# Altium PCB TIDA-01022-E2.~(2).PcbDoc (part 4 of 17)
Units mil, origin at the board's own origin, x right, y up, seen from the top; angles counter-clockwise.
Board outline 6929.13 x 11614.17 mil, 12 copper layers (L1_Top Layer, L2_GND, L3_GND, L4_Signal Layer 1, L5_GND, L6_PWR, L7_GND/PWR, L8_PWR, L9_GND/PWR, L10_Signal Layer 2, L11_GND, L12_Bottom Layer), stack 64.6 mil thick; 1711 components, 1001 nets, 5985 pads, 3200 vias.

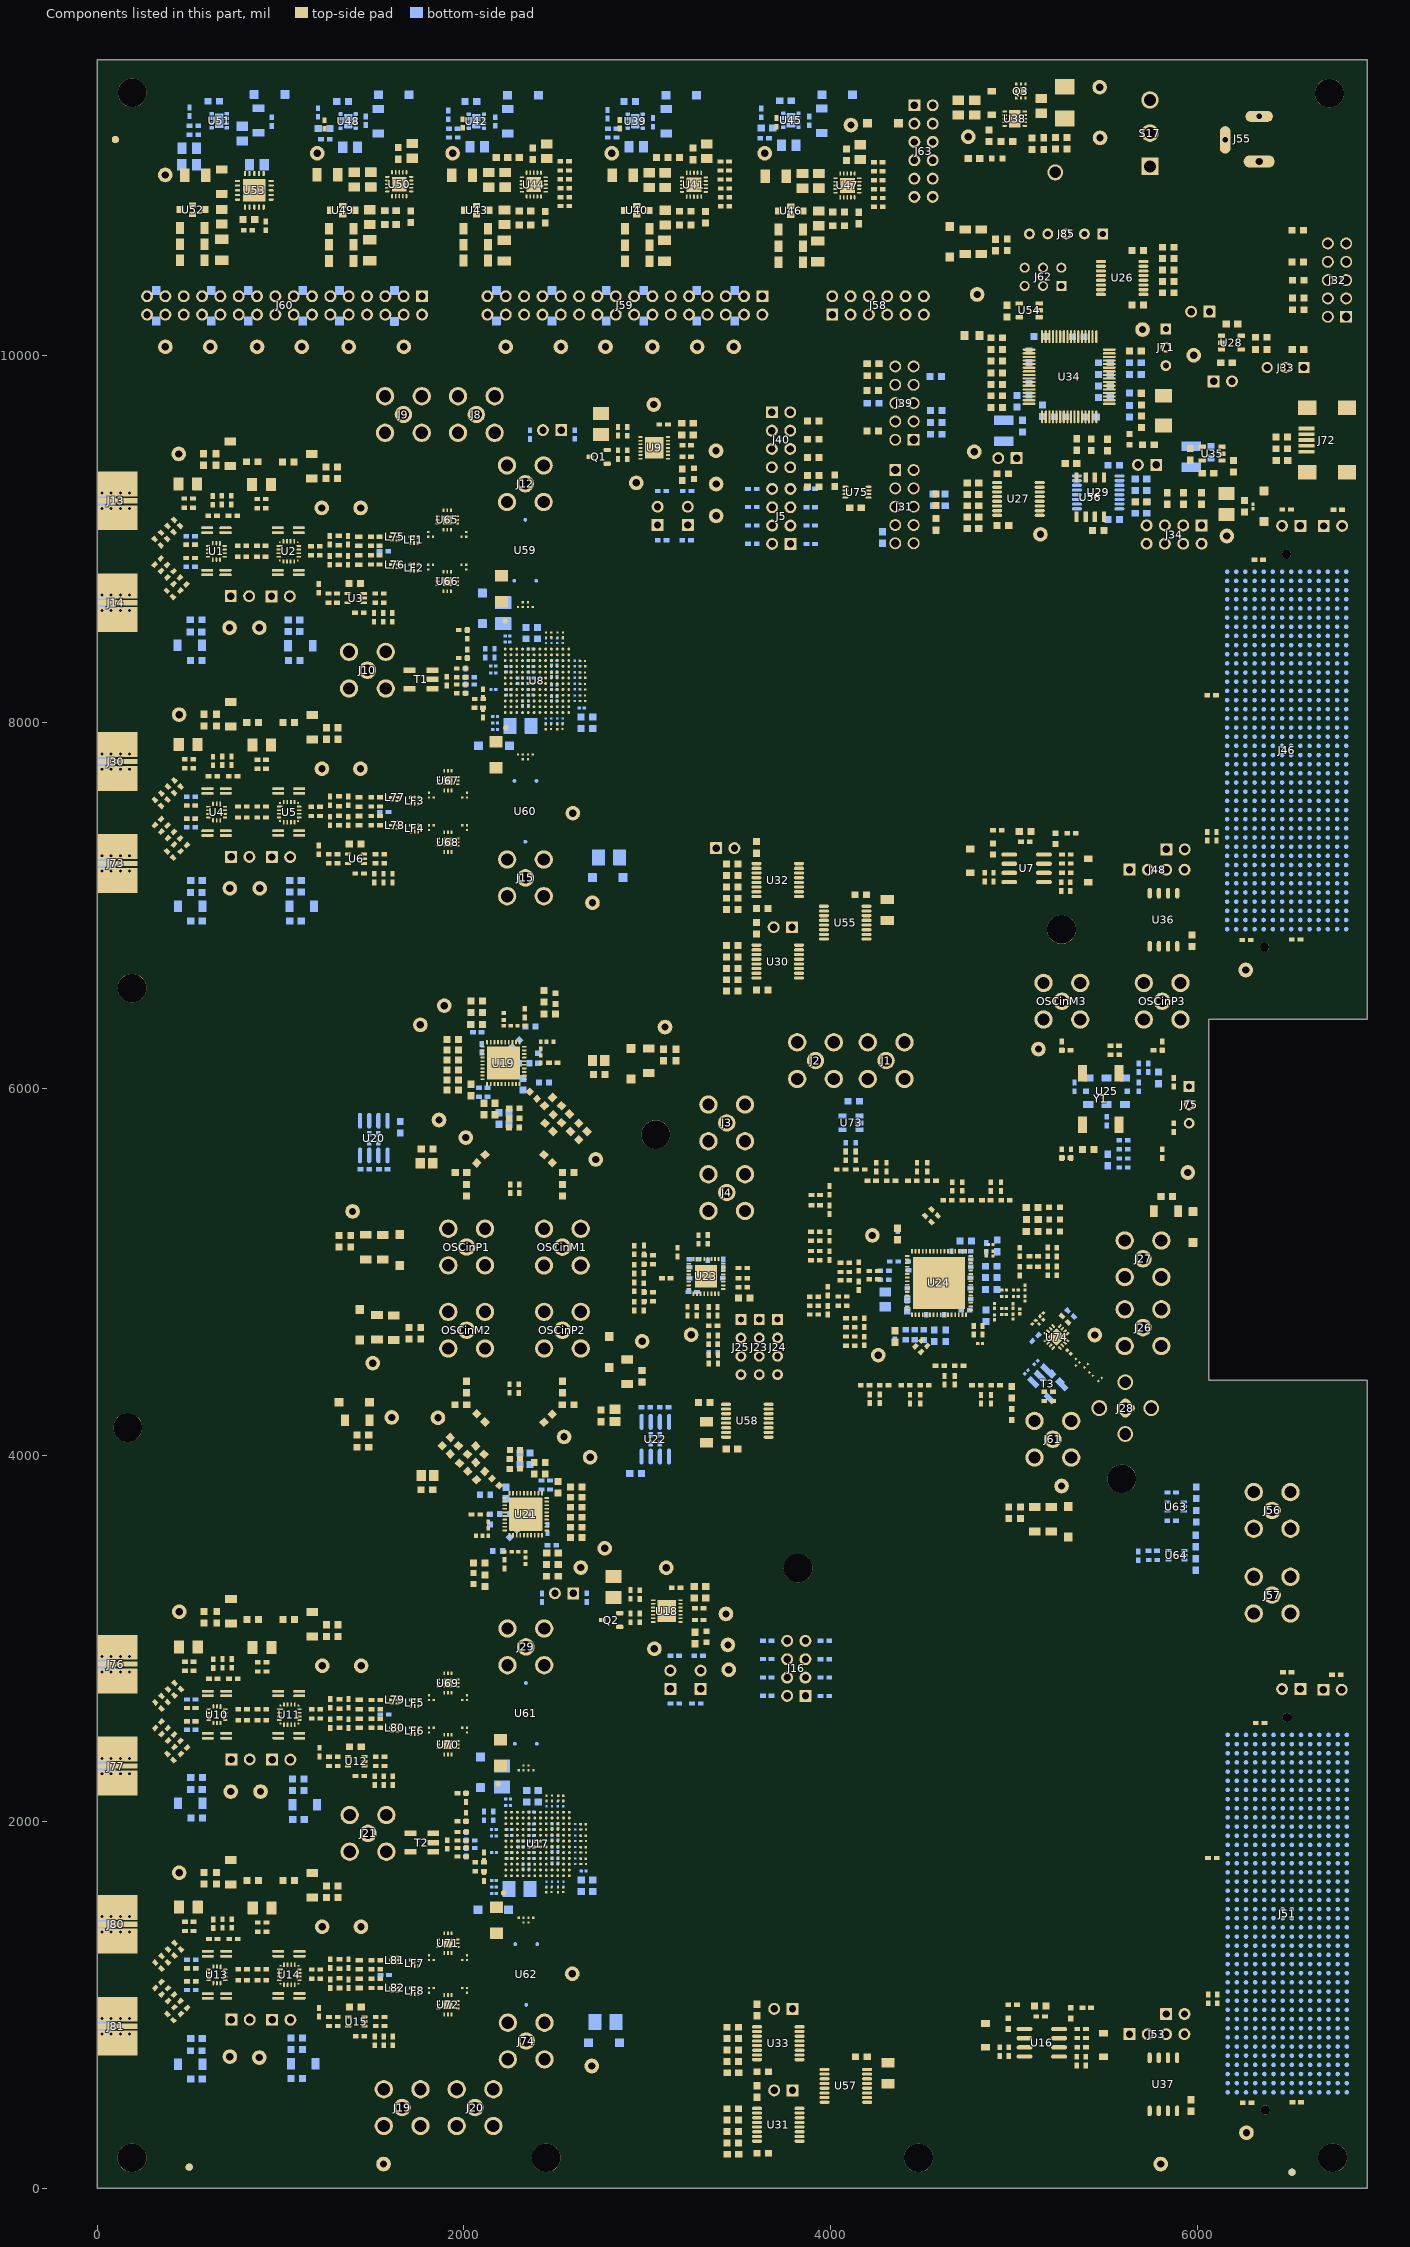
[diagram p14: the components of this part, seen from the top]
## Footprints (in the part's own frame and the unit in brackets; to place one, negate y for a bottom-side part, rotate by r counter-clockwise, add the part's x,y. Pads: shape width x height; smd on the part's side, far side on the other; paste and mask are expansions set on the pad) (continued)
ASP-184330-01#2 [mil]
  round 25 smd paste+5 mask+2: A1(975,225) A2(925,225) A3(875,225) A4(825,225) A5(775,225) A6(725,225) A7(675,225) A8(625,225) A9(575,225) A10(525,225) A11(475,225) A12(425,225) A13(375,225) A14(325,225) A15(275,225) A16(225,225) A17(175,225) A18(125,225) A19(75,225) A20(25,225) A21(-25,225) A22(-75,225) A23(-125,225) A24(-175,225) A25(-225,225) A26(-275,225) A27(-325,225) A28(-375,225) A29(-425,225) A30(-475,225) A31(-525,225) A32(-575,225) A33(-625,225) A34(-675,225) A35(-725,225) A36(-775,225) A37(-825,225) A38(-875,225) A39(-925,225) A40(-975,225) B1(975,175) B2(925,175) B3(875,175) B4(825,175) B5(775,175) B6(725,175) B7(675,175) B8(625,175) B9(575,175) B10(525,175) B11(475,175) B12(425,175) B13(375,175) B14(325,175) B15(275,175) B16(225,175) B17(175,175) B18(125,175) B19(75,175) B20(25,175) B21(-25,175) B22(-75,175) B23(-125,175) B24(-175,175) B25(-225,175) B26(-275,175) B27(-325,175) B28(-375,175) B29(-425,175) B30(-475,175) B31(-525,175) B32(-575,175) B33(-625,175) B34(-675,175) B35(-725,175) B36(-775,175) B37(-825,175) B38(-875,175) B39(-925,175) B40(-975,175) C1(975,125) C2(925,125) C3(875,125) C4(825,125) C5(775,125) C6(725,125) C7(675,125) C8(625,125) C9(575,125) C10(525,125) C11(475,125) C12(425,125) C13(375,125) C14(325,125) C15(275,125) C16(225,125) C17(175,125) C18(125,125) C19(75,125) C20(25,125) C21(-25,125) C22(-75,125) C23(-125,125) C24(-175,125) C25(-225,125) C26(-275,125) C27(-325,125) C28(-375,125) C29(-425,125) C30(-475,125) C31(-525,125) C32(-575,125) C33(-625,125) C34(-675,125) C35(-725,125) C36(-775,125) C37(-825,125) C38(-875,125) C39(-925,125) C40(-975,125) D1(975,75) D2(925,75) D3(875,75) D4(825,75) D5(775,75) D6(725,75) D7(675,75) D8(625,75) D9(575,75) D10(525,75) D11(475,75) D12(425,75) D13(375,75) D14(325,75) D15(275,75) D16(225,75) D17(175,75) D18(125,75) D19(75,75) D20(25,75) D21(-25,75) D22(-75,75) D23(-125,75) D24(-175,75) D25(-225,75) D26(-275,75) D27(-325,75) D28(-375,75) D29(-425,75) D30(-475,75) D31(-525,75) D32(-575,75) D33(-625,75) D34(-675,75) D35(-725,75) D36(-775,75) D37(-825,75) D38(-875,75) D39(-925,75) D40(-975,75) E1(975,25) E2(925,25) E3(875,25) E4(825,25) E5(775,25) E6(725,25) E7(675,25) E8(625,25) E9(575,25) E10(525,25) E11(475,25) E12(425,25) E13(375,25) E14(325,25) E15(275,25) E16(225,25) E17(175,25) E18(125,25) E19(75,25) E20(25,25) E21(-25,25) E22(-75,25) E23(-125,25) E24(-175,25) E25(-225,25) E26(-275,25) E27(-325,25) E28(-375,25) E29(-425,25) E30(-475,25) E31(-525,25) E32(-575,25) E33(-625,25) E34(-675,25) E35(-725,25) E36(-775,25) E37(-825,25) E38(-875,25) E39(-925,25) E40(-975,25) F1(975,-25) F2(925,-25) F3(875,-25) F4(825,-25) F5(775,-25) F6(725,-25) F7(675,-25) F8(625,-25) F9(575,-25) F10(525,-25) F11(475,-25) F12(425,-25) F13(375,-25) F14(325,-25) F15(275,-25) F16(225,-25) F17(175,-25) F18(125,-25) F19(75,-25) F20(25,-25) F21(-25,-25) F22(-75,-25) F23(-125,-25) F24(-175,-25) F25(-225,-25) F26(-275,-25) F27(-325,-25) F28(-375,-25) F29(-425,-25) F30(-475,-25) F31(-525,-25) F32(-575,-25) F33(-625,-25) F34(-675,-25) F35(-725,-25) F36(-775,-25) F37(-825,-25) F38(-875,-25) F39(-925,-25) F40(-975,-25) G1(975,-75) G2(925,-75) G3(875,-75) G4(825,-75) G5(775,-75) G6(725,-75) G7(675,-75) G8(625,-75) G9(575,-75) G10(525,-75) G11(475,-75) G12(425,-75) G13(375,-75) G14(325,-75) G15(275,-75) G16(225,-75) G17(175,-75) G18(125,-75) G19(75,-75) G20(25,-75) G21(-25,-75) G22(-75,-75) G23(-125,-75) G24(-175,-75) G25(-225,-75) G26(-275,-75) G27(-325,-75) G28(-375,-75) G29(-425,-75) G30(-475,-75) G31(-525,-75) G32(-575,-75) G33(-625,-75) G34(-675,-75) G35(-725,-75) G36(-775,-75) G37(-825,-75) G38(-875,-75) G39(-925,-75) G40(-975,-75) H1(975,-125) H2(925,-125) H3(875,-125) H4(825,-125) H5(775,-125) H6(725,-125) H7(675,-125) H8(625,-125) H9(575,-125) H10(525,-125) H11(475,-125) H12(425,-125) H13(375,-125) H14(325,-125) H15(275,-125) H16(225,-125) H17(175,-125) H18(125,-125) H19(75,-125) H20(25,-125) H21(-25,-125) H22(-75,-125) H23(-125,-125) H24(-175,-125) H25(-225,-125) H26(-275,-125) H27(-325,-125) H28(-375,-125) H29(-425,-125) H30(-475,-125) H31(-525,-125) H32(-575,-125) H33(-625,-125) H34(-675,-125) H35(-725,-125) H36(-775,-125) H37(-825,-125) H38(-875,-125) H39(-925,-125) H40(-975,-125) J1(975,-175) J2(925,-175) J3(875,-175) J4(825,-175) J5(775,-175) J6(725,-175) J7(675,-175) J8(625,-175) J9(575,-175) J10(525,-175) J11(475,-175) J12(425,-175) J13(375,-175) J14(325,-175) J15(275,-175) J16(225,-175) J17(175,-175) J18(125,-175) J19(75,-175) J20(25,-175) J21(-25,-175) J22(-75,-175) J23(-125,-175) J24(-175,-175) J25(-225,-175) J26(-275,-175) J27(-325,-175) J28(-375,-175) J29(-425,-175) J30(-475,-175) J31(-525,-175) J32(-575,-175) J33(-625,-175) J34(-675,-175) J35(-725,-175) J36(-775,-175) J37(-825,-175) J38(-875,-175) J39(-925,-175) J40(-975,-175) K1(975,-225) K2(925,-225) K3(875,-225) K4(825,-225) K5(775,-225) K6(725,-225) K7(675,-225) K8(625,-225) K9(575,-225) K10(525,-225) K11(475,-225) K12(425,-225) K13(375,-225) K14(325,-225) K15(275,-225) K16(225,-225) K17(175,-225) K18(125,-225) K19(75,-225) K20(25,-225) K21(-25,-225) K22(-75,-225) K23(-125,-225) K24(-175,-225) K25(-225,-225) K26(-275,-225) K27(-325,-225) K28(-375,-225) K29(-425,-225) K30(-475,-225) K31(-525,-225) K32(-575,-225) K33(-625,-225) K34(-675,-225) K35(-725,-225) K36(-775,-225) K37(-825,-225) K38(-875,-225) K39(-925,-225) K40(-975,-225) L1(975,-275) L2(925,-275) L3(875,-275) L4(825,-275) L5(775,-275) L6(725,-275) L7(675,-275) L8(625,-275) L9(575,-275) L10(525,-275) L11(475,-275) L12(425,-275) L13(375,-275) L14(325,-275) L15(275,-275) L16(225,-275) L17(175,-275) L18(125,-275) L19(75,-275) L20(25,-275) L21(-25,-275) L22(-75,-275) L23(-125,-275) L24(-175,-275) L25(-225,-275) L26(-275,-275) L27(-325,-275) L28(-375,-275) L29(-425,-275) L30(-475,-275) L31(-525,-275) L32(-575,-275) L33(-625,-275) L34(-675,-275) L35(-725,-275) L36(-775,-275) L37(-825,-275) L38(-875,-275) L39(-925,-275) L40(-975,-275) M1(975,-325) M2(925,-325) M3(875,-325) M4(825,-325) M5(775,-325) M6(725,-325) M7(675,-325) M8(625,-325) M9(575,-325) M10(525,-325) M11(475,-325) M12(425,-325) M13(375,-325) M14(325,-325) M15(275,-325) M16(225,-325) M17(175,-325) M18(125,-325) M19(75,-325) M20(25,-325) M21(-25,-325) M22(-75,-325) M23(-125,-325) M24(-175,-325) M25(-225,-325) M26(-275,-325) M27(-325,-325) M28(-375,-325) M29(-425,-325) M30(-475,-325) M31(-525,-325) M32(-575,-325) M33(-625,-325) M34(-675,-325) M35(-725,-325) M36(-775,-325) M37(-825,-325) M38(-875,-325) M39(-925,-325) M40(-975,-325) Y1(975,325) Y2(925,325) Y3(875,325) Y4(825,325) Y5(775,325) Y6(725,325) Y7(675,325) Y8(625,325) Y9(575,325) Y10(525,325) Y11(475,325) Y12(425,325) Y13(375,325) Y14(325,325) Y15(275,325) Y16(225,325) Y17(175,325) Y18(125,325) Y19(75,325) Y20(25,325) Y21(-25,325) Y22(-75,325) Y23(-125,325) Y24(-175,325) Y25(-225,325) Y26(-275,325) Y27(-325,325) Y28(-375,325) Y29(-425,325) Y30(-475,325) Y31(-525,325) Y32(-575,325) Y33(-625,325) Y34(-675,325) Y35(-725,325) Y36(-775,325) Y37(-825,325) Y38(-875,325) Y39(-925,325) Y40(-975,325) Z1(975,275) Z2(925,275) Z3(875,275) Z4(825,275) Z5(775,275) Z6(725,275) Z7(675,275) Z8(625,275) Z9(575,275) Z10(525,275) Z11(475,275) Z12(425,275) Z13(375,275) Z14(325,275) Z15(275,275) Z16(225,275) Z17(175,275) Z18(125,275) Z19(75,275) Z20(25,275) Z21(-25,275) Z22(-75,275) Z23(-125,275) Z24(-175,275) Z25(-225,275) Z26(-275,275) Z27(-325,275) Z28(-375,275) Z29(-425,275) Z30(-475,275) Z31(-525,275) Z32(-575,275) Z33(-625,275) Z34(-675,275) Z35(-725,275) Z36(-775,275) Z37(-825,275) Z38(-875,275) Z39(-925,275) Z40(-975,275)
  round 50 hole 50 unplated paste+0 mask+10: MH1(1070.5,0)
  round 50 hole 50 unplated mask+10: MH2(-1070.5,-120)
  silkscreen extent -1118,-409 1153,409
AssemblyNote [mil] "Assembly Note"
AssemblyNoteLabel [mil] "Assembly Note for PCB Labels"
CONN_PEC06DAAN [mm] "SULLINS"
  rect 1.65x1.65 hole 1.016 mask+0: 1(-6.35,-1.27)
  round 1.65 hole 1.016 mask+0: 2(-6.35,1.27) 3(-3.81,-1.27) 4(-3.81,1.27) 5(-1.27,-1.27) 6(-1.27,1.27) 7(1.27,-1.27) 8(1.27,1.27) 9(3.81,-1.27) 10(3.81,1.27) 11(6.35,-1.27) 12(6.35,1.27)
  silkscreen extent -8.72,-2.6 7.62,2.54, body extent -7.62,-2.54 7.62,2.54, height 8.38
CONN_RAPC722X [mm] "Conn_DC Jack"
  oval 1.7x4.3 hole 1.01 slot 3.56 at 90 deg mask+0.254: 1(-13.741,0)
  oval 1.5x3.8 hole 0.76 slot 3.05 at 90 deg mask+0.254: 2(-7.493,0)
  oval 3.8x1.5 hole 0.76 slot 3.05 at 0 deg mask+0.254: 3(-10.744,4.7)
  silkscreen extent -14.48,-4.57 0.25,4.57, body extent -14.5,-4.57 0.23,4.83, height 11.18
DBV0005A_N [mm] "SOT23, 5-Leads, Body 2.9x1.6mm, Pitch 0.95mm, Lead Span 2.8mm, IPC Medium Density"
  rrect17% 1x0.6 smd: 1(-1.375,0.95) 2(-1.375,0) 3(-1.375,-0.95) 4(1.375,-0.95) 5(1.375,0.95)
  silkscreen extent -1.62,-1.55 0.38,1.55, body extent -1.42,-1.46 1.42,1.46, height 1.09
DCK0005A_N#1 [mm] "SOT353, 5-Leads, Body 2x1.3mm, Pitch 0.65mm, Lead Span 2.1mm, IPC Medium Density"
  rrect25% 0.85x0.4 smd: 1(10.178,0.65) 2(10.178,0) 3(10.178,-0.65) 4(12.428,-0.65) 5(12.428,0.65)
  silkscreen extent 9.83,-1.02 11.85,1.1, body extent 10.16,-1 12.44,1, height 0.95
DCK0005A_N#2 [mm] "SOT353, 5-Leads, Body 2x1.3mm, Pitch 0.65mm, Lead Span 2.1mm, IPC Medium Density"
  rrect25% 0.85x0.4 smd: 1(-1.125,0.65) 2(-1.125,0) 3(-1.125,-0.65) 4(1.125,-0.65) 5(1.125,0.65)
  silkscreen extent -1.48,-1.02 0.55,1.1, body extent -1.14,-1 1.14,1, height 0.95
DCU0008A_N [mm] "TSSOP, 8-Leads, Body 2x2.3mm, Pitch 0.5mm, IPC Medium Density"
  oval 0.8x0.3 smd: 1(-1.6,0.75) 2(-1.6,0.25) 3(-1.6,-0.25) 4(-1.6,-0.75) 5(1.6,-0.75) 6(1.6,-0.25) 7(1.6,0.25) 8(1.6,0.75)
  silkscreen extent -1.05,-1.05 0.38,1.05, body extent -1.56,-1 1.56,1, height 0.9
DQ1225 [mm] "SMD, 12-Leads, Body 3x3mm"
  rect 0.51x0.25 smd: 1(-1.36,0.51) 2(-1.36,0) 3(-1.36,-0.51) 7(1.36,-0.51) 8(1.36,0) 9(1.36,0.51)
  rect 0.25x0.51 smd: 4(-0.51,-1.36) 5(0,-1.36) 6(0.51,-1.36) 10(0.51,1.36) 11(0,1.36) 12(-0.51,1.36)
  rect 1.24x1.24 smd: 13(0,0)
  silkscreen extent -1.8,-1.6 1.6,1.6, body extent -1.5,-1.5 1.5,1.5, height 0.89
DQK0006C [mm] "WSON"
  rrect12% 0.9x0.86 on Top Paste: 0(0,0.325)
  rrect34% 0.7x0.29 on Top Paste: 0(0.095,-0.65)
  rrect33% 0.45x0.3 smd: 1(-0.975,0.65) 2(-0.975,0) 3(-0.975,-0.65) 4(0.975,-0.65) 5(0.975,0) 6(0.975,0.65)
  rrect33% 0.75x0.3 smd paste-0.15: 7(0.095,-0.65)
  rrect11% 1x0.95 smd paste-0.5: 8(0,0.325)
  silkscreen extent -1.15,-1.15 1.15,1.15, body extent -1,-1 1,1, height 0.82
DRC0010J [mm] "SON, 10-Leads, Body 3x3mm, Pitch 0.5mm, Thermal Pad 2.4x1.65mm, TI Recommended"
  rrect40% 0.6x0.25 smd: 1(-1.4,1) 2(-1.4,0.5) 3(-1.4,0) 4(-1.4,-0.5) 5(-1.4,-1) 6(1.4,-1) 7(1.4,-0.5) 8(1.4,0) 9(1.4,0.5) 10(1.4,1)
  rrect40% 0.25x0.34 on Top Paste: 11(-0.25,1.53) 11(-0.25,-1.53) 11(0.25,1.53) 11(0.25,-1.53)
  rrect9% 1.5x1.06 on Top Paste: 11(0,0.63) 11(0,-0.63)
  rrect12% 1.65x2.4 smd paste-1 mask-2: 11(0,0)
  L1_Top Layer region: -0.775,-1.2 -0.375,-1.2 -0.375,-1.65 -0.371,-1.669 -0.36,-1.685 -0.344,-1.696 -0.325,-1.7 -0.325,-1.7 -0.325,-1.7 -0.175,-1.7 -0.175,-1.7 -0.156,-1.696 -0.14,-1.685 -0.129,-1.669 -0.125,-1.65 -0.125,-1.65 -0.125,-1.65 -0.125,-1.2 0.125,-1.2 0.125,-1.65 0.129,-1.669 0.14,-1.685 0.156,-1.696 0.175,-1.7 0.175,-1.7 0.175,-1.7 0.325,-1.7 0.325,-1.7 0.344,-1.696 0.36,-1.685 0.371,-1.669 0.375,-1.65 0.375,-1.65 0.375,-1.2 0.775,-1.2 0.794,-1.196 0.81,-1.185 0.821,-1.169 0.825,-1.15 0.825,-1.15 0.825,1.15 0.821,1.169 0.81,1.185 0.794,1.196 0.775,1.2 0.775,1.2 0.375,1.2 0.375,1.65 0.371,1.669 0.36,1.685 0.344,1.696 0.325,1.7 0.325,1.7 0.175,1.7 0.156,1.696 0.14,1.685 0.129,1.669 0.125,1.65 0.125,1.65 0.125,1.2 -0.125,1.2 -0.125,1.65 -0.125,1.65 -0.129,1.669 -0.14,1.685 -0.156,1.696 -0.175,1.7 -0.175,1.7 -0.325,1.7 -0.344,1.696 -0.36,1.685 -0.371,1.669 -0.375,1.65 -0.375,1.65 -0.375,1.2 -0.775,1.2 -0.794,1.196 -0.81,1.185 -0.821,1.169 -0.825,1.15 -0.825,1.15 -0.825,-1.15 -0.821,-1.169 -0.81,-1.185 -0.794,-1.196 -0.775,-1.2
  silkscreen extent -1.63,-1.63 1.63,1.63, body extent -1.5,-1.5 1.5,1.5, height 0.77
ESD_Overlay_Large [mil]
  silkscreen extent -254,-219 250,219
EURoHS_Exempt_60mil [mil] "EU RoHS Exempt symbol"
FCC_disclaimer [mil]
Fiducial10-20 [mm]
  round 1 smd mask+0.5: 1(0,0)
  L1_Top Layer keep-out circle w1.178: c0,0 r0.5
FIL_LFL18_TC1 [mm] "SMD, 6-Leads, Body 1.6x0.8mm"
  rrect40% 0.25x0.55 smd: 1(-0.5,0.425) 2(0,0.425) 3(0.5,0.425) 4(0.5,-0.425) 5(0,-0.425) 6(-0.5,-0.425)
  silkscreen extent -1.1,-1 1.1,1, body extent -0.85,-0.45 0.85,0.45, height 0.7
IEC_Caution_Medium [mil]
  silkscreen extent -217,-182 217,193
IND_LQG15H [mm] "MuRata"
  rect 0.55x0.6 smd: 1(-0.475,0) 2(0.475,0)
  silkscreen extent -1.3,-0.3 -0.95,0.3, body extent -0.52,-0.27 0.52,0.27, height 0.55
Johnson_142-0701-20x [mil] "Johnson Components recommended land pattern"
  round 95 hole 62: 1(0,0)
  round 100 hole 67: 2(100,100) 3(100,-100) 4(-100,-100) 5(-100,100)
  silkscreen extent -160,-160 160,160, body extent -156,-156 156,156, height 375
JOHNSON_142-0701-20X [mil] "Johnson Components recommended land pattern"
  round 95 hole 62: 1(0,0)
  round 100 hole 67: 2(100,100) 3(100,-100) 4(-100,-100) 5(-100,100)
  silkscreen extent -160,-160 160,160, body extent -156,-156 156,156, height 375
JOHNSON_142-0771-831 [mil]
  rect 28.5x218 smd: 1(0,-109)
  rect 135.75x218 smd: 2(-92.12,-109) 3(92.13,-109)
  rect 270x97.5 smd far side: 4(0,-48.75)
  round 16 hole 16: ""(-42,-25) ""(-42,-125) ""(-42,-75) ""(-42,-175) ""(42,-25) ""(42,-125) ""(42,-75) ""(42,-175)
  body extent -124,-179 123,375, height 131
Keystone5000 [mil] "For Keystone 500x miniature loop terminals"
  round 80 hole 40: 1(0,0)
  silkscreen extent -52,-52 52,52, body extent -49,-49 49,49, height 182
Keystone5001 [mil] "For Keystone 500x miniature loop terminals"
  round 80 hole 40: 1(0,0)
  silkscreen extent -52,-52 52,52, body extent -49,-49 49,49, height 182
Keystone5002 [mil] "For Keystone 500x miniature loop terminals"
  round 80 hole 40: 1(0,0)
  silkscreen extent -52,-52 52,52, body extent -49,-49 49,49, height 182
Keystone5012 [mil] "Keystone Multipurpose loops"
  round 87 hole 63: 1(0,0)
  silkscreen extent -70,-70 70,70, body extent -63,-63 63,62, height 319
Label_650x200 [mil] "Thermal Transfer Label"
  round 1 on Mech13: 0(0,0)
  silkscreen extent -325,-100 325,100, body extent -325,-100 325,100, height 1
LED_LTST-C190 [mm] "Lite-On"
  rect 0.8x0.8 smd: 1(-0.75,0) 2(0.75,0)
  silkscreen extent -1.1,-0.8 1.8,0.8, body extent -0.85,-0.45 0.85,0.45, height 0.9
LQFP64_N [mm] "Thin QFP, 64-Leads, Body 10x10mm, Pitch 0.5mm, IPC Medium Density"
  oval 1.8x0.3 smd: 1(-5.55,3.75) 2(-5.55,3.25) 3(-5.55,2.75) 4(-5.55,2.25) 5(-5.55,1.75) 6(-5.55,1.25) 7(-5.55,0.75) 8(-5.55,0.25) 9(-5.55,-0.25) 10(-5.55,-0.75) 11(-5.55,-1.25) 12(-5.55,-1.75) 13(-5.55,-2.25) 14(-5.55,-2.75) 15(-5.55,-3.25) 16(-5.55,-3.75) 33(5.55,-3.75) 34(5.55,-3.25) 35(5.55,-2.75) 36(5.55,-2.25) 37(5.55,-1.75) 38(5.55,-1.25) 39(5.55,-0.75) 40(5.55,-0.25) 41(5.55,0.25) 42(5.55,0.75) 43(5.55,1.25) 44(5.55,1.75) 45(5.55,2.25) 46(5.55,2.75) 47(5.55,3.25) 48(5.55,3.75)
  oval 0.3x1.8 smd: 17(-3.75,-5.55) 18(-3.25,-5.55) 19(-2.75,-5.55) 20(-2.25,-5.55) 21(-1.75,-5.55) 22(-1.25,-5.55) 23(-0.75,-5.55) 24(-0.25,-5.55) 25(0.25,-5.55) 26(0.75,-5.55) 27(1.25,-5.55) 28(1.75,-5.55) 29(2.25,-5.55) 30(2.75,-5.55) 31(3.25,-5.55) 32(3.75,-5.55) 49(3.75,5.55) 50(3.25,5.55) 51(2.75,5.55) 52(2.25,5.55) 53(1.75,5.55) 54(1.25,5.55) 55(0.75,5.55) 56(0.25,5.55) 57(-0.25,5.55) 58(-0.75,5.55) 59(-1.25,5.55) 60(-1.75,5.55) 61(-2.25,5.55) 62(-2.75,5.55) 63(-3.25,5.55) 64(-3.75,5.55)
  silkscreen extent -5.68,-4.25 4.25,4.57, body extent -5,-5 5,5, height 1.6
LQW18A [mm] "Murata"
  rect 0.625x0.85 smd: 1(-0.663,0) 2(0.663,0)
  silkscreen extent -0.13,-0.5 0.13,0.5, body extent -0.9,-0.5 0.9,0.5, height 1
LTST-C191_Green [mm] "Lite-On"
  rect 0.8x0.8 smd: 1(-0.75,0) 2(0.75,0)
  silkscreen extent -1.1,-0.8 1.8,0.8, body extent -0.85,-0.45 0.85,0.45, height 0.65
M08A_N [mm] "SOIC, 8-Leads, Body 4.9x3.9mm, Pitch 1.27mm, IPC Medium Density"
  oval 2.2x0.6 smd: 1(-2.4,1.905) 2(-2.4,0.635) 3(-2.4,-0.635) 4(-2.4,-1.905) 5(2.4,-1.905) 6(2.4,-0.635) 7(2.4,0.635) 8(2.4,1.905)
  silkscreen extent -2.52,-2.5 0.9,2.88, body extent -2,-2.5 2,2.5, height 1.75
MARKI_BAL-0006SMG [mil] "SMD, 3-Leads, Body 320x320mil"
  round 21 smd: 1(0,166) 2(60,-166) 3(-60,-166)
  L1_Top Layer region: -100,-180 -100,-115 -15,-115 -15,-180 10,-180 10,-115 110.01,-115.01 109.99,-180 180,-180 180,180 50,180 50,125 -50,125 -50,180 -180,180 -180,-180
  body extent -160,-160 160,160, height 155
MF05A_N [mm] "SOT23, 5-Leads, Body 2.9x1.6mm, Pitch 0.95mm, Lead Span 2.8mm, IPC Medium Density"
  rect 1.1x0.65 smd: 1(-1.2,0.95) 2(-1.2,0) 3(-1.2,-0.95) 4(1.2,-0.95) 5(1.2,0.95)
  silkscreen extent -1.32,-1.55 0.25,1.95, body extent -0.9,-1.55 0.9,1.55, height 1.19
Mill-Max_800-10-003-10-001000 [mm] "Mill-Max"
  rect 1.5x1.5 hole 0.85: 1(-2.54,0)
  round 1.5 hole 0.85: 2(0,0) 3(2.54,0)
  silkscreen extent -3.81,-1.27 3.81,1.78, body extent -3.81,-1.27 3.81,1.27, height 8.13
Mill-Max_800-10-004-10-001000 [mm] "Mill-Max"
  rect 1.5x1.5 hole 0.85: 1(-3.81,0)
  round 1.5 hole 0.85: 2(-1.27,0) 3(1.27,0) 4(3.81,0)
  silkscreen extent -5.75,-1.27 5.08,1.27, body extent -5.08,-1.27 5.08,1.27, height 8.13
Mill-Max_800-10-005-10-001000 [mm] "Mill-Max"
  rect 1.5x1.5 hole 0.85: 1(-5.08,0)
  round 1.5 hole 0.85: 2(-2.54,0) 3(0,0) 4(2.54,0) 5(5.08,0)
  silkscreen extent -6.35,-1.27 6.35,1.78, body extent -6.35,-1.27 6.35,1.27, height 8.13
Mill-Max_802-10-006-10-001000 [mm] "Header, 2.54 mm, 3x2, TH"
  rect 1.4x1.4 hole 0.9: 1(-2.54,1.27)
  round 1.4 hole 0.9: 2(-2.54,-1.27) 3(0,1.27) 4(0,-1.27) 5(2.54,1.27) 6(2.54,-1.27)
  silkscreen extent -4.21,-2.54 3.81,2.54, body extent -3.85,-2.54 3.77,2.54, height 8.11
MNC_AT1521 [mm] "SMD, 5-leads, Body 3.81x3.81mm, Pitch 1.27mm"
  rect 0.76x1.65 smd: 1(-1.27,1.59) 2(0,1.59) 3(1.27,1.59) 4(1.27,-1.59) 6(-1.27,-1.59)
  silkscreen extent -1.91,-1.91 1.91,3.09, body extent -1.91,-1.91 1.91,1.91, height 4.07
Murata_NFM31P#1 [mm] "SMD, 3-Leads, Body 3.2x1.6mm"
  rect 0.95x1 smd paste-2 mask-2: 1(-1.725,0) 3(1.725,0)
  rect 1x0.7 smd paste-2 mask+0: 2(0,-0.65) 2(0,0.65)
  silkscreen extent -2.59,-1.2 2.59,1.2, body extent -1.7,-0.9 1.7,0.9, height 1.5
Murata_NFM31P#2 [mm] "SMD, 3-Leads, Body 3.2x1.6mm"
  rect 0.95x1 smd paste-2 mask-2: 1(-19.378,138.303) 3(-15.928,138.303)
  rect 1x0.7 smd paste-2 mask+0: 2(-17.653,137.653) 2(-17.653,138.953)
  silkscreen extent -20.24,137.1 -15.07,139.5, body extent -19.35,137.4 -15.95,139.2, height 1.5
NKD0064A [mm] "QFN, 64-Leads, Body 9x9mm, Pitch 0.5mm"
  rrect40% 0.6x0.25 smd: 1(-4.4,3.75) 2(-4.4,3.25) 3(-4.4,2.75) 4(-4.4,2.25) 5(-4.4,1.75) 6(-4.4,1.25) 7(-4.4,0.75) 8(-4.4,0.25) 9(-4.4,-0.25) 10(-4.4,-0.75) 11(-4.4,-1.25) 12(-4.4,-1.75) 13(-4.4,-2.25) 14(-4.4,-2.75) 15(-4.4,-3.25) 16(-4.4,-3.75) 33(4.4,-3.75) 34(4.4,-3.25) 35(4.4,-2.75) 36(4.4,-2.25) 37(4.4,-1.75) 38(4.4,-1.25) 39(4.4,-0.75) 40(4.4,-0.25) 41(4.4,0.25) 42(4.4,0.75) 43(4.4,1.25) 44(4.4,1.75) 45(4.4,2.25) 46(4.4,2.75) 47(4.4,3.25) 48(4.4,3.75)
  rrect40% 0.25x0.6 smd: 17(-3.75,-4.4) 18(-3.25,-4.4) 19(-2.75,-4.4) 20(-2.25,-4.4) 21(-1.75,-4.4) 22(-1.25,-4.4) 23(-0.75,-4.4) 24(-0.25,-4.4) 25(0.25,-4.4) 26(0.75,-4.4) 27(1.25,-4.4) 28(1.75,-4.4) 29(2.25,-4.4) 30(2.75,-4.4) 31(3.25,-4.4) 32(3.75,-4.4) 49(3.75,4.4) 50(3.25,4.4) 51(2.75,4.4) 52(2.25,4.4) 53(1.75,4.4) 54(1.25,4.4) 55(0.75,4.4) 56(0.25,4.4) 57(-0.25,4.4) 58(-0.75,4.4) 59(-1.25,4.4) 60(-1.75,4.4) 61(-2.25,4.4) 62(-2.75,4.4) 63(-3.25,4.4) 64(-3.75,4.4)
  rrect1% 7.2x7.2 smd paste-3.6: 65(0,0)
  silkscreen extent -4.65,-4.65 4.65,4.65, body extent -4.55,-4.55 4.55,4.55, height 0.81
OSC_CVHD-950-4 [mil] "Crystek recommended land pattern 2011-02-22 Rev H"
  rect 90x50 smd: 1(-140,100) 2(-140,-100) 3(140,-100) 4(140,100)
  silkscreen extent -200,-300 200,300, body extent -180,-280 180,280, height 209
Pb-Free_Overlay_Small [mil]
  silkscreen extent -46,-46 46,46
PROBE_POINT_30PAD [mil] "PROBE_POINT_30PAD"
  round 30 smd: 1(0,0)
  silkscreen extent -25,-25 25,25
PW0016A_N [mm] "TSOP, 16-Leads, Body 5x4.4mm, Pitch 0.65mm, IPC Medium Density"
  oval 1.4x0.45 smd: 1(-2.95,2.275) 2(-2.95,1.625) 3(-2.95,0.975) 4(-2.95,0.325) 5(-2.95,-0.325) 6(-2.95,-0.975) 7(-2.95,-1.625) 8(-2.95,-2.275) 9(2.95,-2.275) 10(2.95,-1.625) 11(2.95,-0.975) 12(2.95,-0.325) 13(2.95,0.325) 14(2.95,0.975) 15(2.95,1.625) 16(2.95,2.275)
  silkscreen extent -3.5,-2.55 1.85,2.75, body extent -3.21,-2.5 3.21,2.5, height 1
QFN16-3x3MM_0_5 [mm] "QFN, 16-Leads, Body 3x3mm, Pitch 0.5mm"
  rrect100% 0.6x0.3 smd: 1(-1.4,0.75) 2(-1.4,0.25) 3(-1.4,-0.25) 4(-1.4,-0.75) 9(1.4,-0.75) 10(1.4,-0.25) 11(1.4,0.25) 12(1.4,0.75)
  rrect100% 0.3x0.6 smd: 5(-0.75,-1.4) 6(-0.25,-1.4) 7(0.25,-1.4) 8(0.75,-1.4) 13(0.75,1.4) 14(0.25,1.4) 15(-0.25,1.4) 16(-0.75,1.4)
  rrect6% 1.7x1.7 smd paste-2: 17(0,0)
  silkscreen extent -1.6,-1.6 1.6,1.6, body extent -1.5,-1.5 1.5,1.5, height 1.01
RGR0020A [mm] "QFN, 20-Leads, Body 3.5x3.5mm, Pitch 0.5mm, Thermal Pad 2.05x2.05mm, TI Recommended"
  oval 0.6x0.24 smd: 1(-1.65,1) 2(-1.65,0.5) 3(-1.65,0) 4(-1.65,-0.5) 5(-1.65,-1) 11(1.65,-1) 12(1.65,-0.5) 13(1.65,0) 14(1.65,0.5) 15(1.65,1)
  oval 0.24x0.6 smd: 6(-1,-1.65) 7(-0.5,-1.65) 8(0,-1.65) 9(0.5,-1.65) 10(1,-1.65) 16(1,1.65) 17(0.5,1.65) 18(0,1.65) 19(-0.5,1.65) 20(-1,1.65)
  rect 2.05x2.05 smd paste-1.025: 21(0,0)
  silkscreen extent -1.97,-1.98 1.97,1.97, body extent -1.83,-1.83 1.83,1.83, height 1.01
RGW0020A [mm] "QFN, 20-Leads, Body 5x5mm, Pitch 0.65mm, Thermal Pad 3.15x3.15mm, TI Recommended"
  oval 0.75x0.3 smd: 1(-2.325,1.3) 2(-2.325,0.65) 3(-2.325,0) 4(-2.325,-0.65) 5(-2.325,-1.3) 11(2.325,-1.3) 12(2.325,-0.65) 13(2.325,0) 14(2.325,0.65) 15(2.325,1.3)
  oval 0.3x0.75 smd: 6(-1.3,-2.325) 7(-0.65,-2.325) 8(0,-2.325) 9(0.65,-2.325) 10(1.3,-2.325) 16(1.3,2.325) 17(0.65,2.325) 18(0,2.325) 19(-0.65,2.325) 20(-1.3,2.325)
  rect 3.15x3.15 smd paste-1.575: 21(0,0)
  silkscreen extent -2.73,-2.73 2.73,2.73, body extent -2.58,-2.57 2.57,2.58, height 1.01
RHA0040A [mm] "QFN, 40-Leads, Body 6x6mm, Pitch 0.5mm, Thermal Pad 4.6x4.6mm, TI Recommended"
  rrect40% 0.6x0.25 smd: 1(-2.9,2.25) 2(-2.9,1.75) 3(-2.9,1.25) 4(-2.9,0.75) 5(-2.9,0.25) 6(-2.9,-0.25) 7(-2.9,-0.75) 8(-2.9,-1.25) 9(-2.9,-1.75) 10(-2.9,-2.25) 21(2.9,-2.25) 22(2.9,-1.75) 23(2.9,-1.25) 24(2.9,-0.75) 25(2.9,-0.25) 26(2.9,0.25) 27(2.9,0.75) 28(2.9,1.25) 29(2.9,1.75) 30(2.9,2.25)
  rrect40% 0.25x0.6 smd: 11(-2.25,-2.9) 12(-1.75,-2.9) 13(-1.25,-2.9) 14(-0.75,-2.9) 15(-0.25,-2.9) 16(0.25,-2.9) 17(0.75,-2.9) 18(1.25,-2.9) 19(1.75,-2.9) 20(2.25,-2.9) 31(2.25,2.9) 32(1.75,2.9) 33(1.25,2.9) 34(0.75,2.9) 35(0.25,2.9) 36(-0.25,2.9) 37(-0.75,2.9) 38(-1.25,2.9) 39(-1.75,2.9) 40(-2.25,2.9)
  rrect2% 4.6x4.6 smd paste-2.3: 41(0,0)
  silkscreen extent -3.2,-3.18 3.18,3.18, body extent -3,-3 3,3, height 1
RMS0014A [mm] "QFN, Body 2.6x2.6mm, Pitch 0.5mm"
  oval 0.7x0.25 smd: 1(-1.1,0.5)
  oval 0.6x0.25 smd: 2(-1.15,0) 3(-1.15,-0.5) 8(1.15,-0.5) 9(1.15,0) 10(1.15,0.5)
  oval 0.25x0.6 smd: 4(-0.75,-1.15) 5(-0.25,-1.15) 6(0.25,-1.15) 7(0.75,-1.15) 11(0.75,1.15) 12(0.25,1.15) 13(-0.25,1.15) 14(-0.75,1.15)
  silkscreen extent -1.4,-1.4 1.4,1.4, body extent -1.3,-1.3 1.3,1.3, height 0.61
RMZ0016A [mm] "QFN, 16-Leads, Body 3.0x3.0 mm, Pitch 0.5mm"
  rrect40% 0.8x0.25 smd paste+0 mask+0.07: 1(-1.3,0.75)
  rrect40% 0.6x0.25 smd paste+0 mask+0.07: 2(-1.4,0.25) 3(-1.4,-0.25) 4(-1.4,-0.75) 9(1.4,-0.75) 10(1.4,-0.25) 11(1.4,0.25) 12(1.4,0.75)
  rrect40% 0.25x0.6 smd paste+0 mask+0.07: 5(-0.75,-1.4) 6(-0.25,-1.4) 7(0.25,-1.4) 8(0.75,-1.4) 13(0.75,1.4) 14(0.25,1.4) 15(-0.25,1.4) 16(-0.75,1.4)
  rrect40% 0.25x0.25 smd paste+0 mask+0.07: ""(-1.25,-1.25) ""(-1.25,1.25) ""(1.25,-1.25) ""(1.25,1.25)
  silkscreen extent -1.7,-1.7 1.7,1.7, body extent -1.55,-1.55 1.55,1.55, height 0.66
Rosenberger_32K101-400L5 [mm] "SMA, 50 Ohm, TH"
  rrect50% 2.2x2.2 hole 1.6: 1(0,0)
  round 2.2 hole 1.6: 2(-2.54,2.54) 3(2.54,2.54) 4(2.54,-2.54) 5(-2.54,-2.54)
  silkscreen extent -3.18,-3.18 3.18,3.18, body extent -3.17,-3.17 3.18,3.18, height 9.51
RTV0032A [mm] "QFN, 32-Leads, Body 5x5mm, Pitch 0.5mm"
  rrect40% 0.6x0.25 smd: 1(-2.4,1.75) 2(-2.4,1.25) 3(-2.4,0.75) 4(-2.4,0.25) 5(-2.4,-0.25) 6(-2.4,-0.75) 7(-2.4,-1.25) 8(-2.4,-1.75) 17(2.4,-1.75) 18(2.4,-1.25) 19(2.4,-0.75) 20(2.4,-0.25) 21(2.4,0.25) 22(2.4,0.75) 23(2.4,1.25) 24(2.4,1.75)
  rrect40% 0.25x0.6 smd: 9(-1.75,-2.4) 10(-1.25,-2.4) 11(-0.75,-2.4) 12(-0.25,-2.4) 13(0.25,-2.4) 14(0.75,-2.4) 15(1.25,-2.4) 16(1.75,-2.4) 25(1.75,2.4) 26(1.25,2.4) 27(0.75,2.4) 28(0.25,2.4) 29(-0.25,2.4) 30(-0.75,2.4) 31(-1.25,2.4) 32(-1.75,2.4)
  rrect3% 3.1x3.1 smd paste-1.55: 33(0,0)
  silkscreen extent -2.7,-2.7 2.7,2.7, body extent -2.55,-2.55 2.55,2.55, height 0.81
Samtec_HTSW-103-09-x-S [mm] "Header, 3x1, 2.54mm, TH"
  rect 1.55x1.55 hole 1.02: 1(-2.54,0)
  round 1.55 hole 1.02: 2(0,0) 3(2.54,0)
  silkscreen extent -3.81,-1.24 3.81,1.5, body extent -3.81,-1.24 3.81,1.24, height 8.38
SDA14B [mm] "SON, 14-Leads, Body 4x4mm, Pitch 0.5mm, NSC Recommended"
  rect 0.6x0.25 smd paste-0.125 mask+0.051: 1(-1.9,1.5) 2(-1.9,1) 3(-1.9,0.5) 4(-1.9,0) 5(-1.9,-0.5) 6(-1.9,-1) 7(-1.9,-1.5) 8(1.9,-1.5) 9(1.9,-1) 10(1.9,-0.5) 11(1.9,0) 12(1.9,0.5) 13(1.9,1) 14(1.9,1.5)
  rect 2.6x3 smd paste-1.3 mask+0.051: 15(0,0)
  silkscreen extent -3.02,-2.2 2.35,2.3, body extent -2.05,-2.05 2.05,2.05, height 0.8
SIA0008B [mm] "SIP 8-Leads, Body 5x7mm"
  rrect17% 1x0.6 on Bottom Paste: 1(-1.85,2.14) 1(-1.85,2.94) 2(-1.85,-0.4) 2(-1.85,0.4) 3(-1.85,-2.94) 3(-1.85,-2.14) 4(1.85,-2.94) 4(1.85,-2.14) 5(1.85,-0.4) 5(1.85,0.4) 6(1.85,2.14) 6(1.85,2.94)
  rrect10% 1x1.4 smd paste-0.5: 1(-1.85,2.54) 2(-1.85,0) 3(-1.85,-2.54) 4(1.85,-2.54) 5(1.85,0) 6(1.85,2.54)
  rrect12% 0.8x0.8 smd: 7(0,2.865) 8(0,-2.865)
  silkscreen extent -2.64,-3.63 2.64,3.63, body extent -2.56,-3.56 2.56,3.56, height 1.13
SIL0008D_SMD#1 [mm] "SIP, 8-Leads, Body 2.8x3.0mm, Pitch 0.65mm, Thermal Pad 1.9x1.1mm"
  rrect12% 1.04x0.85 on Bottom Paste: 0(0,-0.525) 0(0,0.525)
  rrect40% 0.6x0.5 smd paste-0.05 mask-0.05: 1(-1.05,0.975) 2(-1.05,0.325) 3(-1.05,-0.325) 4(-1.05,-0.975) 5(1.05,-0.975) 6(1.05,-0.325) 7(1.05,0.325) 8(1.05,0.975)
  rrect17% 1.2x2 smd paste-0.6 mask-0.05: 9(0,0)
  silkscreen extent -1.53,-1.63 1.53,1.63, body extent -1.4,-1.5 1.4,1.5, height 1.53
SIL0008D_SMD#2 [mm] "SIP, 8-Leads, Body 2.8x3.0mm, Pitch 0.65mm, Thermal Pad 1.9x1.1mm"
  rrect50% 1.04x0.85 on Bottom Paste: 0(0,-0.525) 0(0,0.525)
  rrect40% 0.6x0.5 smd paste-0.05 mask-0.05: 1(-1.05,0.975) 2(-1.05,0.325) 3(-1.05,-0.325) 4(-1.05,-0.975) 5(1.05,-0.975) 6(1.05,-0.325) 7(1.05,0.325) 8(1.05,0.975)
  rrect17% 1.2x2 smd paste-0.6 mask-0.05: 9(0,0)
  silkscreen extent -1.53,-1.63 1.53,1.62, body extent -1.4,-1.5 1.4,1.5, height 1.53
SMB-Bi [mil] "Molded Diode, 2-Leads, Body 5.4x3.6mm, IPC Medium Density, based on OnSemi component dimensions"
  rect 85x107.99 smd: 1(-87.01,0) 2(87.01,0)
  silkscreen extent -125,-79 125,79, body extent -104,-73 104,73, height 89
SOD-123 [mm] "On Semi recommended land pattern"
  rect 0.915x1.22 smd: 1(-1.637,0) 2(1.637,0)
  silkscreen extent -2.74,-1.17 2.03,1.17, body extent -1.93,-0.9 1.93,0.9, height 1.35
SOIC127P800X216-8N [mm] "SOIC, 8-Leads, Body 5.3x5.3mm (max), Pitch 1.27mm, IPC Medium Density"
  oval 1.5x0.6 smd: 1(-3.675,1.905) 2(-3.675,0.635) 3(-3.675,-0.635) 4(-3.675,-1.905) 5(3.675,-1.905) 6(3.675,-0.635) 7(3.675,0.635) 8(3.675,1.905)
  silkscreen extent -4.11,-2.7 2.69,2.7, body extent -4.1,-2.7 4.1,2.7, height 2.17
SOIC-8 [mm] "duplicate of SO-8.  SOIC, 8-Leads, Body 5.0x4.0mm (max), Pitch 1.27mm, IPC Medium Density"
  rrect17% 1.45x0.6 smd: 1(-2.725,1.905) 2(-2.725,0.635) 3(-2.725,-0.635) 4(-2.725,-1.905) 5(2.725,-1.905) 6(2.725,-0.635) 7(2.725,0.635) 8(2.725,1.905)
  silkscreen extent -3.5,-2.5 0.9,2.5, body extent -3,-2.45 3,2.45, height 1.63
SOT-23 [mm] "SOT23, 3-Leads, Body 2.9x1.3mm, Pitch 0.95mm, Lead Span 2.5mm, IPC Medium Density"
  rrect50% 1x0.6 smd: 1(-1.2,0.95) 2(-1.2,-0.95) 3(1.2,0)
  silkscreen extent -1.62,-1.5 0.7,1.5, body extent -1.16,-1.45 1.21,1.45, height 1
"SW_ L101011MS02Q" [mm] "SWITCH SLIDE sPST 4A PCB"
  rect 2.416x2.416 hole 1.65: 1(2.858,4.6)
  round 2.416 hole 1.65: 2(2.857,0) 3(2.858,-4.6)
  silkscreen extent -5.4,-9.55 5.4,9.55, body extent -5.39,-9.55 5.39,9.55, height 14.18
TCBS-6-01 [mil] "Richco Plastics"
  round 157 hole 157 unplated mask+10: 1(0,0)
  body extent -180,-156 180,156, height 375
TE_5-146278-4 [mm] "TE CONNECTIVITY"
  rect 1.65x1.65 hole 1: 1(-3.81,0)
  round 1.65 hole 1: 2(-1.27,0) 3(1.27,0) 4(3.81,0)
  silkscreen extent -5.46,-1.27 5.08,1.27, body extent -4.95,-1.17 4.95,1.17, height 8.13
TFMR_5_150x150_50 [mil] "TFMR_5_150X150_50"
  rect 65x30 smd: 1(-62.5,-50) 2(-62.5,0) 3(-62.5,50) 4(62.5,50) 6(62.5,-50)
  silkscreen extent -110,-90 110,90
TSW-102-07-G-S [mm] "Samtec 100mil, 1x2, 230 mil above insulator"
  rrect6% 1.65x1.65 hole 1.016: 1(-1.27,0)
  round 1.65 hole 1.016: 2(1.27,0)
  silkscreen extent -2.54,-1.27 2.54,1.65, body extent -2.54,-1.27 2.54,1.27, height 8.38
TSW-104-07-G-D [mm] "Samtec 100mil, 2x4, 230 mil above insulator"
  rrect6% 1.65x1.65 hole 1.016: 1(-3.81,-1.27)
  round 1.65 hole 1.016: 2(-3.81,1.27) 3(-1.27,-1.27) 4(-1.27,1.27) 5(1.27,-1.27) 6(1.27,1.27) 7(3.81,-1.27) 8(3.81,1.27)
  silkscreen extent -6.1,-2.54 5.08,2.54, body extent -5.08,-2.54 5.08,2.54, height 8.38
TSW-116-07-G-D [mm] "Samtec 100mil, 2x16, 230 mil above insulator"
  rrect6% 1.65x1.65 hole 1.016: 1(-19.05,-1.27)
  round 1.65 hole 1.016: 2(-19.05,1.27) 3(-16.51,-1.27) 4(-16.51,1.27) 5(-13.97,-1.27) 6(-13.97,1.27) 7(-11.43,-1.27) 8(-11.43,1.27) 9(-8.89,-1.27) 10(-8.89,1.27) 11(-6.35,-1.27) 12(-6.35,1.27) 13(-3.81,-1.27) 14(-3.81,1.27) 15(-1.27,-1.27) 16(-1.27,1.27) 17(1.27,-1.27) 18(1.27,1.27) 19(3.81,-1.27) 20(3.81,1.27) 21(6.35,-1.27) 22(6.35,1.27) 23(8.89,-1.27) 24(8.89,1.27) 25(11.43,-1.27) 26(11.43,1.27) 27(13.97,-1.27) 28(13.97,1.27) 29(16.51,-1.27) 30(16.51,1.27) 31(19.05,-1.27) 32(19.05,1.27)
  silkscreen extent -21.35,-2.54 20.32,2.54, body extent -20.32,-2.54 20.32,2.54, height 8.38
"WE-CBF_1210_High Current" [mm] "SMD EMI Suppression Ferrite  Bead, body 3.2mmx2.5mm"
  rect 1.6x1.8 smd: 1(-1.8,0) 2(1.8,0)
  silkscreen extent -2.85,-1.25 2.85,1.25, body extent -1.6,-1.25 1.6,1.25, height 1.34
WE-LPF_0603 [mm] "WE-LPF Multilayer Chip Low-Pass Filter, 0603"
  rect 0.25x0.55 smd mask+0: 1(0.5,0.4) 2(0,0.4) 3(-0.5,0.4) 4(-0.5,-0.4) 5(0,-0.4) 6(0.5,-0.4)
  silkscreen extent -0.8,-0.8 0.8,0.8, body extent -0.8,-0.4 0.8,0.4, height 0.62
WL-SMCW_Green_0805 [mm] "SMD, 2-Leads, Body 2x1.25mm"
  rect 1.1x1.2 smd: 1(-1.05,0) 2(1.05,0)
  silkscreen extent -2.4,-1.1 1.5,1.1, body extent -1,-0.62 1,0.63, height 0.7
WURTH_61301021121 [mm] "Header, 2.54mm, 5x2, TH"
  rect 1.65x1.65 hole 1.15: 1(-5.08,-1.27)
  round 1.65 hole 1.15: 2(-5.08,1.27) 3(-2.54,-1.27) 4(-2.54,1.27) 5(0,-1.27) 6(0,1.27) 7(2.54,-1.27) 8(2.54,1.27) 9(5.08,-1.27) 10(5.08,1.27)
  silkscreen extent -6.35,-2.92 6.35,2.54, body extent -6.35,-2.54 6.35,2.54, height 8.54
XTAL_ABM3 [mm] "Abracon recommended land pattern 12.28.10"
  rect 1.9x2.4 smd: 1(-2.05,0) 2(2.05,0)
  silkscreen extent -2.67,-1.78 2.67,1.78, body extent -2.6,-1.7 2.6,1.7, height 1.3

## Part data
3P3V_RX1 3P3V_RX2 TP6 TP12 TP13 TP14 TP17 TP18 TP21 TP22 TP23 TP24 TP25 TP26 TP31 TP32 TP33 TP34 TP35 TP36 TP37 TP38 TP39 TP40 TP41 TP42 TP43 TP44 TP45 TP46 TP47 TP48 TP49 TP54 TP55 TP56 TP57 TP58 TP59 TP60 TP61 TP62 TP63 TP77: "Test Point, Miniature, Red, TH"
BG1 BG2 CALSAT1 CALSAT2 CE_TP1 CE_TP2 RMPCLK1 RMPCLK2 RMPDIR1 RMPDIR2 SYNC1 TP1 TP2 TP3 TP7 TP8 TP9 Vtune_TP1 Vtune_TP2: "Test Point, Miniature, White, TH"
C1 C12 C13 C14 C27 C35 C46 C47 C48 C61 C161 C172 C173 C174 C187 C195 C206 C207 C208 C221 C384 C385 C386 C387 C388 C389 C390 C412 C422 C435 C492 C500 C504 C507: "CAP, CERM, 0.01 µF, 25 V, +/- 10%, X7R, 0402"
C2 C3 C4 C5 C21 C22 C23 C24 C36 C37 C38 C39 C55 C56 C57 C58 C162 C163 C164 C165 C181 C182 C183 C184 C196 C197 C198 C199 C215 C216 C217 C218: "CAP, CERM, 0.01 µF, 25 V, +/- 20%, X7R, 0306"
C6 C7 C8 C9 C17 C18 C19 C20 C40 C41 C42 C43 C51 C52 C53 C54 C166 C167 C168 C169 C177 C178 C179 C180 C200 C201 C202 C203 C211 C212 C213 C214: "CAP, CERM, 2200 pF, 50 V, +/- 20%, X7R, 0306"
C10 C15 C44 C49 C170 C175 C204 C209: "CAP, CERM, 1 pF, 50 V, +/- 5%, C0G/NP0, 0402"
C11 C16 C45 C50 C171 C176 C205 C210: "CAP, CERM, 2.4 pF, 50 V, +/- 5%, C0G/NP0, 0402"
C25 C28 C31 C32 C33 C34 C59 C62 C65 C66 C67 C68 C185 C188 C191 C192 C193 C194 C219 C222 C225 C226 C227 C228: "CAP, CERM, 0.1 µF, 10 V, +/- 10%, X5R, 0402"
C26 C60 C70 C132 C133 C159 C160 C186 C220 C230 C292 C293 C319 C320 C475 C476 C484: "CAP, CERM, 1 µF, 10 V, +/- 10%, X5R, 0603"
C29 C30 C63 C64 C189 C190 C223 C224: "CAP, TA, 10 µF, 10 V, +/- 10%, 0.9 ohm, SMD"
C69 C74 C82 C83 C94 C95 C109 C229 C234 C242 C243 C254 C255 C269 C321 C325 C334 C341 C391 C392 C394 C396 C399 C401 C402 C406 C407 C408 C410 C413 C415 C417 C419 C423 C424 C436 C437 C438: "CAP, CERM, 0.1 µF, 25 V, +/- 20%, X7R, 0402"
C71 C72 C73 C75 C76 C77 C78 C79 C80 C81 C84 C85 C86 C87 C88 C89 C96 C98 C100 C101 C102 C103 C104 C105 C106 C110 C111 C112 C113 C114 C115 C118 C120 C121 C122 C123 C124 C125 C126 C127 C128 C129 C130 C131 C135 C136 C137 C138 C139 C140 C141 C142 C143 C144 C145 C146 C150 C151 C152 C153 C154 C155 C156 C157 C158 C231 C232 C233 C235 C236 C237 C238 C239 C240 C241 C244 C245 C246 C247 C248 C249 C256 C258 C260 C261 C262 C263 C264 C265 C266 C270 C271 C272 C273 C274 C275 C278 C280 C281 C282 C283 C284 C285 C286 C287 C288 C289 C290 C291 C295 C296 C297 C298 C299 C300 C301 C302 C303 C304 C305 C306 C310 C311 C312 C313 C314 C315 C316 C317 C318 C483: "CAP, CERM, 0.1 µF, 10 V, +/- 10%, X7S, 0201"
C90 C91 C92 C93 C97 C99 C250 C251 C252 C253 C257 C259: "CAP, CERM, 4700 pF, 50 V, +/- 10%, X7R, 0402"
C107 C116 C117 C267 C276 C277: "CAP, CERM, 100 pF, 50 V, +/- 5%, C0G/NP0, 0402"
C108 C119 C134 C149 C268 C279 C294 C309 C482: "CAP, TA, 10 µF, 10 V, +/- 20%, 2.5 ohm, SMD"
C147 C485 C596 C605 C609 C622 C625 C629 C633 C637 C638 C648 C650 C658 C659 C670 C671 C688 C689 C699 C700 C708 C709 C717 C718: "CAP, CERM, 0.1 µF, 50 V, +/- 10%, X7R, AEC-Q200 Grade 1, 0603"
C148 C431 C441 C442 C443 C444 C445 C447 C448 C449 C450 C451 C452 C453 C454 C455 C456 C458 C459 C460 C461 C462 C463 C464 C465 C467 C468 C469 C472 C489 C737 C738 C741: "CAP, CERM, 0.1uF, 25V, +/-5%, X7R, 0603"
C307: "CAP, CERM, 0.1 µF, 6.3 V,+/- 10%, X5R, 0201"
C308: "CAP, CERM, 0.1 µF, 25 V,+/- 20%, X7R, 0402"
C322 C338 C352 C368: "CAP, CERM, 0.01 µF, 16 V, +/- 10%, X7R, 0402"
C323 C324 C326 C332 C333 C340 C343 C353 C354 C356 C362 C363 C370 C373 C470 C473: "CAP, CERM, 1 µF, 16 V, +/- 10%, X7R, 0603"
C327 C328 C331 C348 C349 C350 C357 C358 C361 C378 C379 C380: "CAP, CERM, 0.1uF, 16V, +/-5%, X7R, 0603"
C329 C330 C359 C360 C432: "CAP, CERM, 10uF, 10V, +/-10%, X5R, 0805"
C335 C365: "CAP, CERM, 1200 pF, 50 V, +/- 5%, C0G/NP0, 0603"
C336 C366: "CAP, CERM, 300pF, 100V, +/-5%, C0G/NP0, 0603"
C337 C367: "CAP, CERM, 0.027 µF, 50 V, +/- 10%, X7R, 0603"
C339 C369: "CAP, CERM, 220 pF, 50 V, +/- 5%, C0G/NP0, 0603"
C342 C344 C345 C346 C347 C372 C374 C375 C376 C377 C457 C466 C736: "CAP, CERM, 10 µF, 10 V, +/- 20%, X5R, 0603"
C351 C397 C400 C403 C404 C405: "CAP, CERM, 0.1 µF, 6.3 V, +/- 10%, X5R, 0201"
C355 C364 C371 C509 C510: "CAP, CERM, 470 pF, 50 V, +/- 5%, C0G/NP0, 0402"
C381: "CAP, CERM, 10 µF, 16 V, +/- 20%, X5R, 0603"
C382 C420 C428 C429 C430 C433 C439 C440: "CAP, CERM, 1 µF, 10 V, +/- 10%, X7S, 0402"
C383 C421 C434 C508 C511: "CAP, CERM, 0.1 µF, 16 V, +/- 10%, X7R, 0402"
C393: "CAP, CERM, 3900 pF, 10 V, +/- 10%, X5R, 0201"
C395: "CAP, CERM, 47 pF, 25 V, +/- 5%, C0G/NP0, 0201"
C398: "CAP, CERM, 0.68 µF, 10 V, +/- 10%, X5R, 0402"
C409: "CAP, CERM, 12 pF, 25 V, +/- 5%, C0G/NP0, AEC-Q200 Grade 1, 0402"
C411: "CAP, CERM, 4.7 µF, 6.3 V, +/- 20%, X5R, 0402"
C414: "CAP, CERM, 10 pF, 50 V, +/- 5%, C0G/NP0, 0402"
C416: "CAP, CERM, 2200 pF, 25 V, +/- 10%, X7R, 0402"
C418: "CAP, CERM, 100 pF, 50 V, +/- 1%, C0G/NP0, 0402"
C425 C426 C427: "CAP, CERM, 33pF, 50V, +/-5%, C0G/NP0, 0603"
C446: "CAP, CERM, 1 µF, 10 V,+/- 10%, X7S, 0402"
C471 C474: "CAP, CERM, 100 µF, 10 V, +/- 20%, X5R, 1210"
C477 C478 C479 C723: "CAP, CERM, 1 µF, 25 V, +/- 10%, X5R, 0805"
C480 C481: "CAP, CERM, 1000 pF, 100 V, +/- 20%, X7R, 0603"
C486 C597 C610 C626 C630 C634: "CAP, CERM, 33 µF, 25 V, +/- 20%, X5R, 1206"
C487 C494 C496 C497 C498 C537 C539 C540 C541 C598 C600 C602 C603 C604 C606 C611 C623 C627 C631 C635 C639 C641 C643 C644 C645 C646 C649 C651 C663 C665 C672 C674 C690 C691 C693 C701 C703 C705 C706 C707 C710 C712 C715 C719 C721: "CAP, CERM, 10 µF, 25 V, +/- 20%, X7R, 1206_190"
C488 C599 C607 C612 C624 C628 C632 C636 C640 C642 C652 C653 C664 C666 C673 C675 C692 C694 C702 C704 C711 C713 C720 C722: "CAP, CERM, 0.01 µF, 50 V, +/- 10%, X7R, AEC-Q200 Grade 1, 0603"
C490 C491 C493 C499 C502 C503 C505 C506: "CAP, CERM, 0.1 µF, 16 V, +/- 5%, X7R, 0402"
C495 C538 C601 C647 C695 C696 C697: "CAP, CERM, 22 µF, 6.3 V, +/- 20%, X5R, 0805"
C501 C544 C608 C654 C698: "CAP, CERM, 3300 pF, 50 V, +/- 5%, C0G/NP0, 0603"
C512: "CAP, CERM, 0.01 µF, 25 V,+/- 10%, X7R, 0402"
C516 C517 C523 C587 C588 C594 C613 C614 C620 C655 C656 C668: "CAP, CERM, 10 µF, 16 V, +/- 10%, X5R, 0805"
C518 C519 C589 C590 C615 C616 C657 C660 C714: "CAP, CERM, 47 µF, 4 V, +/- 20%, X5R, 0805"
C522 C524 C593 C595 C619 C621 C667 C669 C716: "CAP, CERM, 0.01 µF, 50 V, +/- 10%, X7R, 0603"
C739 C740: "CAP, CERM, 16 pF, 100 V, +/- 5%, C0G/NP0, 0603"
D1 D3 D6 D8: "LED, Orange, SMD"
D2 D4 D7 D9: "Diode, Ultrafast, 100 V, 0.15 A, SOD-123"
D5 D10 D11 D12 D13 D14 D15 D16 D17 D18 D21: "LED, Green, SMD"
D19: "Diode, TVS, Bi, 15 V, 24.4 Vc, SMB"
D20: "Diode, Schottky, 30 V, 1 A, SOD-123"
FID1 FID2 FID3 FID4 FID5 FID6: "Fiducial mark.  There is nothing to buy or mount."
J1 J2 J3 J4 J8 J9 J12 J15 J19 J20 J26 J27 J29 J56 J57 J61 J74 OSCinM1 OSCinM2 OSCinM3 OSCinP1 OSCinP2 OSCinP3: "Connector, TH, SMA"
J5 J16 J34 J40: "Header, 100mil, 4x2, Gold, TH"
J6 J7 J11 J17 J18 J22 J35 J36 J37 J38 J41 J42 J43 J44 J45 J47 J49 J50 J52 J54 J64 J67 J68 J78 J79 J82 J83 J84: "Header, 100mil, 2x1, Gold, TH"
J10 J21: "Connector, SMA, TH"
J13 J14 J30 J73 J76 J77 J80 J81: "JACK, SMA, 50 Ohm, Gold, Edge Mount"
J23 J24 J25: "Header, 100mil, 4x1, TH"
J28: library part CMP-0077743-1, "SMA, 50 Ohm, Gold, TH"
J31 J32 J39: "Header, 2.54 mm, 5x2, Gold, TH"
J33: "Header, 100mil, 3x1, Gold, TH"
J46 J51: "14 ROW .050 PITCH TERMINAL ARRAY ASM."
J48 J53: "Header, 100mil, 4x1, Tin, TH"
J55: "Power Jack, mini, 2.1mm OD, R/A, TH"
J58 J63: "Header, 100mil, 6x2, Tin, TH"
J59 J60: "Header, 100mil, 16x2, Gold, TH"
J62: "Header, 2.54 mm, 3x2, Gold, TH"
J71 J75: "Header, 100mil, 3x1, TH"
J72: "WR-COM Mini USB 2.0 Type AB SMT Horizontal 5 Contacts"
J85: "Header, 100mil, 5x1, TH"
L1 L3 L5 L7 L9 L11 L13 L15: "Inductor, Wirewound, 5.6 nH, 0.9 A, 0.045 ohm, SMD"
L2 L4 L6 L8 L10 L12 L14 L16: "Inductor, Wirewound, Ceramic, 3.9 nH, 2.2 A, 0.054 ohm, SMD"
L17 L18 L19 L20: "Inductor, Multilayer, Air Core, 18 nH, 0.3 A, 0.36 ohm, SMD"
L21 L48 L49 L50 L51 L52 L53 L54 L55 L56 L60 L61 L62 L63 L64 L65 L66 L67: "Ferrite Bead, 120 ohm @ 100 MHz, 3 A, 0603"
L22 L23 L24 L25 L26 L27 L28 L29 L30 L31: "Ferrite Bead, 120 ohm @ 100 MHz, 0.5 A, 0603"
L32 L33 L34: "Ferrite Bead, 26 ohm @ 100 MHz, 6 A, 0603"
L35 L36 L37 L38 L39 L40 L41 L42 L43 L44 L45 L46 L47 L57 L58 L59 L68 L69 L70 L71 L72 L73 L74 L83 L84 L85 L86 L87 L88 L89 L90 L91 L92: "Ferrite Bead, 1000 ohm @ 100 MHz, 1.5 A, 1806"
L75 L76 L77 L78 L79 L80 L81 L82: "WE-LPF Multilayer Chip Low-Pass Filter, size 0603, 2400-2500MHz"
L93 L94 L95 L96: library part "WE-CBF, 742792310", "WE-CBF SMD EMI Suppression Ferrite Bead, 1210, 30O"
LBL1: library part THT-14-423-10, "Thermal Transfer Printable Labels, 0.650\" W x 0.200\" H - 10,000 per roll"
LF1 LF2 LF3 LF4 LF5 LF6 LF7 LF8: "Filter for Communication Equipment, SMD"
Logo1: library part ESD_Susceptible, "ESD Susceptible Symbol"
Logo2: library part Pb-Free
Logo3: library part FCC_disclaimer, "FCC_disclaimer"
Logo4: library part EURoHS_Exempt
Logo5: library part IEC_Caution, "IEC 61010-1 Caution Warning"
Q1 Q2: library part "MMBT3904, Fairchild Semiconductor", "Transistor, NPN, 40 V, 0.2 A, SOT-23"
Q3: "MOSFET, N-CH, 20 V, 10 A, DQK0006C (WSON-6)"
R1 R3 R25 R27 R82 R84 R106 R108 R483 R556 R557 R558 R559 R565 R566 R567 R568 R574 R575 R576 R577 R583 R584 R585: "RES, 2.00 k, 1%, 0.063 W, 0402"
R2 R10 R11 R14 R15 R23 R24 R26 R34 R35 R38 R39 R47 R48 R67 R68 R69 R70 R78 R79 R83 R91 R92 R95 R96 R104 R105 R107 R115 R116 R119 R120 R128 R129 R148 R149 R150 R151 R159 R160 R174 R178 R181 R184 R185 R186 R188 R193 R195 R197 R200 R203 R204 R207 R215 R219 R222 R225 R226 R229 R234 R236 R238 R239 R244 R245 R246 R247 R248 R249 R250 R251 R252 R253 R254 R255 R256 R257 R260 R261 R262 R263 R264 R265 R266 R270 R271 R272 R277 R280 R285 R286 R287 R293 R295 R303 R304 R306 R310 R313 R314 R315 R316 R317 R318 R320 R322 R323 R325 R326 R343 R346 R350 R355 R356 R357 R359 R360 R361 R390 R391 R474 R477 R479 R482 R495 R496 R497 R498 R499 R500 R507 R508 R509 R510 R511 R512 R519 R520 R521 R522 R523 R524 R586 R587 R588 R589 R590 R633 R636 R637 R638 R639 R640 R641 R642 R643 R644 R645: "RES, 0, 5%, 0.063 W, 0402"
R4 R18 R28 R42 R85 R99 R109 R123: "RES, 4.99, 1%, 0.063 W, 0402"
R5 R19 R29 R43 R54 R55 R56 R57 R63 R64 R71 R86 R100 R110 R124 R135 R136 R137 R138 R144 R145 R152 R553 R554 R562 R563 R571 R572 R580 R581: "RES, 1.00 k, 1%, 0.1 W, 0402"
R6 R16 R30 R40 R87 R97 R111 R121: "RES, 127, 1%, 0.063 W, 0402"
R7 R17 R31 R41 R88 R98 R112 R122: "RES, 1.21 k, 1%, 0.063 W, 0402"
R8 R12 R32 R36 R89 R93 R113 R117: "RES, 22.6, 1%, 0.063 W, 0402"
R9 R13 R33 R37 R90 R94 R114 R118: "RES, 15.0, 1%, 0.063 W, 0402"
R20 R21 R44 R45 R101 R102 R125 R126: "RES, 365, 1%, 0.063 W, 0402"
R22 R46 R103 R127: "RES, 10.0 k, 1%, 0.063 W, 0402"
R49 R130 R492: "RES, 8.06 k, 1%, 0.063 W, 0402"
R50 R61 R131 R142 R352 R353 R358: "RES, 1.2 k, 5%, 0.063 W, 0402"
R51 R62 R132 R143: "RES, 1.00 M, 1%, 0.1 W, 0402"
R52 R53 R58 R59 R65 R66 R74 R75 R76 R133 R134 R139 R140 R146 R147 R155 R156 R157 R228 R368: "RES, 10.0 k, 1%, 0.1 W, 0402"
R60 R141: "RES, 1.33 k, 1%, 0.063 W, 0402"
R72 R153: "RES, 2.10 k, 1%, 0.063 W, 0402"
R73 R154 R267 R344: "RES, 100, 1%, 0.063 W, 0402"
R77 R158: "RES, 750, 5%, 0.1 W, 0603"
R80 R81 R161 R162: "RES, 1.3 k, 5%, 0.1 W, 0603"
R163 R166: "RES, 1.5 k, 5%, 0.063 W, 0402"
R164 R168 R175 R180 R205 R209 R216 R221: "RES, 50, 0.1%, 0.05 W, 0402"
R165 R167 R169 R170 R171 R173 R206 R208 R210 R211 R212 R214 R470: "RES, 0 ohm, 5%, 0.1W, 0603"
R172 R213: "RES, 100 k, 5%, 0.1 W, 0603"
R176 R218: "RES, 56, 5%, 0.1 W, 0603"
R177 R191 R192 R198 R199 R217 R232 R233 R241 R242 R296 R374 R375 R376 R377 R378 R379 R386 R387 R388 R389 R403 R408 R410 R494 R506 R518 R530 R593 R594 R595 R596 R598 R600: "RES, 0, 5%, 0.1 W, 0603"
R179 R220 R469: "RES, 270, 5%, 0.1 W, 0603"
R182 R183 R223 R224: "RES, 10.0 k, 0.5%, 0.063 W, 0402"
R187 R196 R227 R237 R394 R396 R398 R400 R402 R404 R405 R407 R409 R411 R416 R420 R421 R423 R424 R425 R440 R441 R445 R447 R449 R451 R452 R454 R467 R468 R591: "RES, 100, 1%, 0.1 W, 0603"
R189 R202 R230 R243: "RES, 51, 5%, 0.1 W, 0603"
R190 R231: "RES, 330 ohm, 5%, 0.1W, 0603"
R194 R201 R235 R240 R475 R476 R480 R481: "RES, 100, 5%, 0.063 W, 0402"
R258 R259 R268 R269: "RES, 160, 5%, 0.063 W, 0402"
R273 R274 R276 R279 R282 R283 R288 R289 R292 R294 R299 R300: "RES, 120, 5%, 0.063 W, 0402"
R275: "RES, 620, 1%, 0.05 W, 0201"
R278 R290 R301 R302 R309 R392 R401 R551 R552 R560 R561 R569 R570 R578 R579 R592 R604 R605 R606 R607 R608 R609 R610 R646 R647 R648 R649 R650 R651 R652 R653 R654 R655 R656 R657 R658 R659 R660 R661 R662 R663 R664 R665 R666 R667 R668 R669 R670 R671 R672 R673 R674 R675 R676 R677: "RES, 0, 5%, 0.05 W, 0201"
R281 R291: "RES, 51, 5%, 0.05 W, 0201"
R284: "RES, 39.0 k, 1%, 0.05 W, 0201"
R297 R298 R311 R312: "RES, 49.9, 1%, 0.05 W, 0201"
R305: "RES, 100, 1%, 0.05 W, 0201"
R307 R308: "RES, 294, 1%, 0.05 W, 0201"
R319 R341: "RES, 49.9, 1%, 0.063 W, 0402"
R321 R340: "RES, 130, 1%, 0.063 W, 0402"
R324 R327: "RES, 18, 5%, 0.063 W, 0402"
R328 R329 R330 R331 R332 R333 R334 R335 R336 R337 R338 R339 R362 R363 R364 R365: "RES, 240, 5%, 0.063 W, 0402"
R342 R345 R349 R354: "RES, 20.0, 1%, 0.063 W, 0402"
R347 R348 R366 R367: "RES, 220, 5%, 0.063 W, 0402"
R351: "RES, 82.0, 1%, 0.1 W, 0603"
R369: "RES, 47, 5%, 0.063 W, 0402"
R370 R371 R372 R373: "RES, 750, 1%, 0.1 W, 0603"
R380 R381 R382 R383 R384 R385 R406 R429 R430 R431 R544 R545 R546: "RES, 10 k, 5%, 0.1 W, 0603"
R393: "RES, 33 k, 5%, 0.063 W, 0402"
R395 R399: "RES, 0, 5%, 0.05 W, AEC-Q200 Grade 0, 0201"
R397 R489 R503 R513 R525: "RES, 100 k, 1%, 0.063 W, 0402"
R426 R427 R428 R597 R599 R601 R602 R603: "RES, 33, 5%, 0.1 W, 0603"
R432 R433 R434 R435 R436 R437 R438 R439 R455 R456 R458 R459 R461 R462 R464 R465 R485 R543 R549: "RES, 1.00 k, 1%, 0.1 W, 0603"
R472 R539: "RES, 10.0, 1%, 0.25 W, 0603"
R473 R478: "RES, 4.99 k, 1%, 0.063 W, 0402"
R484: "RES, 1.00 M, 1%, 0.1 W, 0603"
R486 R493 R505 R517 R529: "RES, 10.0 k, 1%, 0.1 W, 0603"
R487: "RES, 45.3 k, 1%, 0.1 W, 0603"
R488: "RES, 100 k, 1%, 0.1 W, 0603"
R490: "RES, 11.0 k, 1%, 0.063 W, 0402"
R491: "RES, 13.7 k, 1%, 0.063 W, 0402"
R501: "RES, 3.24 k, 1%, 0.063 W, 0402"
R502: "RES, 6.34 k, 1%, 0.063 W, 0402"
R504 R535: "RES, 9.09 k, 1%, 0.063 W, 0402"
R514: "RES, 34.8 k, 1%, 0.1 W, 0603"
R515: "RES, 38.3 k, 1%, 0.063 W, 0402"
R516 R528: "RES, 11.3 k, 1%, 0.063 W, 0402"
R526: "RES, 24.9 k, 1%, 0.1 W, 0603"
R527: "RES, 27.4 k, 1%, 0.063 W, 0402"
R531: "RES, 24.3 k, 1%, 0.1 W, 0603"
R532: "RES, 11.5 k, 1%, 0.1 W, 0603"
R533: "RES, 19.6 k, 1%, 0.063 W, 0402"
R534: "RES, 28.7 k, 1%, 0.063 W, 0402"
R536: "RES, 118 k, 1%, 0.063 W, 0402"
R537: "RES, 105 k, 1%, 0.063 W, 0402"
R541 R548 R550: "RES, 10.0 k, 1%, 0.25 W, 1206"
R542: "RES, 12k ohm, 5%, 0.1W, 0603"
R547: "RES, 2.2 k, 5%, 0.1 W, 0603"
R555 R564 R573 R582: "RES, 50, 0.1%, 0.5 W, 0402"
R613 R614 R617 R618 R621 R622 R625 R626 R629 R630: "RES, 0, 5%, 0.25 W, 1206"
R631 R632 R634 R635: "RES, 10.0 k, 0.5%, 0.1 W, 0603"
S1 S2 S3 S4 S5 S6 S7 S8 S9 S10 S11 S12: "HEX STANDOFF SPACER, 9.53 mm"
S17: "SWITCH SLIDE SPST 4A PCB, TH"
T1 T2: "RF Transformer, 50 ohm, SMT"
T3: library part TFMR_5_TC1-1-13M+, "RF Transformer"
TP4 TP5 TP10 TP11: "Test Point, O.025\""
TP15 TP16 TP20 TP27 TP28 TP29 TP30 TP50 TP51 TP52 TP53 TP64 TP65 TP66 TP67 TP68 TP69 TP70 TP71 TP72 TP73 TP74 TP75 TP76: "Test Point, Miniature, Black, TH"
TP19: "Test Point, Multipurpose, White, TH"
U1 U4 U10 U13: "8GHz Ultra Wideband Fully Differential Amplifier, RMS0014A (UQFN-14)"
U2 U5 U11 U14: "4.5 GHz Ultra Wideband Digital Variable Gain Amplifier, RMZ0016A (UQFN-HR-16)"
U3 U6 U12 U15: "Precision, Low Noise, Low Iq Operational Amplifier, 2.2 to 5.5 V, -40 to 125 degC, 5-pin SOT23 (DCK0005A), Green (RoHS & no Sb/Br)"
U7 U16: "Dual Micro-Power Rail-to-Rail Input CMOS Comparator with Push-Pull Output, 8-pin Narrow SOIC"
U8 U17: "6.4-GSPS Single Channel or 3.2-GSPS Dual Channel 12-bit Analog-to-Digital Converter (ADC) Family, AAV0144A (FCBGA-144)"
U9 U18: "Dual Remote Diode and Local Temperature Sensor with SMBus Interface and TruTherm Technology, 15-pin LLP"
U19 U21: "High Performance, Wideband PLLatinum RF Synthesizer, RHA0040A (VQFN-40)"
U20 U22: "Automotive LVDS Dual Differential Line Receiver, 8-pin Narrow SOIC"
U23: "3.1-GHz Differential Clock Buffer/Level Translator, RTV0032A (WQFN-32)"
U24: "LMK04828BISQE/NOPB"
U25: "Ultra-Low Jitter Programmable Oscillator with Internal EEPROM, SIA0008B"
U26 U27 U29 U30 U31 U32 U33: "4-Bit Dual-Supply Bus Transceiver With Configurable Voltage-Level Shifting and 3-State Outputs, PW0016A (TSSOP-16)"
U28 U54: "Single Bus Buffer Gate With 3-State Outputs, DBV0005A (SOT-5)"
U34: "Quad High Speed USB to Multipurpose UART/MPSSE IC"
U35: "Single Output LDO, 300 mA, Fixed 3.3 V Output, 2 to 5.5 V Input, with Low IQ, 5-pin SOT-23 (DBV), -40 to 125 degC, Green (RoHS & no Sb/Br)"
U36 U37: library part 24LC65, "64K I2C Smart Serial EEPROM, SOIC-8"
U38: "5V, 5A, 30mO eFuse with Adjustable +/-15% Accurate Current Limit, DRC0010J (VSON-10)"
U39 U42 U45 U48 U51: "3-A 17V Step-down Converter Module with Integrated Inductor, SIL0008D (uSIP-8)"
U40 U43 U46 U49 U52: "FILTER LC HIGH FREQ 27uF 1206"
U41 U44 U47: "High-Current (3 A), High-Accuracy (1%), Low-Noise (4.4 µVRMS), LDO Voltage Regulator, RGR0020A (VQFN-20)"
U50: "2A, Low-Dropout Voltage Regulator for High Speed Communication Systems, RGR0020A (VQFN-20)"
U53: "Single Output High PSRR LDO, 1 A, Adjustable -1.18 to -33 V Output, -3 to -36 V Input, with Ultra-Low Noise, 20-pin VQFN (RGW), -40 to 125 degC, Green (RoHS & no Sb/Br)"
U55 U57 U58: "Remote 8-Bit I2C and Low-Power I/O Expander With Interrupt Output and Configuration Registers, PW0016A (TSSOP-16)"
U56: "1K Microwire Compatible Serial EEPROM"
U59 U60 U61 U62: "Broadband Balun, 500 kHz to 6 GHz"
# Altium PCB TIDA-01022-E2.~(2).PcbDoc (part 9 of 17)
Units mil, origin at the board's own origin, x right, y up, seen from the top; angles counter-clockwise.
Board outline 6929.13 x 11614.17 mil, 12 copper layers (L1_Top Layer, L2_GND, L3_GND, L4_Signal Layer 1, L5_GND, L6_PWR, L7_GND/PWR, L8_PWR, L9_GND/PWR, L10_Signal Layer 2, L11_GND, L12_Bottom Layer), stack 64.6 mil thick; 1711 components, 1001 nets, 5985 pads, 3200 vias.

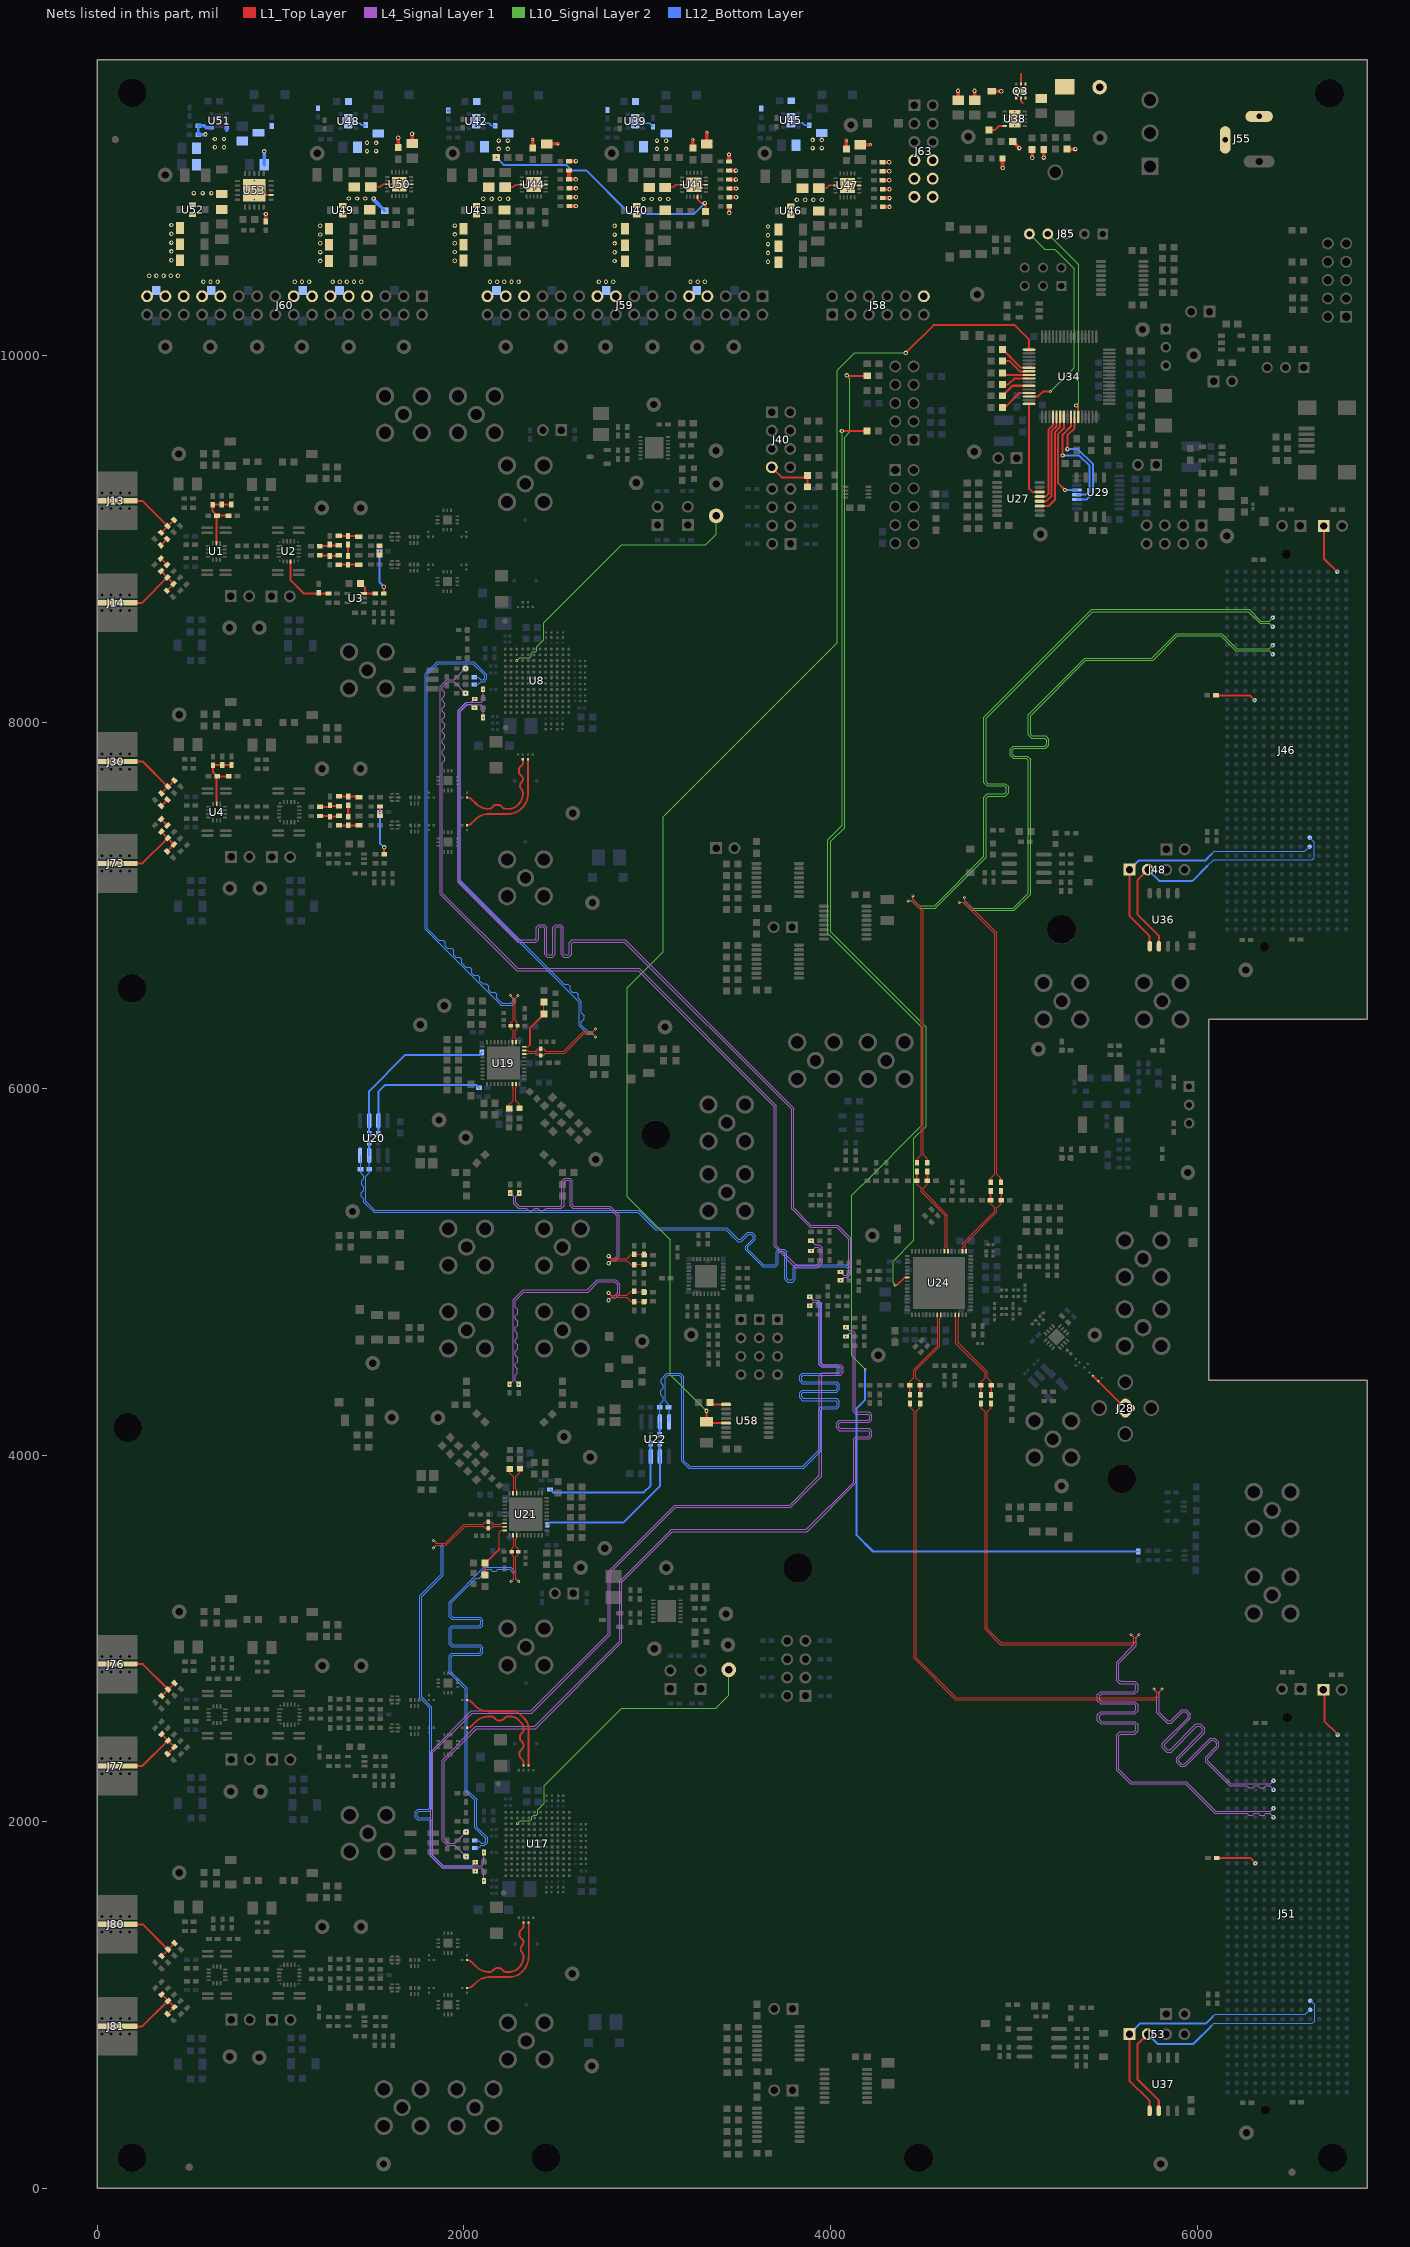
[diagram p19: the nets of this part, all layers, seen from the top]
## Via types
v1: diameter 16, hole 8, L1_Top Layer to L12_Bottom Layer, tented both sides, 1699 vias
v2: diameter 24, hole 12, L1_Top Layer to L12_Bottom Layer, tented both sides, 1501 vias

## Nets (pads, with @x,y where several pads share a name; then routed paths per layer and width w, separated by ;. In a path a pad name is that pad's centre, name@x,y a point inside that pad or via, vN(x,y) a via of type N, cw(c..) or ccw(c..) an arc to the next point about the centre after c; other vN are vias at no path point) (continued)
F_OUT2N: R606.1 R659.1 R661.2 | length 604
  L1_Top Layer w10: R659.1@2016.45,7436.62 ccw(c2016.45,7470.42) 2040.35,7446.52 2063.15,7469.32 cw(c2133.86,7398.61) 2133.86,7498.61 2241.87,7498.61 ccw(c2241.87,7602.03) 2315,7528.9 ccw(c2231.46,7612.44) 2349.6,7612.44 2349.6,7793.24 ccw(c2347.82,7793.24) 2349.08,7794.5 R606.1@2349.08,7796.9
F_OUT2P: R605.1 R654.1 R657.2 | length 603
  L1_Top Layer w10: R654.1@2016.45,7588.6 cw(c2016.45,7554.8) 2040.35,7578.7 2063.15,7555.9 ccw(c2133.86,7626.61) 2133.86,7526.61 2137.73,7526.61 ccw(c2137.73,7546.58) 2151.85,7532.46 2156.85,7537.46 2161.28,7541.9 cw(c2176.78,7526.4) 2176.78,7548.32 2187.95,7548.32 cw(c2187.95,7529.61) 2201.18,7542.84 2206.55,7537.47 2211.59,7532.42 ccw(c2225.62,7546.45) 2225.62,7526.61 2241.87,7526.61 ccw(c2241.87,7602.03) 2295.2,7548.7 ccw(c2231.47,7612.44) 2321.6,7612.44 ccw(c2288.85,7612.44) 2319.23,7624.67 ccw(c2288.85,7612.44) 2312.01,7635.59 2311.8,7635.8 cw(c2324.84,7648.84) 2306.4,7648.84 2306.4,7655.58 cw(c2325.52,7655.58) 2312,7669.1 2313.68,7670.78 ccw(c2294.56,7689.9) 2321.6,7689.9 ccw(c2301.7,7689.9) 2315.77,7703.97 2310.77,7708.97 ; 2310.76,7708.97 2306.33,7713.4 cw(c2321.83,7728.9) 2299.91,7728.9 2299.91,7740.07 cw(c2318.62,7740.07) 2305.39,7753.3 2310.76,7758.67 ; 2310.77,7758.67 2315.81,7763.71 ccw(c2301.78,7777.74) 2321.62,7777.74 R605.1@2321.62,7796.9 ; R605.1@2320.53,7796.9 cw(c2317.95,7794.32) 2321.6,7794.32 ccw(c2317.95,7794.32) R605.1@2320.53,7796.9
F_OUT3N: R608.1 R667.1 R669.2 | length 607.8
  L1_Top Layer w10: R667.1@2016.15,2512.34 ccw(c2016.15,2546.14) 2040.05,2522.24 2062.85,2545.04 cw(c2133.56,2474.33) 2133.56,2574.33 2149.82,2574.33 cw(c2149.82,2554.49) 2163.85,2568.52 2168.89,2563.48 2174.26,2558.1 ccw(c2187.49,2571.33) 2187.49,2552.62 2198.66,2552.62 ccw(c2198.66,2574.54) 2214.16,2559.04 2218.59,2563.47 2223.59,2568.48 cw(c2237.71,2554.36) 2237.71,2574.33 2254.82,2574.33 cw(c2254.82,2516.85) 2295.46,2557.49 2311.08,2541.87 cw(c2278.65,2509.44) 2324.52,2509.44 2324.52,2498.93 cw(c2304.78,2500.92) 2318.81,2486.89 ; 2309.87,2444.19 cw(c2319.44,2453.74) 2305.92,2453.74 2305.92,2468.84 cw(c2318.37,2468.84) 2309.57,2477.65 2318.79,2486.88 ; 2309.88,2444.18 2316.37,2437.69 cw(c2296.45,2417.77) 2324.62,2417.77 2324.62,2412.83 cw(c2304.78,2412.83) 2318.81,2398.8 2313.77,2393.76 2308.39,2388.39 ccw(c2321.62,2375.16) 2302.91,2375.16 2302.91,2363.99 ccw(c2324.83,2363.99) 2309.33,2348.49 2313.76,2344.06 2318.77,2339.06 cw(c2304.65,2324.94) 2324.52,2326.93 ; R608.1@2324.08,2306.94 ccw(c2323.04,2307.98) 2324.52,2307.98 2324.52,2326.93 ; 2324.62,2324.94 ccw(c2304.65,2324.94) 2324.52,2326.93
F_OUT3P: R607.1 R662.1 R665.2 | length 608.6
  L1_Top Layer w10: R662.1@2016.15,2664.32 cw(c2016.15,2630.52) 2040.05,2654.42 2062.85,2631.62 ccw(c2133.56,2702.33) 2133.56,2602.33 2266.41,2602.33 cw(c2266.41,2544.85) 2307.06,2585.49 2330.88,2561.67 cw(c2278.65,2509.44) 2352.52,2509.44 2352.52,2484.64 ; 2352.52,2483.69 2352.52,2307 R607.1@2352.58,2306.93
F_OUT4N: R610.1 R675.1 R677.2 | length 605.4
  L1_Top Layer w10: R675.1@2016.45,1093.92 2017.78,1093.92 ccw(c2017.78,1140.22) 2050.52,1107.48 2066.48,1123.45 cw(c2137.19,1052.74) 2137.19,1152.74 2245.2,1152.74 ccw(c2245.2,1256.16) 2318.33,1183.03 ccw(c2234.8,1266.56) 2352.93,1266.56 2352.93,1447.37 ccw(c2351.15,1447.37) 2352.41,1448.63 R610.1@2352.41,1451.03
F_OUT4P: R609.1 R670.1 R673.2 | length 607.7
  L1_Top Layer w10: R670.1@2016.45,1245.9 cw(c2016.45,1211.72) 2040.62,1235.89 2066.48,1210.02 ccw(c2137.19,1280.74) 2137.19,1180.74 2141.06,1180.74 ccw(c2141.06,1200.71) 2155.18,1186.58 2160.18,1191.59 2164.61,1196.03 cw(c2180.11,1180.53) 2180.11,1202.45 2191.28,1202.45 cw(c2191.28,1183.74) 2204.51,1196.97 2209.88,1191.6 2214.92,1186.55 ccw(c2228.95,1200.58) 2228.95,1180.74 2245.2,1180.74 ccw(c2245.2,1256.16) 2298.53,1202.83 ccw(c2234.8,1266.56) 2324.93,1266.56 ccw(c2292.18,1266.56) 2322.56,1278.8 ccw(c2292.18,1266.56) 2315.34,1289.72 2315.13,1289.93 cw(c2328.17,1302.96) 2309.73,1302.96 2309.73,1309.71 cw(c2328.85,1309.71) 2315.33,1323.23 2317.01,1324.91 ccw(c2297.89,1344.03) 2324.93,1344.03 ccw(c2305.03,1344.03) 2319.1,1358.1 2314.1,1363.1 2309.66,1367.53 cw(c2325.16,1383.03) 2303.24,1383.03 2303.24,1394.2 cw(c2321.95,1394.2) 2308.72,1407.43 2314.09,1412.8 2319.14,1417.84 ccw(c2305.11,1431.87) 2324.95,1431.87 2324.95,1450 R609.1@2324.95,1451.03 ; R609.1@2323.86,1451.03 cw(c2321.28,1448.45) 2324.93,1448.45 ccw(c2321.28,1448.45) R609.1@2323.86,1451.03
F_REFCLK1+: R322.1 R329.2 U24.54 | length 500.2
  L1_Top Layer w6: R329.2@4528,5497.16 4528,5479.35 4504.62,5455.97 4504.62,5441.82 4636.13,5310.31 4636.13,5135.11 4640.47,5130.76 U24.54@4640.47,5112.95
  L1_Top Layer w10: R329.2@4528,5497.16 R322.1@4528,5547.16
F_REFCLK1-: R325.1 R328.2 U24.55 | length 500.2
  L1_Top Layer w6: R328.2@4470.25,5497.16 4470.25,5479.35 4493.62,5455.97 4493.62,5437.27 4625.13,5305.76 4625.13,5135.11 4620.79,5130.76 U24.55@4620.79,5112.95
  L1_Top Layer w10: R328.2@4470.25,5497.16 R325.1@4470.25,5547.16
F_REFCLK1_N: J46.G7 R325.2 | length 4849.6
  L1_Top Layer w6: v1(4421.23,7024.43) 4442.41,7024.43 4493.62,6973.22 4493.62,5639.53 4471.62,5617.53 R325.2@4471.62,5595.78
  L10_Signal Layer 2 w5.5: v1(4421.23,7024.43) 4440.32,7024.43 4479.75,6985 4571.97,6985 4849,7262.03 4849,7585.39 4859.36,7595.75 4953.61,7595.75 4971,7613.14 4971,7645.86 4953.61,7663.25 4859.36,7663.25 4849,7673.61 4849,8022 5430,8603 6279.03,8603 6343.02,8539.01 6394.11,8539.01 v1(6413.11,8520.01)
F_REFCLK1_P: J46.G6 R322.2 | length 4848
  L1_Top Layer w6: v1(4448.81,7052) 4448.81,7033.59 4504.62,6977.77 4504.62,5639.53 4526.62,5617.53 R322.2@4526.62,5595.78
  L10_Signal Layer 2 w5.5: v1(4448.81,7052) 4448.81,7032.91 4484.72,6997 4567,6997 4837,7267 4837,7590.36 4854.39,7607.75 4948.64,7607.75 4959,7618.11 4959,7640.89 4948.64,7651.25 4854.39,7651.25 4837,7668.64 4837,8026.97 5425.03,8615 6284,8615 6347.99,8551.01 6394.11,8551.01 v1(6413.11,8570.01)
F_REFCLK2+: R304.1 R339.2 U24.24 | length 500.6
  L1_Top Layer w6: R339.2@4432.25,4382.29 4432.25,4400.1 4454.94,4422.79 4454.94,4467.61 4585.76,4598.43 4585.76,4744.34 4581.42,4748.69 U24.24@4581.42,4766.5
  L1_Top Layer w10: R304.1@4432.25,4331.29 R339.2@4432.25,4382.29
F_REFCLK2-: R306.1 R338.2 U24.25 | length 502
  L1_Top Layer w6: R338.2@4488.63,4382.29 4488.63,4400.1 4465.94,4422.79 4465.94,4463.05 4596.76,4593.87 4596.76,4744.34 4601.1,4748.69 U24.25@4601.1,4766.5
  L1_Top Layer w10: R306.1@4488.63,4329.91 R338.2@4488.63,4382.29
F_REFCLK2_N: J51.G7 R306.2 | length 4847.8
  L1_Top Layer w6: R306.2@4488.63,4282.67 4488.63,4260.92 4466.63,4238.92 4466.63,2896.37 4686,2677 5769,2677 5780,2688 5780,2708 v1(5764,2724)
  L4_Signal Layer 1 w4.9: v1(5764,2724) 5780,2708 5780,2594.03 5835.48,2538.55 5859.86,2538.55 5920.7,2599.4 5935.14,2599.4 5951.04,2583.5 5951.04,2569.06 5809.94,2427.96 5809.94,2403.58 5832.86,2380.66 5857.24,2380.66 5998.34,2521.76 6012.78,2521.76 6028.68,2505.86 6028.68,2491.42 5887.58,2350.32 5887.58,2325.94 5910.5,2303.02 5934.88,2303.01 6075.98,2444.12 6090.42,2444.12 6106.32,2428.22 6106.32,2413.78 6045.47,2352.94 6045.47,2328.56 6165.53,2208.5 6178.22,2195.81 6271.19,2195.81 6281,2186 6302.19,2186 6312,2195.81 6333.19,2195.81 6342,2187 6366.19,2187 6375,2195.81 6394.64,2195.81 v1(6416.44,2174.01)
F_REFCLK2_P: J51.G6 R304.2 | length 4849.8
  L1_Top Layer w6: R304.2@4433.63,4282.67 4433.63,4260.92 4455.63,4238.92 4455.63,2891.81 4681.44,2666 5773.56,2666 5779.56,2672 5787.78,2680.22 5791,2683.44 5791,2708 5807,2724 v1(5808,2724)
  L4_Signal Layer 1 w4.9: v1(5808,2724) 5792,2708 5792,2599 5840.45,2550.55 5854.89,2550.55 5915.73,2611.4 5940.11,2611.4 5963.04,2588.47 5963.04,2564.09 5821.94,2422.99 5821.94,2408.55 5837.83,2392.66 5852.27,2392.66 5993.37,2533.76 6017.75,2533.76 6040.68,2510.83 6040.68,2486.45 5899.58,2345.35 5899.58,2330.91 5915.47,2315.02 5929.91,2315.01 6071.01,2456.12 6095.39,2456.12 6118.32,2433.19 6118.32,2408.81 6057.47,2347.97 6057.47,2333.53 6170.5,2220.5 6183.19,2207.81 6400.24,2207.81 v1(6416.44,2224.01) ; v1@6415.19,2225.26 v1@6416.75,2226.81
F_SYSREF1+: R318.1 R331.2 U24.49 | length 410.4
  L1_Top Layer w6: U24.49@4738.9,5112.95 4738.9,5130.76 4734.56,5135.11 4734.56,5155 4907.41,5327.86 4907.41,5349.07 4930.79,5372.45 R331.2@4930.79,5390.26
  L1_Top Layer w10: R331.2@4930.79,5390.26 R318.1@4930.79,5440.26
F_SYSREF1-: R320.1 R330.2 U24.50 | length 410.4
  L1_Top Layer w6: U24.50@4719.22,5112.95 4719.22,5130.76 4723.56,5135.11 4723.56,5154.56 4723.56,5159.56 4852,5288 4896.41,5332.41 4896.41,5349.07 4873.03,5372.45 R330.2@4873.03,5390.26
  L1_Top Layer w10: R330.2@4873.03,5390.26 R320.1@4873.03,5440.26
F_SYSREF1_N: J46.G10 R320.2 | length 4939.6
  L1_Top Layer w6: v1(4703.81,7016) 4725,7016 4896.41,6844.59 4896.41,5532.63 4874.41,5510.63 R320.2@4874.41,5488.88
  L10_Signal Layer 2 w5.5: v1(4703.81,7016) 4722.91,7016 4766.91,6972 5001.97,6972 5091,7061.03 5091,7795.86 5073.61,7813.25 5001.36,7813.25 4991,7823.61 4991,7846.39 5001.36,7856.75 5173.61,7856.75 5191,7874.14 5191,7906.86 5173.61,7924.25 5101.36,7924.25 5091,7934.61 5091,8035.03 5392.46,8336.49 5758.49,8336.49 5762,8340 5892,8470 6129.03,8470 6210.02,8389.01 6394.11,8389.01 v1(6413.11,8370.01)
F_SYSREF1_P: J46.G9 R318.2 | length 4938
  L1_Top Layer w6: v1(4731.39,7043.58) 4731.39,7025.16 4907.41,6849.14 4907.41,5532.63 4929.41,5510.63 R318.2@4929.41,5488.88
  L10_Signal Layer 2 w5.5: v1(4731.39,7043.58) 4731.39,7024.49 4771.88,6984 4997,6984 5079,7066 5079,7790.89 5068.64,7801.25 4996.39,7801.25 4979,7818.64 4979,7851.36 4996.39,7868.75 5168.64,7868.75 5179,7879.11 5179,7901.89 5168.64,7912.25 5096.39,7912.25 5079,7929.64 5079,8040 5387.49,8348.49 5753.51,8348.49 5887.03,8482 6134,8482 6214.99,8401.01 6394.11,8401.01 v1(6413.11,8420.01)
F_SYSREF2+: R314.1 R335.2 U24.29 | length 513.2
  L1_Top Layer w6: U24.29@4679.84,4766.5 4679.84,4748.69 4684.19,4744.34 4684.19,4608.29 4842.48,4450 4842.48,4422.38 4819.1,4399 R335.2@4819.1,4381.19
  L1_Top Layer w10: R314.1@4819.1,4330.31 R335.2@4819.1,4381.19
F_SYSREF2-: R315.1 R334.2 U24.30 | length 513.2
  L1_Top Layer w6: U24.30@4699.53,4766.5 4699.53,4748.69 4695.19,4744.34 4695.19,4612.85 4853.48,4454.56 4853.48,4422.38 4876.86,4399 R334.2@4876.86,4381.19
  L1_Top Layer w10: R315.1@4876.86,4330.32 R334.2@4876.86,4381.19
F_SYSREF2_N: J51.G10 R315.2 | length 4835.1
  L1_Top Layer w6: R315.2@4875.47,4281.69 4875.47,4259.95 4853.47,4237.95 4853.47,3054.53 4931,2977 5645,2977 5655,2987 5655,3007 v1(5639,3023)
  L4_Signal Layer 1 w4.9: v1(5639,3023) 5655,3007 5655,2964.97 5561,2870.97 5561,2770.79 5578.24,2753.55 5655.79,2753.55 5666,2743.34 5666,2720.86 5655.79,2710.65 5473.24,2710.65 5456,2693.41 5456,2660.99 5473.24,2643.75 5655.79,2643.75 5666,2633.54 5666,2611.06 5655.79,2600.85 5473.24,2600.85 5456,2583.61 5456,2551.19 5473.24,2533.95 5655.79,2533.95 5666,2523.74 5666,2501.26 5655.79,2491.05 5578.24,2491.05 5561,2473.81 5561,2281.03 5635.03,2207 5936.03,2207 6097.22,2045.81 6271.19,2045.81 6281,2036 6302.19,2036 6312,2045.81 6333.19,2045.81 6342,2037 6366.19,2037 6375,2045.81 6394.64,2045.81 v1(6416.44,2024.01)
F_SYSREF2_P: J51.G9 R314.2 | length 4834.9
  L1_Top Layer w6: R314.2@4820.47,4281.69 4820.47,4259.95 4842.47,4237.95 4842.47,3049.97 4926.44,2966 5649.56,2966 5650.56,2967 5662.78,2979.22 5666,2982.44 5666,3007 5682,3023 v1(5683,3023)
  L4_Signal Layer 1 w4.9: v1(5683,3023) 5667,3007 5667,2960 5573,2866 5573,2775.76 5583.21,2765.55 5660.76,2765.55 5678,2748.31 5678,2715.89 5660.76,2698.65 5478.21,2698.65 5468,2688.44 5468,2665.96 5478.21,2655.75 5660.76,2655.75 5678,2638.51 5678,2606.09 5660.76,2588.85 5478.21,2588.85 5468,2578.64 5468,2556.16 5478.21,2545.95 5660.76,2545.95 5678,2528.71 5678,2496.29 5660.76,2479.05 5583.21,2479.05 5573,2468.84 5573,2286 5640,2219 5941,2219 6102.19,2057.81 6400.24,2057.81 v1(6416.44,2074.01)
FMC_SCL_1: J46.C30 J48.2 U36.6 | length 1594.7
  L1_Top Layer w11: J48.2@5731.21,7194.68 5675.21,7138.68 5675.21,6949.68 5791.21,6833.68 U36.6@5791.21,6776.68
  L12_Bottom Layer w5: 6056.23,7215.03 6089.21,7248.01 6627.11,7248.01 6638.11,7259.01 6638.11,7345.01 J46.C30@6613.11,7370.01
  L12_Bottom Layer w11: J48.2@5731.21,7194.68 5792.21,7133.68 5974.88,7133.68 6056.23,7215.03
FMC_SCL_2: J51.C30 J53.2 U37.6 | length 1600.7
  L1_Top Layer w11: J53.2@5730.4,841.39 5674.4,785.39 5674.4,596.39 5790.4,480.39 U37.6@5790.4,423.39
  L12_Bottom Layer w5: 6076.04,885.52 6090.34,899.81 6628.24,899.81 6641.44,913.01 6641.44,1002.12 J51.C30@6616.75,1026.81
  L12_Bottom Layer w11: J53.2@5730.4,841.39 5784.1,787.69 5978.21,787.69 6076.04,885.52 ; J53.2@5734.54,848.69 J53.2@5736.12,847.11
FMC_SDA_1: J46.C31 J48.1 U36.5 | length 1497.4
  L1_Top Layer w11: J48.1@5631.21,7194.68 5631.21,6940.68 5741.21,6830.68 U36.5@5741.21,6776.68
  L12_Bottom Layer w5: 6076.98,7278.28 6092.71,7294.01 6587.11,7294.01 J46.C31@6613.11,7320.01
  L12_Bottom Layer w11: J48.1@5631.21,7194.68 5681.21,7244.68 6043.38,7244.68 6076.98,7278.28
FMC_SDA_2: J51.C31 J53.1 U37.5 | length 1506
  L1_Top Layer w11: J53.1@5630.4,841.39 5630.4,587.39 5740.4,477.39 U37.5@5740.4,423.39
  L12_Bottom Layer w5: 6084.79,936.77 6097.84,949.81 6589.75,949.81 J51.C31@6616.75,976.81
  L12_Bottom Layer w11: J53.1@5630.4,841.39 5687.69,898.69 6046.71,898.69 6084.79,936.77
FREQ_DIV_RESET: R403.2 U58.9 | length 91.6
  L1_Top Layer w11: R403.2@3342.79,4288.29 3353.36,4277.72 U58.9@3430.04,4277.72
GND: C355.2 C364.2 C371.2 C477.2 C478.2 C480.2 C481.2 C494.2 C495.2 C496.1 C497.1 C498.1 C501.1 C509.2 C510.2 C516.2 C517.2 C518.2 C519.2 C523.2 C524.2 C537.2 C538.2 C539.1 C540.1 C541.1 C544.1 C587.2 C588.2 C589.2 C590.2 C594.2 C595.2 C600.2 C601.2 C602.1 C603.1 C604.1 C608.1 C613.2 C614.2 C615.2 C616.2 C620.2 C621.2 C643.2 C644.1 C645.1 C646.1 C647.2 C654.1 C655.2 C656.2 C657.2 C660.2 C668.2 C669.2 C690.2 C695.1 C696.1 C697.1 C705.1 C706.1 C707.1 C714.2 C715.1 C723.2 D20.2 D21.2 J58.12 J59.7 J59.9 J59.17 J59.19 J59.27 J59.29 J59.31 J60.7 J60.9 J60.11 J60.13 J60.15 J60.23 J60.25 J60.27 J60.29 J60.31 J63.7 J63.8 J63.9 J63.10 J63.11 J63.12 L57.1 L58.1 L59.1 L68.1 L69.1 L70.1 L71.1 Q3.4 Q3.7 R486.1 R488.1 R492.1 R495.1 R496.1 R497.1 R498.1 R499.1 R500.1 R504.1 R507.1 R508.1 R509.1 R510.1 R511.1 R512.1 R516.1 R519.1 R520.1 R521.1 R522.1 R523.1 R524.1 R528.1 R532.1 R533.2 R534.2 R537.1 U38.11@5004.7,11291.8 U39.3 U39.9 U40.2 U41.8 U41.18 U41.21 U42.3 U42.9 U43.2 U44.8 U44.18 U44.21 U45.3 U45.9 U46.2 U47.8 U47.18 U47.21 U48.3 U48.9 U49.2 U50.8 U50.18 U50.21 U51.4 U51.5 U52.2 U53.7 U53.21 | length 3387.3
  L1_Top Layer w8: v1(855.91,10901.1) 881.5,10875.51 U53.7@947.45,10875.51 ; C656.2@1490.22,10919.4 1544.14,10919.4 1559.1,10934.36 U50.18@1581.89,10934.36 v1(1616.34,10934.36) U50.21@1646.85,10934.36 v1(1677.36,10934.36) U50.8@1711.81,10934.36 ; C589.2@2224.09,10917.54 2266.67,10917.54 2281.63,10932.5 U44.18@2315.76,10932.5 v1(2350.21,10932.5) U44.21@2380.72,10932.5 v1(2411.24,10932.5) U44.8@2445.69,10932.5 ; C516.2@3097.92,10916.68 3140.5,10916.68 3155.46,10931.64 U41.18@3189.59,10931.64 v1(3224.04,10931.64) U41.21@3254.55,10931.64 v1(3285.06,10931.64) U41.8@3319.51,10931.64 ; C614.2@3934.9,10912.67 3977.47,10912.67 3992.43,10927.63 U47.18@4026.56,10927.63 ; v1(4061.01,10927.63) U47.21@4091.53,10927.63 v1(4122.04,10927.63) U47.8@4156.49,10927.63
  L1_Top Layer w20: R537.1@918.5,10730.19 918.5,10770.65 v2(919.42,10771.57) ; v2(1641.14,11187.4) 1641.22,11187.32 C669.2@1641.22,11133.9 ; v2(1717.14,11209.91) 1717.22,11209.83 C668.2@1717.22,11156.4 ; C595.2@2375.09,11132.03 v1(2375.09,11177.96) ; C594.2@2451.09,11154.54 2513.52,11154.54 v1(2513.59,11154.46) ; R508.1@2572.72,11009.54 R509.1@2572.72,10960.54 v2(2609.67,10960.54) ; R507.1@2572.72,11059.54 2573.64,11060.46 v2(2610.59,11060.46) ; R512.1@2572.8,10814.61 R512.1@2573.72,10815.54 v2(2610.67,10815.54) ; R511.1@2572.8,10862.61 R511.1@2573.72,10863.54 v2(2610.67,10863.54) ; R510.1@2572.8,10910.61 R510.1@2573.72,10911.54 v2(2610.67,10911.54) ; C524.2@3248.92,11131.17 v1(3248.92,11177.1) ; C523.2@3324.92,11153.68 v1@3324.92,11216.1 ; R497.1@3445.62,10958.76 R497.1@3446.54,10959.68 v2(3483.5,10959.68) ; R496.1@3445.62,11007.76 R496.1@3446.54,11008.68 v2(3483.5,11008.68) ; v2(3445.62,11096.56) 3445.62,11059.6 R495.1@3446.54,11058.68 ; R500.1@3446.62,10815.6 R500.1@3447.54,10814.68 v2(3447.54,10777.72) ; R499.1@3446.62,10861.76 R499.1@3447.54,10862.68 v2(3484.5,10862.68) ; R498.1@3446.62,10909.76 R498.1@3447.54,10910.68 v2(3484.5,10910.68) ; C621.2@4085.9,11127.17 v1(4085.9,11173.09) ; C620.2@4161.9,11149.67 v1@4217,11149.67 ; R521.1@4282.6,10954.75 R521.1@4283.52,10955.67 v2(4320.47,10955.67) ; R520.1@4282.6,11003.75 R520.1@4283.52,11004.67 v2(4320.47,11004.67) ; R519.1@4283.52,11054.67 v2(4319.7,11054.67) ; R524.1@4283.6,10809.75 R524.1@4284.52,10810.67 v2(4321.47,10810.67) ; R523.1@4283.6,10857.75 R523.1@4284.52,10858.67 v2(4321.47,10858.67) ; R522.1@4283.6,10905.75 R522.1@4284.52,10906.67 v2(4321.47,10906.67) ; v2(4695.32,11444.73) 4695.82,11444.23 C478.2@4695.82,11392.8 ; v2(4785.32,11444.73) 4785.82,11444.23 C477.2@4785.82,11392.8 ; D20.2@4878.82,11441.27 4930.24,11441.27 v2(4930.74,11441.77) ; D21.2@4938.35,11074.8 4938.35,11023.38 v2(4938.84,11022.88) ; R488.1@4993.32,11167.8 5029.68,11131.44 v2(5030.38,11131.44) ; v2(5099.82,11078.23) C481.2@5099.82,11123.31 ; v2(5162.82,11079.23) R486.1@5162.82,11124.31 ; C480.2@5290.31,11125.8 v2(5335.39,11125.8)
  L12_Bottom Layer w8: U48.9@1380.67,11266.03 U48.3@1409.21,11266.03 1432.56,11266.03 1441.58,11257.01 C509.2@1463.76,11257.01 ; U42.9@2081.49,11265.82 U42.3@2109,11265.82 2136.73,11265.82 2149.78,11252.76 C364.2@2170.76,11252.76 ; U39.9@2948.49,11265.86 U39.3@2976,11265.86 3013.16,11265.86 C355.2@3031.45,11247.58 ; U45.9@3797.49,11269.99 U45.3@3825.01,11269.99 3844.4,11269.99 3858.11,11256.28 C371.2@3883.49,11256.28
  L12_Bottom Layer w15: R533.2@549.62,11203.92 R534.2@549.62,11252.92 ; v2@588,11203.92 v2(590,11205.92)
  L12_Bottom Layer w20: R533.2@549.62,11203.92 v2@588,11203.92 ; R534.2@549.62,11252.92 582.76,11252.92 593.42,11242.26 U51.5@623.22,11242.26 ; 705.89,11229.1 U51.4@705.89,11242.26 ; C723.2@910.42,11041.57 v2(910.42,11113.57) ; v2(1506.72,10856.32) 1506.72,10850.41 R532.1@1567.72,10789.4 ; R504.1@1913.41,11335.93 R504.1@1913.41,11338.04 ; v1(2067.66,11278.61) 2067.66,11251.99 U42.9@2081.49,11265.82 ; v1(2934.66,11278.66) 2934.66,11252.04 U39.9@2948.49,11265.86 ; v1(3783.67,11282.79) 3783.67,11256.17 U45.9@3797.49,11269.99
  other v1: 855.91,10848.94 4091.53,10897.12 803.75,10901.1 908.08,10901.1 3254.55,10901.13 2380.72,10901.98 1646.85,10903.85 855.91,10953.27 4091.53,10958.14 3254.55,10962.15 2380.72,10963.01 1646.85,10964.87 4217,11150 3325,11216.18 1367.87,11249.3 2067.66,11249.09 2934.66,11249.13 3783.67,11253.26 5004.7,11254.4 1367.87,11278.83 4982.06,11291.8 5027.34,11291.8 2067.66,11308.14 2934.66,11308.19 1367.87,11308.36 3783.67,11312.32 5004.7,11329.21
  other v2: 578,10402 617,10402 656,10402 1077,10402 1116,10402 1155,10402 1283,10402 1322,10402 1361,10402 1400,10402 1439,10402 2142,10402 2181,10402 2220,10402 2259,10402 2298,10402 2736,10402 2775,10402 2814,10402 3236,10402 3275,10402 3314,10402 283,10435 322,10435 361,10435 400,10435 439,10435 3658.73,10511.73 1215.93,10516 2821.51,10515.64 1949.93,10516.6 403.93,10520 3658.73,10559.73 1215.93,10564 2821.51,10563.64 1949.93,10564.6 403.93,10568 3658.73,10607.73 1215.93,10612 2821.51,10611.64 1949.93,10612.6 403.93,10616 3658.73,10655.73 1215.93,10660 2821.51,10659.64 1949.93,10660.6 403.93,10664 3658.73,10703.73 1215.93,10708 2821.51,10707.64 1949.93,10708.6 403.93,10712 3816.4,10849.59 3861.4,10849.59 3906.4,10849.59 3951.4,10849.59 2979.42,10853.6 3024.42,10853.6 3069.42,10853.6 3114.42,10853.6 2105.59,10854.46 2150.59,10854.46 2195.59,10854.46 2240.59,10854.46 1371.72,10856.32 1416.72,10856.32 1461.72,10856.32 526,10886 574,10886 622,10886 1470.79,11115 1520.7,11114.94 2189.1,11127.06 2239,11127 3053,11127 3102.9,11126.94 3902.01,11131.13 3951.91,11131.07 641,11135.92 690.9,11135.87 1470.79,11160 1520.7,11159.94 2189.1,11172.06 2239,11172 3053,11172 3102.9,11171.94 3902.01,11176.13 3951.91,11176.07 641,11180.92 690.9,11180.87
GND1: C479.2 D19.1 J55.2 J55.3 Q3.1 Q3.2 Q3.5 Q3.6 Q3.8 TP20.1 | length 85.8
  L1_Top Layer w11: Q3.5@5038.41,11404.03 5038.41,11387.23 5048.02,11377.62 ; Q3.2@5038.41,11480.8 5038.41,11536.23
HSPC_PRSNT_M2C_L_1: J46.Z1 J49.1 | length 279.9
  L1_Top Layer w11: J49.1@6690.81,9070.01 6690.81,8892.31 v1(6763.11,8820.01)
HSPC_PRSNT_M2C_L_2: J51.Z1 J54.1 | length 279.9
  L1_Top Layer w11: J54.1@6694.45,2726.81 6694.45,2549.11 v1@6766.75,2476.81
  other v1: 6766.44,2474.01
ILIM: R487.2 U38.10 | length 94.9
  L1_Top Layer w10: R487.2@4863.82,11230.3 4897.9,11230.3 4920.03,11252.43 U38.10@4949.58,11252.43
IN1_N: C13.1 C490.2 J13.1 R8.1 | length 439.4
  L1_Top Layer w11: J13.1@101.27,9206.79 J13.1@109,9206.79 245.49,9206.79 R8.1@382.88,9069.4 ; C13.1@347.21,9032.69 382.88,9068.37 R8.1@382.88,9069.4 ; C490.2@418.21,9103.49 384.12,9069.4 R8.1@382.88,9069.4
IN1_P: C14.1 C491.1 C492.1 J14.1 R12.1 | length 491.4
  L1_Top Layer w11: J14.1@100.12,8650.69 J14.1@109,8650.69 243.61,8650.69 R12.1@382.21,8789.29 ; C14.1@347.21,8824.29 R12.1@382.21,8789.29 ; C492.1@378.61,8716.49 C491.1@416.21,8754.08 416.21,8755.29 R12.1@382.21,8789.29
IN2_N: C47.1 C493.2 J30.1 R32.1 | length 438.6
  L1_Top Layer w10: J30.1@103.92,7784.66 J30.1@105.07,7784.66
  L1_Top Layer w11: J30.1@105.07,7784.66 J30.1@109,7784.66 247.29,7784.66 R32.1@384.68,7647.27 ; C47.1@349.01,7610.57 384.68,7646.24 R32.1@384.68,7647.27 ; C493.2@420.01,7681.36 385.91,7647.27 R32.1@384.68,7647.27
IN2_P: C48.1 C499.1 C500.1 J73.1 R36.1 | length 491.8
  L1_Top Layer w10: J73.1@101.92,7228.57 J73.1@105.07,7228.57 ; R36.1@384.01,7365.95 R36.1@384.01,7367.16
  L1_Top Layer w11: J73.1@105.07,7228.57 J73.1@109,7228.57 245.41,7228.57 R36.1@384.01,7367.16 C48.1@349.01,7402.16 ; C500.1@380.01,7294.36 380.41,7294.36 C499.1@418.01,7331.95 R36.1@384.01,7365.95
IN3_N: C173.1 C502.2 J76.1 R89.1 | length 437.4
  L1_Top Layer w11: J76.1@105.36,2860.42 J76.1@109,2860.42 247.58,2860.42 R89.1@384.97,2723.03 ; C173.1@350.52,2686.33 386.2,2722.01 R89.1@386.2,2723.03 387.43,2723.03 C502.2@421.52,2757.13
IN3_P: C174.1 C503.1 C504.1 J77.1 R93.1 | length 488.7
  L1_Top Layer w11: J77.1@105.36,2304.33 J77.1@109,2304.33 245.7,2304.33 R93.1@384.29,2442.92 ; C174.1@350.52,2477.93 R93.1@385.52,2442.93 419.52,2408.92 C503.1@419.52,2407.72 381.93,2370.13 C504.1@381.52,2370.13
IN4_N: C207.1 C505.2 J80.1 R113.1 | length 437.4
  L1_Top Layer w11: J80.1@105.43,1440.06 109,1440.06 247.65,1440.06 R113.1@385.04,1302.67 ; C207.1@350.6,1267 386.27,1302.67 R113.1@386.27,1303.7 387.51,1303.7 C505.2@421.6,1337.79
IN4_P: C208.1 C506.1 C507.1 J81.1 R117.1 | length 488.7
  L1_Top Layer w11: J81.1@105.43,883.97 109,883.97 245.77,883.97 R117.1@384.37,1022.56 ; C208.1@350.6,1058.59 R117.1@385.6,1023.59 419.6,989.59 C506.1@419.6,988.38 382.01,950.79 C507.1@381.6,950.79
IOVLVL: R597.2 U24.7 | length 5507.4
  L1_Top Layer w10: v1(4352,4929) 4363,4929 4403.25,4969.25 U24.7@4418.03,4969.25
  L1_Top Layer w11: v2(4088,9891) 4090,9889 R597.2@4200.5,9889
  L10_Signal Layer 2 w6.5: v2(4088,9891) 4105,9874 4105,9583 4076,9554 4076,7424 4001,7349 4001,6856 4521,6336 4521,5795.48 4455,5729.48 4455,5173.12 4341,5059.12 4341,4939.89 4351.89,4929 v1(4352,4929) 4355.28,4929 v1@4356.28,4928
LDO_PG_1P9V: R389.1 R493.2 U41.4 | length 1401
  L1_Top Layer w10: U41.4@3274.24,10866.68 3274.24,10851.48 3294.34,10831.37 v2(3314.19,10831.37) 3316.92,10828.64 R493.2@3316.92,10785.17
  L12_Bottom Layer w11: v1(2175.69,11080.86) 2216.54,11040 2558,11040 2587.93,11010.07 2665.93,11010.07 2903,10773 3255.82,10773 v2(3314.19,10831.37)
LMH_CLK: U27.6 U34.48 | length 528.3
  L1_Top Layer w11: U34.48@5083.38,9736.33 5083.38,9272.62 5100.41,9255.59 U27.6@5140.96,9255.59
LMH_CS1: U27.3 U34.54 | length 561.5
  L1_Top Layer w11: U27.3@5140.96,9178.81 5189.81,9178.81 5225,9214 5225,9583.12 5252.67,9610.8 U34.54@5252.67,9665.47
LMH_CS2: U29.5 U34.55 | length 492.1
  L1_Top Layer w11: U34.55@5272.36,9665.47 5272.36,9602.36 5242,9572 5242,9303 v2(5279,9266)
  L12_Bottom Layer w11: v2(5279,9266) 5279.2,9265.8 U29.5@5343.68,9265.8
LMH_CS3: U29.4 U34.57 | length 617.3
  L1_Top Layer w11: v2(5266,9454) 5266,9568 5311.73,9613.73 U34.57@5311.73,9665.47
  L12_Bottom Layer w11: v2(5266,9454) 5357,9454 5413,9398 5413,9258 5395.2,9240.2 U29.4@5343.68,9240.2
LMH_CS4: U29.3 U34.58 | length 628.3
  L1_Top Layer w11: v2(5292,9489) 5292,9564 5331.41,9603.41 U34.58@5331.41,9665.47
  L4_Signal Layer 1 w5.5: v2(5292,9489) v2@5292,9490
  L12_Bottom Layer w11: v2(5292,9489) 5349,9489 5432,9406 5432,9248 5398.61,9214.61 U29.3@5343.68,9214.61
LMH_CSX1: J85.4 U34.59 | length 1077.8
  L1_Top Layer w11: v2(5340.19,9726.93) 5351.1,9716.03 U34.59@5351.1,9665.47
  L10_Signal Layer 2 w6.5: J85.4@5185,10663 5354,10494 5354,9740.74 v2(5340.19,9726.93)
LMH_SDI: U27.5 U34.52 | length 484.2
  L1_Top Layer w11: U27.5@5140.96,9230 5173,9230 5188,9245 5188,9594.21 5213.3,9619.51 U34.52@5213.3,9665.47
LMH_SDO: U27.4 U34.53 | length 519.9
  L1_Top Layer w11: U27.4@5140.96,9204.4 5176.4,9204.4 5205,9233 5205,9587.17 5232.99,9615.15 U34.53@5232.99,9665.47
LMK00304_STS: R550.1 U34.33 U58.13 | length 7735.8
  L1_Top Layer w11: v2(3323,4242) 3323.18,4241.82 R550.1@3323.18,4183.24 3331.06,4175.36 U58.13@3430.04,4175.36 ; v2(4410,10014) 4411,10014 4562,10165 5004,10165 5083.38,10085.62 U34.33@5083.38,10031.61
  L10_Signal Layer 2 w6.5: v2(3323,4242) 3126,4439 3126,5175 2890.5,5410.5 2890.5,6550.5 3088,6748 3088,7484 4036,8432 4036,9919 4131,10014 v2(4410,10014)
LMK04828_SYNC1: J46.J15 R586.2 | length 221.1
  L1_Top Layer w11: R586.2@6102.73,8146.01 6287.11,8146.01 v1(6313.11,8120.01)
LMK04828_SYNC2: J51.J15 R590.1 | length 221.1
  L1_Top Layer w11: R590.1@6106.37,1802.81 6290.75,1802.81 v1@6316.75,1776.81
  other v1: 6316.44,1774.01
LMK_ADC1_DCLKM: C99.2 C396.2 R197.1 | length 4856.9
  L4_Signal Layer 1 w4.9: v1(2008.17,8157.76) 1946.92,8219 1910.97,8219 1882,8190.03 1882,8173 1896,8159 1896,8145 1882,8131 1882,8116 1896,8102 1896,8088 1882,8074 1882,8058 1895,8045 1895,8029 1882,8016 1882,8001 1895,7988 1895,7972 1882,7959 1882,7944 1896,7930 1896,7916 1882,7902 1882,7885 1896,7871 1896,7857 1882,7843 1882,7823 1896,7809 1896,7791 1882,7777 1882,7065.97 2291.97,6656 2954.97,6656 2957.97,6653 3704,5906.97 3704,5144 3812,5036 3923,5036 3943,5056 3943,5127 3934.06,5135.94 3915.35,5135.94 v1(3893.85,5114.44)
LMK_ADC1_DCLKP: C90.2 C394.2 R195.1 | length 4856.9
  L4_Signal Layer 1 w4.9: v1(2008.17,8292.24) 1946.92,8231 1906,8231 1870,8195 1870,7061 2287,6644 2950,6644 3692,5902 3692,5139.03 3807.03,5024 3927.97,5024 3955,5051.03 3955,5131.97 3939.03,5147.94 3915.35,5147.94 v1(3893.85,5169.44)
LMK_ADC1_SYSREF_M: C95.1 R200.1 R201.1 R280.2 U20.3 | length 8900.1
  L4_Signal Layer 1 w4.9: v1(2103.89,8024.57) 2103.89,8084.77 2092.97,8095.69 2018.66,8095.69 1979.97,8057 1979.97,7129 2296.97,6812 2387.74,6812 2395.45,6819.71 2395.45,6879.76 2410.19,6894.5 2437.61,6894.5 2452.35,6879.76 2452.35,6737.21 2460.06,6729.5 2477.54,6729.5 2485.25,6737.21 2485.25,6879.76 2499.99,6894.5 2527.41,6894.5 2542.15,6879.76 2542.15,6737.21 2549.86,6729.5 2567.34,6729.5 2575.05,6737.21 2575.05,6797.26 2589.79,6812 2879,6812 3799,5892 3799,5350 3893,5256 4038.97,5256 4042.49,5252.49 4111,5183.97 4111,4990.3 4091.97,4971.27 4071.29,4971.27 v1(4054.79,4954.77)
  L12_Bottom Layer w6: U20.3@1482.81,5636.03 1483.28,5635.57 R201.1@1483.28,5559.32 1483.28,5541.51 1465.16,5523.38 1465.16,5384.84 1514,5336 2953,5336 3048,5241 3433,5241 3497.02,5176.98 3508.73,5176.98 3549.03,5217.28 3569.85,5217.28 3589.34,5197.8 3589.34,5176.98 3549.03,5136.67 3549.03,5124.97 3634,5040 3696.22,5040 3704.5,5048.28 3704.5,5109.28 3719.22,5124 3746.78,5124 3761.5,5109.28 3761.5,4964.28 3769.78,4956 3788.22,4956 3796.5,4964.28 3796.5,5025.28 3811.22,5040 4089.56,5040 4106.51,5023.05 4109.73,5019.82 4109.73,4988.44 4106.51,4985.22 4093.06,4971.77 4071.79,4971.77 v1(4054.79,4954.77)
  L12_Bottom Layer w11: U20.3@1482.81,5636.03 R200.1@1482.81,5706.9
LMK_ADC1_SYSREF_P: C94.1 R201.2 R277.2 U20.4 | length 8834
  L4_Signal Layer 1 w4.9: v1(2103.89,8178.81) 2103.89,8118.61 2092.97,8107.69 2013.69,8107.69 1967.97,8061.97 1967.97,7124.03 2292,6800 2392.71,6800 2407.45,6814.74 2407.45,6874.79 2415.16,6882.5 2432.64,6882.5 2440.35,6874.79 2440.35,6732.24 2455.09,6717.5 2482.51,6717.5 2497.25,6732.24 2497.25,6874.79 2504.96,6882.5 2522.44,6882.5 2530.15,6874.79 2530.15,6732.24 2544.89,6717.5 2572.31,6717.5 2587.05,6732.24 2587.05,6792.29 2594.76,6800 2874.03,6800 3787,5887.03 3787,5345.03 3790.51,5341.51 3888.03,5244 4034,5244 4099,5179 4099,4995.27 4087,4983.27 4071.29,4983.27 v1(4054.79,4999.77)
  L12_Bottom Layer w6: U20.4@1432.81,5636.03 1436.04,5632.81 R201.2@1436.04,5559.32 1436.04,5541.51 1454.16,5523.38 1454.16,5509 1442,5496.84 1442,5475.16 1454.16,5463 1454.16,5447 1440,5432.84 1440,5414.16 1454.16,5400 1454.16,5380.29 1509.44,5325 2948.44,5325 3043.44,5230 3428.44,5230 3492.46,5165.98 3513.28,5165.98 3553.59,5206.28 3565.3,5206.28 3578.34,5193.24 3578.34,5181.54 3538.03,5141.23 3538.03,5120.41 3629.44,5029 3700.78,5029 3715.5,5043.72 3715.5,5104.72 3723.78,5113 3742.22,5113 3750.5,5104.72 3750.5,4959.72 3765.22,4945 3792.78,4945 3807.5,4959.72 3807.5,5020.72 3815.78,5029 4085,5029 4098.73,5015.27 4098.73,4993 4088.5,4982.77 4071.79,4982.77 v1(4054.79,4999.77)
LMK_ADC2_DCLKM: C259.2 C402.2 R238.1 | length 5018.4
  L4_Signal Layer 1 w4.9: v1(2011.5,1810.35) 1950.25,1871.6 1907.29,1871.6 1883.77,1895.11 1880.26,1898.63 1880.26,2336.26 2065,2521 2386,2521 2849,2984 2849,3311.97 3128.51,3591.49 3132.03,3595 3867.03,3595 4123,3850.97 4123,4087.11 4137.74,4101.85 4205.79,4101.85 4213.5,4109.56 4213.5,4127.04 4205.79,4134.75 4047.24,4134.75 4032.5,4149.49 4032.5,4176.91 4047.24,4191.65 4205.79,4191.65 4213.5,4199.36 4213.5,4216.84 4205.79,4224.55 4137.74,4224.55 4123,4239.29 4123,4660 4116.48,4666.52 4101.35,4666.52 v1(4082.35,4647.52)
LMK_ADC2_DCLKP: C250.2 C401.2 R236.1 | length 5018.4
  L4_Signal Layer 1 w4.9: v1(2011.5,1944.84) 1950.25,1883.6 1912.26,1883.6 1892.26,1903.6 1892.26,2331.29 2069.97,2509 2390.97,2509 2861,2979.03 2861,3307 3137,3583 3872,3583 4135,3846 4135,4082.14 4142.71,4089.85 4210.76,4089.85 4225.5,4104.59 4225.5,4132.01 4210.76,4146.75 4052.21,4146.75 4044.5,4154.46 4044.5,4171.94 4052.21,4179.65 4210.76,4179.65 4225.5,4194.39 4225.5,4221.81 4210.76,4236.55 4142.71,4236.55 4135,4244.26 4135,4664.97 4121.45,4678.52 4101.35,4678.52 v1(4082.35,4697.52)
LMK_ADC2_SYSREF_M: C255.1 R239.1 R240.1 R295.2 U22.3 | length 8615.4
  L4_Signal Layer 1 w4.9: v1(2108.76,1677.75) 2108.76,1737.5 2096.89,1749.37 2047,1749.37 1880.72,1749.37 1818.26,1811.83 1818.26,2383.23 2040.03,2605 2365,2605 2786,3026 2786,3362.97 3085.03,3662 3151.03,3728 3778.03,3728 3939.5,3889.47 3939.5,4433.91 3954.24,4448.65 4049.29,4448.65 4057,4456.36 4057,4473.84 4049.29,4481.55 3954.24,4481.55 3939.5,4496.29 3939.5,4822.92 3927.99,4834.44 3904.85,4834.44 v1(3885.85,4815.44)
  L12_Bottom Layer w6: R240.1@3067.84,4261.16 3067.84,4278.97 3085.96,4297.09 3085.96,4317.51 3073,4330.47 3073,4351.56 3085.96,4364.51 3085.96,4380.51 3075,4391.47 3075,4415.56 3104.22,4444.78 3107.44,4448 3178.56,4448 3181.78,4444.78 3196.78,4429.78 3200,4426.56 3200,3970.56 3230.78,3939.78 3847.78,3939.78 3934.14,4026.14 3934.14,4248.78 3948.86,4263.5 4028.36,4263.5 4036.64,4271.78 4036.64,4290.22 4028.36,4298.5 3846.36,4298.5 3831.64,4313.22 3831.64,4340.78 3846.36,4355.5 4028.36,4355.5 4036.64,4363.78 4036.64,4382.22 4028.36,4390.5 3846.36,4390.5 3831.64,4405.22 3831.64,4432.78 3846.36,4447.5 4028.36,4447.5 4036.64,4455.78 4036.64,4474.22 4028.36,4482.5 3948.86,4482.5 3934.14,4497.22 3934.14,4820.94 3920.14,4834.94 3905.35,4834.94 v1(3885.85,4815.44) ; U22.3@3068.8,4181.94 R240.1@3068.8,4260.19
  L12_Bottom Layer w11: R239.1@3067.83,4111.57 U22.3@3067.83,4180.97
LMK_ADC2_SYSREF_P: C254.1 R240.2 R293.2 U22.4 | length 8541.6
  L4_Signal Layer 1 w4.9: v1(2108.76,1833) 2108.76,1773.25 2096.89,1761.37 1996,1761.37 1885.69,1761.37 1830.26,1816.8 1830.26,2378.26 2045,2593 2369.97,2593 2798,3021.03 2798,3358 3156,3716 3783,3716 3951.5,3884.5 3951.5,4428.94 3959.21,4436.65 4054.26,4436.65 4069,4451.39 4069,4478.81 4054.26,4493.55 3959.21,4493.55 3951.5,4501.26 3951.5,4827.89 3932.96,4846.44 3904.85,4846.44 v1(3885.85,4865.44)
  L12_Bottom Layer w6: R240.2@3115.08,4261.16 3115.08,4278.97 3096.96,4297.09 3096.96,4421.96 3112,4437 3174,4437 3189,4422 3189,3966 3223,3932 3226.22,3928.78 3852.33,3928.78 3855.56,3932 3945.14,4021.58 3945.14,4244.22 3953.42,4252.5 4032.92,4252.5 4047.64,4267.22 4047.64,4294.78 4032.92,4309.5 3850.92,4309.5 3842.64,4317.78 3842.64,4336.22 3850.92,4344.5 4032.92,4344.5 4047.64,4359.22 4047.64,4386.78 4032.92,4401.5 3850.92,4401.5 3842.64,4409.78 3842.64,4428.22 3850.92,4436.5 4032.92,4436.5 4047.64,4451.22 4047.64,4478.78 4032.92,4493.5 3953.42,4493.5 3945.14,4501.78 3945.14,4825.5 3924.7,4845.94 3905.35,4845.94 v1(3885.85,4865.44) ; U22.4@3118.8,4181.94 R240.2@3118.8,4257.43
LMK_CLKIN: J28.1 R301.1 R307.2 | length 250
  L1_Top Layer w11: R301.1@5430.87,4433.5 5460.37,4404 R307.2@5461,4404 J28.1@5607.84,4257.16
LMK_CS: R451.1 U34.40 | length 152.6
  L1_Top Layer w11: R451.1@4935.38,9910.97 R451.1@4937.81,9910.97 ; R451.1@4937.81,9905 4949,9893.81 U34.40@5083.38,9893.81
LMK_EXT_SYNC: R229.1 R601.1 | length 8192.5
  L1_Top Layer w11: v2(4062,9588) R601.1@4199.01,9588
  L10_Signal Layer 2 w6.5: v2(4062,9588) 4063.5,9586.5 4063.5,7437.5 3984,7358 3984,6849 4501,6332 4501,5801.93 4174.81,5475.74 4173.74,5475.74 4116,5418 4116,4542 v1(4189,4469)
  L12_Bottom Layer w11: v1(4189,4469) 4189,4303 4142,4256 4142,3564 4231.38,3474.62 R229.1@5679,3474.62
LMK_LMX_SCK: R445.1 U34.38 | length 186.9
  L1_Top Layer w11: R445.1@4937.81,10033 5037.63,9933.18 U34.38@5083.38,9933.18
LMK_SDIO_LMX_SDI: R447.1 U34.39 | length 171
  L1_Top Layer w11: R447.1@4935.38,9974.97 R447.1@4937.81,9974.97 ; R447.1@4937.81,9969 4977,9969 5032.5,9913.5 U34.39@5083.38,9913.5
LMX1_CLKM: C93.2 R168.1 U19.22 | length 2878.9
  L1_Top Layer w6: U19.22@2283.76,6253.99 2283.76,6271.8 2279.41,6276.14 2279.41,6315.31 2291.82,6327.71 R168.1@2291.82,6343.55 2291.82,6359.39 2279.27,6371.94 2279.27,6492.09 v1(2294.77,6507.59)
  L12_Bottom Layer w6: C93.2@2055.41,8205 2077.16,8205 2091.66,8219.5 2109.56,8219.5 2125,8234.94 2125,8258.56 2053.56,8330 1855.44,8330 1788,8262.56 1788,6869 2203,6454 2262,6454 2279.27,6471.27 2279.27,6492.09 v1(2294.77,6507.59)
LMX1_CLKP: C92.2 R164.1 U19.23 | length 2878.7
  L1_Top Layer w6: v1(2252.77,6507.59) 2268.27,6492.09 2268.27,6372.26 2255.73,6359.71 R164.1@2255.73,6343.87 2255.73,6328.03 2268.41,6315.34 2268.41,6276.14 2264.07,6271.8 U19.23@2264.07,6253.99
  L12_Bottom Layer w6: C92.2@2055.41,8245 2077.16,8245 2091.66,8230.5 2105,8230.5 2114,8239.5 2114,8254 2049,8319 1860,8319 1799,8258 1799,6873.56 1862.56,6810 1887,6810 1897,6800 1897,6775.56 1907.56,6765 1932,6765 1943.16,6753.84 1943.16,6729.4 1954.47,6718.08 1975.69,6718.08 1987,6706.77 1987,6685.56 2008.93,6663.63 2030.14,6663.63 2042.16,6651.61 2042.16,6630.4 2053.47,6619.08 2074.69,6619.08 2086,6607.77 2086,6586.56 2101.48,6571.07 2122.69,6571.07 2134.72,6559.05 2134.72,6537.84 2146.03,6526.53 2167.24,6526.53 2178.56,6515.21 2178.56,6494 2207.56,6465 2257.44,6465 2268.27,6475.83 2268.27,6492.09 v1(2252.77,6507.59)
LMX1_CS: R452.1 U34.41 | length 158.9
  L1_Top Layer w11: R452.1@4937.81,9842 4969,9842 5001.13,9874.13 U34.41@5083.38,9874.13
LMX1_REFN: R203.1 R255.2 R256.1 R258.2 | length 1443.1
  L1_Top Layer w6: v2(2789.09,5047.33) 2804.04,5062.29 2888.81,5062.29 2911.69,5039.41 2920.59,5039.41 2923.76,5042.58 2929.5,5042.58 2981,5042.58 R255.2@2983.38,5042.58
  L4_Signal Layer 1 w4.9: v1(2301.31,5429.94) 2282.71,5411.34 2282.71,5377.29 2300.5,5359.5 2526.74,5359.5 2534.45,5367.21 2534.45,5496.76 2549.19,5511.5 2576.61,5511.5 2591.35,5496.76 2591.35,5367.21 2599.06,5359.5 2798.47,5359.5 2848,5309.97 2848,5083.11 2825.72,5060.83 2802.59,5060.83 v2(2789.09,5047.33)
LMX1_REFP: R185.2 R252.1 R254.2 R259.2 | length 1443.4
  L1_Top Layer w6: v2(2789.09,5086.33) 2802.13,5073.29 2888.81,5073.29 2911.69,5096.17 R259.2@2929.5,5096.17 2930,5096.67 R252.1@2982,5096.67
  L4_Signal Layer 1 w4.9: v1(2252.11,5430.25) 2270.71,5411.65 2270.71,5372.32 2292.01,5351.01 2295.53,5347.5 2339,5347.5 2352.5,5334 2372.5,5334 2386,5347.5 2402,5347.5 2416.5,5333 2433.5,5333 2448,5347.5 2531.71,5347.5 2546.45,5362.24 2546.45,5491.79 2554.16,5499.5 2571.64,5499.5 2579.35,5491.79 2579.35,5362.24 2594.09,5347.5 2793.5,5347.5 2836,5305 2836,5088.08 2820.75,5072.83 2802.59,5072.83 v2(2789.09,5086.33)
LMX1_SYNC: R178.2 R193.1 U20.7 | length 800.8
  L12_Bottom Layer w11: R193.1@1532.81,5753.77 U20.7@1532.81,5825.01 1532.81,5983.47 1570.16,6020.82 2065.39,6020.82 R178.2@2081.69,6004.52
LMX1_SYSREFREQ: R184.2 R200.2 U20.6 | length 933.2
  L12_Bottom Layer w11: R200.2@1482.81,5754.14 U20.6@1482.81,5825.01 1482.81,5986.87 1680.66,6184.72 2084.13,6184.72 R184.2@2096.31,6196.9
LMX2_CLKM: C253.2 R209.1 U21.22 | length 2893.9
  L1_Top Layer w6: v1(2256.84,3310.39) 2272.34,3325.89 2272.34,3446.04 2259.8,3458.58 R209.1@2259.8,3474.42 2259.8,3490.27 2272.2,3502.67 2272.2,3541.83 2267.86,3546.17 U21.22@2267.86,3563.98
  L12_Bottom Layer w6: C253.2@2058.74,1857.6 2080.49,1857.6 2094.99,1872.1 2112.65,1872.1 2125.78,1885.22 2129,1888.44 2129,1911.56 2125.78,1914.78 2069,1971.56 2069,2123.56 2019,2173.56 2019,2728 1930,2817 1930,2900.22 1938.28,2908.5 2088.28,2908.5 2103,2923.22 2103,2950.78 2088.28,2965.5 1938.28,2965.5 1930,2973.78 1930,3050.22 1938.28,3058.5 2088.28,3058.5 2103,3073.22 2103,3100.78 2088.28,3115.5 1938.28,3115.5 1930,3123.78 1930,3194 2019.93,3283.93 2053.16,3317.16 ; v1(2256.84,3310.39) 2272.34,3325.89 2272.34,3354.66 2250,3377 2184,3377 2175,3368 2154,3368 2145,3377 2113,3377 2097,3361 2097,3342 2083.47,3328.47 2064.47,3328.47 ; 2053.16,3317.16 2064.47,3328.47 ; 2053.16,3317.16 2064.47,3328.47
LMX2_CLKP: C252.2 R205.1 U21.23 | length 2877.7
  L1_Top Layer w6: U21.23@2287.55,3563.98 2287.55,3546.17 2283.2,3541.83 2283.2,3502.63 2295.89,3489.95 R205.1@2295.89,3474.1 2295.89,3458.26 2283.34,3445.72 2283.34,3325.89 v1(2298.84,3310.39)
  L12_Bottom Layer w6: C252.2@2058.74,1897.6 2080.49,1897.6 2094.99,1883.1 2108.1,1883.1 2118,1893 2118,1907 2058,1967 2058,2119 2008,2169 2008,2723.44 1919,2812.44 1919,2904.78 1933.72,2919.5 2083.72,2919.5 2092,2927.78 2092,2946.22 2083.72,2954.5 1933.72,2954.5 1919,2969.22 1919,3054.78 1933.72,3069.5 2083.72,3069.5 2092,3077.78 2092,3096.22 2083.72,3104.5 1933.72,3104.5 1919,3119.22 1919,3198.56 2108.44,3388 2254.56,3388 2283.34,3359.21 2283.34,3325.89 v1(2298.84,3310.39)
LMX2_CS: R454.1 U34.45 | length 180.5
  L1_Top Layer w11: R454.1@4935.38,9722.97 R454.1@4937.81,9722.97 ; R454.1@4937.81,9717 4951.96,9717 5030.35,9795.39 U34.45@5083.38,9795.39
LMX2_REFN: R244.1 R264.2 R265.1 R268.2 | length 1443.8
  L1_Top Layer w6: v2(2788.59,4845.83) 2803.54,4860.79 2888.31,4860.79 2911.19,4837.91 2929,4837.91 2929.5,4837.41 2930,4836.91 R265.1@2980,4836.91
  L4_Signal Layer 1 w4.9: v1(2248.66,4387.84) 2268.16,4407.34 2268.16,4848.13 2322.03,4902 2672.03,4902 2728.03,4958 2827,4958 2851,4934 2851,4881.61 2828.72,4859.33 2802.09,4859.33 v2(2788.59,4845.83)
LMX2_REFP: R226.2 R260.1 R262.2 R269.2 | length 1443.9
  L1_Top Layer w6: v2(2788.59,4884.83) 2801.63,4871.79 2888.31,4871.79 2911.19,4894.67 R269.2@2929,4894.67 2933,4890.67 R260.1@2981,4890.67
  L4_Signal Layer 1 w4.9: v1(2299.16,4387.35) 2280.16,4406.34 2280.16,4436 2291.16,4447 2291.16,4471 2280.16,4482 2280.16,4498 2292.16,4510 2292.16,4533 2280.16,4545 2280.16,4568 2292.16,4580 2292.16,4603 2280.16,4615 2280.16,4631 2291.16,4642 2291.16,4666 2280.16,4677 2280.16,4697 2292.16,4709 2292.16,4732 2280.16,4744 2280.16,4761 2292.16,4773 2292.16,4796 2280.16,4808 2280.16,4843.16 2327,4890 2677,4890 2733,4946 2822.03,4946 2839,4929.03 2839,4886.58 2823.75,4871.33 2802.09,4871.33 v2(2788.59,4884.83)
LMX2_SYNC: R219.2 R234.1 U22.7 | length 800.8
  L12_Bottom Layer w11: R219.2@2469.93,3813.45 2486.22,3797.16 2981.46,3797.16 3018.8,3834.5 U22.7@3018.8,3992.97 R234.1@3018.8,4064.21
LMX2_SYSREFREQ: R225.2 R239.2 U22.6 | length 934.1
  L12_Bottom Layer w11: R225.2@2455.3,3621.08 2467.49,3633.26 2870.96,3633.26 3068.8,3831.1 U22.6@3068.8,3992.97 3067.83,3993.94 R239.2@3067.83,4064.32
LMX_ADC1_SYSREF_M: C325.1 R180.1 U19.19 | length 2672
  L1_Top Layer w6: U19.19@2329.03,6208.71 2346.84,6208.71 2351.18,6204.37 2390.38,6204.37 2403.07,6217.06 R180.1@2418.91,6217.06 2434.75,6217.06 2447.3,6204.51 2545.3,6204.51 2650.1,6309.32 2701.66,6309.32 v1(2717.16,6324.82)
  L12_Bottom Layer w6: v1(2056.89,8077.19) 2037.89,8096.19 2017,8096.19 1979.97,8059.16 1979.97,7136.03 2545.93,6570.07 2567.14,6570.07 2579.16,6558.05 2579.16,6536.84 2590.47,6525.53 2611.69,6525.53 2623,6514.21 2623,6493 2641,6475 2641,6413 2656,6398 2656,6381 2641,6366 2641,6346.56 2678.24,6309.32 2701.66,6309.32 v1(2717.16,6324.82)
LMX_ADC1_SYSREF_P: C321.1 R175.2 U19.18 | length 2672.5
  L1_Top Layer w6: U19.18@2329.03,6189.03 2346.84,6189.03 2351.18,6193.37 2390.35,6193.37 2402.75,6180.97 R175.2@2418.59,6180.97 2434.43,6180.97 2443.76,6190.29 2446.98,6193.51 2549.85,6193.51 2654.66,6298.32 2701.66,6298.32 v1(2717.16,6282.82)
  L12_Bottom Layer w6: v1(2058.26,8126.19) 2039.26,8107.19 2012.44,8107.19 1968.97,8063.71 1968.97,7131.48 2630,6470.44 2630,6342 2673.68,6298.32 2701.66,6298.32 v1(2717.16,6282.82)
LMX_ADC2_SYSREF_M: C341.1 R221.1 U21.19 | length 2673.7
  L1_Top Layer w6: v1(1834.46,3493.16) 1849.96,3508.66 1901.51,3508.66 2006.32,3613.46 2104.32,3613.46 2116.86,3600.92 R221.1@2132.7,3600.92 2148.55,3600.92 2161.23,3613.6 2200.43,3613.6 2204.77,3609.26 U21.19@2222.59,3609.26
  L12_Bottom Layer w6: v1(1834.46,3493.16) 1849.96,3508.66 1868.34,3508.66 1875.67,3501.33 1875.67,3350.22 1758,3232.56 1758,2677.44 1814,2621.44 1814,2076.78 1805.72,2068.5 1748.72,2068.5 1734,2053.78 1734,2026.22 1748.72,2011.5 1805.72,2011.5 1814,2003.22 1814,1816.44 1819,1811.44 1880.25,1750.19 2042.59,1750.19 v1(2061.59,1731.19)
LMX_ADC2_SYSREF_P: C334.1 R216.2 U21.18 | length 2673.5
  L1_Top Layer w6: v1(1834.46,3535.16) 1849.96,3519.66 1896.96,3519.66 2001.76,3624.46 2104.64,3624.46 2107.86,3627.68 2117.18,3637.01 R216.2@2133.02,3637.01 2148.87,3637.01 2161.27,3624.6 2200.43,3624.6 2204.77,3628.95 U21.18@2222.59,3628.95
  L12_Bottom Layer w6: v1(1834.46,3535.16) 1849.96,3519.66 1872.9,3519.66 1886.67,3505.89 1886.67,3345.67 1769,3228 1769,2682 1825,2626 1825,2072.22 1810.28,2057.5 1753.28,2057.5 1745,2049.22 1745,2030.78 1753.28,2022.5 1810.28,2022.5 1825,2007.78 1825,1821 1884.81,1761.19 2042.59,1761.19 v1(2061.59,1780.19)
LMX_CS_1X: J85.5 U34.46 | length 1175.5
  L1_Top Layer w11: U34.46@5083.38,9775.7 5130.7,9775.7 5158,9803 v1(5199,9803)
  L10_Signal Layer 2 w6.5: J85.5@5085,10663 5168,10580 5224,10580 5330,10474 5330,9934 v1(5199,9803)
LMX_OSCIN1+: C348.2 U19.8 | length 144.6
  L1_Top Layer w6: C348.2@2246.86,5891.78 2246.86,5913.52 2268.41,5935.08 2268.41,6003.49 2264.07,6007.83 U19.8@2264.07,6025.64
LMX_OSCIN1-: C349.2 U19.9 | length 143.3
  L1_Top Layer w6: U19.9@2283.76,6025.64 2283.76,6007.83 2279.41,6003.49 2279.41,5937.85 2302.04,5915.22 C349.2@2302.04,5893.48
LMX_OSCIN2+: C378.2 U21.8 | length 144.6
  L1_Top Layer w6: U21.8@2287.55,3792.33 2287.55,3810.14 2283.2,3814.48 2283.2,3882.9 2304.76,3904.45 C378.2@2304.76,3926.2
LMX_OSCIN2-: C379.2 U21.9 | length 143.3
  L1_Top Layer w6: C379.2@2249.58,3924.5 2249.58,3902.75 2272.2,3880.13 2272.2,3814.48 2267.86,3810.14 U21.9@2267.86,3792.33
LMX_SDO: R449.1 U34.43 | length 168.3
  L1_Top Layer w11: R449.1@4937.81,9780 4992.57,9834.76 U34.43@5083.38,9834.76
LMX_SDO_MSEL: J40.7 R406.2 R408.2 | length 284.7
  L1_Top Layer w11: J40.7@3679.92,9390 3735.92,9334 3862.5,9334 R406.2@3874.5,9346 R408.2@3874.5,9284
MUXOUT1: R187.1 R190.2 U19.20 | length 300.5
  L1_Top Layer w6: U19.20@2329.03,6228.4 2349.5,6228.4 2359.81,6238.72 ; R187.1@2435.81,6472.22 2436.32,6471.72 R190.2@2436.32,6406.72
  L1_Top Layer w11: 2359.81,6238.72 2359.81,6330.21 R190.2@2436.32,6406.72
MUXOUT2: R227.1 R231.2 U21.20 | length 300.5
  L1_Top Layer w6: R227.1@2115.3,3346.26 R227.1@2115.8,3345.75 ; 2191.8,3487.76 2191.8,3579.26 2202.12,3589.58 U21.20@2222.59,3589.58
  L1_Top Layer w11: R227.1@2115.3,3346.26 R231.2@2115.3,3411.26 2191.8,3487.76
NetBG1_1: BG1.1 U8.C3 | length 1548.3
  L10_Signal Layer 2 w3.5: v1(2287.93,8335.33) 2304.6,8352 ; 2304.68,8352.08 2304.6,8352 ; 2434.67,8459.17 2434.67,8448 2397.92,8411.24 2397.92,8389.24 2391,8382.33 2376,8382.33 2366.92,8373.25 2366.92,8360.24 2358.67,8352 2304.6,8352
  L10_Signal Layer 2 w6.5: 2434.67,8459.17 2434.67,8542 2860.67,8968 3318,8968 3375.44,9025.44 BG1.1@3375.44,9124.69
NetBG2_1: BG2.1 U17.C3 | length 1659.3
  L10_Signal Layer 2 w3.5: v1(2291.26,1989.33) 2307.93,2006 ; 2308.01,2006.08 2307.93,2006 ; 2438,2113.17 2438,2102 2401.25,2065.25 2401.25,2043.25 2394.33,2036.33 2379.33,2036.33 2370.25,2027.25 2370.25,2014.25 2362,2006 2307.93,2006
  L10_Signal Layer 2 w6.5: 2438,2113.17 2438,2196 2861,2619 3373.77,2619 3444.77,2690 BG2.1@3444.77,2829.93
NetC1_1: C1.1 R1.1 R2.1 R3.2 R483.2 U1.2 | length 385.5
  L1_Top Layer w8: C1.1@648.91,9122.87 C1.1@652.03,9125.99
  L1_Top Layer w11: U1.2@648.91,8976.27 C1.1@648.91,9122.87 ; R2.1@715.29,9125.99 C1.1@652.03,9125.99 628.91,9149.11 R3.2@628.91,9185.99 630.29,9187.37 R1.1@678.91,9187.37 729.71,9187.37 R483.2@729.91,9187.16
NetC10_1: C10.1 L1.1 R11.1 | length 109.5
  L1_Top Layer w11: R11.1@1212.71,8959.6 1257.81,8959.6 C10.1@1266.72,8968.51 1271.18,8964.05 L1.1@1316.72,8964.05
NetC11_1: C11.1 L1.2 L2.1 | length 111
  L1_Top Layer w11: L1.2@1316.72,9016.22 1366.26,9016.22 C11.1@1366.72,9015.76 1421.3,9015.76 L2.1@1425.72,9011.33
NetC11_2: C11.2 C16.2 | length 62.8
  L1_Top Layer w11: C16.2@1366.72,8905.76 C11.2@1366.72,8968.51
NetC12_1: C12.1 R7.1 R17.1 R22.2 | length 292.3
  L1_Top Layer w11: R17.1@1539.34,8909.13 R7.1@1539.34,8961.13 ; R22.2@1562.71,8701.26 v2(1562.71,8738.45)
  L12_Bottom Layer w11: v1(1539.2,8931.82) 1539.2,8761.96 v2(1562.71,8738.45)
NetC13_2: C13.2 R20.2 | length 49.5
  L1_Top Layer w11: R20.2@345.61,8964.29 C13.2@380.61,8999.29
NetC14_2: C14.2 R21.2 | length 49.5
  L1_Top Layer w11: R21.2@345.61,8892.69 C14.2@380.61,8857.69
NetC15_1: C15.1 L3.1 R15.1 | length 107.9
  L1_Top Layer w11: R15.1@1212.71,8909.6 1262.87,8909.6 C15.1@1266.72,8905.76 1311.26,8905.76 L3.1@1316.72,8911.22
NetC16_1: C16.1 L3.2 L4.1 | length 109.4
  L1_Top Layer w11: L3.2@1316.72,8859.05 1366.18,8859.05 C16.1@1366.72,8858.51 1425.3,8858.51 L4.1@1425.72,8858.94
NetC26_2: C26.2 R22.1 U3.3 | length 129
  L1_Top Layer w11: C26.2@1435.59,8756.26 1460.19,8731.65 1460.19,8706.85 U3.3@1465.19,8701.85 ; U3.3@1453.38,8701.85 U3.3@1465.19,8701.85 ; R22.1@1515.47,8701.26 1514.88,8701.85 U3.3@1465.19,8701.85
NetC27_1: C27.1 R23.2 U2.7 | length 339.4
  L1_Top Layer w11: U2.7@1053.93,8876.14 1053.93,8773 1125.68,8701.26 R23.2@1260.47,8701.26
NetC35_1: C35.1 R25.1 R26.1 R27.2 R559.2 U4.2 | length 385.5
  L1_Top Layer w8: C35.1@650.71,7700.74 C35.1@653.83,7703.86
  L1_Top Layer w11: U4.2@650.71,7554.14 C35.1@650.71,7700.74 ; R26.1@717.09,7703.86 C35.1@653.83,7703.86 630.71,7726.98 R27.2@630.71,7763.86 632.09,7765.24 R25.1@680.71,7765.24 731.5,7765.24 R559.2@731.71,7765.04
NetC44_1: C44.1 L5.1 R35.1 | length 109.5
  L1_Top Layer w11: R35.1@1214.51,7537.48 1259.61,7537.48 C44.1@1268.52,7546.39 1272.98,7541.92 L5.1@1318.52,7541.92
NetC45_1: C45.1 L5.2 L6.1 | length 111
  L1_Top Layer w11: L5.2@1318.52,7594.09 1368.06,7594.09 C45.1@1368.52,7593.63 1423.09,7593.63 L6.1@1427.52,7589.2
NetC45_2: C45.2 C50.2 | length 62.8
  L1_Top Layer w11: C50.2@1368.52,7483.63 C45.2@1368.52,7546.38
NetC46_1: C46.1 R31.1 R41.1 R46.2 | length 292.3
  L1_Top Layer w11: R41.1@1541.14,7487.01 R31.1@1541.14,7539.01 ; R46.2@1564.51,7279.13 v2(1564.51,7316.32)
  L12_Bottom Layer w11: v1(1541,7509.7) 1541,7339.84 v2(1564.51,7316.32)
NetC47_2: C47.2 R44.2 | length 49.5
  L1_Top Layer w11: R44.2@347.41,7542.16 C47.2@382.41,7577.16
NetC48_2: C48.2 R45.2 | length 49.5
  L1_Top Layer w11: R45.2@347.41,7470.57 C48.2@382.41,7435.57
NetC49_1: C49.1 L7.1 R39.1 | length 107.9
  L1_Top Layer w11: R39.1@1214.51,7487.48 1264.67,7487.48 C49.1@1268.52,7483.63 1313.06,7483.63 L7.1@1318.52,7489.09
NetC50_1: C50.1 L7.2 L8.1 | length 109.4
  L1_Top Layer w11: L7.2@1318.52,7436.92 1367.98,7436.92 C50.1@1368.52,7436.39 1427.09,7436.39 L8.1@1427.52,7436.81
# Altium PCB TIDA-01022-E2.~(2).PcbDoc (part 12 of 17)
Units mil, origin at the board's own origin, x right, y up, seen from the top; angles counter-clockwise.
Board outline 6929.13 x 11614.17 mil, 12 copper layers (L1_Top Layer, L2_GND, L3_GND, L4_Signal Layer 1, L5_GND, L6_PWR, L7_GND/PWR, L8_PWR, L9_GND/PWR, L10_Signal Layer 2, L11_GND, L12_Bottom Layer), stack 64.6 mil thick; 1711 components, 1001 nets, 5985 pads, 3200 vias.

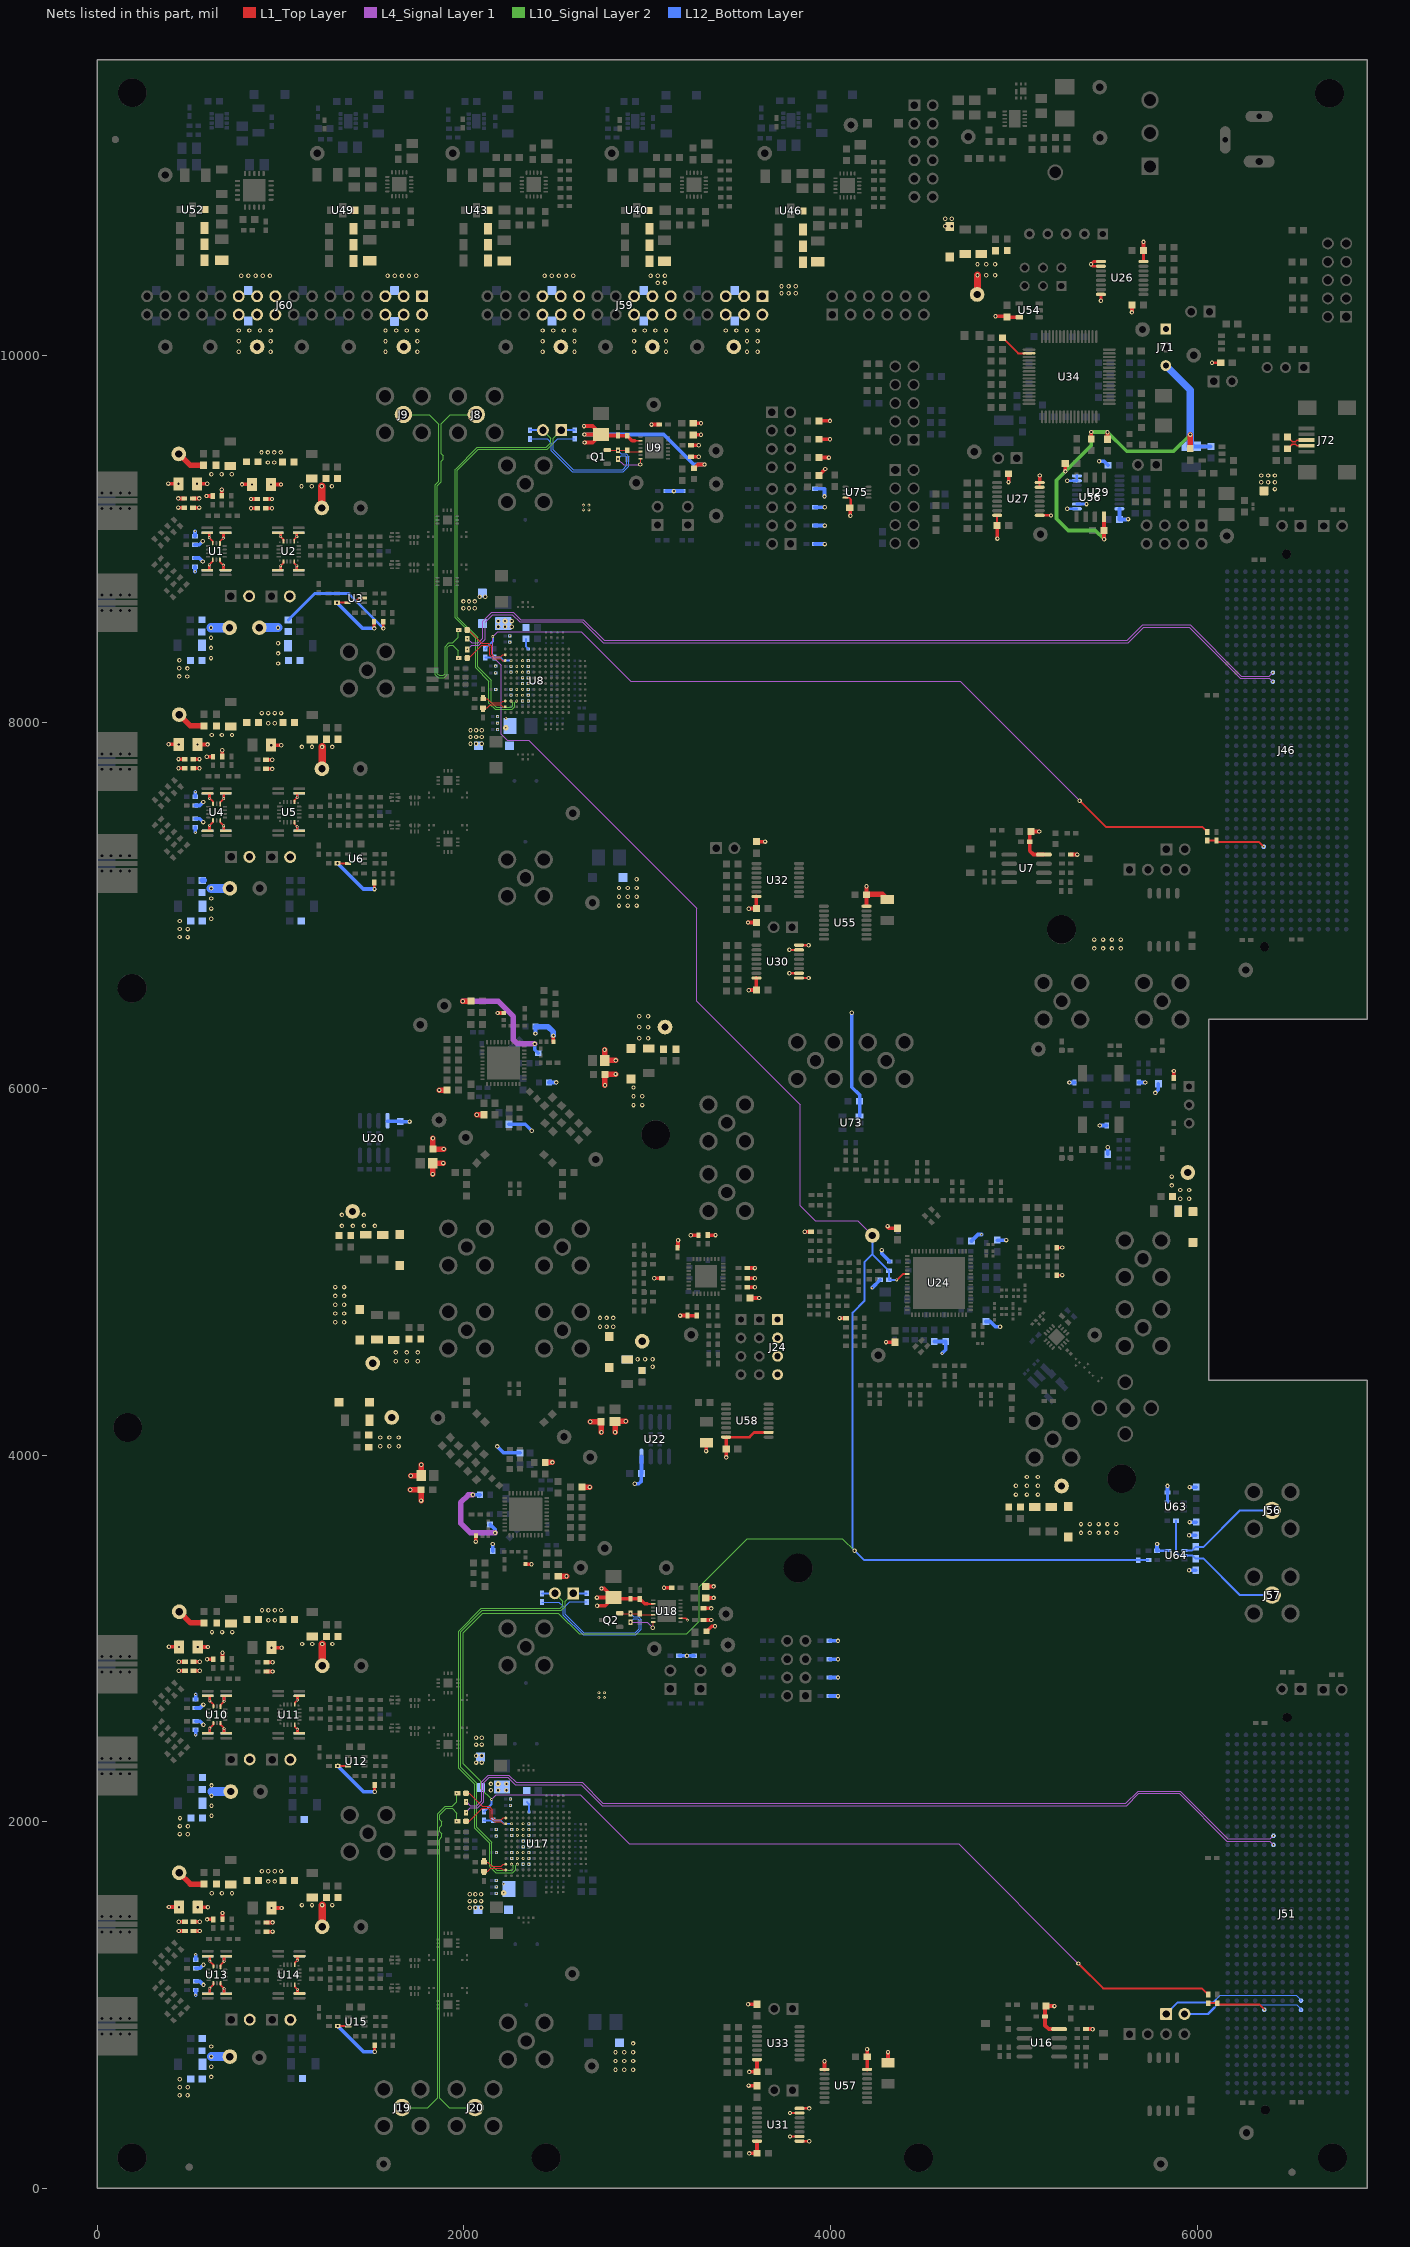
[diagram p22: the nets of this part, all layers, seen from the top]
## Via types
v1: diameter 16, hole 8, L1_Top Layer to L12_Bottom Layer, tented both sides, 1699 vias
v2: diameter 24, hole 12, L1_Top Layer to L12_Bottom Layer, tented both sides, 1501 vias

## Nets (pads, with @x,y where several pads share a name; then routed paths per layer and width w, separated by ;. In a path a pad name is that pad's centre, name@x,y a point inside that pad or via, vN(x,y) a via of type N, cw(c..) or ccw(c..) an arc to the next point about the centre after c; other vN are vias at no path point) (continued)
SYNC: C424.2 R71.2 R152.2 R229.2 R369.2 R633.2 R636.2 R637.2 SYNC1.1 U24.6 | length 20481.1
  L1_Top Layer w9.84: 4390,4984.26 4394.68,4988.94 U24.6@4418.03,4988.94
  L1_Top Layer w11: v1(4360.89,4957) 4362.74,4957 4390,4984.26 ; v2(5351.9,1226.91) 5487.27,1091.53 6025.9,1091.53 R637.2@6060,1057.43 ; v2(5358.57,7570.9) 5501.57,7427.9 6028.44,7427.9 R633.2@6055.82,7400.52
  L4_Signal Layer 1 w3.5: v2@5351.9,1224.91 v2(5351.9,1226.91) v2@5356.6,1226.91
  L4_Signal Layer 1 w5.5: v1(2150.26,2121.8) 2150.26,2121.89 2175.37,2147 2634,2147 2901.82,1879.18 4699.63,1879.18 v2(5351.9,1226.91) ; SYNC1.1@4227.97,5199.02 4148.99,5278 3916,5278 3834,5360 3834,5913 3271,6476 3271,6983 2354,7900 2235,7900 2202,7933 2202,8311 2156.93,8356.07 v1(2156.93,8465.8) 2156.93,8465.89 2184.04,8493 2638.66,8493 2908.49,8223.17 4706.3,8223.17 v2(5358.57,7570.9) v2@5358.57,7568.9
  L10_Signal Layer 2 w6.5: v1(2150.26,2121.8) 2091,2181.06 2091,2222 1995.05,2317.95 1995.05,3031.08 2102.97,3139 2515,3139 2629,3025 3215,3025 3284,3094 3284,3283 3546,3545 4065,3545 v2(4131,3479)
  L12_Bottom Layer w11: R152.2@2109.5,2055.72 2150.26,2096.48 v1(2150.26,2121.8) ; R71.2@2116.17,8399.72 2156.93,8440.48 v1(2156.93,8465.8) ; SYNC1.1@4227.97,5199.02 4227.97,5097.06 ; v1(4360.89,4957) 4317.78,4957 R369.2@4317.72,4956.94 4317.72,5006.56 C424.2@4318.09,5006.94 4227.97,5097.06 ; R636.2@5735.38,3428 5679.62,3428 R229.2@5679,3427.38 4182.62,3427.38 v2(4131,3479) 4120,3490 4120,4778 4186,4844 4186,5055.09 4227.97,5097.06
SYNC1_N: J46.G13 R69.1 | length 4749.9
  L4_Signal Layer 1 w4.9: v1(2018.1,8396.54) 2041.35,8419.8 2081.77,8419.8 2115,8453.03 2115,8545 2156.49,8586.49 2264.51,8586.49 2304,8547 2646.03,8547 2760.03,8433 5623,8433 5708.19,8518.19 5956.11,8518.19 6235.29,8239.01 6394.11,8239.01 v1(6413.11,8220.01)
SYNC1_P: J46.G12 R68.1 | length 4749.9
  L4_Signal Layer 1 w4.9: v1(2018.1,8455.06) 2041.35,8431.8 2076.8,8431.8 2103,8458 2103,8549.97 2151.51,8598.49 2269.49,8598.49 2308.97,8559 2651,8559 2765,8445 5618.03,8445 5703.22,8530.19 5961.08,8530.19 6240.26,8251.01 6394.11,8251.01 v1(6413.11,8270.01)
SYNC1_SE: J46.H31 R587.1 R633.1 | length 321.2
  L1_Top Layer w11: R633.1@6055.82,7353.28 6055.92,7353.39 R587.1@6105.11,7353.39 6112.48,7346.01 6337.11,7346.01 v1(6363.11,7320.01)
SYNC1SE: R71.1 R72.2 U8.C2 | length 147.4
  L12_Bottom Layer w11: R71.1@2116.17,8352.47 R72.2@2166.17,8352.47 2197.85,8352.47 2214.99,8335.33 v1(2256.43,8335.33)
SYNC2_N: J51.G13 R150.1 | length 4752.7
  L4_Signal Layer 1 w4.9: v1(2011.43,2052.55) 2034.68,2075.8 2075.1,2075.8 2108.33,2109.03 2108.33,2214.33 2136.49,2242.49 2239.54,2242.49 2279.03,2203 2639.36,2203 2753.36,2089 5616.33,2089 5682.33,2155 5902.03,2155 6162.02,1895.01 6395.44,1895.01 v1(6416.44,1874.01)
SYNC2_P: J51.G12 R149.1 | length 4751
  L4_Signal Layer 1 w4.9: v1(2011.43,2111.06) 2034.68,2087.8 2070.13,2087.8 2096.33,2114 2096.33,2219.3 2131.52,2254.49 2244.51,2254.49 2284,2215 2644.33,2215 2758.33,2101 5611.36,2101 5677.36,2167 5907,2167 6166.99,1907.01 6399.44,1907.01 v1(6416.44,1924.01)
SYNC2_SE: J51.H31 R589.1 R637.1 | length 320.6
  L1_Top Layer w11: R637.1@6060,1010.19 R589.1@6108.75,1010.19 6116.13,1002.81 6340.75,1002.81 v1@6366.75,976.81
  other v1: 6366.44,974.01
SYNC2SE: R152.1 R153.2 U17.C2 | length 157.4
  L12_Bottom Layer w10: R152.1@2109.5,2006.48 2201.18,2006.48 2218.32,1989.33 v1(2259.76,1989.33)
SYNCSE_EXTIN: J56.1 R631.1 U64.1 | length 568.6
  L12_Bottom Layer w11: U64.1@5931.19,3479.41 5970.99,3479.41 R631.1@5991.9,3500.32 6035.32,3500.32 6233.82,3698.82 J56.1@6408.9,3698.82
SYNCSE_EXTOUT: J57.1 R588.2 R632.1 U64.2 | length 792.5
  L12_Bottom Layer w11: R588.2@5884.62,3643 5884.62,3472.38 5903.18,3453.82 U64.2@5931.19,3453.82 5973.4,3453.82 R632.1@5991.9,3435.31 6035.32,3435.31 6233.82,3236.82 J57.1@6408.9,3236.82
SYS1+: C94.2 C321.2 U8.K1 | length 132.6
  L1_Top Layer w6: C321.2@2105.51,8126.19 2127.26,8126.19 2148.83,8104.61 2200.81,8104.61 2211.06,8114.86 U8.K1@2224.94,8114.86
SYS1-: C95.2 C325.2 U8.L1 | length 131.9
  L1_Top Layer w6: C325.2@2104.13,8077.19 2127.26,8077.19 2143.68,8093.61 2200.81,8093.61 2211.06,8083.36 U8.L1@2224.94,8083.36
SYS2+: C254.2 C334.2 U17.K1 | length 132.6
  L1_Top Layer w6: C334.2@2108.84,1780.19 2130.59,1780.19 2152.16,1758.61 2204.15,1758.61 2214.39,1768.86 U17.K1@2228.27,1768.86
SYS2-: C255.2 C341.2 U17.L1 | length 131.9
  L1_Top Layer w6: C341.2@2107.46,1731.19 2108.76,1731.19 C341.2@2108.84,1731.19 2130.59,1731.19 2147.01,1747.61 2204.15,1747.61 2214.39,1737.37 U17.L1@2228.27,1737.37
TDI_1: J51.D30 J52.1 | length 790.4
  L12_Bottom Layer w5: 6102.4,1030.16 6125.05,1052.81 6540.75,1052.81 J51.D30@6566.75,1026.81
  L12_Bottom Layer w11: J52.1@5830.85,951.48 5894.55,1015.18 6087.42,1015.18 6102.4,1030.16 ; J51.D30@6565.19,1025.26 J51.D30@6566.44,1024.01
TDIODE1+: J11.1 R78.2 U8.K2 | length 2251.5
  L10_Signal Layer 2 w5.5: v1(2256.43,8114.86) 2266.18,8105.11 2266.18,8089.8 2257.18,8080.8 2174.82,8080.8 2147.83,8107.79 2147.83,8228.87 2075,8301.7 2075,8461.97 1964,8572.97 1964,9373 2078,9487 2453.64,9487 2486.42,9519.77 2486.42,9548.16 J11.1@2530.82,9592.56
  L12_Bottom Layer w11: J11.1@2530.82,9592.56 R78.2@2603.93,9592.56 R78.2@2604.16,9592.79
TDIODE1-: J11.2 R79.2 U8.K3 | length 2288.4
  L10_Signal Layer 2 w5.5: v1(2287.93,8114.86) 2278.18,8105.11 2278.18,8084.83 2262.15,8068.8 2169.85,8068.8 2137.67,8100.98 2135.83,8102.82 2135.83,8223.9 2063,8296.73 2063,8457 1952,8568 1952,9377.97 1957,9382.97 2073.03,9499 2448.67,9499 2474.42,9524.74 2474.42,9548.96 J11.2@2430.82,9592.56
  L12_Bottom Layer w11: R79.2@2360.16,9592.17 2360.56,9592.56 J11.2@2430.82,9592.56
TDIODE1N: C116.2 C117.2 Q1.2 R79.1 U9.5 | length 962
  L1_Top Layer w6: Q1.2@2781.35,9484.05 2783.13,9482.27 v2(2840.1,9482.27) C117.2@2890.1,9482.27 2896.47,9475.9 U9.5@2963.36,9475.9
  L12_Bottom Layer w6: R79.1@2360.16,9544.93 2453.62,9544.93 2476.55,9522 2476.55,9480.9 2591.75,9365.69 2870,9365.69 2899.44,9395.14 2899.44,9448.7 2884,9464.15 2858.22,9464.15 v2(2840.1,9482.27)
TDIODE1P: C116.1 R78.1 U9.7 | length 888.6
  L1_Top Layer w6: v2(2961.9,9404.89) 2963.36,9406.36 U9.7@2963.36,9436.53
  L4_Signal Layer 1 w5.5: v2(2840.1,9435.03) 2870.24,9404.89 v2(2961.9,9404.89)
  L12_Bottom Layer w6: R78.1@2603.93,9545.32 2510.87,9545.32 2487.55,9522 2487.55,9485.45 2596.31,9376.69 2865.44,9376.69 2888.44,9399.69 2888.44,9444.15 2879.44,9453.15 2858.22,9453.15 v2(2840.1,9435.03)
TDIODE2+: J22.1 R159.2 U17.K2 | length 2296.3
  L10_Signal Layer 2 w5.5: v1(2259.76,1768.86) 2269.51,1759.11 2269.51,1743.8 2260.51,1734.8 2178.15,1734.8 2151.16,1761.8 2151.16,1888.81 2070.26,1969.71 2070.26,2210.74 1983.05,2297.95 1983.05,3036.05 2100,3153 2530.97,3153 2551.75,3173.78 2551.75,3202.17 J22.1@2596.15,3246.57
  L12_Bottom Layer w11: J22.1@2596.15,3246.57 R159.2@2669.26,3246.57
TDIODE2-: J22.2 R160.2 U17.K3 | length 2332.9
  L10_Signal Layer 2 w5.5: 2141,1754.98 2173.18,1722.8 2265.48,1722.8 2281.51,1738.83 2281.51,1759.11 v1(2291.26,1768.86) ; 2141,1754.98 2139.16,1756.83 2139.16,1883.84 2058.26,1964.74 2058.26,2205.77 1971.05,2292.98 1971.05,3041.02 2095.03,3165 2526,3165 2539.75,3178.75 2539.75,3202.97 J22.2@2496.15,3246.57
  L12_Bottom Layer w11: R160.2@2425.89,3246.57 J22.2@2496.15,3246.57
TDIODE2N: C276.2 C277.2 Q2.2 R160.1 U18.5 | length 968.6
  L1_Top Layer w6: Q2.2@2849.68,3138.28 2851.46,3136.5 v2(2908.43,3136.5) C277.2@2958.43,3136.5 2964.8,3130.13 U18.5@3031.69,3130.13
  L12_Bottom Layer w6: R160.1@2425.49,3198.93 2517.85,3198.93 2541.88,3174.91 2541.88,3127.57 2649.52,3019.93 2938.33,3019.93 2967.77,3049.37 2967.77,3102.94 2952.33,3118.38 2926.55,3118.38 v2(2908.43,3136.5)
TDIODE2P: C276.1 R159.1 U18.7 | length 895.2
  L1_Top Layer w6: v2(3030.23,3059.12) 3031.69,3060.59 U18.7@3031.69,3090.76
  L4_Signal Layer 1 w5.5: v2(2908.43,3089.26) 3000.09,3089.26 v2(3030.23,3059.12)
  L12_Bottom Layer w6: R159.1@2669.26,3199.32 2577.3,3199.32 2552.88,3174.91 2552.88,3132.12 2654.07,3030.93 2933.77,3030.93 2956.77,3053.93 2956.77,3098.38 2947.77,3107.38 2926.56,3107.38 v2(2908.43,3089.26)
TDO_1: J51.D31 J52.2 | length 668
  L12_Bottom Layer w5: 6094.65,986.91 6108.55,1000.81 6542.75,1000.81 J51.D31@6566.75,976.81
  L12_Bottom Layer w11: J52.2@5930.85,951.48 6059.22,951.48 6094.65,986.91 ; J51.D31@6565.19,975.26 J51.D31@6566.44,974.01
TMSP1+: J8.1 R67.1 | length 1943.7
  L10_Signal Layer 2 w5.5: 1874.98,9410 1874.98,9423.02 ; v1(1969,8502) 1968.59,8501.59 v1@1968.59,8500.04 ; v1@1970.85,8502.3 1969.78,8501.22 v1@1968.59,8500.04 ; J8.1@2067.22,9677.9 1926.32,9677.9 1875,9626.58 1875,9464 1886.98,9452.02 1886.98,9435.02 1875,9423.04 1875,9310.03 1854,9289.03 1854,8263.97 1863.97,8254 1888,8254 1897,8263 1897,8411.97 1916.83,8431.8 1939.03,8431.8 1968.59,8461.36 v1@1968.59,8500.04
TMSP1-: J9.1 R70.1 | length 1941.6
  L10_Signal Layer 2 w5.5: J9.1@1669.62,9677.9 1810.52,9677.9 1863,9625.42 1863,9315 1842,9294 1842,8259 1859,8242 1892.97,8242 1909,8258.03 1909,8407 1921.8,8419.8 1939.03,8419.8 1968.59,8390.24 v1@1968.59,8351.56 ; v1(1969,8349) 1968.59,8349.41 v1@1968.59,8351.56 ; v1@1970.85,8349.3 1970.08,8350.08 v1@1968.59,8351.56
TMSP2+: J19.1 R148.1 | length 1943.3
  L10_Signal Layer 2 w5.5: J19.1@1662.64,440.91 1803.54,440.91 1856.02,493.38 1856.02,2043.78 1897.25,2085.01 1935,2085.01 1960.25,2110.26 1960.25,2151.88 1961,2152.63 v1(1961,2156)
TMSP2-: J20.1 R151.1 | length 1941.7
  L10_Signal Layer 2 w5.5: 1868,1947 1868,1970 ; 1868.02,1946.98 1879.98,1935.02 1879.98,1918.02 1868.02,1906.06 1868.02,492.23 1919.34,440.91 J20.1@2060.24,440.91 ; 1868.02,1970.02 1880,1982 1880,1999 1868.02,2010.98 1868.02,2038.8 1902.22,2073.01 1935,2073.01 1960.25,2047.76 1960.25,2006.13 1960,2005.88 v1(1960,2003)
TMSTP1+: R67.2 R68.2 U8.B1 | length 306.4
  L1_Top Layer w6: R68.2@2007.79,8501.5 2018.1,8501.5 2025.6,8501.5 2096.6,8430.5 2133.78,8430.5 2151.93,8412.36 2151.93,8369.8 2165.15,8356.58 2200.81,8356.58 2211.06,8366.83 U8.B1@2224.94,8366.83
TMSTP1-: R69.2 R70.2 U8.C1 | length 306.4
  L1_Top Layer w6: R70.2@2007.79,8348.5 2018.1,8348.5 2025.6,8348.5 2096.6,8419.5 2129.23,8419.5 2140.93,8407.8 2140.93,8365.24 2160.6,8345.58 2200.81,8345.58 2211.06,8335.33 U8.C1@2224.94,8335.33
TMSTP2+: R148.2 R149.2 U17.B1 | length 306.4
  L1_Top Layer w6: R149.2@2011.12,2155.51 2028.93,2155.51 2099.93,2084.51 2137.12,2084.51 2155.26,2066.36 2155.26,2023.8 2168.48,2010.58 2204.15,2010.58 2214.39,2020.83 U17.B1@2228.27,2020.83
TMSTP2-: R150.2 R151.2 U17.C1 | length 306.4
  L1_Top Layer w6: R151.2@2011.12,2002.51 2028.93,2002.51 2099.93,2073.51 2132.56,2073.51 2144.26,2061.8 2144.26,2019.25 2163.93,1999.58 2204.15,1999.58 2214.39,1989.33 U17.C1@2228.27,1989.33
USB_ACTIVITY: R549.1 U34.34 | length 186.3
  L1_Top Layer w11: R549.1@4935.88,10102.97 R549.1@4940.08,10098.77 ; R549.1@4938.31,10097 5023.38,10011.92 U34.34@5083.38,10011.92
USB_DM: J72.2 R472.1 | length 117.2
  L1_Top Layer w8.2: R472.1@6493.44,9490.71 6518.48,9515.75 6536.7,9515.75 6545.34,9507.1 J72.2@6596.73,9507.1
USB_DP: J72.3 R539.1 | length 117.1
  L1_Top Layer w8.2: R539.1@6493.44,9554.71 6518.21,9529.95 6536.7,9529.95 6545.34,9538.59 J72.3@6596.73,9538.59
V1P1V: J59.22 J59.24 J59.26 L37.1 L38.1 L39.1 L40.1 L84.2 TP26.1
  other v2: 2826.68,646.91 2874.68,646.91 2922.68,646.91 2826.68,694.91 2874.68,694.91 2922.68,694.91 2826.68,742.91 2874.68,742.91 2922.68,742.91 2922.68,790.91 2066,2323 2097,2323 2066,2360 2097,2360 2066.13,2421.37 2097.13,2421.37 2066.13,2458.37 2097.13,2458.37 2845.66,6998.71 2893.66,6998.71 2941.66,6998.71 2845.66,7046.71 2893.66,7046.71 2941.66,7046.71 2845.66,7094.71 2893.66,7094.71 2941.66,7094.71 2941.66,7142.71 1996.52,8621 2027.52,8621 2058.52,8621 1996.52,8658 2027.52,8658 2058.52,8658 2084.87,8683.63 2115.87,8683.63 2429,10020 2603,10020 2429,10078 2603,10078 2429,10136 2487,10136 2545,10136 2603,10136
V1P1V_IN: C539.2 C540.2 C541.2 J59.21 J59.23 J59.25 L84.1 R618.2 U43.3
  other v2: 2440,10435 2479,10435 2518,10435 2557,10435 2596,10435
V1P9V: J59.12 J59.14 J59.16 L35.1 L36.1 L72.1 L83.2 TP22.1
  other v2: 2031.21,1530.63 2062.21,1530.63 2093.21,1530.63 2031.21,1567.63 2062.21,1567.63 2093.21,1567.63 2031.21,1604.63 2062.21,1604.63 2093.21,1604.63 2035.27,7881.26 2066.27,7881.26 2097.27,7881.26 2035.27,7918.26 2066.27,7918.26 2097.27,7918.26 2035.27,7955.26 2066.27,7955.26 2097.27,7955.26 6424,9271 6350,9308 6387,9308 6424,9308 6350,9345 6387,9345 6424,9345 2928,10020 3102,10020 2928,10078 3102,10078 2928,10136 2986,10136 3044,10136 3102,10136
V1P9V_IN: C496.2 C497.2 C498.2 J59.11 J59.13 J59.15 L83.1 R614.2 U40.3 | length 1.4
  L1_Top Layer w10: C496.2@3010.43,10692.06 C496.2@3011.44,10691.04
  other v2: 3057,10396 3096,10396 3018,10435 3057,10435 3096,10435
V3P3: J59.2 J59.4 J59.6 L41.1 L42.1 L43.1 L44.1 L45.1 L46.1 L47.1 L73.1 L74.2 TP33.1
  other v2: 5366.07,3576.12 5414.07,3576.12 5462.07,3576.12 5510.07,3576.12 5558.07,3576.12 5366.07,3624.12 5414.07,3624.12 5462.07,3624.12 5510.07,3624.12 5558.07,3624.12 2741.91,4701.28 2777.91,4701.28 2813.91,4701.28 1297.64,4725.39 1345.64,4725.39 2741.91,4749.28 2777.91,4749.28 2813.91,4749.28 1297.64,4773.39 1345.64,4773.39 1297.64,4821.39 1345.64,4821.39 1297.64,4869.39 1345.64,4869.39 1297.64,4917.39 1345.64,4917.39 2924.64,5910.39 2972.64,5910.39 2924.64,5958.39 2972.64,5958.39 2924.64,6006.39 3544,10020 3602,10020 3544,10078 3602,10078 3428,10136 3486,10136 3544,10136 3602,10136 4626,10705 4661,10705 4626,10746 4661,10746
V3P3_IN: C602.2 C603.2 C604.2 J59.1 J59.3 J59.5 L74.1 R622.2 U46.3
  other v2: 3732,10339 3771,10339 3810,10339 3732,10378 3771,10378 3810,10378
V3P3_LMK48XX: C625.1 C626.1 C627.2 C628.1 L22.1 L23.1 L24.1 L25.1 L29.1 L30.1 L31.1 L45.2 R228.1 R271.2 R286.2 R321.1 R340.1 R369.1 TP37.1 | length 728.7
  L1_Top Layer w15: R321.1@5234.67,4982.2 v2@5263.1,4982.2 ; R340.1@5234.67,5132.45 v2@5263.1,5132.45
  L1_Top Layer w20: v2(3858.62,5219.44) R271.2@3893.85,5219.44 ; v2(4049.16,4748.08) R286.2@4084.39,4748.08 ; v2(4302.47,4616.94) 4302.89,4616.52 L23.1@4350.97,4616.52 ; v2(4310.89,5250) 4310.89,5244.52 4316.9,5238.51 L31.1@4365.97,5238.51
  L12_Bottom Layer w20: v2(3858.62,5219.44) v2@3859.84,5218.22 ; v2(4049.16,4748.08) v2@4050.38,4746.86 ; v1(4226.47,4912.94) R369.1@4270.47,4956.94 ; v2(4278.89,5119) 4278.89,5100.38 R228.1@4322.27,5057 ; L24.1@4565.97,4620.52 L25.1@4627.97,4620.52 4627.97,4575.44 v1(4608.47,4555.94) ; L30.1@4769.05,5168.44 4804.61,5204 v1(4824,5204) ; L22.1@4846.97,4729.52 4871.37,4729.52 4899.89,4701 v2(4924.89,4701) ; L29.1@4908.97,5173.51 v2(4958.9,5173.51)
  other v2: 5011.23,3785.01 5071.23,3785.01 5131.23,3785.01 5011.23,3833.01 5071.23,3833.01 5131.23,3833.01 5071.23,3881.01 5131.23,3881.01 5264.17,4982.98 5264.17,5133.23
V3P3_LMK61E2: C629.1 C630.1 C631.2 C632.1 L21.2 L46.2 L56.1 R163.2 R352.2 R353.2 R358.1 TP38.1 | length 235.3
  L1_Top Layer w20: R163.2@5872.89,6058.6 5872.89,6095.89 v2(5873,6096)
  L12_Bottom Layer w11: R358.1@5505.84,5799 R358.1@5505.97,5798.87 ; L21.2@5512.38,5642.51 L21.2@5512.51,5642.64
  L12_Bottom Layer w20: v2(5303.08,6033.46) R352.2@5330.97,6033.46 ; v2(5468,5799) R358.1@5505.84,5799 ; L21.2@5512.51,5642.64 v2(5512.51,5680.48) ; R353.2@5680.97,6033.46 5717.02,6033.46 v2(5717.14,6033.35) ; v2@5770.78,5976.81 5788.35,5994.39 L56.1@5788.35,6027.22
  other v2: 5908,5399 5956,5399 5908,5447 5956,5447 5861,5472 5861,5520 5771.08,5976.52
V3P3_LMK00304: C381.1 C382.1 C383.1 C485.1 C486.1 C487.2 C488.1 J24.1 J24.2 J24.3 J24.4 L73.2 R245.2 R246.2 R247.2 R248.2 R249.2 R250.2 R251.2 TP24.1 | length 437.9
  L1_Top Layer w11: R245.2@3164.5,5131.41 R245.2@3168,5134.91
  L1_Top Layer w20: v2(3038,4966) 3038.21,4965.79 R246.2@3079.88,4965.79 ; R245.2@3168,5134.91 v2(3168,5173) ; v2(3178.76,4762) 3178.38,4762.38 C383.1@3219,4762.38 3219.71,4761.67 R251.2@3270.5,4761.67 ; v2(3237.62,5200.62) 3237.83,5200.41 R249.2@3279.5,5200.41 ; R250.2@3330.5,5200.91 3372.17,5200.91 v2(3372.38,5200.7) ; C382.1@3545.12,4916.29 3586.79,4916.29 v2(3587,4916.07) ; R247.2@3545.12,4966.29 3586.79,4966.29 v2(3587,4966.07) ; R248.2@3545.12,5021.29 3586.79,5021.29 v2(3587,5021.07) ; C381.1@3561,4857.79 3610.79,4857.79 v2(3611,4858)
  other v2: 3029,4483 2947,4524 2988,4524 3029,4524
V3P3_LMX1: C328.2 C329.2 C330.2 C331.2 C350.2 C596.1 C597.1 C598.2 C599.1 L41.2 R165.1 R167.1 R170.1 R171.2 R172.1 R173.2 TP31.1 U20.8 | length 1526.2
  L1_Top Layer w30: C329.2@1827.11,5592.72 C329.2@1828.17,5593.78 ; C328.2@1829.2,5669.45 C328.2@1830.26,5670.52 ; v2(1829.23,5533.54) C329.2@1829.23,5592.72 C329.2@1828.17,5593.78 ; v2(1830.26,5729.69) C328.2@1830.26,5670.52 ; C328.2@1831.33,5669.45 C328.2@1830.26,5670.52 ; v2(1865.09,5991.92) R173.2@1904.23,5991.92 ; v2(1887.34,5593.78) C329.2@1828.17,5593.78 ; v2(1889.44,5670.52) C328.2@1830.26,5670.52 ; v2(1992.88,6477.14) R171.2@2026.45,6477.14 ; v2(2069.52,5857.32) R172.1@2108.66,5857.32 ; C331.2@2767.14,6078.05 C331.2@2768.2,6079.11 ; v2(2767.17,6211.96) 2767.17,6153.85 C330.2@2767.17,6152.79 ; C330.2@2768.23,6151.73 C330.2@2767.17,6152.79 ; v2(2769.26,6018.88) C331.2@2769.26,6078.05 C331.2@2768.2,6079.11 ; v2(2827.37,6079.11) C331.2@2768.2,6079.11 ; v2(2827.41,6153.85) C330.2@2768.23,6153.85 C330.2@2767.17,6152.79
  L4_Signal Layer 1 w30: v2(1992.88,6477.14) 2185.86,6477.14 2270,6393 2270,6266 2291.68,6244.32 v2(2385.81,6244.32)
  L12_Bottom Layer w20: U20.8@1582.81,5821.27 1650.97,5821.27 C350.2@1651.97,5820.27 v2(1703.17,5820.27) ; R165.1@2245.1,5805.31 2334.42,5805.31 v2(2369.86,5769.87) ; v2(2385.81,6244.32) 2385.81,6212.28 R170.1@2404.81,6193.28 ; R167.1@2468.86,6038.93 R167.1@2463.84,6033.92 v2(2502.86,6033.87)
  other v2: 1333.94,5251.3 1393.94,5251.3 1453.94,5251.3 1513.94,5251.3 1333.94,5311.3 1453.94,5311.3
V3P3_LMX1RF: C605.1 C606.2 C607.1 L17.1 L18.1 L42.2 R169.1 TP34.1 | length 232.2
  L1_Top Layer w20: v2(2183.37,6412.47) L17.1@2216.07,6412.47 ; L18.1@2487.51,6256.72 v2(2487.51,6289.42)
  L12_Bottom Layer w20: v2(2389.81,6300.72) 2390.37,6301.28 R169.1@2390.37,6338.72
  L12_Bottom Layer w30: R169.1@2390.37,6338.72 2457.03,6338.72 2487.51,6308.23 v2(2487.51,6289.42)
  other v2: 2956.28,6275.23 3004.28,6275.23 2956.28,6335.23 3004.28,6335.23 2956.28,6395.23 3004.28,6395.23
V3P3_LMX2: C358.2 C359.2 C360.2 C361.2 C380.2 C609.1 C610.1 C611.2 C612.1 L43.2 R206.1 R208.1 R211.1 R212.2 R213.1 R214.2 TP35.1 U22.8 | length 1423.7
  L1_Top Layer w30: v2(1706.98,3811.53) C358.2@1766.15,3811.53 ; v2(1709.07,3888.26) 1767.18,3888.26 C359.2@1768.25,3888.26 ; C358.2@1765.09,3812.59 C358.2@1766.15,3811.53 ; v2(1766.15,3752.35) C358.2@1766.15,3811.53 ; C358.2@1767.21,3812.59 C358.2@1766.15,3811.53 ; v2(1767.18,3948.5) C359.2@1767.18,3889.33 C359.2@1768.25,3888.26 ; C359.2@1769.31,3889.33 C359.2@1768.25,3888.26 ; R213.1@2442.96,3960.65 v2(2482.1,3960.65) ; R212.2@2525.87,3340.13 v2(2559.44,3340.13) ; R214.2@2647.39,3826.06 v2(2686.53,3826.06) ; v2(2689.21,4183.18) C361.2@2748.38,4183.18 C361.2@2749.45,4184.24 ; C361.2@2748.38,4185.31 C361.2@2749.45,4184.24 ; v2(2749.45,4125.07) C361.2@2749.45,4184.24 ; C360.2@2822.06,4184.21 C360.2@2823.12,4185.28 ; v2(2824.18,4125.04) C360.2@2824.18,4184.21 C360.2@2823.12,4185.28 ; v2(2882.29,4185.28) 2824.18,4185.28 C360.2@2823.12,4185.28
  L4_Signal Layer 1 w30: v2(2048.76,3784.1) 2024.1,3784.1 1982,3742 1982,3629 2034.84,3576.16 v2(2169.57,3576.16)
  L12_Bottom Layer w20: v2@2048.8,3784.06 R208.1@2087.78,3784.06 R208.1@2082.76,3779.04 ; R211.1@2142.48,3622.45 2169.83,3595.1 2169.57,3594.84 v2(2169.57,3576.16) ; v2(2181.76,4048.1) 2217.2,4012.66 R206.1@2306.51,4012.66 ; v2(2932,3844) 2953,3844 2967.8,3858.8 C380.2@2967.8,3899.45 2968.8,3900.46 U22.8@2968.8,3992.97
  other v2: 1627.57,4512.9 1687.57,4512.9 1747.57,4512.9 1627.57,4560.9 1687.57,4560.9 1747.57,4560.9
V3P3_LMX2RF: C622.1 C623.2 C624.1 L19.1 L20.1 L44.2 R210.1 TP36.1 | length 103.6
  L1_Top Layer w20: v2(2064.1,3528.56) L20.1@2064.1,3561.26 ; L19.1@2335.55,3405.5 v2(2368.25,3405.5)
  L12_Bottom Layer w20: R210.1@2156.32,3477.61 2156.32,3515.05 v2(2156.88,3515.61)
  other v2: 1543.1,4048.68 1593.1,4048.68 1643.1,4048.68 1543.1,4096.68 1593.1,4096.68 1643.1,4096.68
V3P3_VDD: C69.2 C70.1 C107.1 C108.1 C109.1 C147.1 C148.1 C229.2 C230.1 C267.1 C268.1 C269.1 C441.2 C444.2 C447.2 C449.2 C451.2 C453.2 C455.2 C468.2 C489.2 C508.1 C511.1 C633.1 C634.1 C635.2 C636.1 C737.2 C741.2 D5.1 D10.1 J71.1 L47.2 R49.2 R74.2 R75.2 R76.2 R80.2 R81.2 R130.2 R155.2 R156.2 R157.2 R161.2 R162.2 R404.1 R406.1 R411.1 R420.1 R425.1 R429.1 R430.1 R431.1 R440.1 R441.1 R467.1 R468.1 R541.2 R548.2 R550.2 R631.2 R632.2 R634.2 R635.2 TP39.1 U7.8 U9.2 U16.8 U18.2 U18.9 U26.1 U26.2 U26.8 U26.16 U27.1 U27.7 U27.8 U27.16 U29.1 U29.2 U29.7 U29.8 U29.16 U30.1 U30.2 U30.7 U30.8 U30.16 U31.1 U31.2 U31.7 U31.8 U31.16 U32.16 U33.16 U54.5 U55.16 U57.1 U57.16 U58.2 U58.16 U63.5 U64.5 U73.1 U75.8 | length 7282.3
  L1_Top Layer w8: U18.9@3181.3,3110.45 3208.5,3110.45 v1(3218.92,3100.02)
  L1_Top Layer w10: 2929.96,9534.95 U9.2@2963.36,9534.95 ; 2998.29,3189.19 U18.2@3031.69,3189.19
  L1_Top Layer w11: U75.8@4081.01,9224.47 4100.53,9224.47 4110,9215 4110,9174.5 C148.1@4104.5,9169 ; C444.2@4908.68,9072.79 U27.16@4908.68,9127.63 ; U27.7@5140.96,9281.18 U27.8@5140.96,9306.77
  L1_Top Layer w12: v2(3775.15,6629.3) 3775.21,6629.24 U30.2@3827.61,6629.24 ; v2(3775.15,6757.26) 3775.21,6757.2 U30.7@3827.61,6757.2 ; v2(3778.48,283.31) 3778.54,283.25 U31.2@3830.94,283.25 ; v2(3778.48,411.26) 3778.54,411.2 U31.7@3830.94,411.2 ; U30.1@3827.61,6603.65 v2(3880.07,6603.59) v2(3880.07,6603.59) ; U30.8@3827.61,6782.79 3880.01,6782.79 v2(3880.07,6782.73) ; U31.1@3830.94,257.66 3883.34,257.66 v2(3883.4,257.6) ; U31.8@3830.94,436.79 3883.34,436.79 v2(3883.4,436.73)
  L1_Top Layer w15: U58.16@3430.04,4098.58 3557.33,4098.58 3582.92,4124.17 U58.2@3662.32,4124.17 ; U27.1@5140.96,9127.63 5202.18,9127.63 v2(5202.72,9127.09) ; v2@5474.72,10302 U26.8@5474.72,10333.41 ; U26.2@5474.72,10486.95 5432.05,10486.95 v2(5421,10498) 5435.54,10512.54 U26.1@5474.72,10512.54 ; U26.16@5707,10512.54 5707,10572.74 C441.2@5707.21,10572.95 ; v2(6080.83,9960.28) R420.1@6128.55,9960.28
  L1_Top Layer w20: v2(2654.9,9614.89) 2701.38,9614.89 C108.1@2747.1,9569.17 ; v2(2656.9,9568.89) 2656.62,9569.17 C108.1@2747.1,9569.17 ; v2(2657.9,9524.89) 2702.83,9524.89 C108.1@2747.1,9569.17 ; v2(2725.23,3223.12) 2724.95,3223.4 C268.1@2815.43,3223.4 ; v2(2726.23,3179.12) 2771.16,3179.12 C268.1@2815.43,3223.4 ; v2(2750,3273) 2765.83,3273 C268.1@2815.43,3223.4 ; 2929.96,9534.95 2917.17,9534.95 C109.1@2890.1,9562.03 2841.1,9562.03 C107.1@2840.1,9563.03 2753.24,9563.03 C108.1@2747.1,9569.17 ; 2998.29,3189.19 2985.5,3189.19 C269.1@2958.43,3216.26 2909.43,3216.26 C267.1@2908.43,3217.26 2821.57,3217.26 C268.1@2815.43,3223.4 ; v2(3022.9,9622.89) 3023.03,9623.03 R76.2@3065.48,9623.03 ; v2(3091.23,3277.12) 3091.36,3277.26 R157.2@3133.81,3277.26 ; R74.2@3238.72,9447.03 v2(3281.17,9447.03) ; R75.2@3238.72,9510.03 v2(3281.17,9510.03) ; R80.2@3250.6,9567.03 3293.05,9567.03 v2(3293.18,9567.16) ; R81.2@3250.6,9630.03 v2@3293.05,9630.03 ; D5.1@3255.1,9385.08 3275.09,9405.06 v2(3312,9405.06) ; R155.2@3307.06,3101.26 v2(3349.5,3101.26) ; R156.2@3307.06,3164.26 v2(3349.5,3164.26) ; R161.2@3318.93,3221.26 3361.38,3221.26 v2(3361.51,3221.39) ; R162.2@3318.93,3284.26 3361.38,3284.26 v2(3361.51,3284.39) ; v2(3321,4022.37) R550.2@3321,4067.06 ; R550.2@3321.18,4067.06 R550.2@3323.18,4069.06 ; D10.1@3323.43,3039.31 3351.05,3066.93 v2(3369.66,3066.93) ; U58.16@3430.04,4098.58 3430.04,4033.8 C489.2@3430.68,4033.15 3430.68,3988.32 v2(3431,3988) ; v2(3549.2,6906.63) 3549.6,6906.22 R440.1@3595.07,6906.22 ; v2(3550,1005) 3550.07,1004.93 R468.1@3598.4,1004.93 ; v2(3552.53,560.63) 3552.93,560.23 R441.1@3598.4,560.23 ; v2(3553.07,6537.02) 3554.03,6537.97 C449.2@3595.33,6537.97 ; v2(3553.07,6981.73) 3554.03,6982.68 C453.2@3595.33,6982.68 U32.16@3595.33,7048.36 ; v2(3556.4,191.02) 3557.36,191.98 C451.2@3598.66,191.98 ; v2(3556.4,635.73) 3557.36,636.68 C455.2@3598.66,636.68 ; C449.2@3595.08,6537.73 C449.2@3595.33,6537.97 ; U30.16@3595.33,6603.65 C449.2@3595.33,6537.97 ; R467.1@3595.43,7347.75 v2(3642.93,7347.75) ; C451.2@3598.41,191.73 C451.2@3598.66,191.98 ; C455.2@3598.41,636.44 C455.2@3598.66,636.68 ; U31.16@3598.66,257.66 C451.2@3598.66,191.98 ; U33.16@3598.66,702.36 C455.2@3598.66,636.68 ; R406.1@3937.5,9347 v2(3971,9380.5) ; R431.1@3937.5,9443 v2(3991,9443) ; R430.1@3937.5,9543 v2(3997,9543) ; R429.1@3937.5,9643 v2(3997,9643) ; U57.1@3967.01,649.08 v2(3967.06,693.32) v2(3967.06,693.32) ; C148.1@4104.5,9169 4108,9165.5 v2(4108,9125) ; U55.16@4195.96,6995.08 C737.2@4195.96,7057.16 ; C737.2@4196.32,7057.51 v2@4196.32,7104.48 ; U57.16@4199.29,649.08 4199.29,711.16 4199.65,711.52 C741.2@4199.65,718.52 4199.65,758.48 v2(4199.4,758.73) ; R548.2@4313.15,685.6 4313.15,743.48 v2(4313.4,743.73) ; v2(4899.87,10213.5) 4959.86,10213.5 C468.2@4962.88,10210.47 ; v2(4910,9001) 4910,9067 C444.2@4911,9068 ; C468.2@4964.79,10208.57 U54.5@5029.75,10208.57 ; v2(4970.91,9309.13) 4971.31,9309.53 R411.1@4971.31,9355 ; v2(5138.21,7402.68) 5137.71,7403.18 C70.1@5092.71,7403.18 5086.83,7397.31 C69.2@5086.83,7346.18 5086.83,7297.06 5106.71,7277.18 U7.8@5163.7,7277.18 ; U27.8@5140.96,9306.77 5140.96,9344.96 v2(5141,9345) ; v2(5221.3,994.75) 5220.8,995.25 C230.1@5175.79,995.25 5169.92,989.38 C229.2@5169.92,938.25 5169.92,889.13 5189.8,869.25 U16.8@5246.78,869.25 ; R49.2@5309.83,7277.18 5345.71,7277.18 v2(5346.21,7276.68) ; R130.2@5392.92,869.25 5428.8,869.25 v2(5429.3,868.75) ; v2(5644,10235) R404.1@5644.01,10276 ; v2(5707,10619.58) 5707.21,10619.79 C441.2@5707.21,10572.95
  L1_Top Layer w30: C737.2@4198.12,7059.31 4282.11,7059.31 R541.2@4309.82,7031.6
  L1_Top Layer w40: TP39.1@4801.4,10334.82 v2(4801.4,10437.82)
  L12_Bottom Layer w15: v2(5290.95,9163.46) U29.1@5343.68,9163.43 ; v2(5290.95,9317) U29.7@5343.68,9316.98 U29.8@5343.68,9342.57 ; U29.2@5343.68,9189.02 v2@5396.38,9189.02 ; C511.1@5781.48,3479.41 U64.5@5842.61,3479.41 ; U63.5@5838.18,3745.69 C508.1@5838.18,3796.77
  L12_Bottom Layer w20: v2(2656.9,9568.89) 3089.49,9568.89 3253.31,9405.06 v2(3312,9405.06) ; v2(4116,6414) 4116,6008 4158.5,5965.5 C147.1@4158.5,5931 ; U73.1@4158.74,5850.4 C147.1@4158.74,5930.75 ; v2(5465,9423) 5491.32,9423 R425.1@5513.32,9401 ; U29.16@5575.96,9163.43 5575.96,9105.35 C447.2@5576.31,9105 5613.63,9105 5615.63,9107 v2(5623,9107) ; C511.1@5781.15,3479.74 5781.15,3515.4 v2(5781.21,3515.45) ; v2(5837.9,3832.82) 5837.84,3832.76 C508.1@5837.84,3797.1 C508.1@5838.18,3796.77 ; v2(5955.86,3372.05) 5955.92,3371.99 R632.2@5991.57,3371.99 ; v2(5955.86,3563.04) 5955.92,3562.98 R631.2@5991.57,3562.98 ; v2(5958.86,3635.05) 5958.92,3634.99 R634.2@5994.57,3634.99 ; v2(5958.86,3826.04) 5958.92,3825.98 R635.2@5994.57,3825.98
  other v2: 5439,6765 5487,6765 5535,6765 5583,6765 5439,6813 5487,6813 5535,6813 5583,6813 4196.07,7104.73 5396.4,9189 3293.18,9630.16 5475,10298 4849.4,10437.82 4897.4,10437.82 4801.4,10497.82 4849.4,10497.82 4897.4,10497.82
V_BUS: C471.1 C472.2 C738.2 J71.3 L34.2 R544.2 R545.2 R546.2 U56.8 | length 2402.9
  L1_Top Layer w20: R545.2@5279.88,9410.97 5279.88,9368.46 v2(5280.87,9367.47) ; R546.2@5421.88,9544.47 v2(5421.87,9582.47) ; C738.2@5491.88,9045.47 U56.8@5491.88,9119.69 ; v2(5492.39,8996.99) 5491.88,8997.49 5491.88,9044.47 C738.2@5492.38,9044.97 ; R544.2@5510.88,9543.47 v2(5510.88,9581.46)
  L1_Top Layer w30: L34.2@5962,9491.68 v2(5962,9568)
  L10_Signal Layer 2 w20: v2(5492.39,8996.99) 5443.9,9045.47 5296.53,9045.47 5233,9109 5233,9319.6 v2(5280.87,9367.47) 5421.87,9508.47 v2(5421.87,9582.47) 5509.87,9582.47 v2(5510.88,9581.46) 5615.34,9477 5871,9477 v2(5962,9568)
  L12_Bottom Layer w20: v2(5421.87,9582.47) v2@5422.88,9581.46 ; C471.1@5968.59,9503.5 C472.2@6075,9503.5
  L12_Bottom Layer w40: J71.3@5829,9945 5962,9812 v2(5962,9568) C471.1@5962,9505.09 ; C471.1@5967,9505.09 C471.1@5968.59,9503.5
VA1P1_ADC1: C119.1 C120.1 C121.1 C122.1 C123.1 C124.1 C125.1 C126.1 C127.1 C128.1 C129.1 C130.1 C131.1 C132.1 C133.1 L37.2 TP4.1 U8.C5 U8.D2 U8.D3 U8.D5 U8.E5 U8.F5 U8.G5 U8.H5 U8.J2 U8.J3 U8.J5 U8.K5 | length 61.3
  L12_Bottom Layer w10: C132.1@2338.77,8454.56 2338.77,8410.47 C121.1@2350.92,8398.32
  other v1: 2350.92,8114.86 2256.43,8146.35 2287.93,8146.35 2350.92,8146.35 2350.92,8177.85 2350.92,8209.35 2350.92,8240.84 2350.92,8272.34 2256.43,8303.83 2287.93,8303.83 2350.92,8303.83 2172.81,8304.79 2350.92,8335.33
  other v2: 2187.08,8519.9 2224.08,8519.9 2261.08,8519.9 2187.08,8550.9 2224.08,8550.9 2261.08,8550.9
VA1P1_ADC2: C279.1 C280.1 C281.1 C282.1 C283.1 C284.1 C285.1 C286.1 C287.1 C288.1 C289.1 C290.1 C291.1 C292.1 C293.1 L38.2 TP10.1 U17.C5 U17.D2 U17.D3 U17.D5 U17.E5 U17.F5 U17.G5 U17.H5 U17.J2 U17.J3 U17.J5 U17.K5 | length 61.3
  L12_Bottom Layer w10: C292.1@2342.1,2108.56 2354.25,2096.41 C281.1@2354.25,2052.33
  other v1: 2354.25,1768.86 2259.76,1800.36 2291.26,1800.36 2354.25,1800.36 2354.25,1831.85 2354.25,1863.35 2354.25,1894.85 2354.25,1926.34 2259.76,1957.84 2291.26,1957.84 2354.25,1957.84 2176.14,1958.8 2354.25,1989.33
  other v2: 2147,2172 2186.26,2171.8 2231.26,2171.8 2147,2207 2186.26,2206.8 2231.26,2206.8
VA1P9_ADC1: C134.1 C135.1 C136.1 C137.1 C138.1 C139.1 C140.1 C141.1 C142.1 C143.1 C144.1 C145.1 C146.1 L35.2 R54.1 R55.1 R56.1 R57.1 R63.2 R64.2 TP5.1 U8.C4 U8.D4 U8.E2 U8.E3 U8.E4 U8.F4 U8.G4 U8.H2 U8.H3 U8.H4 U8.J4 U8.K4 | length 341.8
  L12_Bottom Layer w20: R63.2@3103.92,9260.91 R64.2@3193.68,9260.91 ; R57.1@3915.42,8970.99 3967.96,8970.99 v2(3968.08,8970.87) ; R56.1@3915.42,9071.99 3967.96,9071.99 v2(3968.08,9071.87) ; R55.1@3915.42,9171.99 3967.96,9171.99 v2(3968.08,9171.87) ; R54.1@3915.42,9271.99 3967.96,9271.99 3967,9271.03 v2(3967,9231)
  other v1: 2183.26,7958.56 2228.08,7968.9 2183.26,7993.56 2228.08,8019.9 2183.26,8029.56 2319.43,8114.86 2319.43,8146.35 2173.81,8177.79 2256.43,8177.85 2287.93,8177.85 2319.43,8177.85 2319.43,8209.35 2319.43,8240.84 2172.81,8267.79 2256.43,8272.34 2287.93,8272.34 2319.43,8272.34 2319.43,8303.83 2319.43,8335.33 2250.26,8435.56 2250.26,8470.56 2651,9158 2681,9158 2651,9184 2681,9184
  other v2: 3145.3,9259.91
VA1P9_ADC2: C294.1 C295.1 C296.1 C297.1 C298.1 C299.1 C300.1 C301.1 C302.1 C303.1 C304.1 C305.1 C306.1 L36.2 R135.1 R136.1 R137.1 R138.1 R144.2 R145.2 TP11.1 U17.C4 U17.D4 U17.E2 U17.E3 U17.E4 U17.F4 U17.G4 U17.H2 U17.H3 U17.H4 U17.J4 U17.K4 | length 258
  L12_Bottom Layer w20: R144.2@3173.61,2905.76 3174.35,2906.49 v2(3216.28,2906.49) R145.2@3256.65,2906.49 ; R138.1@3997.06,2686.1 v2(4040.6,2686.1) v2@4040.48,2686.22 ; R137.1@3997.06,2787.1 v2(4040.6,2787.1) v2@4040.48,2787.22 ; R136.1@3997.06,2887.1 4040.6,2887.1 v2(4040.72,2886.98) ; R135.1@3997.06,2987.1 v2@4040.6,2987.1
  other v1: 2176.59,1609.56 2216.26,1611.8 2176.59,1644.56 2216.26,1661.8 2176.59,1680.56 2322.76,1768.86 2322.76,1800.36 2177.14,1831.8 2259.76,1831.85 2291.26,1831.85 2322.76,1831.85 2322.76,1863.35 2322.76,1894.85 2176.14,1921.8 2259.76,1926.34 2291.26,1926.34 2322.76,1926.34 2322.76,1957.84 2322.76,1989.33 2253.59,2089.56 2253.59,2124.56 2736,2678 2766,2678 2736,2704 2766,2704
  other v2: 4040.72,2986.98
VA3P75: J60.2 J60.4 J60.6 L48.1 L49.1 L50.1 L51.1 L52.1 L53.1 L54.1 L55.1 L85.2 TP43.1
  other v2: 932.17,1675.17 967.17,1675.17 897.17,1730.42 932.17,1730.42 967.17,1730.42 1002.17,1730.42 933.09,3099.5 968.09,3099.5 898.09,3154.76 933.09,3154.76 968.09,3154.76 1003.09,3154.76 931.99,7993.8 966.99,7993.8 896.99,8049.06 931.99,8049.06 966.99,8049.06 1001.99,8049.06 930.19,9415.93 965.19,9415.93 895.19,9471.18 930.19,9471.18 965.19,9471.18 1000.19,9471.18 1572,10020 1746,10020 1572,10078 1746,10078 1572,10136 1630,10136 1688,10136 1746,10136
VA3P75_IN: C644.2 C645.2 C646.2 J60.1 J60.3 J60.5 L85.1 R626.2 U49.3
  other v2: 1583,10435 1622,10435 1661,10435 1700,10435 1739,10435
VA3P75_LMH5401_1: C3.2 C7.1 C18.1 C22.2 C29.1 C31.1 C32.1 C658.1 C663.2 C664.1 J67.2 L52.2 R1.2 R5.2 R19.1 TP46.1 U1.1 U1.10 | length 641.9
  L1_Top Layer w10: U1.10@668.6,8885.71 668.6,8875.08 v1(687.63,8856.05) ; U1.1@668.6,8974.3 668.6,8984.93 v1(687.63,9003.96) ; C22.2@687.63,8831.05 689.89,8828.79 C22.2@698.91,8828.79 ; C3.2@687.63,9028.96 689.89,9031.23 C3.2@698.91,9031.23
  L1_Top Layer w15: C22.2@687.63,8831.05 v1(687.63,8856.05) ; v1(687.63,9003.96) C3.2@687.63,9028.96
  L1_Top Layer w20: v2(386.48,9300.93) C29.1@441.73,9300.93 ; v2(440.57,9169.99) C32.1@474.29,9169.99 ; v2(440.57,9219.99) C31.1@474.29,9219.99 ; R1.2@678.91,9234.61 v2(678.91,9268.33)
  L1_Top Layer w30: TP46.1@443.91,9462.71 505.34,9401.29 C664.1@578.91,9401.29
  L12_Bottom Layer w10: C18.1@687.63,8831.05 689.89,8828.79 C18.1@698.91,8828.79 ; C7.1@687.63,9030.93 689.89,9033.19 C7.1@698.91,9033.19
  L12_Bottom Layer w15: C18.1@687.63,8831.05 v1(687.63,8856.05) ; v1@687.63,9005.93 C7.1@687.63,9030.93
  L12_Bottom Layer w20: R19.1@532.53,8895.01 556.24,8895.01 v2(575.19,8876.05) ; R5.2@532.53,8966.97 556.24,8966.97 v2(575.19,8985.93)
  other v2: 441.73,9299.99 622.05,9351.57 677.3,9351.57 732.55,9351.57
VA3P75_LMH5401_2: C37.2 C41.1 C52.1 C56.2 C63.1 C65.1 C66.1 C670.1 C672.2 C673.1 J78.2 L54.2 R25.2 R29.2 R43.1 TP48.1 U4.1 U4.10 | length 641.9
  L1_Top Layer w10: U4.10@670.39,7463.59 670.39,7452.95 v1(689.42,7433.92) ; U4.1@670.39,7552.17 670.39,7562.8 v1(689.42,7581.84) ; C56.2@689.42,7408.92 691.69,7406.66 C56.2@700.71,7406.66 ; C37.2@689.42,7606.84 691.69,7609.1 C37.2@700.71,7609.1
  L1_Top Layer w15: C56.2@689.42,7408.92 v1(689.42,7433.92) ; v1(689.42,7581.84) C37.2@689.42,7606.84
  L1_Top Layer w20: v2(388.28,7878.8) C63.1@443.53,7878.8 ; v2(442.37,7747.86) C66.1@476.09,7747.86 ; v2(442.37,7797.86) C65.1@476.09,7797.86 ; R25.2@680.71,7812.48 v2(680.71,7846.2)
  L1_Top Layer w30: TP48.1@445.71,8040.59 507.13,7979.16 C673.1@580.71,7979.16
  L12_Bottom Layer w10: C52.1@689.42,7408.92 691.69,7406.66 C52.1@700.71,7406.66 ; C41.1@689.42,7608.8 691.69,7611.07 C41.1@700.71,7611.07
  L12_Bottom Layer w15: C52.1@689.42,7408.92 v1(689.42,7433.92) ; v1@689.42,7583.8 C41.1@689.42,7608.8
  L12_Bottom Layer w20: R43.1@534.33,7472.88 558.04,7472.88 v2(576.99,7453.92) ; R29.2@534.33,7544.85 558.04,7544.85 v2(576.99,7563.8)
  other v2: 443.53,7877.86 623.84,7929.44 679.1,7929.44 734.35,7929.44
VA3P75_LMH5401_3: C163.2 C167.1 C178.1 C182.2 C189.1 C191.1 C192.1 C659.1 C665.2 C666.1 J82.2 L53.2 R82.2 R86.2 R100.1 TP47.1 U10.1 U10.10 | length 641.9
  L1_Top Layer w10: U10.10@671.91,2539.35 671.91,2528.72 v1(690.94,2509.69) ; U10.1@671.91,2627.94 671.91,2638.57 v1(690.94,2657.6) ; C182.2@690.94,2484.69 693.21,2482.42 C182.2@702.23,2482.42 ; C163.2@690.94,2682.6 693.21,2684.86 C163.2@702.23,2684.86
  L1_Top Layer w15: C182.2@690.94,2484.69 v1(690.94,2509.69) ; v1(690.94,2657.6) C163.2@690.94,2682.6
  L1_Top Layer w20: v2(389.79,2954.57) C189.1@445.05,2954.57 ; v2(443.89,2823.63) C192.1@477.61,2823.63 ; v2(443.89,2873.63) C191.1@477.61,2873.63 ; R82.2@682.23,2888.25 v2(682.23,2921.97)
  L1_Top Layer w30: TP47.1@446.81,3146.29 508.23,3084.86 C666.1@581.81,3084.86
  L12_Bottom Layer w10: C178.1@690.94,2484.69 693.21,2482.42 C178.1@702.23,2482.42 ; C167.1@690.94,2684.57 693.21,2686.83 C167.1@702.23,2686.83
  L12_Bottom Layer w15: C178.1@690.94,2484.69 v1(690.94,2509.69) ; v1@690.94,2659.57 C167.1@690.94,2684.57
  L12_Bottom Layer w20: R100.1@535.85,2548.64 559.55,2548.64 v2(578.51,2529.69) ; R86.2@535.85,2620.61 559.55,2620.61 v2(578.51,2639.57)
  other v2: 445.05,2953.63 624.94,3035.14 680.19,3035.14 735.45,3035.14
VA3P75_LMH5401_4: C197.2 C201.1 C212.1 C216.2 C223.1 C225.1 C226.1 C671.1 C674.2 C675.1 J84.2 L55.2 R106.2 R110.2 R124.1 TP49.1 U13.1 U13.10 | length 641.9
  L1_Top Layer w10: U13.10@671.99,1120.02 671.99,1109.38 v1(691.02,1090.35) ; U13.1@671.99,1208.6 671.99,1219.23 v1(691.02,1238.26) ; C216.2@691.02,1065.35 693.28,1063.09 C216.2@702.3,1063.09 ; C197.2@691.02,1263.26 693.28,1265.53 C197.2@702.3,1265.53
  L1_Top Layer w15: C216.2@691.02,1065.35 v1(691.02,1090.35) ; v1(691.02,1238.26) C197.2@691.02,1263.26
  L1_Top Layer w20: v2(389.87,1535.23) C223.1@445.12,1535.23 ; v2(443.96,1404.29) C226.1@477.68,1404.29 ; v2(443.96,1454.29) C225.1@477.68,1454.29 ; R106.2@682.3,1468.91 v2(682.3,1502.63)
  L1_Top Layer w30: TP49.1@445.88,1721.95 507.31,1660.53 C675.1@580.88,1660.53
  L12_Bottom Layer w10: C212.1@691.02,1065.35 693.28,1063.09 C212.1@702.3,1063.09 ; C201.1@691.02,1265.23 693.28,1267.5 C201.1@702.3,1267.5
  L12_Bottom Layer w15: C212.1@691.02,1065.35 v1(691.02,1090.35) ; v1@691.02,1240.23 C201.1@691.02,1265.23
  L12_Bottom Layer w20: R124.1@535.92,1129.31 559.63,1129.31 v2(578.59,1110.35) ; R110.2@535.92,1201.28 559.63,1201.28 v2(578.59,1220.23)
  other v2: 445.12,1534.29 624.02,1610.8 679.27,1610.8 734.52,1610.8
VA3P75_LMH6401_1: C5.2 C9.1 C20.1 C24.2 C25.2 C30.1 C33.1 C34.1 C637.1 C639.2 C640.1 J64.2 L48.2 R556.2 TP40.1 U2.8 U2.13 U3.5 | length 791.1
  L1_Top Layer w10: U2.8@1073.62,8876.14 1073.62,8865.95 v1(1087.99,8851.58) ; U2.13@1073.62,8986.38 1073.62,8996.56 v1(1087.99,9010.93) ; C24.2@1090.52,8829.05 C24.2@1104.09,8829.05 ; C5.2@1090.52,9033.46 C5.2@1099.09,9033.46 C5.2@1104.09,9033.46
  L1_Top Layer w11: v2(1307.71,8651.26) 1364.21,8651.26 U3.5@1364.8,8650.67
  L1_Top Layer w15: C24.2@1087.99,8831.58 v1(1087.99,8851.58) ; v1(1087.99,9010.93) C5.2@1087.99,9030.93 ; R556.2@1508.91,8547.16 1508.91,8512.21 v2(1510.19,8510.93)
  L1_Top Layer w20: C34.1@918.71,9166.71 v2(952.43,9166.71) ; C33.1@918.71,9216.71 v2(952.43,9216.71) ; v2(946.27,9295.77) v2(1001.53,9295.77)
  L1_Top Layer w40: TP40.1@1224.15,9168.08 v2(1224.15,9286.5)
  L12_Bottom Layer w10: C20.1@1090.52,8829.05 C20.1@1099.09,8829.05 C20.1@1104.09,8829.05 ; C9.1@1090.52,9033.46 C9.1@1099.09,9033.46 C9.1@1104.09,9033.46
  L12_Bottom Layer w15: C20.1@1087.99,8831.58 v1(1087.99,8851.58) ; v1(1087.99,9010.93) C9.1@1087.99,9030.93
  L12_Bottom Layer w20: v2(1307.71,8651.26) 1448.04,8510.93 v2(1510.19,8510.93)
  other v2: 1113.65,9286.5 1168.9,9286.5 1279.41,9286.5
VA3P75_LMH6401_2: C39.2 C43.1 C54.1 C58.2 C59.2 C64.1 C67.1 C68.1 C648.1 C651.2 C652.1 J68.2 L50.2 R565.2 TP44.1 U5.8 U5.13 U6.5 | length 792.4
  L1_Top Layer w10: U5.8@1075.42,7454.01 1075.42,7443.83 v1(1089.79,7429.46) ; U5.13@1075.42,7564.25 1075.42,7574.43 v1(1089.79,7588.8) ; C58.2@1092.32,7406.93 C58.2@1105.89,7406.93 ; C39.2@1092.32,7611.34 C39.2@1100.89,7611.34 C39.2@1105.89,7611.34
  L1_Top Layer w11: v2(1309.51,7229.13) 1366.01,7229.13 U6.5@1366.6,7228.54
  L1_Top Layer w15: C58.2@1089.79,7409.46 v1(1089.79,7429.46) ; v1(1089.79,7588.8) C39.2@1089.79,7608.8 ; R565.2@1510.71,7125.04 1510.71,7090.09 v2(1511.99,7088.8)
  L1_Top Layer w20: C68.1@920.51,7744.58 v2(954.23,7744.58) ; C67.1@920.51,7794.58 v2(954.23,7794.58) ; v2(948.07,7873.64) v2(1003.32,7873.64)
  L1_Top Layer w40: TP44.1@1225,7745 1225.95,7745.95 v2(1225.95,7864.37)
  L12_Bottom Layer w10: C54.1@1092.32,7406.93 C54.1@1105.89,7406.93 ; C43.1@1092.32,7611.34 C43.1@1100.89,7611.34 C43.1@1105.89,7611.34
  L12_Bottom Layer w15: C54.1@1089.79,7409.46 v1(1089.79,7429.46) ; v1(1089.79,7588.8) C43.1@1089.79,7608.8
  L12_Bottom Layer w20: v2(1309.51,7229.13) 1449.84,7088.8 v2(1511.99,7088.8)
  other v2: 1115.45,7864.37 1170.7,7864.37 1281.2,7864.37
VA3P75_LMH6401_3: C165.2 C169.1 C180.1 C184.2 C185.2 C190.1 C193.1 C194.1 C638.1 C641.2 C642.1 J79.2 L49.2 R574.2 TP41.1 U11.8 U11.13 U12.5 | length 791.1
  L1_Top Layer w10: U11.8@1076.94,2529.78 1076.94,2519.59 v1(1091.31,2505.22) ; U11.13@1076.94,2640.01 1076.94,2650.2 v1(1091.31,2664.57) ; C184.2@1093.84,2482.69 C184.2@1107.41,2482.69 ; C165.2@1093.84,2687.1 C165.2@1102.41,2687.1 C165.2@1107.41,2687.1
  L1_Top Layer w11: v2(1311.03,2304.9) 1367.53,2304.9 U12.5@1368.12,2304.31
  L1_Top Layer w15: C184.2@1091.31,2485.22 v1(1091.31,2505.22) ; v1(1091.31,2664.57) C165.2@1091.31,2684.57 ; R574.2@1512.23,2200.8 1512.23,2165.85 v2(1513.51,2164.57)
  L1_Top Layer w20: C194.1@922.03,2820.34 v2(955.75,2820.34) ; C193.1@922.03,2870.34 v2(955.75,2870.34) ; v2(949.59,2949.4) v2(1004.84,2949.4)
  L1_Top Layer w40: TP41.1@1227.05,2851.65 v2(1227.05,2970.07)
  L12_Bottom Layer w10: C180.1@1093.84,2482.69 C180.1@1107.41,2482.69 ; C169.1@1093.84,2687.1 C169.1@1102.41,2687.1 C169.1@1107.41,2687.1
  L12_Bottom Layer w15: C180.1@1091.31,2485.22 v1(1091.31,2505.22) ; v1(1091.31,2664.57) C169.1@1091.31,2684.57
  L12_Bottom Layer w20: v2(1311.03,2304.9) 1451.36,2164.57 v2(1513.51,2164.57)
  other v2: 1116.55,2970.07 1171.8,2970.07 1282.3,2970.07
VA3P75_LMH6401_4: C199.2 C203.1 C214.1 C218.2 C219.2 C224.1 C227.1 C228.1 C649.2 C650.1 C653.1 J83.2 L51.2 R583.2 TP45.1 U14.8 U14.13 U15.5 | length 791.1
  L1_Top Layer w10: U14.8@1077.01,1110.44 1077.01,1100.26 v1(1091.38,1085.89) ; U14.13@1077.01,1220.68 1077.01,1230.86 v1(1091.38,1245.23) ; C218.2@1093.91,1063.36 C218.2@1107.48,1063.36 ; C199.2@1093.91,1267.77 C199.2@1102.48,1267.77 C199.2@1107.48,1267.77
  L1_Top Layer w11: v2(1311.11,885.56) 1367.6,885.56 U15.5@1368.19,884.97
  L1_Top Layer w15: C218.2@1091.38,1065.89 v1(1091.38,1085.89) ; v1(1091.38,1245.23) C199.2@1091.38,1265.23 ; R583.2@1512.3,781.47 1512.3,746.52 v2(1513.59,745.23)
  L1_Top Layer w20: C228.1@922.11,1401.01 v2(955.82,1401.01) ; C227.1@922.11,1451.01 v2(955.82,1451.01) ; v2(949.66,1530.07) v2(1004.92,1530.07)
  L1_Top Layer w40: TP45.1@1226.12,1427.32 v2(1226.12,1545.73)
  L12_Bottom Layer w10: C214.1@1093.91,1063.36 C214.1@1107.48,1063.36 ; C203.1@1093.91,1267.77 C203.1@1102.48,1267.77 C203.1@1107.48,1267.77
  L12_Bottom Layer w15: C214.1@1091.38,1065.89 v1(1091.38,1085.89) ; v1(1091.38,1245.23) C203.1@1091.38,1265.23
  L12_Bottom Layer w20: v2(1311.11,885.56) 1451.43,745.23 v2(1513.59,745.23)
  other v2: 1115.62,1545.73 1170.87,1545.73 1281.38,1545.73
VA_N1P25: J60.18 J60.20 J60.22 L60.1 L61.1 L62.1 L63.1 L64.1 L65.1 L66.1 L67.1 L86.2 TP58.1
  other v2: 492.2,507.9 448.42,508.45 448.97,552.24 492.76,551.68 449.52,596.02 493.13,1932.23 449.34,1932.79 493.68,1976.02 449.9,1976.57 450.45,2020.36 448.24,6827.09 492.03,6826.53 448.8,6870.87 492.58,6870.32 449.35,6914.66 446.45,8249.21 490.23,8248.66 447,8293 490.79,8292.45 447.55,8336.79 771,10020 945,10020 771,10078 945,10078 771,10136 829,10136 887,10136 945,10136
VA_N1P25_IN: C705.2 C706.2 C707.2 J60.17 J60.19 J60.21 L86.1 R630.2 U52.3
  other v2: 785,10435 824,10435 863,10435 902,10435 941,10435
VA_N1P25_LMH5401_1: C2.2 C6.1 C17.1 C21.2 C29.2 C31.2 C32.2 C689.1 C693.2 C694.1 L61.2 R3.1 R553.2 R554.2 TP55.1 U1.3 U1.8 | length 536
  L1_Top Layer w10: C21.2@598.91,8830.75 607.93,8830.75 C21.2@610.19,8833.02 ; C2.2@598.91,9033.19 607.93,9033.19 C2.2@610.19,9030.93 ; v1(610.19,8858.02) 629.23,8877.05 U1.8@629.23,8885.71 U1.8@629.23,8887.68 ; v1(610.19,9005.93) 629.23,8986.9 U1.3@629.23,8976.27
  L1_Top Layer w15: C21.2@610.19,8833.02 v1(610.19,8858.02) ; v1(610.19,9005.93) C2.2@610.19,9030.93
  L1_Top Layer w20: C32.2@521.53,9169.99 v2(555.25,9169.99) ; C31.2@521.53,9219.99 v2(555.25,9219.99) ; v2(544.09,9299.99) v2(599.34,9299.99) ; v2(595.19,9233.23) R3.1@628.91,9233.23
  L12_Bottom Layer w10: C17.1@598.91,8828.79 607.93,8828.79 C17.1@610.19,8831.05 ; C6.1@598.91,9033.19 607.93,9033.19 C6.1@610.19,9030.93
  L12_Bottom Layer w15: C17.1@610.19,8831.05 v1@610.19,8856.05 ; v1(610.19,9005.93) C6.1@610.19,9030.93
  L12_Bottom Layer w20: v1(532.53,8820.64) R554.2@532.53,8847.79 ; R553.2@532.53,9013.79 v1(532.53,9040.93)
  L12_Bottom Layer w50: v2(619.63,8514.85) v2(619.63,8514.85) TP55.1@720.91,8514.79
  other v2: 619.63,8349.09 619.63,8404.35 619.63,8459.6
VA_N1P25_LMH5401_2: C36.2 C40.1 C51.1 C55.2 C63.2 C65.2 C66.2 C700.1 C703.2 C704.1 L63.2 R27.1 R562.2 R563.2 TP57.1 U4.3 U4.8 | length 546.1
  L1_Top Layer w10: C55.2@600.71,7408.63 609.73,7408.63 C55.2@611.99,7410.89 ; C36.2@600.71,7611.07 609.73,7611.07 C36.2@611.99,7608.8 ; v1(611.99,7435.89) 631.02,7454.92 U4.8@631.02,7463.59 U4.8@631.02,7465.56 ; v1(611.99,7583.8) 631.02,7564.77 U4.3@631.02,7554.14
  L1_Top Layer w15: C55.2@611.99,7410.89 v1(611.99,7435.89) ; v1(611.99,7583.8) C36.2@611.99,7608.8
  L1_Top Layer w20: C66.2@523.33,7747.86 v2(557.05,7747.86) ; C65.2@523.33,7797.86 v2(557.05,7797.86) ; v2(545.89,7877.86) v2(601.14,7877.86) ; v2(596.99,7811.11) R27.1@630.71,7811.11
  L12_Bottom Layer w10: C51.1@600.71,7406.66 609.73,7406.66 C51.1@611.99,7408.92 ; C40.1@600.71,7611.07 609.73,7611.07 C40.1@611.99,7608.8
  L12_Bottom Layer w15: C51.1@611.99,7408.92 v1@611.99,7433.92 ; v1(611.99,7583.8) C40.1@611.99,7608.8
  L12_Bottom Layer w20: v1(534.33,7398.51) R563.2@534.33,7425.66 ; R562.2@534.33,7591.66 v1(534.33,7618.8)
  L12_Bottom Layer w30: C704.1@571.7,7135.86 C704.1@581.91,7135.86
  L12_Bottom Layer w50: v2@621.49,7092.66 TP57.1@722.71,7092.66
  other v2: 621.42,6926.97 621.42,6982.22 621.42,7037.47 621.42,7092.72
VA_N1P25_LMH5401_3: C162.2 C166.1 C177.1 C181.2 C189.2 C191.2 C192.2 C709.1 C712.2 C713.1 L65.2 R84.1 R571.2 R572.2 TP61.1 U10.3 U10.8 | length 535.9
  L1_Top Layer w10: C181.2@602.23,2484.39 611.25,2484.39 C181.2@613.51,2486.66 ; C162.2@602.23,2686.83 611.25,2686.83 C162.2@613.51,2684.57 ; v1(613.51,2511.66) 632.54,2530.69 U10.8@632.54,2539.35 U10.8@632.54,2541.32 ; v1(613.51,2659.57) 632.54,2640.54 U10.3@632.54,2629.9
  L1_Top Layer w15: C181.2@613.51,2486.66 v1(613.51,2511.66) ; v1(613.51,2659.57) C162.2@613.51,2684.57
  L1_Top Layer w20: C192.2@524.85,2823.63 v2(558.57,2823.63) ; C191.2@524.85,2873.63 v2(558.57,2873.63) ; v2(547.41,2953.63) v2(602.66,2953.63) ; v2(598.51,2886.87) R84.1@632.23,2886.87
  L12_Bottom Layer w10: C177.1@602.23,2482.42 611.25,2482.42 C177.1@613.51,2484.69 ; C166.1@602.23,2686.83 611.25,2686.83 C166.1@613.51,2684.57
  L12_Bottom Layer w15: C177.1@613.51,2484.69 v1@613.51,2509.69 ; v1(613.51,2659.57) C166.1@613.51,2684.57
  L12_Bottom Layer w20: v1(535.85,2474.28) R572.2@535.85,2501.42 ; R571.2@535.85,2667.42 v1(535.85,2694.57)
  L12_Bottom Layer w50: 626.13,2165 TP61.1@727.35,2165
  other v2: 622.52,2032.67 622.52,2087.92 622.52,2143.17 622.52,2198.42
VA_N1P25_LMH5401_4: C196.2 C200.1 C211.1 C215.2 C223.2 C225.2 C226.2 C718.1 C721.2 C722.1 L67.2 R108.1 R580.2 R581.2 TP63.1 U13.3 U13.8 | length 535.9
  L1_Top Layer w10: C215.2@602.3,1065.06 611.32,1065.06 C215.2@613.59,1067.32 ; C196.2@602.3,1267.5 611.32,1267.5 C196.2@613.59,1265.23 ; v1(613.59,1092.32) 632.62,1111.35 U13.8@632.62,1120.02 U13.8@632.62,1121.99 ; v1(613.59,1240.23) 632.62,1221.2 U13.3@632.62,1210.57
  L1_Top Layer w15: C215.2@613.59,1067.32 v1(613.59,1092.32) ; v1(613.59,1240.23) C196.2@613.59,1265.23
  L1_Top Layer w20: C226.2@524.92,1404.29 v2(558.64,1404.29) ; C225.2@524.92,1454.29 v2(558.64,1454.29) ; v2(547.48,1534.29) v2(602.74,1534.29) ; v2(598.59,1467.54) R108.1@632.3,1467.54
  L12_Bottom Layer w10: C211.1@602.3,1063.09 611.32,1063.09 C211.1@613.59,1065.35 ; C200.1@602.3,1267.5 611.32,1267.5 C200.1@613.59,1265.23
  L12_Bottom Layer w15: C211.1@613.59,1065.35 v1@613.59,1090.35 ; v1(613.59,1240.23) C200.1@613.59,1265.23
  L12_Bottom Layer w20: v1(535.92,1054.94) R581.2@535.92,1082.09 ; R580.2@535.92,1248.09 v1(535.92,1275.23)
  L12_Bottom Layer w50: v2@621.66,719.02 TP63.1@722.88,719.02
  other v2: 621.6,608.33 621.6,663.58 621.6,718.84 621.6,774.09
VA_N1P25_LMH6401_1: C4.2 C8.1 C19.1 C23.2 C30.2 C33.2 C34.2 C688.1 C691.2 C692.1 L60.2 R557.1 TP54.1 U2.5 U2.16 U3.2 | length 1166.4
  L1_Top Layer w10: C23.2@984.09,8829.05 C23.2@997.66,8829.05 ; C4.2@984.09,9033.46 C4.2@997.66,9033.46 ; v1(1000.19,8851.58) 1014.56,8865.95 U2.5@1014.56,8876.14 ; v1(1000.19,9010.93) 1014.56,8996.56 U2.16@1014.56,8986.38 ; v1(1415.19,8655.93) 1415.19,8665.93 1425.52,8676.26 U3.2@1453.38,8676.26
  L1_Top Layer w15: C23.2@1000.19,8831.58 v1(1000.19,8851.58) ; v1(1000.19,9010.93) C4.2@1000.19,9030.93 ; R557.1@1558.91,8547.16 1558.91,8512.21 v2(1560.19,8510.93)
  L1_Top Layer w20: v2(788.66,9296.71) C30.2@843.91,9296.71 ; v2(837.75,9166.71) C34.2@871.47,9166.71 ; v2(837.75,9216.71) C33.2@871.47,9216.71
  L12_Bottom Layer w10: C19.1@984.09,8829.05 C19.1@997.66,8829.05 ; C8.1@984.09,9033.46 C8.1@997.66,9033.46
  L12_Bottom Layer w15: C19.1@1000.19,8831.58 v1(1000.19,8851.58) ; v1(1000.19,9010.93) C8.1@1000.19,9030.93 ; C692.1@1041.29,8557.35 1185.93,8702 1369.13,8702 v1(1415.19,8655.93) v2(1560.19,8510.93)
  L12_Bottom Layer w50: TP54.1@883.78,8515 v2(985,8515)
  other v2: 985.93,8319.55 985.93,8374.81 985.93,8430.06 843.91,9295.77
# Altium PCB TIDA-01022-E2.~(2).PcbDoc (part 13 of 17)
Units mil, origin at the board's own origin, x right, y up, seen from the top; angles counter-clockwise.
Board outline 6929.13 x 11614.17 mil, 12 copper layers (L1_Top Layer, L2_GND, L3_GND, L4_Signal Layer 1, L5_GND, L6_PWR, L7_GND/PWR, L8_PWR, L9_GND/PWR, L10_Signal Layer 2, L11_GND, L12_Bottom Layer), stack 64.6 mil thick; 1711 components, 1001 nets, 5985 pads, 3200 vias.

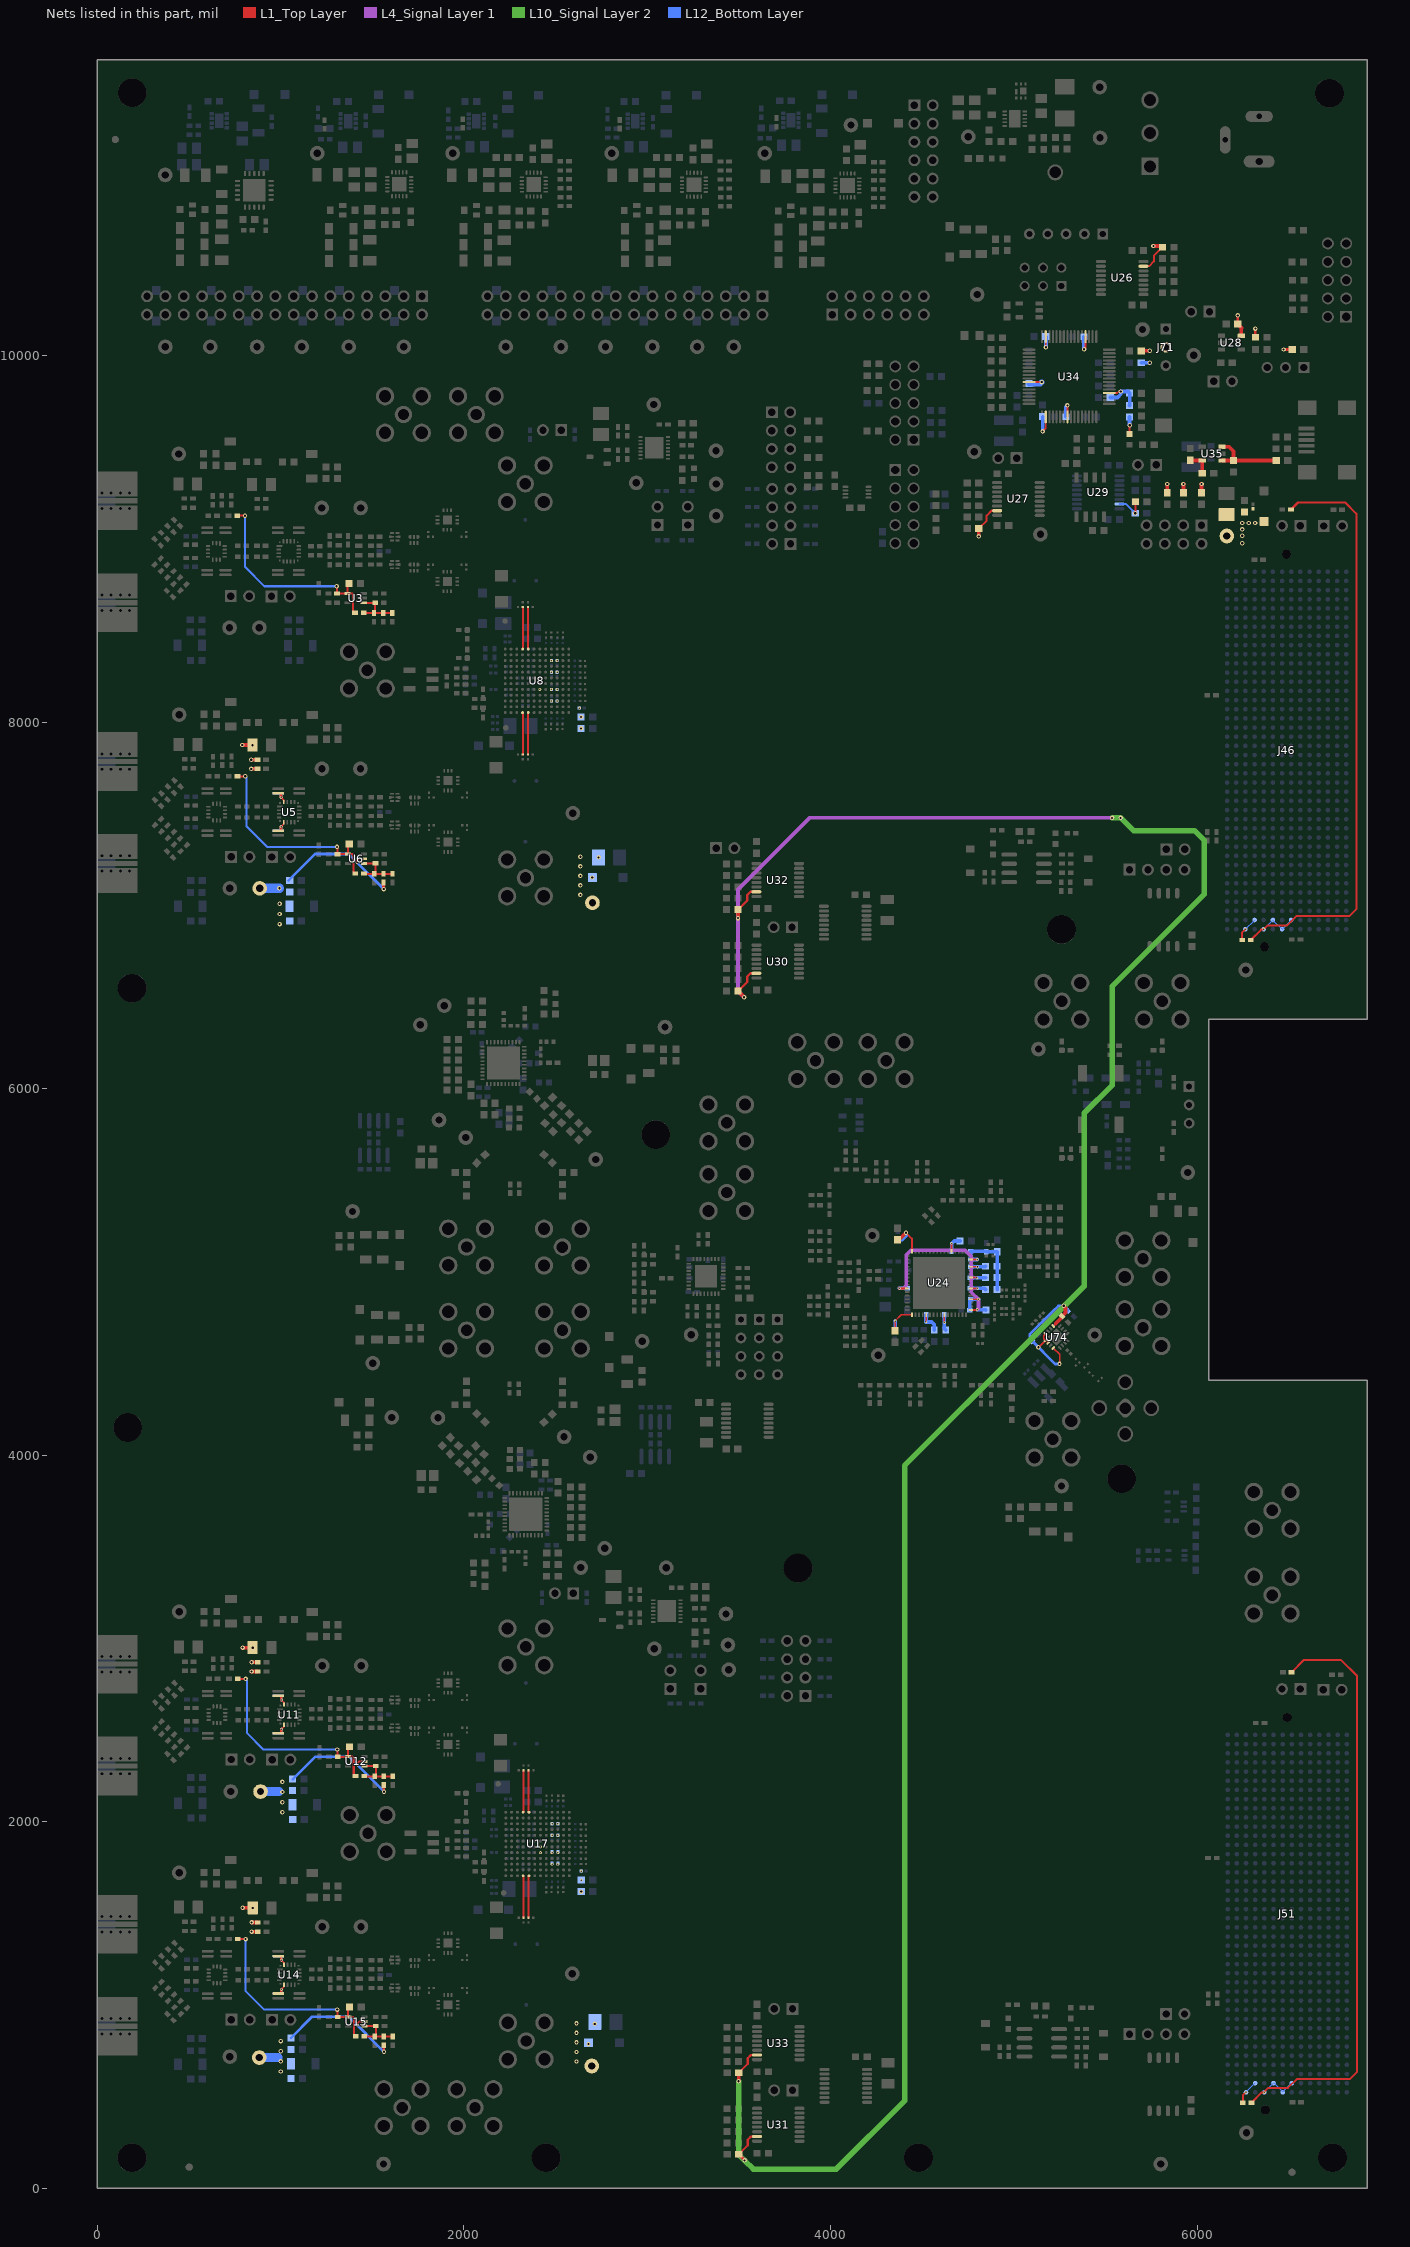
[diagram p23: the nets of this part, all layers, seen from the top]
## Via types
v1: diameter 16, hole 8, L1_Top Layer to L12_Bottom Layer, tented both sides, 1699 vias
v2: diameter 24, hole 12, L1_Top Layer to L12_Bottom Layer, tented both sides, 1501 vias

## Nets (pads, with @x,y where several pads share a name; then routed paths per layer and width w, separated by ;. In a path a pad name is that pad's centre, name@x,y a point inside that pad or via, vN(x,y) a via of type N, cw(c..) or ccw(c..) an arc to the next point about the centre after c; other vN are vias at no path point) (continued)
VA_N1P25_LMH6401_2: C38.2 C42.1 C53.1 C57.2 C64.2 C67.2 C68.2 C699.1 C701.2 C702.1 L62.2 R566.1 TP56.1 U5.5 U5.16 U6.2 | length 1166.4
  L1_Top Layer w10: C57.2@985.89,7406.93 C57.2@999.46,7406.93 ; C38.2@985.89,7611.34 C38.2@999.46,7611.34 ; v1(1001.99,7429.46) 1016.36,7443.83 U5.5@1016.36,7454.01 ; v1(1001.99,7588.8) 1016.36,7574.43 U5.16@1016.36,7564.25 ; v1(1416.99,7233.8) 1416.99,7243.8 1427.32,7254.13 U6.2@1455.18,7254.13
  L1_Top Layer w15: C57.2@1001.99,7409.46 v1(1001.99,7429.46) ; v1(1001.99,7588.8) C38.2@1001.99,7608.8 ; R566.1@1560.71,7125.04 1560.71,7090.09 v2(1561.99,7088.8)
  L1_Top Layer w20: v2(790.46,7874.58) C64.2@845.71,7874.58 ; v2(839.55,7744.58) C68.2@873.27,7744.58 ; v2(839.55,7794.58) C67.2@873.27,7794.58
  L12_Bottom Layer w10: C53.1@985.89,7406.93 C53.1@999.46,7406.93 ; C42.1@985.89,7611.34 C42.1@999.46,7611.34
  L12_Bottom Layer w15: C53.1@1001.99,7409.46 v1(1001.99,7429.46) ; v1(1001.99,7588.8) C42.1@1001.99,7608.8 ; C702.1@1043.09,7135.23 1187.73,7279.87 1370.92,7279.87 v1(1416.99,7233.8) v2(1561.99,7088.8)
  L12_Bottom Layer w50: TP56.1@891.65,7093.2 v2(992.87,7093.2)
  other v2: 993.8,6897.76 993.8,6953.01 993.8,7008.26 845.71,7873.64
VA_N1P25_LMH6401_3: C164.2 C168.1 C179.1 C183.2 C190.2 C193.2 C194.2 C708.1 C710.2 C711.1 L64.2 R575.1 TP60.1 U11.5 U11.16 U12.2 | length 1135.5
  L1_Top Layer w10: C183.2@987.41,2482.69 C183.2@1000.98,2482.69 ; C164.2@987.41,2687.1 C164.2@1000.98,2687.1 ; v1(1003.51,2505.22) 1017.88,2519.59 U11.5@1017.88,2529.78 ; v1(1003.51,2664.57) 1017.88,2650.2 U11.16@1017.88,2640.01 ; v1(1418.51,2309.57) 1418.51,2319.57 1428.84,2329.9 U12.2@1456.7,2329.9
  L1_Top Layer w15: C183.2@1003.51,2485.22 v1(1003.51,2505.22) ; v1(1003.51,2664.57) C164.2@1003.51,2684.57 ; R575.1@1562.23,2200.8 1562.23,2165.85 v2(1563.51,2164.57)
  L1_Top Layer w20: v2(791.98,2950.34) C190.2@847.23,2950.34 ; v2(841.07,2820.34) C194.2@874.79,2820.34 ; v2(841.07,2870.34) C193.2@874.79,2870.34
  L12_Bottom Layer w10: C179.1@987.41,2482.69 C179.1@1000.98,2482.69 ; C168.1@987.41,2687.1 C168.1@1000.98,2687.1
  L12_Bottom Layer w15: C179.1@1003.51,2485.22 v1(1003.51,2505.22) ; v1(1003.51,2664.57) C168.1@1003.51,2684.57 ; C711.1@1066.47,2232.85 1189.25,2355.64 1372.44,2355.64 v1(1418.51,2309.57) v2(1563.51,2164.57)
  L12_Bottom Layer w50: TP60.1@890,2165 991.22,2165
  other v2: 1009.5,2051.91 1009.5,2107.16 1009.5,2162.41 1009.5,2217.66 847.23,2949.4
VA_N1P25_LMH6401_4: C198.2 C202.1 C213.1 C217.2 C224.2 C227.2 C228.2 C717.1 C719.2 C720.1 L66.2 R584.1 TP62.1 U14.5 U14.16 U15.2 | length 1143.7
  L1_Top Layer w10: C217.2@987.48,1063.36 C217.2@1001.05,1063.36 ; C198.2@987.48,1267.77 C198.2@1001.05,1267.77 ; v1(1003.59,1085.89) 1017.96,1100.26 U14.5@1017.96,1110.44 ; v1(1003.59,1245.23) 1017.96,1230.86 U14.16@1017.96,1220.68 ; v1(1418.59,890.23) 1418.59,900.23 1428.91,910.56 U15.2@1456.78,910.56
  L1_Top Layer w15: C217.2@1003.59,1065.89 v1(1003.59,1085.89) ; v1(1003.59,1245.23) C198.2@1003.59,1265.23 ; R584.1@1562.3,781.47 1562.3,746.52 v2(1563.59,745.23)
  L1_Top Layer w20: v2(792.05,1531.01) C224.2@847.3,1531.01 ; v2(841.15,1401.01) C228.2@874.86,1401.01 ; v2(841.15,1451.01) C227.2@874.86,1451.01
  L12_Bottom Layer w10: C213.1@987.48,1063.36 C213.1@1001.05,1063.36 ; C202.1@987.48,1267.77 C202.1@1001.05,1267.77
  L12_Bottom Layer w15: C213.1@1003.59,1065.89 v1(1003.59,1085.89) ; v1(1003.59,1245.23) C202.1@1003.59,1265.23 ; C720.1@1055.53,820.38 1171.45,936.3 1372.52,936.3 v2(1563.59,745.23)
  L12_Bottom Layer w50: TP62.1@883.45,713.81 984.67,713.81
  other v2: 1000.17,637.83 1000.17,693.09 1000.17,748.34 1000.17,803.59 847.3,1530.07
VADJ_RX1: J46.E39 J46.F40 J46.G39 J46.H40 R473.2 R477.2 | length 3412.3
  L1_Top Layer w11: R477.2@6292.73,6811.01 6348.93,6867.21 v1@6362.8,6867.21 ; v1(6363.11,6870.01) 6384.3,6891.2 6491.36,6891.2 6541.36,6941.2 6830.68,6941.2 6868.68,6979.2 6868.68,9137.32 6808,9198 6550.02,9198 R473.2@6511.73,9159.71
  L12_Bottom Layer w5: v1(6363.11,6870.01) J46.G39@6413.11,6920.01 J46.F40@6463.11,6870.01 J46.E39@6513.11,6920.01
VADJ_RX2: J51.E39 J51.F40 J51.G39 J51.H40 R478.2 R482.2 | length 3437.4
  L1_Top Layer w11: R482.2@6296.37,467.81 6352.57,524.01 v1(6366.44,524.01) ; v1@6366.75,526.81 6387.94,548 6495,548 6545,598 6834.32,598 6872.32,636 6872.32,2795.68 6784,2884 6582.86,2884 R478.2@6515.37,2816.51
  L12_Bottom Layer w5: J51.H40@6366.75,526.81 6416.75,576.81 6466.75,526.81 J51.E39@6516.75,576.81
VBUS: C473.1 R470.2 U35.1 U35.3 | length 418.5
  L1_Top Layer w20: U35.1@6136.15,9427.18 6197.32,9427.18 C473.1@6198,9426.5 ; U35.3@6136.15,9501.98 6174.02,9501.98 6198,9478 C473.1@6198,9426.5 ; R470.2@6430.92,9426.85 6198.35,9426.85 C473.1@6198,9426.5
VBUSS: C470.1 L34.1 U35.5 | length 136.3
  L1_Top Layer w20: L34.1@5962,9428.69 5963.51,9427.18 U35.5@6027.88,9427.18 6027.88,9357.94 C470.1@6027.52,9357.58
VCC1_VCO: C420.1 C421.1 C422.1 L22.2 U24.10 U24.33 U24.36 | length 1207.9
  L1_Top Layer w9.84: U24.33@4764.49,4792.09 v1@4795,4792.09 ; U24.36@4764.49,4851.14 v1(4806.68,4851.14)
  L1_Top Layer w10: v1(4375.73,4910.2) U24.10@4418.03,4910.2
  L4_Signal Layer 1 w20: v1(4375.73,4910.2) 4396.2,4910.2 4413,4927 4413,5092 4439,5118 4734,5118 4768,5084 4768,4889.82 v1(4806.68,4851.14) 4806.68,4800.68 v1(4800,4794)
  L12_Bottom Layer w20: v1(4375.73,4910.2) C420.1@4418.03,4910.2 ; C422.1@4759.59,4791.02 4759.59,4846.24 C421.1@4764.49,4851.14 v1(4806.68,4851.14) ; v1(4800,4794) 4843.56,4794 4846.01,4791.55 L22.2@4846.97,4792.51
VCC2_CG1: C430.1 L23.2 U24.17 | length 212
  L1_Top Layer w8.6: L23.2@4350.97,4679.51 4352,4680.54 v1(4352,4732) 4352,4732.47 4386.03,4766.5 U24.17@4443.62,4766.5
  L12_Bottom Layer w20: C430.1@4350.97,4679.51 4352,4680.54 v1(4352,4732)
VCC3_SYSREF: C429.1 L24.2 U24.21 | length 161.4
  L1_Top Layer w8: v1(4520.47,4727.15) 4522.36,4729.04 U24.21@4522.36,4766.5
  L12_Bottom Layer w20: C429.1@4522.36,4766.5 4520.47,4764.6 v1(4520.47,4727.15) 4552.26,4727.15 4565.97,4713.44 L24.2@4565.97,4683.51
VCC4_CG2: C428.1 L25.2 U24.26 | length 127.2
  L1_Top Layer w8: v1(4620.79,4725.26) U24.26@4620.79,4766.5
  L12_Bottom Layer w20: C428.1@4620.79,4766.5 v1(4620.79,4725.26) 4620.79,4690.69 L25.2@4627.97,4683.51
VCC7_OSCOUT: C438.2 L26.2 U24.39 | length 120.5
  L1_Top Layer w9.84: U24.39@4764.49,4910.2 v1(4800.73,4910.2)
  L12_Bottom Layer w20: C438.2@4764.09,4910.94 4764.83,4910.2 v1(4800.73,4910.2) 4839.29,4910.2 L26.2@4845.47,4904.02
VCC8_OSCIN: C437.2 L27.2 U24.42 | length 117.4
  L1_Top Layer w8: v1@4797.16,4969.25 v1(4798.47,4967.94)
  L1_Top Layer w9.84: U24.42@4764.49,4969.25 v1@4797.16,4969.25
  L12_Bottom Layer w20: C437.2@4763.09,4967.94 v1(4798.47,4967.94) 4844.4,4967.94 L27.2@4845.47,4969.02
VCC9_CP2: C436.2 L28.2 U24.45 | length 119.5
  L1_Top Layer w8: v1@4801.1,5028.31 v1(4801.47,5027.94)
  L1_Top Layer w9.84: U24.45@4764.49,5028.31 v1@4801.1,5028.31
  L12_Bottom Layer w20: C436.2@4764.49,5028.31 4764.86,5027.94 v1(4801.47,5027.94) 4842.4,5027.94 L28.2@4845.47,5031.02
VCC10_PLL2: C433.1 C434.1 C435.1 L26.1 L27.1 L28.1 L29.2 U24.47 | length 467.4
  L1_Top Layer w9.84: U24.47@4764.49,5067.68 v1(4800.21,5067.68)
  L12_Bottom Layer w20: v1(4800.21,5067.68) C435.1@4764.49,5067.68 4764.49,5111.54 C434.1@4764.97,5112.02 4847.35,5112.02 C433.1@4848.97,5110.39 4908.85,5110.39 L29.2@4908.97,5110.52 4908.97,5031.52 L28.1@4908.47,5031.02 L27.1@4908.47,4969.02 L26.1@4908.47,4904.02
VCC11_CG3: C440.1 L30.2 U24.53 | length 134.4
  L1_Top Layer w9.84: U24.53@4660.16,5112.95 v1(4660.16,5154.25)
  L12_Bottom Layer w20: C440.1@4660.16,5112.95 v1(4660.16,5154.25) 4674.35,5168.44 L30.2@4706.05,5168.44
VCC12_CG0: C439.1 L31.2 U24.64 | length 250.4
  L1_Top Layer w9.84: v2(4411.62,5214) 4443.62,5181.99 U24.64@4443.62,5112.95
  L1_Top Layer w20: L31.2@4365.97,5175.52 4369.55,5171.94 v2(4411.62,5214)
  L12_Bottom Layer w20: C439.1@4365.97,5175.52 4390.14,5175.52 4411.62,5197 v2(4411.62,5214)
VCMO1: C28.1 R24.1 R556.1 R557.2 R558.2 U3.1 | length 277.9
  L1_Top Layer w11: R24.1@1452.71,8596.26 1454.56,8594.41 R556.1@1508.91,8594.41 ; U3.1@1453.38,8650.67 1514.88,8650.67 C28.1@1515.47,8651.26 1515.47,8600.97 R556.1@1508.91,8594.41 ; R558.2@1607.91,8594.41 R557.2@1558.91,8594.41 R556.1@1508.91,8594.41
VCMO2: C62.1 R48.1 R565.1 R566.2 R567.2 U6.1 | length 277.9
  L1_Top Layer w11: R48.1@1454.51,7174.13 1456.36,7172.28 R565.1@1510.71,7172.28 ; U6.1@1455.18,7228.54 1516.68,7228.54 C62.1@1517.27,7229.13 1517.27,7178.84 R565.1@1510.71,7172.28 ; R567.2@1609.71,7172.28 R565.1@1510.71,7172.28
VCMO3: C188.1 R105.1 R574.1 R575.2 R576.2 U12.1 | length 277.9
  L1_Top Layer w11: R105.1@1456.03,2249.9 1457.88,2248.05 R574.1@1512.23,2248.05 ; U12.1@1456.7,2304.31 1518.2,2304.31 C188.1@1518.79,2304.9 1518.79,2254.6 R574.1@1512.23,2248.05 ; R576.2@1611.23,2248.05 R574.1@1512.23,2248.05
VCMO4: C222.1 R129.1 R583.1 R584.2 R585.2 U15.1 | length 277.9
  L1_Top Layer w11: R129.1@1456.11,830.56 1457.96,828.71 R583.1@1512.3,828.71 ; U15.1@1456.78,884.97 1518.27,884.97 C222.1@1518.86,885.56 1518.86,835.27 R583.1@1512.3,828.71 ; R585.2@1611.3,828.71 R583.1@1512.3,828.71
VCMO_LMH5401_1: C26.1 R2.2 R23.1 R24.2 U3.4 | length 1158.1
  L1_Top Layer w11: R2.2@762.53,9125.99 v2(805.14,9125.99) ; v2(1305.19,8740.93) 1307.71,8738.41 R23.1@1307.71,8701.26 1364.21,8701.26 U3.4@1364.8,8701.85 ; C26.1@1372.6,8756.26 1364.8,8748.46 U3.4@1364.8,8701.85 ; R24.2@1405.47,8596.26 1395.19,8606.53 1395.19,8695.93 1389.28,8701.85 U3.4@1364.8,8701.85
  L12_Bottom Layer w11: v2(805.14,9125.99) 805.14,8846.86 911.07,8740.93 v2(1305.19,8740.93)
VCMO_LMH5401_2: C60.1 R26.2 R47.1 R48.2 U6.4 | length 1150.9
  L1_Top Layer w11: R26.2@764.33,7703.86 v2(806.93,7703.86) ; v2(1306.99,7318.8) 1309.51,7316.28 R47.1@1309.51,7279.13 1366.01,7279.13 U6.4@1366.6,7279.72 ; C60.1@1374.39,7334.13 1366.6,7326.34 U6.4@1366.6,7279.72 ; R48.2@1407.27,7174.13 1396.99,7184.41 1396.99,7273.8 1391.07,7279.72 U6.4@1366.6,7279.72
  L12_Bottom Layer w11: v2(806.93,7703.86) 814,7696.8 814,7430 925.2,7318.8 v2(1306.99,7318.8)
VCMO_LMH5401_3: C186.1 R83.2 R104.1 R105.2 U12.4 | length 1163.4
  L1_Top Layer w11: R83.2@765.85,2779.63 v2(808.45,2779.63) ; v2(1308.51,2394.57) 1311.03,2392.05 R104.1@1311.03,2354.9 1367.53,2354.9 U12.4@1368.12,2355.49 ; C186.1@1375.91,2409.9 1368.12,2402.1 U12.4@1368.12,2355.49 ; R105.2@1408.79,2249.9 1398.51,2260.17 1398.51,2349.57 1392.59,2355.49 U12.4@1368.12,2355.49
  L12_Bottom Layer w11: v2(808.45,2779.63) 815,2773.08 815,2485 905.43,2394.57 v2(1308.51,2394.57)
VCMO_LMH5401_4: C220.1 R107.2 R128.1 R129.2 U15.4 | length 1160.9
  L1_Top Layer w11: R107.2@765.92,1360.29 v2(808.53,1360.29) ; v2(1308.59,975.23) 1311.11,972.71 R128.1@1311.11,935.56 1367.6,935.56 U15.4@1368.19,936.15 ; C220.1@1375.99,990.56 1368.19,982.76 U15.4@1368.19,936.15 ; R129.2@1408.86,830.56 1398.59,840.84 1398.59,930.23 1392.67,936.15 U15.4@1368.19,936.15
  L12_Bottom Layer w11: v2(808.53,1360.29) 808.53,1076.47 909.77,975.23 v2(1308.59,975.23)
VD1P1_ADC1: C149.1 C150.1 C151.1 C152.1 C153.1 C154.1 C155.1 C156.1 C157.1 C158.1 C159.1 C160.1 L39.2 TP6.1 U8.C9 U8.C10 U8.E9 U8.E10 U8.G7 U8.H7 U8.H9 U8.H10 U8.K9 U8.K10
  other v1: 2629.4,8076 2476.91,8114.86 2508.4,8114.86 2413.91,8177.85 2476.91,8177.85 2508.4,8177.85 2413.91,8209.35 2476.91,8272.34 2508.4,8272.34 2476.91,8335.33 2508.4,8335.33
  other v2: 2634.87,7056.72 2634.87,7108.72 2700.23,7151.69 2634.87,7160.72 2634.87,7212.72 2734.39,7261.72 2634.87,7264.72 2639.09,7965.35 2639.09,8027.35
VD1P1_ADC2: C309.1 C310.1 C311.1 C312.1 C313.1 C314.1 C315.1 C316.1 C317.1 C318.1 C319.1 C320.1 L40.2 TP12.1 U17.C9 U17.C10 U17.E9 U17.E10 U17.G7 U17.H7 U17.H9 U17.H10 U17.K9 U17.K10
  other v1: 2640.04,1682.24 2639.78,1731.37 2480.24,1768.86 2511.73,1768.86 2417.24,1831.85 2480.24,1831.85 2511.73,1831.85 2417.24,1863.35 2480.24,1926.34 2511.73,1926.34 2480.24,1989.33 2511.73,1989.33
  other v2: 2613.65,692.32 2613.65,744.32 2679.02,787.29 2613.65,796.32 2613.65,848.32 2713.17,897.32 2613.65,900.32 2640.04,1619.24
VDDL19: C308.2 C442.2 C443.2 C445.2 C446.2 C448.2 C450.2 C452.2 C454.2 C456.2 C482.1 C483.1 C484.1 C512.2 L72.2 R380.1 R381.1 R382.1 R383.1 R384.1 R385.1 TP23.1 U26.15 U27.15 U28.5 U29.15 U30.15 U31.15 U32.15 U33.15 U74.9 U74.12 U74.13 U74.14 U74.16 | length 15054.8
  L1_Top Layer w8: v2(5133.59,4589) 5135.16,4589 U74.13@5172.78,4626.62 ; U74.12@5172.78,4662.81 5163,4653.03 5163,4636.4 U74.13@5172.78,4626.62 ; U74.14@5186.7,4612.7 U74.13@5172.78,4626.62 ; U74.16@5214.54,4584.86 5249,4550.4 v2(5249,4498) ; U74.9@5214.54,4704.57 5228.97,4719
  L1_Top Layer w11: C443.2@4808.82,9056.2 4851,9098.38 4851,9126.28 4877.94,9153.22 U27.15@4908.68,9153.22 ; v2(5661.82,9139.2) 5663.13,9140.51 R385.1@5663.13,9202.01 ; U26.15@5707,10486.95 5737.95,10486.95 5764,10513 5764,10543.77 C442.2@5810.35,10590.12
  L1_Top Layer w12: C450.2@3495.47,6532.22 3545.07,6581.82 3545.07,6611.73 3562.59,6629.24 U30.15@3595.33,6629.24 ; C454.2@3495.47,6976.93 3545.07,7026.53 3545.07,7056.43 3562.59,7073.95 U32.15@3595.33,7073.95 ; C452.2@3498.8,186.22 3548.4,235.82 3548.4,265.73 3565.92,283.25 U31.15@3598.66,283.25 ; C456.2@3498.8,630.93 3548.4,680.53 3548.4,710.44 3565.92,727.96 U33.15@3598.66,727.96
  L1_Top Layer w15: C445.2@6221.58,10170.75 v2(6221.58,10218.46) ; R382.1@6317.5,10099 v2(6317.5,10146.72) ; v2(6471.29,10032.5) R380.1@6519.01,10032.5
  L1_Top Layer w20: v2(3495.07,6930.43) 3495.47,6930.83 C454.2@3495.47,6976.93 ; C450.2@3495.47,6532.22 3528.06,6499.63 v2(3528.06,6499.06) ; v2(3498.4,584.44) 3498.8,584.84 C456.2@3498.8,630.93 ; C452.2@3498.56,185.98 3531.15,153.38 v2(3531.15,152.82) ; v2(4808,9013) 4808.82,9013.82 C443.2@4808.82,9056.2 ; 5228.97,4719 5262.59,4752.62 C512.2@5262.59,4758.41 5282,4777.81 5282,4805 v2(5272,4815) ; v2(5761,10597) 5803.46,10597 C442.2@5810.35,10590.12 ; R384.1@5837,9251.5 v2(5837,9299) ; R383.1@5925,9251.5 v2(5925,9299) ; R381.1@6024,9251.5 v2(6024,9299) ; C445.2@6221.58,10170.75 6242.4,10149.93 6240.72,10148.25 U28.5@6240.72,10107.31
  L4_Signal Layer 1 w20: v2(3528.06,6499.06) 3495.07,6532.05 v2(3495.07,6930.43) 3495.07,7087.07 3885,7477 v2(5536,7477)
  L10_Signal Layer 2 w30: v2(3498.4,584.44) 3498.4,185.57 v2(3531.15,152.82) 3578.97,105 4031,105 4404,478 4404,3942.92 5067.54,4606.46 5272.04,4810.96 5384,4922.92 5384,5866 5536,6018 5536,6558 6039,7061 6039,7354 5985,7408 5653,7408 5584,7477 v2(5582,7477) v2(5536,7477)
  L12_Bottom Layer w11: U29.15@5575.96,9189.02 5612,9189.02 v2(5661.82,9139.2)
  L12_Bottom Layer w15: v2(5249,4498) 5224.59,4498 C446.2@5100.3,4622.3 5086,4636.59 5086,4658 5211,4783 5243,4815 v2(5272,4815) 5272,4811 C308.2@5293.59,4789.41
  other v2: 6246,8975 6246,9016 6246,9051 6246,9086 6281,9086 6316,9086
VIN1_N: R552.2 R604.2 U8.A4 | length 229.4
  L1_Top Layer w10: U8.A4@2319.43,8398.32 ccw(c2315.21,8402.54) 2321.17,8402.54 R552.2@2321.17,8627.08 ; R552.2@2321.26,8627.43 R552.2@2321.36,8627.33
VIN1_P: R551.2 R592.2 U8.A5 | length 229.6
  L1_Top Layer w10: R551.2@2349.36,8627.2 R551.2@2349.27,8627.3 2349.17,8627.2 2349.17,8402.54 ccw(c2355.14,8402.54) U8.A5@2350.92,8398.32
VIN2_N: R561.2 R606.2 U8.M5 | length 229.4
  L1_Top Layer w10: R561.2@2349.08,7823.01 2349.17,7823.11 2349.17,8047.65 cw(c2355.14,8047.65) U8.M5@2350.92,8051.87
VIN2_P: R560.2 R605.2 U8.M4 | length 229.5
  L1_Top Layer w10: U8.M4@2319.43,8051.87 cw(c2315.2,8047.65) 2321.17,8047.65 2321.17,7822.98 R560.2@2321.08,7822.89
VIN3_N: R570.2 R608.2 U17.A4 | length 229.4
  L1_Top Layer w10: U17.A4@2322.76,2052.33 ccw(c2318.54,2056.55) 2324.5,2056.55 R570.2@2324.5,2281.09 ; R570.2@2324.59,2281.43 R570.2@2324.69,2281.33
VIN3_P: R569.2 R607.2 U17.A5 | length 229.3
  L1_Top Layer w10: R569.2@2352.5,2281.21 R607.2@2352.58,2280.94 2352.5,2056.55 ccw(c2358.47,2056.55) U17.A5@2354.25,2052.33
VIN4_N: R579.2 R610.2 U17.M5 | length 229.4
  L1_Top Layer w10: R610.2@2352.41,1477.01 2352.5,1477.11 2352.5,1701.65 cw(c2358.47,1701.65) U17.M5@2354.25,1705.87
VIN4_P: R578.2 R609.2 U17.M4 | length 229.3
  L1_Top Layer w10: U17.M4@2322.76,1705.87 cw(c2318.54,1701.65) 2324.5,1701.65 R578.2@2324.5,1476.99
VIO_B_M2C_RX1: J46.J39 J46.K40 R477.1 | length 137
  L1_Top Layer w11: R477.1@6245.48,6811.01 6245.48,6852.39 v1(6263.11,6870.01)
  L12_Bottom Layer w5: v1(6263.11,6870.01) J46.J39@6313.11,6920.01
VIO_B_M2C_RX2: J51.J39 J51.K40 R482.1 | length 137
  L1_Top Layer w11: R482.1@6249.13,467.81 6249.13,509.19 v1@6266.75,526.81
  L12_Bottom Layer w5: J51.K40@6266.75,526.81 J51.J39@6316.75,576.81
  other v1: 6266.44,524.01
VPHY: C457.1 C458.2 L32.2 U34.4 | length 265.5
  L1_Top Layer w10: U34.4@5520.39,9795.39 5564.42,9795.39 5572.47,9803.44 v2(5583.42,9803.44)
  L12_Bottom Layer w20: C458.2@5525.38,9770.97 5565.37,9770.97 5583.42,9789.02 v2(5583.42,9803.44) 5622.92,9803.44 C457.1@5631.39,9794.97 5631.39,9727.97 L32.2@5630.88,9727.47
VREGIN: C462.2 C463.2 C464.2 C465.2 C469.2 D17.1 J71.2 L32.1 L33.1 R543.1 U34.20 U34.31 U34.42 U34.50 U34.56 | length 884.9
  L1_Top Layer w10: U34.42@5083.38,9854.44 v2@5151.84,9854.44 ; v2@5157.87,9584.47 v2(5156.87,9585.47) 5156.87,9586.41 5173.93,9603.47 U34.50@5173.93,9665.47 ; U34.31@5173.93,10102.47 5173.93,10043.53 v2(5174.87,10044.47) ; v2(5291.87,9727.47) 5292.04,9727.3 U34.56@5292.04,9665.47 ; v2(5382.87,10033.47) 5390.47,10041.07 U34.20@5390.47,10102.47
  L1_Top Layer w11: D17.1@5630.88,9571.5 5630.88,9618.49 v2(5631.87,9619.47)
  L1_Top Layer w20: R543.1@5694.38,10024.97 5740.37,10024.97 v2(5740.87,10025.47)
  L12_Bottom Layer w20: v2(5156.87,9585.47) C469.2@5156.87,9666.48 ; C462.2@5173.38,10102.97 5174.87,10101.48 v2(5174.87,10044.47) ; C465.2@5284.17,9665.47 5284.17,9719.77 v2(5291.87,9727.47) ; C464.2@5382.59,10102.47 5382.59,10033.75 v2(5382.87,10033.47) ; L32.1@5630.88,9664.47 5630.88,9620.46 v2(5631.87,9619.47) ; L33.1@5694.38,9959.97 5740.37,9959.97 v2(5740.87,9960.47)
  L12_Bottom Layer w30: C463.2@5083.38,9846.57 5143.97,9846.57 v2(5151.87,9854.47)
pads on no net: FID1.1 FID2.1 FID3.1 FID4.1 FID5.1 FID6.1 J31.1 J31.7 J31.10 J32.1 J32.7 J39.7 J46.A21 J46.A22 J46.A23 J46.A26 J46.A27 J46.A30 J46.A31 J46.A34 J46.A35 J46.A38 J46.A39 J46.B1 J46.B2 J46.B19 J46.B20 J46.B21 J46.B22 J46.B23 J46.B24 J46.B25 J46.B28 J46.B29 J46.B32 J46.B33 J46.B36 J46.B37 J46.B40 J46.C1 J46.C2 J46.C3 J46.C4 J46.C9 J46.C10 J46.C11 J46.C12 J46.C13 J46.C14 J46.C15 J46.C16 J46.C17 J46.C18 J46.C19 J46.C20 J46.C21 J46.C22 J46.C23 J46.C26 J46.C27 J46.D2 J46.D7 J46.D8 J46.D9 J46.D10 J46.D11 J46.D12 J46.D13 J46.D14 J46.D15 J46.D16 J46.D17 J46.D18 J46.D19 J46.D20 J46.D21 J46.D22 J46.D23 J46.D24 J46.D27 J46.D29 J46.D33 J46.D34 J46.E1 J46.E2 J46.E3 J46.E4 J46.E5 J46.E6 J46.E7 J46.E8 J46.E9 J46.E10 J46.E11 J46.E12 J46.E13 J46.E14 J46.E15 J46.E16 J46.E17 J46.E18 J46.E19 J46.E20 J46.E21 J46.E22 J46.E23 J46.E24 J46.E25 J46.E27 J46.E28 J46.E30 J46.E31 J46.E33 J46.E34 J46.E36 J46.E37 J46.F2 J46.F3 J46.F4 J46.F5 J46.F6 J46.F7 J46.F8 J46.F9 J46.F10 J46.F11 J46.F12 J46.F13 J46.F14 J46.F15 J46.F16 J46.F17 J46.F18 J46.F19 J46.F20 J46.F21 J46.F22 J46.F23 J46.F24 J46.F25 J46.F26 J46.F28 J46.F29 J46.F31 J46.F32 J46.F34 J46.F35 J46.F37 J46.F38 J46.G1 J46.G2 J46.G3 J46.G4 J46.G15 J46.G16 J46.G17 J46.G18 J46.G19 J46.G20 J46.G21 J46.G22 J46.G23 J46.G24 J46.G25 J46.G28 J46.G30 J46.G31 J46.G33 J46.G34 J46.G36 J46.G37 J46.H1 J46.H3 J46.H4 J46.H5 J46.H6 J46.H7 J46.H8 J46.H9 J46.H10 J46.H11 J46.H12 J46.H13 J46.H14 J46.H15 J46.H16 J46.H17 J46.H18 J46.H19 J46.H20 J46.H21 J46.H22 J46.H23 J46.H24 J46.H25 J46.H26 J46.H28 J46.H29 J46.H32 J46.H34 J46.H35 J46.H37 J46.H38 J46.J1 J46.J2 J46.J3 J46.J4 J46.J5 J46.J6 J46.J7 J46.J8 J46.J9 J46.J10 J46.J11 J46.J12 J46.J13 J46.J14 J46.J16 J46.J17 J46.J18 J46.J19 J46.J20 J46.J21 J46.J22 J46.J23 J46.J24 J46.J25 J46.J26 J46.J27 J46.J28 J46.J30 J46.J31 J46.J33 J46.J34 J46.J36 J46.J37 J46.K1 J46.K2 J46.K3 J46.K4 J46.K5 J46.K6 J46.K7 J46.K8 J46.K9 J46.K10 J46.K11 J46.K12 J46.K13 J46.K14 J46.K15 J46.K16 J46.K17 J46.K18 J46.K19 J46.K20 J46.K21 J46.K22 J46.K23 J46.K24 J46.K25 J46.K26 J46.K27 J46.K28 J46.K29 J46.K31 J46.K32 J46.K34 J46.K35 J46.K37 J46.K38 J46.L1 J46.L2 J46.L3 J46.L4 J46.L5 J46.L6 J46.L7 J46.L8 J46.L9 J46.L10 J46.L11 J46.L12 J46.L13 J46.L14 J46.L15 J46.L16 J46.L17 J46.L18 J46.L19 J46.L20 J46.L21 J46.L22 J46.L23 J46.L24 J46.L25 J46.L26 J46.L27 J46.L28 J46.L29 J46.L32 J46.L33 J46.L36 J46.L37 J46.L40 J46.M2 J46.M3 J46.M4 J46.M5 J46.M6 J46.M7 J46.M8 J46.M9 J46.M10 J46.M11 J46.M12 J46.M13 J46.M14 J46.M15 J46.M16 J46.M17 J46.M18 J46.M19 J46.M20 J46.M21 J46.M22 J46.M23 J46.M24 J46.M25 J46.M26 J46.M27 J46.M28 J46.M30 J46.M31 J46.M34 J46.M35 J46.M38 J46.M39 J46.MH1 J46.MH2 J46.Y1 J46.Y2 J46.Y3 J46.Y6 J46.Y7 J46.Y26 J46.Y27 J46.Y30 J46.Y31 J46.Y34 J46.Y35 J46.Y38 J46.Y39 J46.Z4 J46.Z5 J46.Z6 J46.Z8 J46.Z9 J46.Z24 J46.Z25 J46.Z28 J46.Z29 J46.Z32 J46.Z33 J46.Z36 J46.Z37 J46.Z40 J51.A21 J51.A22 J51.A23 J51.A26 J51.A27 J51.A30 J51.A31 J51.A34 J51.A35 J51.A38 J51.A39 J51.B1 J51.B2 J51.B19 J51.B20 J51.B21 J51.B22 J51.B23 J51.B24 J51.B25 J51.B28 J51.B29 J51.B32 J51.B33 J51.B36 J51.B37 J51.B40 J51.C1 J51.C2 J51.C3 J51.C4 J51.C9 J51.C10 J51.C11 J51.C12 J51.C13 J51.C14 J51.C15 J51.C16 J51.C17 J51.C18 J51.C19 J51.C20 J51.C21 J51.C22 J51.C23 J51.C26 J51.C27 J51.D2 J51.D7 J51.D8 J51.D9 J51.D10 J51.D11 J51.D12 J51.D13 J51.D14 J51.D15 J51.D16 J51.D17 J51.D18 J51.D19 J51.D20 J51.D21 J51.D22 J51.D23 J51.D24 J51.D27 J51.D29 J51.D33 J51.D34 J51.E1 J51.E2 J51.E3 J51.E4 J51.E5 J51.E6 J51.E7 J51.E8 J51.E9 J51.E10 J51.E11 J51.E12 J51.E13 J51.E14 J51.E15 J51.E16 J51.E17 J51.E18 J51.E19 J51.E20 J51.E21 J51.E22 J51.E23 J51.E24 J51.E25 J51.E27 J51.E28 J51.E30 J51.E31 J51.E33 J51.E34 J51.E36 J51.E37 J51.F2 J51.F3 J51.F4 J51.F5 J51.F6 J51.F7 J51.F8 J51.F9 J51.F10 J51.F11 J51.F12 J51.F13 J51.F14 J51.F15 J51.F16 J51.F17 J51.F18 J51.F19 J51.F20 J51.F21 J51.F22 J51.F23 J51.F24 J51.F25 J51.F26 J51.F28 J51.F29 J51.F31 J51.F32 J51.F34 J51.F35 J51.F37 J51.F38 J51.G1 J51.G2 J51.G3 J51.G4 J51.G15 J51.G16 J51.G17 J51.G18 J51.G19 J51.G20 J51.G21 J51.G22 J51.G23 J51.G24 J51.G25 J51.G28 J51.G30 J51.G31 J51.G33 J51.G34 J51.G36 J51.G37 J51.H1 J51.H3 J51.H4 J51.H5 J51.H6 J51.H7 J51.H8 J51.H9 J51.H10 J51.H11 J51.H12 J51.H13 J51.H14 J51.H15 J51.H16 J51.H17 J51.H18 J51.H19 J51.H20 J51.H21 J51.H22 J51.H23 J51.H24 J51.H25 J51.H26 J51.H28 J51.H29 J51.H32 J51.H34 J51.H35 J51.H37 J51.H38 J51.J1 J51.J2 J51.J3 J51.J4 J51.J5 J51.J6 J51.J7 J51.J8 J51.J9 J51.J10 J51.J11 J51.J12 J51.J13 J51.J14 J51.J16 J51.J17 J51.J18 J51.J19 J51.J20 J51.J21 J51.J22 J51.J23 J51.J24 J51.J25 J51.J26 J51.J27 J51.J28 J51.J30 J51.J31 J51.J33 J51.J34 J51.J36 J51.J37 J51.K1 J51.K2 J51.K3 J51.K4 J51.K5 J51.K6 J51.K7 J51.K8 J51.K9 J51.K10 J51.K11 J51.K12 J51.K13 J51.K14 J51.K15 J51.K16 J51.K17 J51.K18 J51.K19 J51.K20 J51.K21 J51.K22 J51.K23 J51.K24 J51.K25 J51.K26 J51.K27 J51.K28 J51.K29 J51.K31 J51.K32 J51.K34 J51.K35 J51.K37 J51.K38 J51.L1 J51.L2 J51.L3 J51.L4 J51.L5 J51.L6 J51.L7 J51.L8 J51.L9 J51.L10 J51.L11 J51.L12 J51.L13 J51.L14 J51.L15 J51.L16 J51.L17 J51.L18 J51.L19 J51.L20 J51.L21 J51.L22 J51.L23 J51.L24 J51.L25 J51.L26 J51.L27 J51.L28 J51.L29 J51.L32 J51.L33 J51.L36 J51.L37 J51.L40 J51.M2 J51.M3 J51.M4 J51.M5 J51.M6 J51.M7 J51.M8 J51.M9 J51.M10 J51.M11 J51.M12 J51.M13 J51.M14 J51.M15 J51.M16 J51.M17 J51.M18 J51.M19 J51.M20 J51.M21 J51.M22 J51.M23 J51.M24 J51.M25 J51.M26 J51.M27 J51.M28 J51.M30 J51.M31 J51.M34 J51.M35 J51.M38 J51.M39 J51.MH1 J51.MH2 J51.Y1 J51.Y2 J51.Y3 J51.Y6 J51.Y7 J51.Y26 J51.Y27 J51.Y30 J51.Y31 J51.Y34 J51.Y35 J51.Y38 J51.Y39 J51.Z4 J51.Z5 J51.Z6 J51.Z8 J51.Z9 J51.Z24 J51.Z25 J51.Z28 J51.Z29 J51.Z32 J51.Z33 J51.Z36 J51.Z37 J51.Z40 J58.2 J58.3 J58.4 J58.5 J58.6 J58.7 J58.8 J58.9 J58.10 J72.4 LBL1.0 LF1.4 LF1.6 LF2.4 LF2.6 LF3.4 LF3.6 LF4.4 LF4.6 LF5.4 LF5.6 LF6.4 LF6.6 LF7.4 LF7.6 LF8.4 LF8.6 Q3.0 S1.1 S2.1 S3.1 S4.1 S5.1 S6.1 S7.1 S8.1 S9.1 S10.1 S11.1 S12.1 S17.3 T1.2 T2.2 U2. U5. U9.1 U9.3 U9.4 U11. U14. U18.1 U18.3 U18.4 U23.11 U23.12 U23.18 U23.19 U23.21 U23.22 U23.25 U23.26 U23.27 U23.29 U23.31 U24.8 U24.9 U25.1@5590.22,5913 U25.1@5621.72,5913 U25.2@5490.22,5913 U25.2@5521.72,5913 U25.3@5390.22,5913 U25.3@5421.72,5913 U25.4@5390.22,6058.67 U25.4@5421.72,6058.67 U25.5@5490.22,6058.67 U25.5@5521.72,6058.67 U25.6@5590.22,6058.67 U25.6@5621.72,6058.67 U29.6 U29.11 U34.36 U34.60 U35.4 U36.7 U37.7 U38.9 U38.11@4994.86,11231.57 U38.11@4994.86,11352.04 U38.11@5004.7,11267 U38.11@5004.7,11316.61 U38.11@5014.54,11231.57 U38.11@5014.54,11352.04 U39.0 U42.0 U45.0 U48.0 U50.5 U50.6 U50.7 U50.9 U50.10 U50.11 U51.0 U51.7 U53.2 U53.4 U53.5 U53.6 U53.8 U53.9 U53.10 U53.11 U53.12 U53.17 U53.18 U53.19 U56.6 U56.7 U58.10 U58.11 U58.12 U74.3

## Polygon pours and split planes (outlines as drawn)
DGND on L1_Top Layer "12" (solid, remove dead copper, pour order 1733): 107 vertices, not listed, extent 1262,70 6899,10776
V3P3 on L1_Top Layer "12" (solid, pour order 1731): 4650,10668 4615.15,10668 4606,10677.14 4606,10761 4615,10770 4666,10770 4674,10762 4674,10678 4664,10668
DGND on L1_Top Layer "12" (solid, pour order 1723): 2216,1522 2129,1522 2124,1527 2124,1673 2143,1692 2180,1692 2191,1681 2191,1596 2197,1590 2213,1590 2216,1587 2216,1525 2213,1522
DGND on L1_Top Layer "12" (solid, pour order 1721): 2129,7867 2134,7862 2206,7862 2213,7869 2213,8031 2199,8045 2142,8045 2129,8032
AGND on L1_Top Layer "12" (solid, pour order 1420): 248,10255 688,10255 704,10239 704,10001 693,9990 250,9990 238,10002 238,10245 248,10255
AGND on L1_Top Layer "12" (solid, pour order 1424): 1048,10255 1487,10255 1503,10239 1503,9998 1495,9990 1050,9990 1038,10002 1038,10245 1048,10255
AGND on L1_Top Layer "12" (solid, pour order 1719): 93 vertices, not listed, extent 17.27,478 2555.33,10255
V3P3 on L1_Top Layer "12" (solid, pour order 1670): 5890,4047 5487.84,3644.84 5374.65,3644.84 5286.84,3644.84 5272,3630 5272,3520 5279,3513 5965.59,3513 6019.07,3566.48 6019.07,4087.07 6019.07,5187.93 6008,5199 5904,5199 5890,5185
12V on L1_Top Layer "V" (solid, pour order 1364): 4814.02,11259.5 4814.02,11163.02 4783,11132 4422,11132 4407,11147 4407,11388 4420,11401 4589,11401 4651,11339 4958,11339 4964,11333 4964,11289 4957,11282 4836.51,11282
V3P3_IN on L1_Top Layer "V" (solid, pour order 1360): 24 vertices, not listed, extent 3393,10289 3978.12,10810
GND on L1_Top Layer "V" (solid, pour order 1354): 18 vertices, not listed, extent 2696,10291 2908.51,10730.64
V1P9V_IN on L1_Top Layer "V" (solid, pour order 1350): 24 vertices, not listed, extent 2891,10288 3162,10812
GND on L1_Top Layer "V" (solid, pour order 1272): 23 vertices, not listed, extent 3641.49,10471.63 3967.49,10938.63
NetC616_1 on L1_Top Layer "V" (solid, pour order 1270): 20 vertices, not listed, extent 3894.49,10598.63 4058.49,10913.63
GND on L1_Top Layer "V" (solid, pour order 1260): 23 vertices, not listed, extent 2804.51,10475.64 3130.51,10942.64
NetC519_1 on L1_Top Layer "V" (solid, pour order 1250): 20 vertices, not listed, extent 3057.51,10602.64 3221.51,10917.64
DGND on L1_Top Layer "V" (solid, pour order 1142): 2119,10255 2344,10255 2360,10239 2360,9998 2352,9990 2107,9990 2095,10002 2095,10221 2095,10245 2105,10255
DGND on L1_Top Layer "V" (solid, pour order 1140): 2719,10255 2844,10255 2860,10239 2860,10001 2849,9990 2707,9990 2695,10002 2695,10221 2695,10245 2705,10255
NetC414_2 on L1_Top Layer "L1_Top Layer-No Net" (solid, pour order 944): 5599,5853 5512.86,5853 5505.97,5846.11 5505.97,5712.03 5514,5704 5595,5704 5602,5711 5602,5851 5600,5853
VA3P75_LMH6401_4 on L1_Top Layer "L1_Top Layer-No Net" (solid, pour order 924): 1054.17,1699.36 1054.17,1579.15 1103.23,1530.1 1345.91,1530.1 1357.17,1541.36 1357.17,1606.15 1353.96,1609.36 1131.17,1609.36 1106.17,1634.36 1106.17,1688.36 1106.17,1710.36 1100.17,1716.36 1059.17,1716.36 1054.17,1711.36
VA3P75_LMH6401_3 on L1_Top Layer "L1_Top Layer-No Net" (solid, pour order 922): 1055.1,3123.7 1055.1,3003.49 1104.15,2954.43 1346.83,2954.43 1358.1,2965.7 1358.1,3030.49 1354.89,3033.7 1132.1,3033.7 1107.1,3058.7 1107.1,3112.7 1107.1,3134.7 1101.1,3140.7 1060.1,3140.7 1055.1,3135.7
VA3P75_LMH6401_1 on L1_Top Layer "L1_Top Layer-No Net" (solid, pour order 920): 1052.2,9440.13 1052.2,9319.91 1101.26,9270.86 1343.94,9270.86 1355.2,9282.13 1355.2,9346.92 1351.99,9350.13 1129.2,9350.13 1104.2,9375.13 1104.2,9429.13 1104.2,9451.13 1098.2,9457.13 1057.2,9457.13 1052.2,9452.13
VA3P75_LMH6401_2 on L1_Top Layer "L1_Top Layer-No Net" (solid, pour order 918): 1054,8018 1054,7897.79 1103.05,7848.73 1345.73,7848.73 1357,7860 1357,7924.79 1353.79,7928 1131,7928 1106,7953 1106,8007 1106,8029 1100,8035 1059,8035 1054,8030
GND on L1_Top Layer "h" (solid, pour order 96): 26 vertices, not listed, extent 4657,11060.73 5190.32,11465.73
NetC587_1 on L1_Top Layer "h" (solid, pour order 788): 17 vertices, not listed, extent 2014.25,10943.23 2347.59,11041.54
DGND on L1_Top Layer "h" (solid, pour order 18): 1294.94,5158.3 1408.94,5158.3 1442.94,5124.3 1570.61,5124.3 1588.94,5105.96 1588.94,5009.3 1576.94,4997.3 1297.94,4997.3 1277.39,5017.84 1277.39,5148.75 1286.94,5158.3
V3P3_LMX1 on L1_Top Layer "h" (solid, pour order 16): 1297.94,5175.3 1674.6,5175.3 1685.6,5186.3 1685.6,5387.64 1672.94,5400.3 1288.94,5400.3 1277.39,5388.75 1277.39,5185.61 1287.7,5175.3
DGND on L1_Top Layer "h" (solid, pour order 2): 3072.57,6173.77 3187.57,6173.77 3197.57,6163.77 3197.57,6056.77 3177.57,6036.77 2980.57,6036.77 2970.57,6046.77 2970.57,6165.77 2978.57,6173.77
V3P3_LMX1RF on L1_Top Layer "h" (solid, pour order 0): 2886.57,6192.77 3189.57,6192.77 3198.57,6201.77 3198.57,6400.77 3180.57,6418.77 3174.57,6424.77 3023.57,6424.77 2888.57,6424.77 2867.57,6403.77 2867.57,6211.77
V3P3_LMX2RF on L1_Top Layer "h" (solid, pour order 22): 1457.92,4312.38 1457.92,4009.38 1466.92,4000.38 1665.92,4000.38 1683.92,4018.38 1689.92,4024.38 1689.92,4175.38 1689.92,4310.38 1668.92,4331.38 1476.92,4331.38
DGND on L1_Top Layer "h" (solid, pour order 24): 1438.92,4126.38 1438.92,4011.38 1428.92,4001.38 1321.92,4001.38 1301.92,4021.38 1301.92,4218.38 1311.92,4228.38 1430.92,4228.38 1438.92,4220.38
V3P3_LMX2 on L1_Top Layer "h" (solid, pour order 28): 1783.57,4656.9 1406.91,4656.9 1395.91,4645.9 1395.91,4444.56 1408.57,4431.9 1792.57,4431.9 1810.57,4449.9 1810.57,4646.9 1800.57,4656.9
DGND on L1_Top Layer "h" (solid, pour order 30): 1786.57,4673.9 1672.57,4673.9 1638.57,4707.9 1510.9,4707.9 1492.57,4726.23 1492.57,4822.9 1504.57,4834.9 1783.57,4834.9 1801.57,4816.9 1801.57,4680.9 1794.57,4673.9
DGND on L1_Top Layer "h" (solid, pour order 44): 4950,3675 5064,3675 5098,3641 5203.24,3641 5229.23,3615.01 5229.23,3524.01 5219.22,3514 4953,3514 4935,3532 4935,3668 4942,3675
V3P3_LMK48XX on L1_Top Layer "h" (solid, pour order 60): 4952.23,3695.01 5343.23,3695.01 5349.23,3701.01 5349.23,3892.01 5338.23,3903.01 5333.23,3908.01 5223.23,3908.01 5026.23,3908.01 4942.23,3824.01 4942.23,3702.01 4949.23,3695.01
NetC516_1 on L1_Top Layer "h" (solid, pour order 140): 17 vertices, not listed, extent 2888.08,10942.37 3221.42,11040.68
DGND on L1_Top Layer "h" (solid, pour order 254): 3943.07,6933.73 3995,6933.73 3995,7044.73 3988,7051.73 3939.07,7051.73 3930.07,7042.73 3930.07,6939.73 3936.07,6933.73
V3P3_VDD on L1_Top Layer "h" (solid, pour order 258): 4876.4,10598.82 4980.4,10598.82 4992.4,10586.82 4992.4,10450.4 4956.82,10414.82 4627.4,10414.82 4608.4,10433.82 4608.4,10585.82 4621.4,10598.82
DGND on L1_Top Layer "h" (solid, pour order 260): 4966.4,10611.82 4868.4,10611.82 4851.4,10628.82 4835.4,10644.82 4717.4,10644.82 4707.34,10644.82 4696.47,10655.69 4696.47,10711.9 4696.47,10733.9 4702.4,10739.82 4717.4,10754.82 4972.4,10754.82 5001.4,10725.82 5001.4,10619.82 4993.4,10611.82
VA3P75_LMH5401_1 on L1_Top Layer "V" (solid, pour order 280): 835.19,9430.93 835.19,9370.93 820.19,9355.93 800.19,9335.93 590.19,9335.93 545.19,9380.93 545.19,9410.93 555.19,9420.93 670.19,9420.93 695.19,9445.93 830.19,9445.93 835.19,9440.93
AGND on L1_Top Layer "V" (solid, pour order 282): 660.19,9440.93 550.19,9440.93 540.19,9450.93 540.19,9550.93 550.19,9560.93 755.19,9560.93 765.19,9550.93 765.19,9495.93 755.19,9485.93 705.19,9485.93
VA3P75 on L1_Top Layer "V" (solid, pour order 284): 1022.93,9380.93 865.19,9380.93 855.19,9390.93 855.19,9475.93 870.2,9490.93 1020.19,9490.93 1029,9482.13 1029,9387
AGND on L1_Top Layer "V" (solid, pour order 288): 1174.14,9370.86 1345.26,9370.86 1355.26,9380.86 1355.26,9480.86 1345.26,9490.86 1140.26,9490.86 1130.26,9480.86 1130.26,9414.74
AGND on L1_Top Layer "V" (solid, remove dead copper, pour order 300): 1162.27,7948.73 1347.05,7948.73 1357.05,7958.73 1357.05,8057.94 1346.27,8068.73 1142.05,8068.73 1132.05,8058.73 1132.05,7978.95
VA3P75 on L1_Top Layer "V" (solid, pour order 304): 1022.8,7958.8 866.99,7958.8 856.99,7968.8 856.99,8053.8 871.99,8068.8 1021.99,8068.8 1032,8058.8 1032,7968
AGND on L1_Top Layer "V" (solid, pour order 306): 661.99,8018.8 551.99,8018.8 541.99,8028.8 541.99,8128.8 551.99,8138.8 756.99,8138.8 766.99,8128.8 766.99,8073.8 756.99,8063.8 706.99,8063.8
VA3P75_LMH5401_2 on L1_Top Layer "V" (solid, pour order 308): 836.99,8008.8 836.99,7948.8 821.99,7933.8 801.99,7913.8 591.99,7913.8 546.99,7958.8 546.99,7988.8 556.99,7998.8 671.99,7998.8 696.99,8023.8 831.99,8023.8 836.99,8018.8
AGND on L1_Top Layer "V" (solid, pour order 318): 1148.57,3054.43 1348.15,3054.43 1358.15,3064.43 1358.15,3164.43 1348.15,3174.43 1143.15,3174.43 1133.15,3164.43 1133.15,3069.85
VA3P75 on L1_Top Layer "V" (solid, pour order 322): 1026.5,3064.5 868.09,3064.5 858.09,3074.5 858.09,3159.5 873.09,3174.5 1023.09,3174.5 1033,3164.59 1033,3071
AGND on L1_Top Layer "V" (solid, pour order 324): 663.09,3124.5 553.09,3124.5 543.09,3134.5 543.09,3234.5 553.09,3244.5 758.09,3244.5 768.09,3234.5 768.09,3179.5 758.09,3169.5 708.09,3169.5
VA3P75_LMH5401_3 on L1_Top Layer "V" (solid, pour order 326): 838.09,3114.5 838.09,3054.5 823.09,3039.5 803.09,3019.5 593.09,3019.5 548.09,3064.5 548.09,3094.5 558.09,3104.5 673.09,3104.5 698.09,3129.5 833.09,3129.5 838.09,3124.5
AGND on L1_Top Layer "V" (solid, pour order 336): 1220.9,1630.1 1334.55,1630.1 1339.71,1635.26 1339.71,1713.35 1302.97,1750.1 1142.23,1750.1 1132.23,1740.1 1132.23,1685.1 1142.23,1675.1 1175.9,1675.1
VA3P75 on L1_Top Layer "V" (solid, pour order 340): 1026.17,1640.17 867.17,1640.17 857.17,1650.17 857.17,1735.17 872.17,1750.17 1011.83,1750.17 1032,1730 1032,1646
AGND on L1_Top Layer "V" (solid, pour order 342): 662.17,1700.17 552.17,1700.17 542.17,1710.17 542.17,1810.17 552.17,1820.17 757.17,1820.17 767.17,1810.17 767.17,1755.17 757.17,1745.17 707.17,1745.17
VA3P75_LMH5401_4 on L1_Top Layer "V" (solid, pour order 344): 837.17,1690.17 837.17,1630.17 822.17,1615.17 802.17,1595.17 592.17,1595.17 547.17,1640.17 547.17,1670.17 557.17,1680.17 672.17,1680.17 697.17,1705.17 832.17,1705.17 837.17,1700.17
NetC715_2 on L1_Top Layer "V" (solid, pour order 748): 768.62,10943.88 551.62,10943.88 534.62,10960.88 534.61,11060.88 539.62,11065.88 571.73,11097.99 846.5,11097.99 862.62,11081.88 862.62,10981.88 859.62,10978.88 783.62,10978.88 778.62,10973.88 778.61,10948.88 773.62,10943.88
NetC613_1 on L1_Top Layer "h" (solid, pour order 810): 17 vertices, not listed, extent 3725.05,10938.36 4058.4,11029
12V_DC on L1_Top Layer "V" (solid, pour order 908): 19 vertices, not listed, extent 5049,10973.07 5799,11346.07
NetJ55_1 on L1_Top Layer "V" (solid, pour order 910): 18 vertices, not listed, extent 5684,10946.07 6434,11269.07
GND1 on L1_Top Layer "V" (solid, pour order 914): 24 vertices, not listed, extent 5032,11099.07 6461,11593.07
V3P3 on L1_Top Layer "L1_Top Layer-No Net" (solid, pour order 926): 2822,4769 2733,4769 2727,4763 2727,4616 2735,4608 2832,4608 2839,4615 2839,4764 2834,4769
V3P3_LMK00304 on L1_Top Layer "L1_Top Layer-No Net" (solid, pour order 928): 2815,4446 2760,4446 2752,4454 2752,4544 2760,4552 2882,4552 2896,4566 2896,4684 2910,4698 3029,4698 3043,4684 3043,4465 3024,4446 2821,4446
DGND on L1_Top Layer "L1_Top Layer-No Net" (solid, pour order 930): 3034,4422 2794,4422 2786,4414 2786,4367 2791,4362 3031,4362 3044,4375 3044,4412
V3P3_LMK61E2 on L1_Top Layer "L1_Top Layer-No Net" (solid, pour order 936): 5844,5393 5844,5556 5906,5618 6021,5618 6038,5601 6038,5300 6023,5285 5854,5285 5844,5295
DGND on L1_Top Layer "L1_Top Layer-No Net" (solid, pour order 938): 5817,5404 5817,5297 5807,5287 5702,5287 5691,5298 5691,5436 5703,5448 5810,5448 5817,5441
VDDL19 on L1_Top Layer "L1_Top Layer-No Net" (solid, pour order 940): 17 vertices, not listed, extent 6081,8952 6407,9168
DGND on L1_Top Layer "L1_Top Layer-No Net" (solid, pour order 942): 6315,9287 6303,9299 6111,9299 6099,9287 6099,9207 6106,9200 6220,9200 6228,9192 6312,9192 6315,9195
DGND on L1_Top Layer "V" (solid, pour order 1048): 3219,10255 3344,10255 3360,10239 3360,10001 3349,9990 3207,9990 3195,10002 3195,10221 3195,10245 3205,10255
V1P1V on L1_Top Layer "V" (solid, pour order 1050): 2520,10255 2645,10255 2661,10239 2661,10002 2649,9990 2403,9990 2392.99,10000 2393,10248 2400,10255
V1P9V on L1_Top Layer "V" (solid, pour order 1056): 3019,10255 3144,10255 3160,10239 3160,10002 3148,9990 2902,9990 2891.99,10000 2892,10248 2899,10255
V3P3 on L1_Top Layer "V" (solid, pour order 1058): 3519,10255 3644,10255 3660,10239 3660,10002 3648,9990 3402,9990 3391.99,10000 3392,10248 3399,10255
VA3P75 on L1_Top Layer "V" (solid, pour order 1064): 1663,10255 1788,10255 1804,10239 1804,10002 1792,9990 1546,9990 1535.99,10000 1536,10248 1543,10255
VA_N1P25 on L1_Top Layer "V" (solid, pour order 1066): 862,10255 987,10255 1003,10239 1003,10002 991,9990 745,9990 734.99,10000 735,10248 742,10255
NetC590_1 on L1_Top Layer "V" (solid, pour order 1284): 20 vertices, not listed, extent 2183.69,10603.5 2347.69,10918.5
GND on L1_Top Layer "V" (solid, pour order 1286): 23 vertices, not listed, extent 1930.69,10476.5 2256.69,10943.5
GND on L1_Top Layer "V" (solid, pour order 1298): 23 vertices, not listed, extent 1196.81,10478.36 1522.81,10945.36
NetC655_1 on L1_Top Layer "h" (solid, pour order 1300): 17 vertices, not listed, extent 1280.38,10945.09 1613.72,11043.4
GND on L1_Top Layer "V" (solid, pour order 1304): 28 vertices, not listed, extent 380,10482 712,10912.37
NetC714_1 on L1_Top Layer "V" (solid, pour order 1308): 717,10602 645,10602 637,10610 637,10741 641,10745 726,10745 734,10753 734,10856 738,10860 808,10860 808,10608 802,10602
NetC695_2 on L1_Top Layer "V" (solid, pour order 1310): 469,10772 387,10772 313,10846 313,11137 324,11148 494,11148 505,11137 505,10939 487,10921 475,10909 475,10796 475,10778
NetC660_1 on L1_Top Layer "V" (solid, pour order 1316): 20 vertices, not listed, extent 1449.81,10605.36 1613.81,10920.36
VA3P75_IN on L1_Top Layer "V" (solid, pour order 1330): 24 vertices, not listed, extent 1372,10288 1819,10814
GND on L1_Top Layer "V" (solid, pour order 1334): 17 vertices, not listed, extent 1038,10291 1505,10733.36
GND on L1_Top Layer "V" (solid, pour order 1338): 18 vertices, not listed, extent 1930.69,10291 2364,10732
V1P1V_IN on L1_Top Layer "V" (solid, pour order 1346): 23 vertices, not listed, extent 2103,10289 2664,10814
12V on L1_Top Layer "12" (solid, pour order 1366): 17 vertices, not listed, extent 4336,11132 4964,11401
GND on L1_Top Layer "12" (solid, pour order 1372): 18 vertices, not listed, extent 3196,10291 3747,10727
3P5_VIN on L1_Top Layer "V" (solid, pour order 1388): 18 vertices, not listed, extent 3581.93,10764 3763,11258
12VIN on L1_Top Layer "12" (solid, pour order 1394): 24 vertices, not listed, extent 2360,11210 4270,11452
NetC647_1 on L1_Top Layer "V" (solid, pour order 1402): 17 vertices, not listed, extent 1140,10764 1321,11253
12VIN on L1_Top Layer "12" (solid, pour order 1406): 17 vertices, not listed, extent 977,11210 4270,11559
V1P9V on L1_Top Layer "h" (solid, pour order 1412): 6393.16,9372.89 6329.16,9372.89 6324.16,9367.89 6324.16,9241.84 6331,9235 6425,9235 6440,9250 6440,9363 6430.11,9372.89
VA_N1P25_IN on L1_Top Layer "12" (solid, pour order 1414): 25 vertices, not listed, extent 553.5,10288 1010,10819.61
GND on L1_Top Layer "12" (solid, pour order 1418): 498,10291 688,10291 704,10307 704,10402 690,10416 530,10416 505,10441 505,10539 481,10563 481,10728 472,10737 264,10737 237,10710 237,10307 253,10291
NetC538_1 on L1_Top Layer "V" (solid, pour order 1428): 17 vertices, not listed, extent 1879,10764 2060,11253
NetC495_1 on L1_Top Layer "V" (solid, pour order 1430): 17 vertices, not listed, extent 2747.42,10764 2928.42,11253
V3P3 on L1_Top Layer "12" (solid, pour order 1578): 2934,6079 2878,6079 2871.43,6072.43 2871.43,5897.57 2883,5886 2982,5886 2989,5893 2989,5971 2981,5979 2956,5979 2937,5998 2937,6076
V3P3 on L1_Top Layer "12" (solid, pour order 1580): 21 vertices, not listed, extent 1277.39,4257 1700,5065.9
DGND on L1_Top Layer "12" (solid, pour order 1725): 18 vertices, not listed, extent 4147,9106 4223,9295.34
DGND on L12_Bottom Layer "12" (solid, remove dead copper, pour order 1749): 54 vertices, not listed, extent 1262,70 6899,10776
V3P3_IN on L12_Bottom Layer "V" (solid, pour order 1362): 3393,10300 3393,10414 3398,10419 3878,10419 3893,10404 3893,10301 3881,10289 3404,10289 3393,10300
GND on L12_Bottom Layer "V" (solid, pour order 1356): 18 vertices, not listed, extent 2696,10291 2908.51,10730.64
V1P9V_IN on L12_Bottom Layer "V" (solid, pour order 1352): 2901,10288 2891,10298 2891,10414 2929,10452 3152,10452 3162,10442 3162,10301 3149,10288
V1P1V_IN on L12_Bottom Layer "V" (solid, pour order 1348): 2405,10288 2392,10301 2392,10434 2410,10452 2655,10452 2664,10443 2664,10302 2650,10288
GND on L12_Bottom Layer "h" (solid, pour order 1274): 3973.4,10940.59 3813.4,10940.59 3804.4,10931.59 3804.4,10832.72 3810.49,10826.63 3960.49,10826.63 3974.9,10841.04 3974.9,10936.09 3970.4,10940.59
DGND on L12_Bottom Layer "V" (solid, pour order 1164): 3219,10255 3344,10255 3360,10239 3360,10001 3349,9990 3207,9990 3195,10002 3195,10221 3195,10245 3205,10255
DGND on L12_Bottom Layer "V" (solid, pour order 1162): 2719,10255 2844,10255 2860,10239 2860,10001 2849,9990 2707,9990 2695,10002 2695,10221 2695,10245 2705,10255
DGND on L12_Bottom Layer "V" (solid, pour order 1160): 2119,10255 2344,10255 2360,10239 2360,9998 2352,9990 2107,9990 2095,10002 2095,10221 2095,10245 2105,10255
V3P3_LMK61E2 on L12_Bottom Layer "L1_Top Layer-No Net" (solid, pour order 952): 5854,5285 5844,5295 5844,5452 5855,5463 6028,5463 6038,5453 6038,5300 6023,5285
DGND on L12_Bottom Layer "L1_Top Layer-No Net" (solid, pour order 950): 5810,5448 5703,5448 5691,5436 5691,5298 5702,5287 5807,5287 5817,5297 5817,5441
DGND on L12_Bottom Layer "L1_Top Layer-No Net" (solid, pour order 948): 5606,5715 5606,5560 5615,5551 5667,5551 5673,5557 5673,5731 5666,5738 5618,5738 5606,5726
NetC414_2 on L12_Bottom Layer "L1_Top Layer-No Net" (solid, pour order 946): 20 vertices, not listed, extent 5481,5542 5592,5770
VA1P1_ADC1 on L12_Bottom Layer "V" (solid, pour order 886): 17 vertices, not listed, extent 2054.93,8436 2366.67,8576
VA1P9_ADC1 on L12_Bottom Layer "V" (solid, pour order 884): 2256.67,7836 2171.67,7836 2166.67,7841 2161.67,7846 2161.67,7941 2161.67,8036 2166.67,8041 2188.36,8041 2198.36,8031 2203.36,8026 2236.67,8026 2276.67,8026 2281.67,8021 2281.67,7856 2261.67,7836
VA1P9_ADC2 on L12_Bottom Layer "V" (solid, pour order 882): 2260,1490 2175,1490 2170,1495 2165,1500 2165,1595 2165,1690 2170,1695 2191.69,1695 2201.69,1685 2206.69,1680 2240,1680 2280,1680 2285,1675 2285,1510 2265,1490
VA1P1_ADC2 on L12_Bottom Layer "V" (solid, pour order 880): 17 vertices, not listed, extent 2058.26,2090 2370,2230
GND on L12_Bottom Layer "V" (solid, pour order 868): 34 vertices, not listed, extent 1894.45,11107 2270.49,11452
GND on L12_Bottom Layer "V" (solid, pour order 866): 34 vertices, not listed, extent 2761.45,11104.83 3137.49,11452
GND on L12_Bottom Layer "V" (solid, pour order 516): 34 vertices, not listed, extent 3609,11095.33 3986.49,11452
V1P1V on L12_Bottom Layer "h" (solid, pour order 90): 2834,6982 2828.66,6987.34 2828.66,7175.71 2837.32,7184.37 2944.63,7184.37 2961,7168 2961,6992 2951,6982
V1P1V on L12_Bottom Layer "h" (solid, pour order 88): 2815,625 2809.68,630.32 2809.68,823.91 2818.34,832.57 2931.43,832.57 2943,821 2943,633 2935,625
GND on L12_Bottom Layer "h" (solid, pour order 144): 3136.42,10944.6 2976.42,10944.6 2967.42,10935.6 2967.42,10836.73 2973.51,10830.64 3123.51,10830.64 3137.92,10845.05 3137.92,10940.1 3133.42,10944.6
VD1P1_ADC1 on L12_Bottom Layer "V" (solid, pour order 270): 2776.87,7317.72 2776.87,6984.72 2740.87,6948.72 2626.87,6948.72 2618.87,6956.72 2612.87,6962.72 2612.87,7216.72 2612.87,7313.72 2620.87,7321.72 2773.87,7321.72 2776.87,7318.72
VD1P1_ADC2 on L12_Bottom Layer "V" (solid, pour order 272): 2755.65,953.32 2755.65,620.32 2719.65,584.32 2605.65,584.32 2597.65,592.32 2591.65,598.32 2591.65,852.32 2591.65,949.32 2599.65,957.32 2752.65,957.32 2755.65,954.32
VA_N1P25_LMH6401_1 on L12_Bottom Layer "V" (solid, pour order 290): 1065.93,8309.81 1065.93,8579.81 1055.93,8589.81 970.93,8589.81 960.93,8579.81 960.93,8314.81 970.93,8304.81 1063.19,8304.81 1065.93,8307.55
AGND on L12_Bottom Layer "V" (solid, pour order 294): 1086.32,8479.68 1086.32,8580.2 1095.93,8589.81 1150.93,8589.81 1170.93,8569.81 1170.93,8494.81 1205.93,8459.81 1205.93,8390.87 1192.13,8377.07 1138.93,8377.07 1128.93,8387.07 1128.93,8436.81 1105.93,8459.81
AGND on L12_Bottom Layer "V" (solid, pour order 296): 527.77,8483.7 527.77,8593.7 517.77,8603.7 417.77,8603.7 407.77,8593.7 407.77,8388.7 417.77,8378.7 472.77,8378.7 482.77,8388.7 482.77,8438.7
VA_N1P25_LMH5401_1 on L12_Bottom Layer "V" (solid, pour order 298): 562.42,8301.7 628.97,8301.7 635.26,8308 635.26,8578.86 622.42,8591.7 560.26,8591.7 550.26,8581.7 550.26,8466.7 550.26,8313.86
VA_N1P25_LMH5401_2 on L12_Bottom Layer "V" (solid, pour order 310): 564.22,6879.57 630.76,6879.57 637.06,6885.87 637.06,7156.74 624.22,7169.58 562.06,7169.57 552.06,7159.57 552.06,7044.57 552.06,6891.74
AGND on L12_Bottom Layer "V" (solid, pour order 312): 529.56,7061.57 529.56,7171.57 519.56,7181.57 419.56,7181.57 409.56,7171.57 409.56,6966.57 419.56,6956.57 474.56,6956.57 484.56,6966.57 484.56,7016.57
AGND on L12_Bottom Layer "V" (solid, pour order 314): 1094.2,7057.88 1094.2,7158.4 1103.8,7168.01 1158.8,7168.01 1178.8,7148.01 1178.8,7073.01 1213.8,7038.01 1213.8,6969.07 1200,6955.27 1146.8,6955.27 1136.8,6965.27 1136.8,7015.01 1113.8,7038.01
VA_N1P25_LMH6401_2 on L12_Bottom Layer "V" (solid, remove dead copper, pour order 316): 1073.8,6888.01 1073.8,7158.01 1063.8,7168.01 978.8,7168.01 968.8,7158.01 968.8,6893.01 978.8,6883.01 1071.06,6883.01 1073.8,6885.75
VA_N1P25_LMH5401_3 on L12_Bottom Layer "V" (solid, pour order 328): 565.32,1985.28 631.86,1985.28 638.16,1991.57 638.16,2262.44 625.32,2275.28 563.16,2275.28 553.16,2265.28 553.16,2150.28 553.16,1997.44
AGND on L12_Bottom Layer "V" (solid, pour order 330): 530.66,2167.28 530.66,2277.28 520.66,2287.28 420.66,2287.28 410.66,2277.28 410.66,2072.28 420.66,2062.28 475.66,2062.28 485.66,2072.28 485.66,2122.28
AGND on L12_Bottom Layer "V" (solid, pour order 332): 1109.9,2156.78 1109.9,2257.3 1119.5,2266.91 1174.5,2266.91 1194.5,2246.91 1194.5,2171.91 1229.5,2136.91 1229.5,2067.97 1215.7,2054.18 1162.5,2054.18 1152.5,2064.18 1152.5,2113.91 1129.5,2136.91
VA_N1P25_LMH6401_3 on L12_Bottom Layer "V" (solid, pour order 334): 1089.5,1986.91 1089.5,2256.91 1079.5,2266.91 994.5,2266.91 984.5,2256.91 984.5,1991.91 994.5,1981.91 1086.76,1981.91 1089.5,1984.65
VA_N1P25_LMH5401_4 on L12_Bottom Layer "V" (solid, pour order 346): 564.39,560.94 630.94,560.94 637.23,567.24 637.23,838.1 624.39,850.94 562.23,850.94 552.23,840.94 552.23,725.94 552.23,573.1
AGND on L12_Bottom Layer "V" (solid, pour order 348): 529.74,742.94 529.74,852.94 519.74,862.94 419.74,862.94 409.74,852.94 409.74,647.94 419.74,637.94 474.74,637.94 484.74,647.94 484.74,697.94
AGND on L12_Bottom Layer "V" (solid, pour order 350): 1100.56,742.71 1100.56,843.23 1110.17,852.83 1165.17,852.83 1185.17,832.83 1185.17,757.83 1220.17,722.83 1220.17,653.9 1206.37,640.1 1153.17,640.1 1143.17,650.1 1143.17,699.83 1120.17,722.83
VA_N1P25_LMH6401_4 on L12_Bottom Layer "V" (solid, pour order 352): 1080.17,572.83 1080.17,842.83 1070.17,852.83 985.17,852.83 975.17,842.83 975.17,577.83 985.17,567.83 1077.43,567.83 1080.17,570.57
GND on L12_Bottom Layer "V" (solid, pour order 876): 34 vertices, not listed, extent 1183.13,11091.37 1570.7,11445
NetJ55_1 on L12_Bottom Layer "V" (solid, pour order 912): 18 vertices, not listed, extent 5684,10946.07 6434,11269.07
V3P3_LMK00304 on L12_Bottom Layer "L1_Top Layer-No Net" (solid, pour order 932): 3024,4446 2862.63,4446 2850.63,4458 2850.63,4543.63 2859,4552 2882,4552 2896,4566 2896,4684 2910,4698 3029,4698 3043,4684 3043,4465 3024,4446
DGND on L12_Bottom Layer "L1_Top Layer-No Net" (solid, pour order 934): 3034,4422 2796,4422 2786,4412 2786,4367 2791,4362 3031,4362 3044,4375 3044,4412 3034,4422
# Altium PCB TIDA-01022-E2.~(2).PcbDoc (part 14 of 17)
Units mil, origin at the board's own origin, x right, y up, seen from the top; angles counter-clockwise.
Board outline 6929.13 x 11614.17 mil, 12 copper layers (L1_Top Layer, L2_GND, L3_GND, L4_Signal Layer 1, L5_GND, L6_PWR, L7_GND/PWR, L8_PWR, L9_GND/PWR, L10_Signal Layer 2, L11_GND, L12_Bottom Layer), stack 64.6 mil thick; 1711 components, 1001 nets, 5985 pads, 3200 vias.

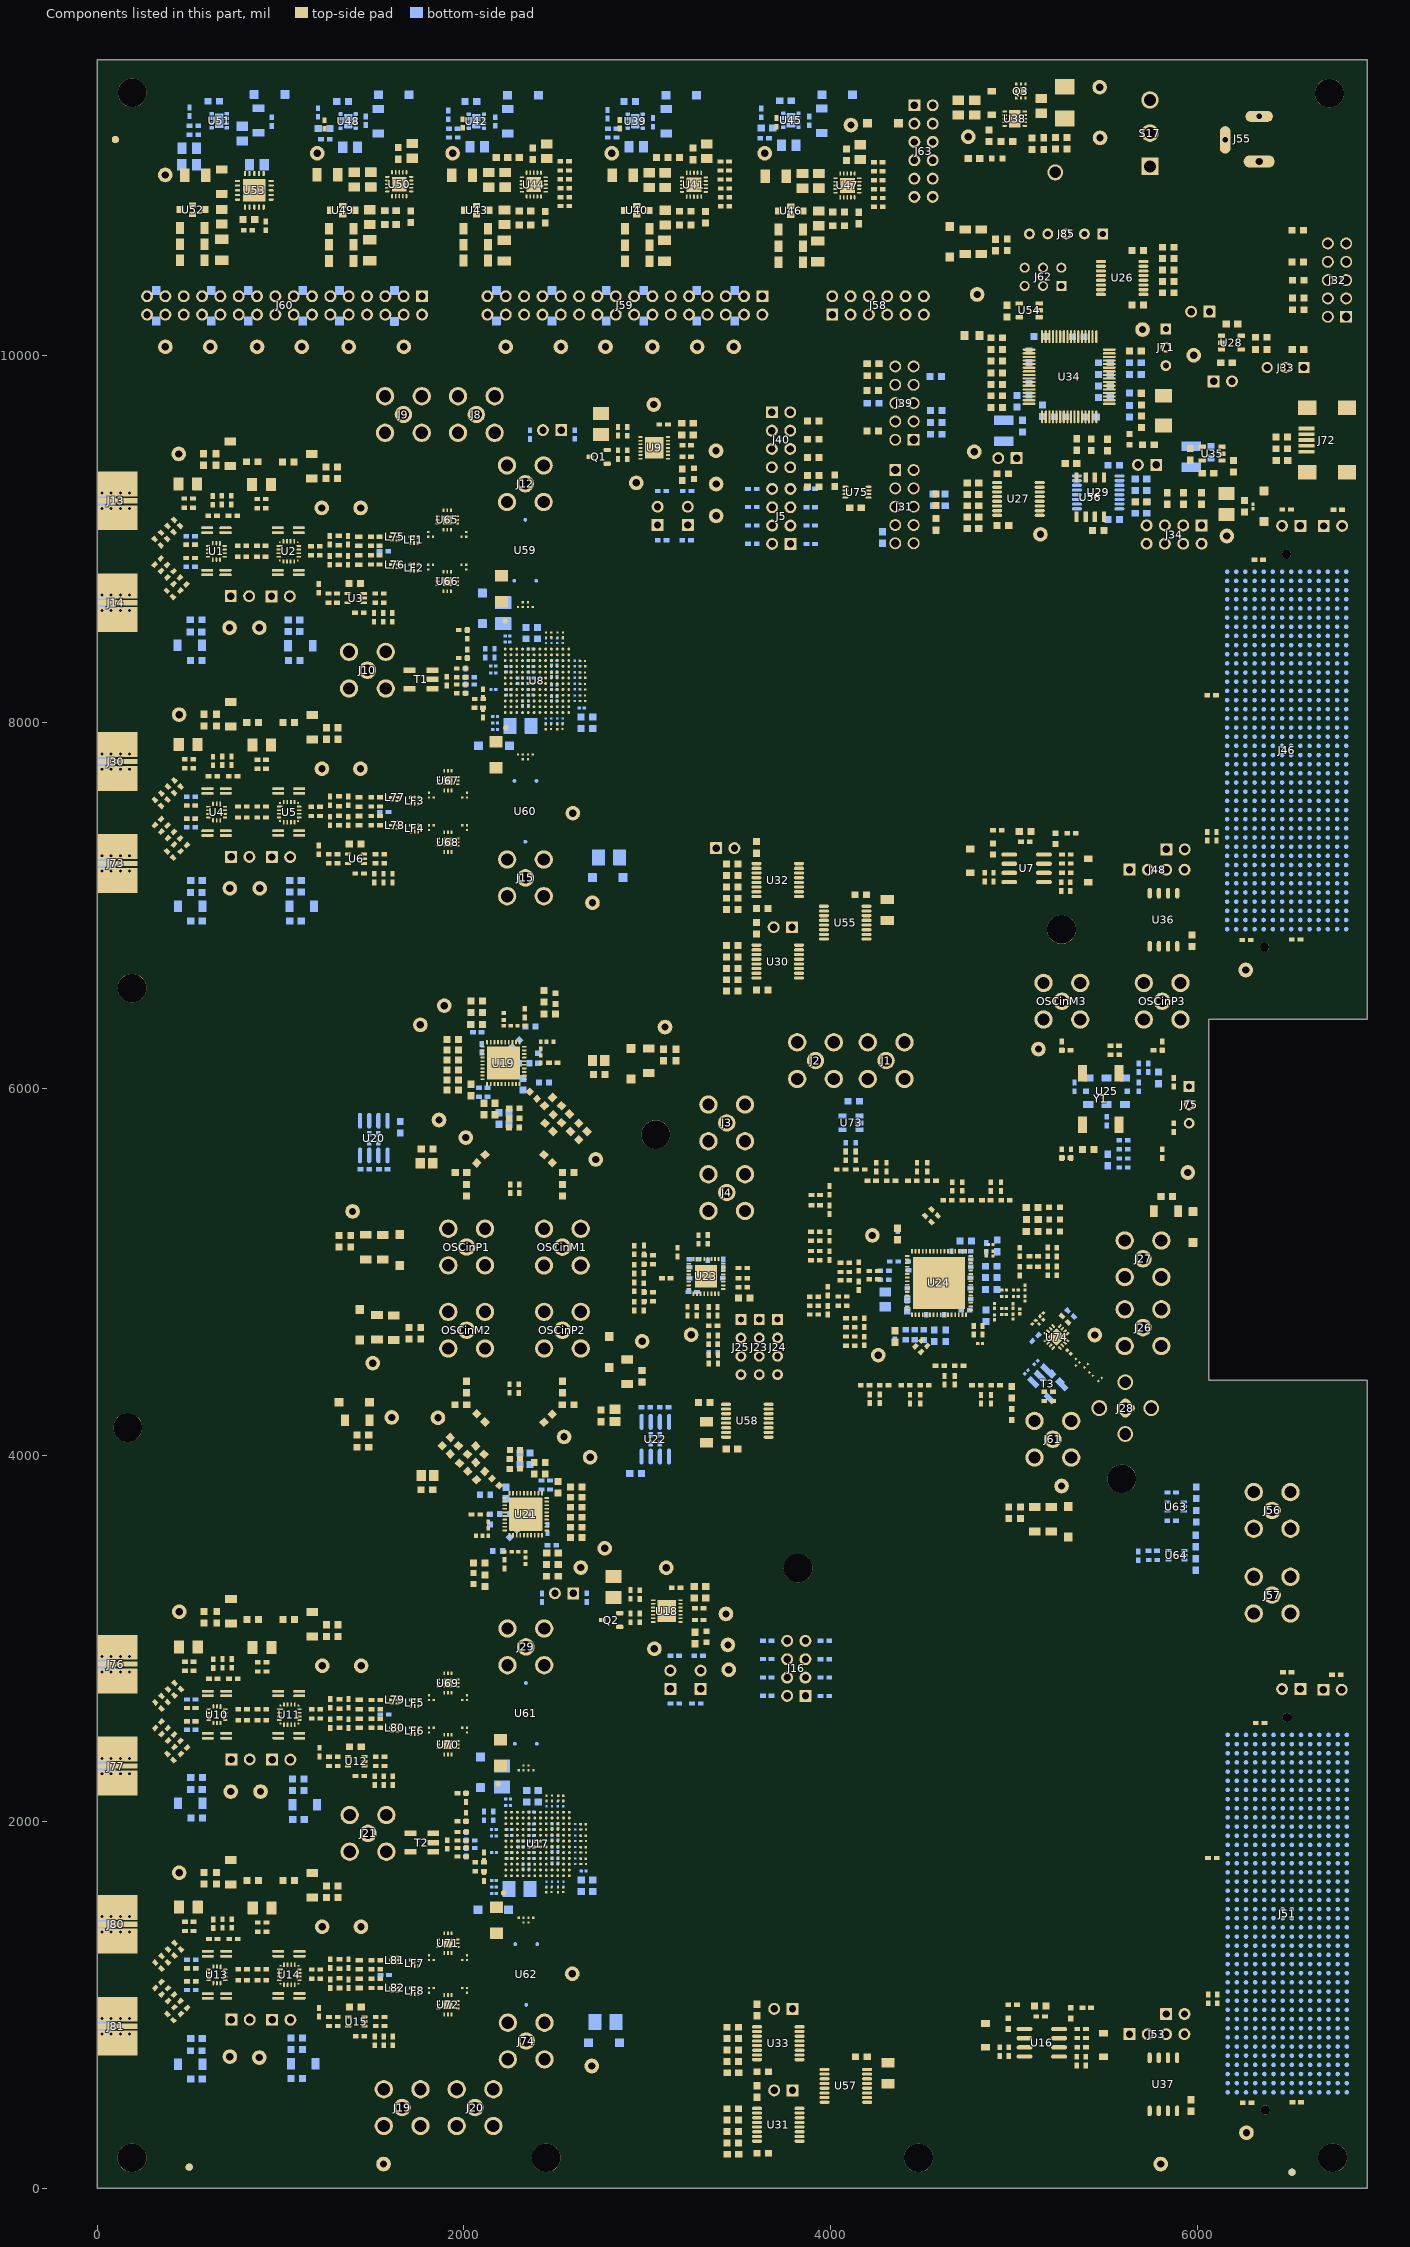
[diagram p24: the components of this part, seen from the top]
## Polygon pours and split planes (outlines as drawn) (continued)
GND on L12_Bottom Layer "V" (solid, pour order 996): 2837,10291 2712,10291 2696,10307 2696,10408 2707,10419 2853,10419 2861,10411 2861,10325 2861,10301 2851,10291
V1P1V on L12_Bottom Layer "V" (solid, pour order 1052): 2520,10255 2645,10255 2661,10239 2661,10002 2649,9990 2403,9990 2392.99,10000 2393,10248 2400,10255
V1P9V on L12_Bottom Layer "V" (solid, pour order 1054): 3019,10255 3144,10255 3160,10239 3160,10002 3148,9990 2902,9990 2891.99,10000 2892,10248 2899,10255
V3P3 on L12_Bottom Layer "V" (solid, pour order 1060): 3519,10255 3644,10255 3660,10239 3660,10002 3648,9990 3402,9990 3391.99,10000 3392,10248 3399,10255
VA3P75 on L12_Bottom Layer "V" (solid, remove dead copper, pour order 1062): 1663,10255 1788,10255 1804,10239 1804,10002 1792,9990 1546,9990 1535.99,10000 1536,10248 1543,10255
VA_N1P25 on L12_Bottom Layer "V" (solid, pour order 1068): 862,10255 987,10255 1003,10239 1003,10002 991,9990 745,9990 734.99,10000 735,10248 742,10255
NetC510_1 on L12_Bottom Layer "V" (solid, pour order 1072): 703,11282.92 965,11282.92 972,11289.92 972,11330.92 921,11381.92 921,11459.92 909,11471.92 831,11471.92 820,11460.92 820,11361.92 812,11353.92 706,11353.92 693,11340.92 693,11288.92 699,11282.92
NetC695_2 on L12_Bottom Layer "V" (solid, pour order 1074): 28 vertices, not listed, extent 315,10932 688,11459.92
GND on L12_Bottom Layer "V" (solid, pour order 1076): 30 vertices, not listed, extent 511,10998.92 975,11271.92
NetC509_1 on L12_Bottom Layer "V" (solid, pour order 1080): 1413.05,11283.14 1542.13,11283.14 1571.13,11312.14 1571.13,11452.06 1559.05,11464.14 1505.05,11464.14 1491.05,11450.14 1491.05,11378.14 1478.05,11365.14 1413.05,11365.14 1399.05,11351.14 1399.05,11287.14 1403.05,11283.14
12VIN on L12_Bottom Layer "V" (solid, pour order 1084): 2360,11447 2360,11346 2376,11330 2519,11330 2527,11338 2527,11441 2516,11452 2365,11452
NetC364_1 on L12_Bottom Layer "V" (solid, pour order 1086): 2112.84,11282.92 2241.92,11282.92 2270.92,11311.92 2270.92,11442.08 2261,11452 2199.91,11452 2190.84,11442.92 2190.84,11377.92 2177.84,11364.92 2112.84,11364.92 2098.84,11350.92 2098.84,11286.92 2102.84,11282.92
NetC355_1 on L12_Bottom Layer "V" (solid, pour order 1090): 2979.84,11282.97 3108.92,11282.97 3137.92,11311.97 3137.92,11444.08 3130,11452 3069,11452 3057.84,11440.84 3057.84,11377.97 3044.84,11364.97 2979.84,11364.97 2965.84,11350.97 2965.84,11286.97 2969.84,11282.97
NetC371_1 on L12_Bottom Layer "V" (solid, pour order 1094): 3828.84,11287.1 3957.93,11287.1 3986.93,11316.1 3986.93,11446.07 3981,11452 3911.74,11452 3906.84,11447.1 3906.84,11382.1 3893.84,11369.1 3828.84,11369.1 3814.84,11355.1 3814.84,11291.1 3818.84,11287.1
V1P1V on L12_Bottom Layer "V" (solid, pour order 1204): 2114,8742 2036,8742 1981,8687 1981,8612 1988,8605 2071,8605 2079,8613 2079,8665 2084,8670 2128,8670 2137,8679 2137,8733 2129,8741 2128,8742 2117,8742
V1P9V on L12_Bottom Layer "V" (solid, pour order 1206): 2032.74,7833.26 2108.79,7833.26 2114.79,7839.26 2114.79,7972.26 2110.79,7976.26 2029.26,7976.26 2020,7967 2020,7846
V1P9V on L12_Bottom Layer "V" (solid, pour order 1208): 2018.37,1482.63 2104.73,1482.63 2110.73,1488.63 2110.73,1621.63 2106.73,1625.63 2018.63,1625.63 2012,1619 2012,1489
V1P1V on L12_Bottom Layer "V" (solid, pour order 1212): 2050,2413 2050,2467 2058,2475 2114,2475 2121,2468 2121,2307 2117,2303 2056,2303 2050,2309
GND on L12_Bottom Layer "h" (solid, pour order 1296): 2262.59,10945.46 2102.59,10945.46 2093.59,10936.46 2093.59,10837.59 2099.68,10831.5 2249.69,10831.5 2264.09,10845.91 2264.09,10940.96 2259.59,10945.46
GND on L12_Bottom Layer "h" (solid, pour order 1314): 1528.72,10947.32 1368.72,10947.32 1359.72,10938.32 1359.72,10839.45 1365.81,10833.36 1515.81,10833.36 1530.22,10847.77 1530.22,10942.82 1525.72,10947.32
GND on L12_Bottom Layer "V" (solid, pour order 1322): 237,10408 237,10710 265,10738 266,10737 393,10737 472,10737 480,10729 481,10728 481,10684 481,10563 505,10539 505,10298 498,10291 253,10291 237,10307
VA3P75_IN on L12_Bottom Layer "V" (solid, pour order 1332): 1548,10288 1535,10301 1535,10434 1553,10452 1807,10452 1819,10440 1819,10298 1809,10288
GND on L12_Bottom Layer "V" (solid, pour order 1340): 18 vertices, not listed, extent 1930.69,10291 2364,10732
VA_N1P25_IN on L12_Bottom Layer "V" (solid, pour order 1342): 750,10288 737,10301 737,10434 755,10452 1001,10452 1010,10443 1010,10302 996,10288
GND on L12_Bottom Layer "V" (solid, pour order 998): 2237,10291 2112,10291 2096,10307 2096,10408 2107,10419 2355,10419 2364,10410 2364,10298 2357,10291
GND on L12_Bottom Layer "V" (solid, pour order 1018): 679,10291 554,10291 538,10307 538,10408 549,10419 695,10419 703,10411 703,10325 703,10301 693,10291
NetC538_1 on L12_Bottom Layer "12" (solid, pour order 1374): 24 vertices, not listed, extent 1878,11044 2124.75,11252.16
12VIN on L12_Bottom Layer "V" (solid, pour order 1376): 3225.26,11446.26 3225.26,11336.74 3232,11330 3383,11330 3393,11340 3393,11445 3386,11452 3231,11452
12VIN on L12_Bottom Layer "V" (solid, pour order 1380): 977,11448 977,11360 981.08,11355.92 1135.92,11355.92 1142,11362 1142,11448 1137,11453 982,11453
12VIN on L12_Bottom Layer "V" (solid, pour order 1382): 1654.05,11447.21 1654.05,11359.21 1657.34,11355.92 1776.92,11355.92 1820,11399 1820,11442 1809.79,11452.21 1659.05,11452.22
NetC495_1 on L12_Bottom Layer "12" (solid, pour order 1384): 24 vertices, not listed, extent 2745,11044.05 2991.75,11252.2
12VIN on L12_Bottom Layer "12" (solid, pour order 1392): 4060,11347 4060,11446 4066,11452 4149,11452 4156.18,11444.82 4156.18,11280.18 4143,11267 4071,11267 4060,11278
NetC647_1 on L12_Bottom Layer "12" (solid, pour order 1404): 24 vertices, not listed, extent 1147,11044.21 1424.96,11252.37
GND on L12_Bottom Layer "12" (solid, pour order 1408): 18 vertices, not listed, extent 3196,10291 3747,10727
GND on L12_Bottom Layer "V" (solid, pour order 1410): 17 vertices, not listed, extent 1038,10291 1505,10733.36
AGND on L12_Bottom Layer "12" (solid, pour order 1422): 248,10255 688,10255 704,10239 704,10001 693,9990 250,9990 238,10002 238,10245 248,10255
AGND on L12_Bottom Layer "12" (solid, pour order 1426): 1048,10255 1487,10255 1503,10239 1503,9998 1495,9990 1050,9990 1038,10002 1038,10245 1048,10255
3P5_VIN on L12_Bottom Layer "12" (solid, pour order 1432): 22 vertices, not listed, extent 3594.01,11048.18 3840.75,11256.33
VA_N1P25 on L12_Bottom Layer "12" (solid, pour order 1522): 18 vertices, not listed, extent 402,8190 1195,8357
VA_N1P25 on L12_Bottom Layer "12" (solid, pour order 1524): 18 vertices, not listed, extent 403.8,6767.87 1196.8,6934.87
VA_N1P25 on L12_Bottom Layer "12" (solid, pour order 1526): 18 vertices, not listed, extent 404.9,1873.57 1197.9,2040.57
VA_N1P25 on L12_Bottom Layer "12" (solid, pour order 1528): 18 vertices, not listed, extent 403.97,478 1196.97,616.24
AGND on L12_Bottom Layer "12" (solid, remove dead copper, pour order 1741): 26 vertices, not listed, extent 2152,2042.38 2554.99,3108.38
AGND on L12_Bottom Layer "12" (solid, remove dead copper, pour order 1743): 25 vertices, not listed, extent 2121.91,650.23 2522,1716.23
AGND on L12_Bottom Layer "12" (solid, remove dead copper, pour order 1747): 26 vertices, not listed, extent 2140,6996.2 2517,8062.2
AGND on L12_Bottom Layer "12" (solid, remove dead copper, pour order 1745): 26 vertices, not listed, extent 2160,8388 2552,9454
AGND on L12_Bottom Layer "12" (solid, remove dead copper, pour order 1751): 45 vertices, not listed, extent 17.27,478 1804,10255
V3P3 on L6_PWR "12" (solid, pour order 1735): 4709,10776 4612,10776 4600,10764 4600,10216 4534,10150 3405,10150 3392,10137 3392,10000 3402,9990 4594,9990 4664,10060 4720,10116 4720,10765
VA1P9_ADC1 on L6_PWR "12" (solid, pour order 1709): 2246,7838 1864.67,7838 1844.67,7858 1844.67,8508.97 1907.69,8572 2300,8572 2330.76,8541.24 2330.76,8412.57 2330.76,7922.76
12VIN on L6_PWR "12" (solid, pour order 1707): 17 vertices, not listed, extent 977,11210 4270,11559
12VIN on L6_PWR "12" (solid, pour order 1705): 24 vertices, not listed, extent 2360,11210 4270,11452
VA_N1P25_LMH6401_4 on L6_PWR "V" (solid, pour order 1703): 18 vertices, not listed, extent 776.39,530.3 1361.39,1567.3
VA_N1P25_LMH6401_3 on L6_PWR "V" (solid, pour order 1701): 18 vertices, not listed, extent 776.32,1949.64 1361.32,2986.64
VA_N1P25_LMH6401_2 on L6_PWR "V" (solid, pour order 1699): 18 vertices, not listed, extent 774.8,6873.87 1359.8,7910.87
VA_N1P25_LMH5401_4 on L6_PWR "V" (solid, pour order 1654): 24 vertices, not listed, extent 374.59,535.3 869.07,1627.3
VA_N1P25_LMH5401_3 on L6_PWR "V" (solid, pour order 1650): 24 vertices, not listed, extent 374.51,1954.64 868.99,3046.64
VA_N1P25_LMH5401_2 on L6_PWR "V" (solid, pour order 1646): 24 vertices, not listed, extent 372.99,6878.87 867.47,7970.87
VA_N1P25_LMH5401_1 on L6_PWR "V" (solid, pour order 1632): 24 vertices, not listed, extent 371.19,8301 865.67,9393
VA_N1P25_LMH6401_1 on L6_PWR "V" (solid, pour order 1630): 18 vertices, not listed, extent 773,8296 1358,9333
VREGIN on L6_PWR "V" (solid, pour order 1166): 18 vertices, not listed, extent 5043.3,9556.44 5863.31,10075
V3P3_LMK00304 on L6_PWR "V" (solid, pour order 1168): 3741,4362 2912,4362 2882,4392 2860,4414 2860,4960 2860,5206 2898,5244 3372,5244 3678,5244 3753,5169 3760.74,5161.26 3760.74,4758 3760.74,4381.74
V3P3_LMK61E2 on L6_PWR "V" (solid, pour order 1172): 5702,5287 5526,5287 5400,5413 5074,5739 5074,6239 5074,6625 5126,6677 5919,6677 6003,6593 6003,5318 5972,5287 5703,5287
V3P3_LMK48XX on L6_PWR "V" (solid, pour order 1174): 21 vertices, not listed, extent 3254,3743 5877,6344
VD1P1_ADC1 on L6_PWR "V" (solid, pour order 1196): 2626.87,6948.72 2575.28,6948.72 2542,6982 2542,7777 2402,7917 2402,8405 2413.24,8416.24 2755.76,8416.24 2776.87,8395.13 2776.87,6984.72 2740.87,6948.72
VD1P1_ADC2 on L6_PWR "V" (solid, pour order 1202): 2630.2,602.73 2578.61,602.73 2545.33,636 2545.33,1422.67 2405.33,1562.67 2405.33,2059 2416.57,2070.24 2759.09,2070.24 2780.2,2049.14 2780.2,638.73 2744.2,602.73
VA_N1P25 on L6_PWR "12" (solid, pour order 1530): 52 vertices, not listed, extent 53,496 1003,10255
V3P3_VDD on L6_PWR "12" (solid, pour order 1544): 30 vertices, not listed, extent 2684,106 6082.44,4333
V3P3_VDD on L6_PWR "12" (solid, pour order 1546): 37 vertices, not listed, extent 2627,6376.24 6867,10834
V3P3_LMX1 on L6_PWR "12" (solid, pour order 1558): 1277.39,5185.61 1277.39,5962.43 1512.96,6198 2291.29,6198 2350.47,6257.18 2418.92,6257.18 2816.82,6257.18 2839.61,6234.39 2839.61,5481.61 2727,5369 1899,5369 1705.3,5175.3 1287.7,5175.3
V3P3 on L6_PWR "12" (solid, pour order 1560): 17 vertices, not listed, extent 1277.39,4478 2837,5340
V3P3_LMX1RF on L6_PWR "12" (solid, pour order 1576): 2339,6260 2299,6220 1717,6220 1698,6239 1698,6391 1812,6505 1852,6545 2330,6545 3092,6545 3178,6545 3198.57,6524.43 3198.57,6400.77 3198.57,6296.57 3162,6260
V3P3_LMX2 on L6_PWR "12" (solid, pour order 1582): 21 vertices, not listed, extent 1277.39,3310 3042,4642.68
V3P3_LMX2RF on L6_PWR "12" (solid, pour order 1584): 1277.39,4363.39 1277.39,3765.61 1764,3279 2425,3279 2437,3291 2437,3526 2413,3550 2329,3550 2219,3660 1792,3660 1667,3785 1667,4337 1633,4371 1285,4371
VA1P9_ADC1 on L6_PWR "12" (solid, pour order 1590): 2656,9321 2627,9292 2627,8938 2675,8890 2717,8848 3421,8848 3964,8848 3985,8869 3985,9303.61 3967.61,9321
V1P1V on L6_PWR "12" (solid, pour order 1594): 2837,6949 3055.64,6948.64 3082,6975 3082,8532.19 2863.19,8751 2009,8751 1968,8710 1968,8606 1981,8593 2635,8593 2800,8428 2800,6966 2817,6949
V1P1V on L6_PWR "12" (solid, pour order 1596): 2840.33,603 3007.05,602.73 3084,679.67 3084,2349 2898,2535 2059,2535 2041,2517 2041,2275 2069,2247 2638.33,2247 2803.33,2082 2803.33,620 2820.33,603
VA1P9_ADC2 on L6_PWR "12" (solid, pour order 1598): 2249.33,1492 1868,1492 1848,1512 1848,2162.98 1911.03,2226 2303.33,2226 2334.09,2195.24 2334.09,2066.57 2334.09,1576.77
VA1P9_ADC2 on L6_PWR "12" (solid, pour order 1600): 2737.64,3036.11 2708.64,3007.11 2708.64,2693.36 2838.89,2563.11 3502.64,2563.11 4045.64,2563.11 4066.64,2584.11 4066.64,3018.72 4049.24,3036.11
VA3P75_LMH5401_4 on L8_PWR "V" (solid, pour order 1668): 374.59,1783.5 394.39,1803.3 836.39,1803.3 869.07,1770.63 869.07,868.96 837.41,837.3 415.39,837.3 374.59,878.11
VA3P75_LMH6401_4 on L8_PWR "V" (solid, pour order 1666): 1329.39,1567.3 918.39,1567.3 899.07,1547.98 899.07,878.96 939.07,838.96 1349.05,838.96 1361.39,851.3 1361.39,1535.3
VA3P75_LMH5401_3 on L8_PWR "V" (solid, pour order 1664): 374.51,3202.83 394.32,3222.64 836.32,3222.64 868.99,3189.96 868.99,2288.29 837.34,2256.64 415.32,2256.64 374.51,2297.44
VA3P75_LMH6401_3 on L8_PWR "V" (solid, pour order 1662): 1329.31,2986.64 918.32,2986.64 898.99,2967.31 898.99,2298.29 938.99,2258.29 1348.97,2258.29 1361.32,2270.64 1361.32,2954.64
VA3P75_LMH5401_2 on L8_PWR "V" (solid, pour order 1660): 372.99,8127.07 392.8,8146.87 834.8,8146.87 867.47,8114.2 867.47,7212.53 835.82,7180.87 413.8,7180.87 372.99,7221.68
VA3P75_LMH6401_2 on L8_PWR "V" (solid, pour order 1658): 1327.8,7910.87 916.8,7910.87 897.47,7891.55 897.47,7222.53 937.47,7182.53 1347.45,7182.53 1359.8,7194.87 1359.8,7878.87
VA3P75_LMH6401_1 on L8_PWR "V" (solid, pour order 1640): 1326,9333 915,9333 895.67,9313.67 895.67,8644.66 935.68,8604.66 1345.66,8604.66 1358,8617 1358,9301
VA3P75_LMH5401_1 on L8_PWR "V" (solid, pour order 1638): 371.19,9549.2 391,9569 833,9569 865.67,9536.33 865.67,8634.66 834.02,8603 412,8603 371.19,8643.81
VA1P9_ADC2 on L8_PWR "12" (solid, pour order 1626): 2628.18,2698.18 2628.18,1722.18 2594,1688 2172,1688 2167,1683 2167,1511 2180.09,1497.91 2819.18,1497.91 2864,1542.73 2864,2702 2848,2718 2648,2718
VA1P9_ADC1 on L8_PWR "12" (solid, pour order 1624): 2640,9187 2640,8061 2617,8038 2177,8038 2175,8036 2175,7864 2183,7856 2831,7856 2884,7909 2884,9185 2846,9223 2658,9223 2640,9205
VA1P1_ADC1 on L8_PWR "V" (solid, pour order 1220): 2142.01,8581 2127,8566 2127,8089 2149,8067 2574,8067 2612,8105 2612,8555 2612,8566 2597,8581
VA1P1_ADC2 on L8_PWR "V" (solid, pour order 1222): 2145.34,2235 2130.33,2220 2130.33,1743 2155.33,1718 2599,1718 2615.33,1734.33 2615.33,2209 2615.33,2220 2600.33,2235
VA3P75 on L8_PWR "12" (solid, pour order 1532): 51 vertices, not listed, extent 683,1613 1804,10255
V3P3 on L8_PWR "12" (solid, pour order 1562): 22 vertices, not listed, extent 2374,3460 5598,10255
VDDL19 on L8_PWR "12" (solid, pour order 1566): 4648,10658 4648,7526 4704,7470 4723,7451 5722,7451 6051,7451 6082,7482 6082,8935 6106,8959 6821,8959 6867,9005 6867,10804 6837,10834 4824,10834 4653,10663
V3P3_VDD on L8_PWR "12" (solid, pour order 1568): 19 vertices, not listed, extent 2886,106 6083,7428
GND on L2_GND "12" (solid, pour order 1396): 27 vertices, not listed, extent 91,10273 6865,11579.37
GND on L2_GND "12" (solid, pour order 1398): 21 vertices, not listed, extent 1860,10291 4609,11452
AGND on L2_GND "12" (solid, remove dead copper, pour order 1672): 95 vertices, not listed, extent 17.27,478 2555.33,10255
DGND on L2_GND "12" (solid, remove dead copper, pour order 1674): 112 vertices, not listed, extent 1262,70 6899,10776
AGND on L11_GND "12" (solid, remove dead copper, pour order 1695): 45 vertices, not listed, extent 17.27,478 1804,10255
AGND on L11_GND "12" (solid, remove dead copper, pour order 1470): 26 vertices, not listed, extent 2160,8388 2552,9454
AGND on L11_GND "12" (solid, remove dead copper, pour order 1472): 26 vertices, not listed, extent 2140,6996.2 2517,8062.2
AGND on L11_GND "12" (solid, remove dead copper, pour order 1474): 25 vertices, not listed, extent 2121.91,650.23 2522,1716.23
AGND on L11_GND "12" (solid, remove dead copper, pour order 1476): 26 vertices, not listed, extent 2152,2042.38 2554.99,3108.38
GND on L11_GND "12" (solid, pour order 1516): 21 vertices, not listed, extent 1860,10291 4609,11452
GND on L11_GND "12" (solid, pour order 1518): 27 vertices, not listed, extent 91,10273 6865,11579.37
DGND on L11_GND "12" (solid, remove dead copper, pour order 1478): 54 vertices, not listed, extent 1262,70 6899,10776
AGND on L5_GND "12" (solid, remove dead copper, pour order 1691): 83 vertices, not listed, extent 17.27,478 2521.36,10255
GND on L5_GND "12" (solid, pour order 1504): 21 vertices, not listed, extent 1860,10291 4609,11452
GND on L5_GND "12" (solid, pour order 1506): 27 vertices, not listed, extent 91,10273 6865,11579.37
DGND on L5_GND "12" (solid, remove dead copper, pour order 1688): 101 vertices, not listed, extent 873,70 6899,10776
GND on L3_GND "12" (solid, pour order 1500): 21 vertices, not listed, extent 1860,10291 4609,11452
GND on L3_GND "12" (solid, pour order 1502): 27 vertices, not listed, extent 91,10273 6865,11579.37
AGND on L3_GND "12" (solid, remove dead copper, pour order 1680): 95 vertices, not listed, extent 17.27,478 2555.33,10255
DGND on L3_GND "12" (solid, remove dead copper, pour order 1684): 112 vertices, not listed, extent 1262,70 6899,10776
V1P9V on L7_GND/PWR "12" (solid, remove dead copper, pour order 1713): 111 vertices, not listed, extent 1262,103 6867,10776
AGND on L7_GND/PWR "12" (solid, remove dead copper, pour order 1711): 95 vertices, not listed, extent 17.27,478 2555.33,10255
GND on L7_GND/PWR "12" (solid, pour order 1508): 21 vertices, not listed, extent 1860,10291 4609,11452
GND on L7_GND/PWR "12" (solid, pour order 1510): 27 vertices, not listed, extent 91,10273 6865,11579.37
V1P1V on L9_GND/PWR "12" (solid, remove dead copper, pour order 1717): 111 vertices, not listed, extent 1262,103 6867,10776
AGND on L9_GND/PWR "12" (solid, remove dead copper, pour order 1715): 95 vertices, not listed, extent 17.27,478 2555.33,10255
GND on L9_GND/PWR "12" (solid, pour order 1512): 21 vertices, not listed, extent 1860,10291 4609,11452
GND on L9_GND/PWR "12" (solid, pour order 1514): 27 vertices, not listed, extent 91,10273 6865,11579.37
V1P9V on L4_Signal Layer 1 "L1_Top Layer-No Net" (solid, pour order 1574): 20 vertices, not listed, extent 2787,8961 6883,10834

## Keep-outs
Keep-Out Layer:
  text ".Layer_Name" at -2293.76,-2323.68 h60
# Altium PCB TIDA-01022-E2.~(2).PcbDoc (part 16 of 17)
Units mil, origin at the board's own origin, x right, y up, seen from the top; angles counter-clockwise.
Board outline 6929.13 x 11614.17 mil, 12 copper layers (L1_Top Layer, L2_GND, L3_GND, L4_Signal Layer 1, L5_GND, L6_PWR, L7_GND/PWR, L8_PWR, L9_GND/PWR, L10_Signal Layer 2, L11_GND, L12_Bottom Layer), stack 64.6 mil thick; 1711 components, 1001 nets, 5985 pads, 3200 vias.

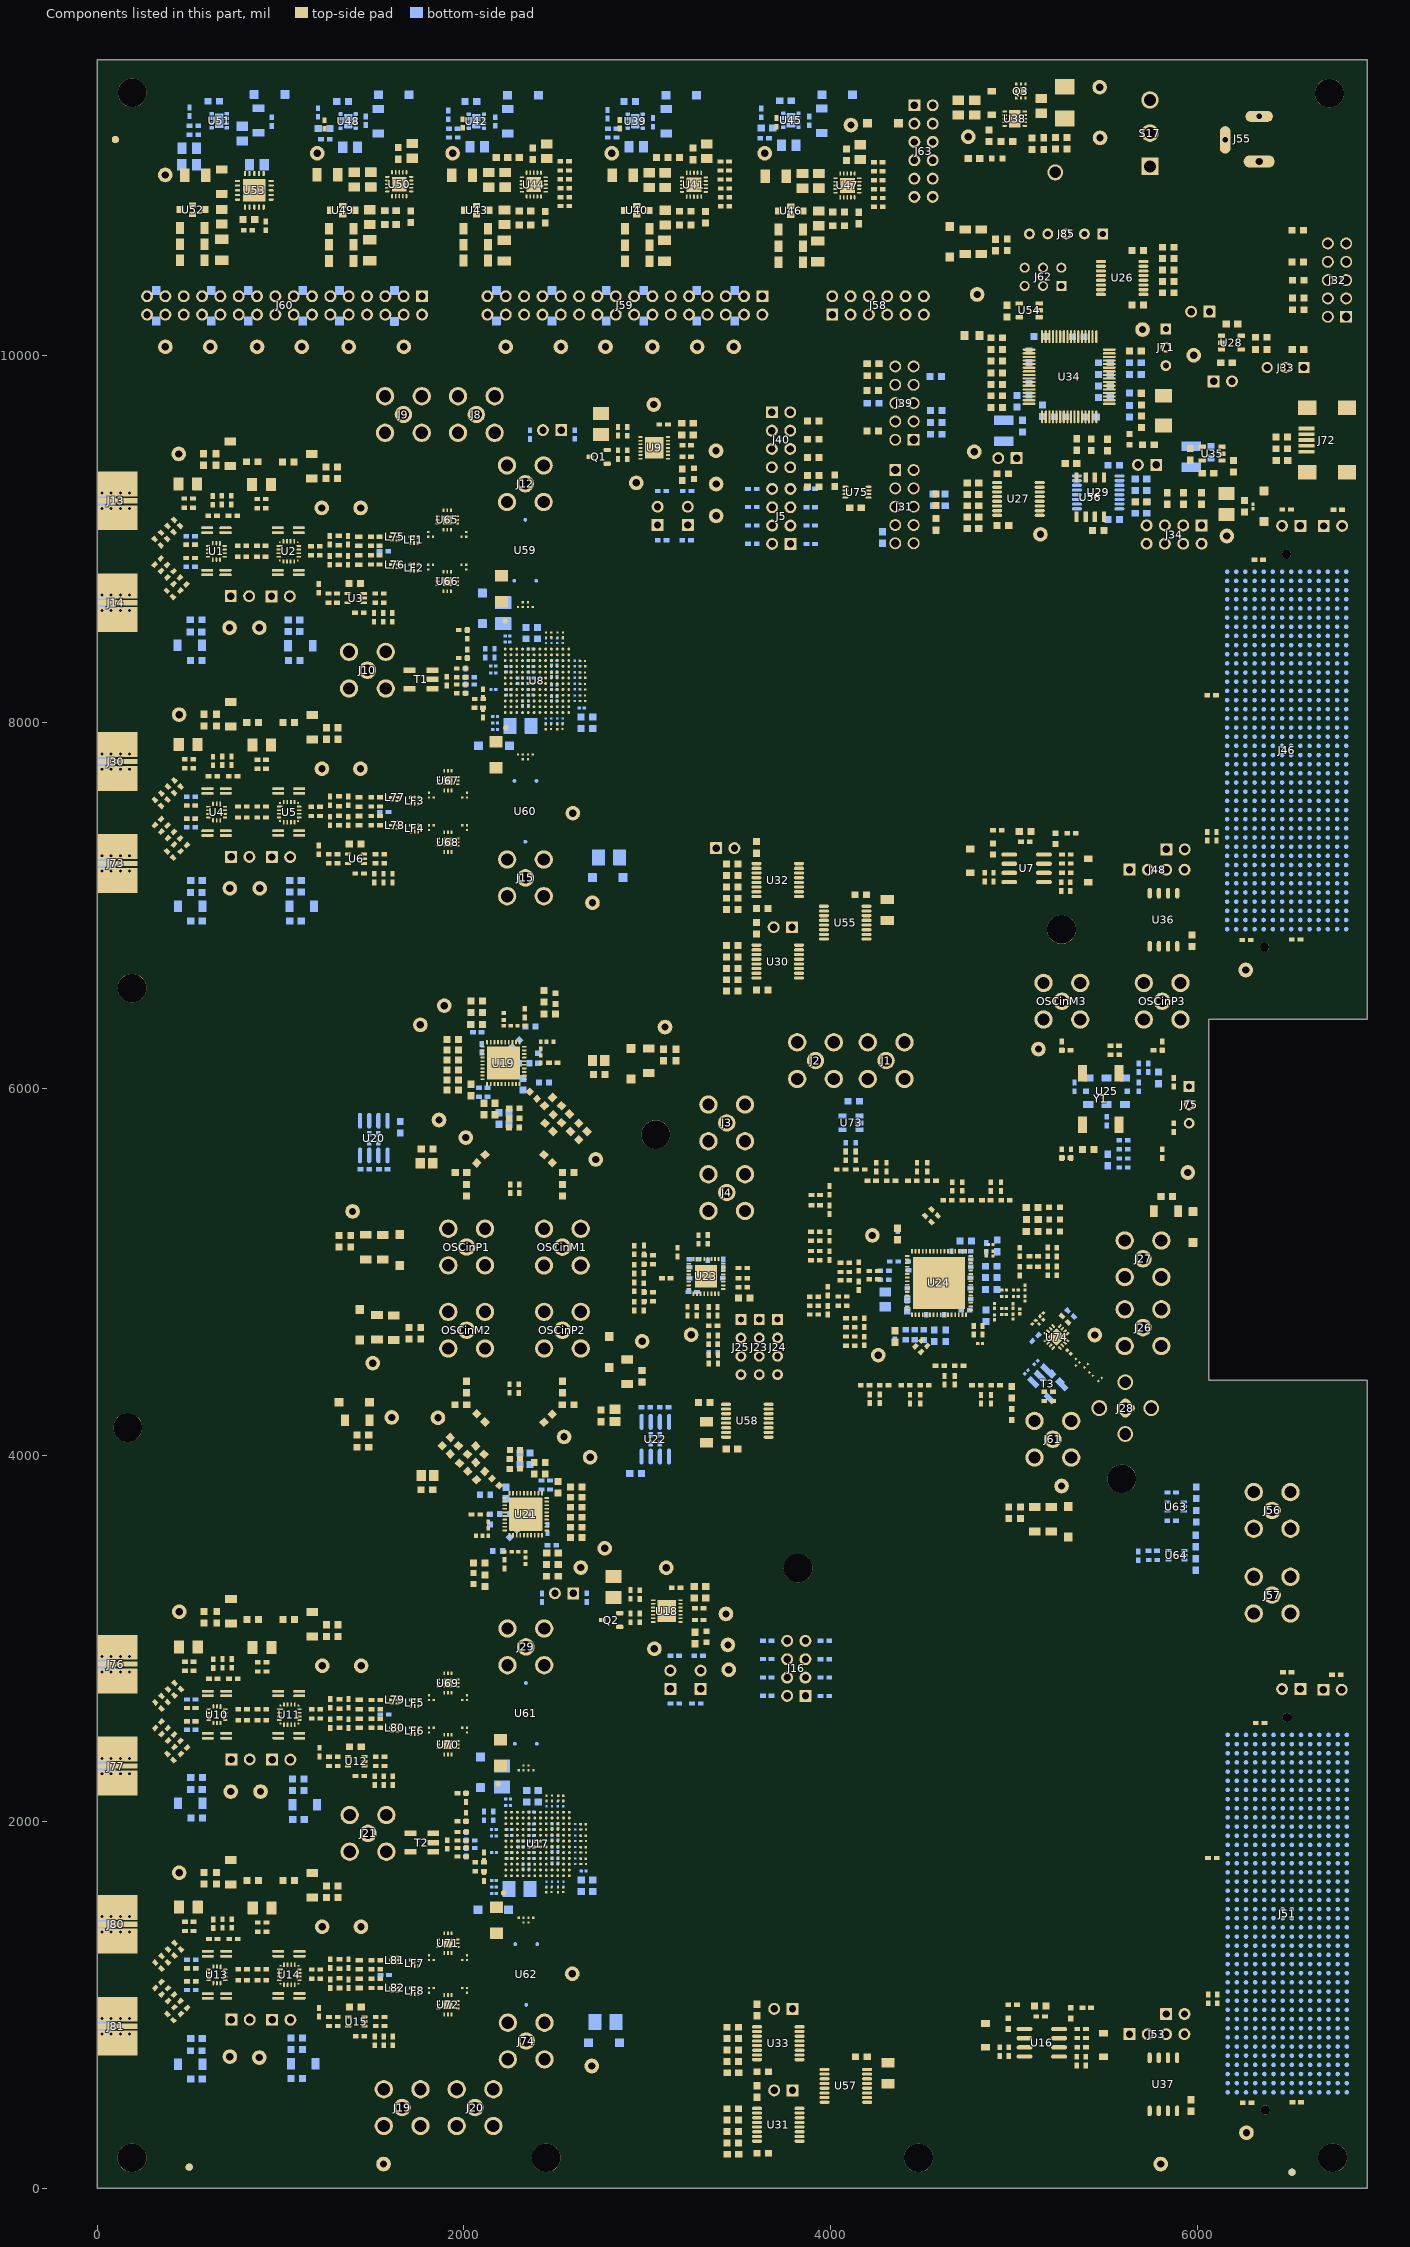
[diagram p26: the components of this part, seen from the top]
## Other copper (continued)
L12_Bottom Layer:
  pour cut-out: 5319.16,4642.16 5319.16,4640.84 5303.5,4656.5 5303.5,4661.5 5326.41,4684.41 5341,4669.82 5341,4664
  pour cut-out: 5259.87,4804.87 5371.08,4694.08 5306.5,4629.5 5233,4703 5175,4645 5231,4589 5301,4659 5369.5,4590.5 5263.5,4484.5 5101.5,4646.5
  pour cut-out: 2410.33,2361 2651.33,2602 6093.33,2602 6866.33,2602 6899.33,2569 6899.33,422 6855.33,378 6120.33,378 6081.33,417 6081.33,1045 2789.33,1045 2410.33,1424
  pour cut-out: 2407,8707 2648,8948 6090,8948 6863,8948 6896,8915 6896,6768 6852,6724 6117,6724 6078,6763 6078,7391 2786,7391 2407,7770
  pour cut-out: 2301.86,2041.72 ccw(c2308.69,2041.72) 2303.86,2036.9 ccw(c2311.1,2044.14) 2311.1,2033.9 2328.2,2033.9 ccw(c2328.2,2047.55) 2337.86,2037.9 ccw(c2330.62,2045.14) 2340.86,2045.14 2340.86,2059.24 ccw(c2327.2,2059.24) 2336.86,2068.9 ccw(c2332.03,2064.07) 2332.03,2070.9 2314.93,2070.9 ccw(c2314.93,2053.83) 2302.86,2065.9 ccw(c2305.28,2063.48) 2301.86,2063.48
  pour cut-out: 2333.36,2041.72 ccw(c2340.19,2041.72) 2335.36,2036.9 ccw(c2342.6,2044.14) 2342.6,2033.9 2359.7,2033.9 ccw(c2359.7,2047.55) 2369.36,2037.9 ccw(c2362.11,2045.14) 2372.36,2045.14 2372.36,2059.24 ccw(c2358.7,2059.24) 2368.36,2068.9 ccw(c2363.53,2064.07) 2363.53,2070.9 2346.43,2070.9 ccw(c2346.43,2053.83) 2334.36,2065.9 ccw(c2336.77,2063.48) 2333.36,2063.48
  pour cut-out: 2522.33,2041.72 ccw(c2529.16,2041.72) 2524.33,2036.9 ccw(c2531.58,2044.14) 2531.58,2033.9 2548.68,2033.9 ccw(c2548.68,2047.55) 2558.33,2037.9 ccw(c2551.09,2045.14) 2561.33,2045.14 2561.33,2059.24 ccw(c2547.68,2059.24) 2557.33,2068.9 ccw(c2552.51,2064.07) 2552.51,2070.9 2535.4,2070.9 ccw(c2535.4,2053.83) 2523.33,2065.9 ccw(c2525.75,2063.48) 2522.33,2063.48
  pour cut-out: 2522.33,2010.23 ccw(c2529.16,2010.23) 2524.33,2005.4 ccw(c2531.58,2012.64) 2531.58,2002.4 2548.68,2002.4 ccw(c2548.68,2016.06) 2558.33,2006.4 ccw(c2551.09,2013.64) 2561.33,2013.64 2561.33,2027.74 ccw(c2547.68,2027.74) 2557.33,2037.4 ccw(c2552.51,2032.57) 2552.51,2039.4 2535.4,2039.4 ccw(c2535.4,2022.33) 2523.33,2034.4 ccw(c2525.75,2031.99) 2522.33,2031.99
  pour cut-out: 2490.84,2010.23 ccw(c2497.67,2010.23) 2492.84,2005.4 ccw(c2500.08,2012.64) 2500.08,2002.4 2517.18,2002.4 ccw(c2517.18,2016.06) 2526.84,2006.4 ccw(c2519.6,2013.64) 2529.84,2013.64 2529.84,2027.74 ccw(c2516.18,2027.74) 2525.84,2037.4 ccw(c2521.01,2032.57) 2521.01,2039.4 2503.91,2039.4 ccw(c2503.91,2022.33) 2491.84,2034.4 ccw(c2494.25,2031.99) 2490.84,2031.99
  pour cut-out: 2490.84,2041.72 ccw(c2497.67,2041.72) 2492.84,2036.9 ccw(c2500.08,2044.14) 2500.08,2033.9 2517.18,2033.9 ccw(c2517.18,2047.55) 2526.84,2037.9 ccw(c2519.6,2045.14) 2529.84,2045.14 2529.84,2059.24 ccw(c2516.18,2059.24) 2525.84,2068.9 ccw(c2521.01,2064.07) 2521.01,2070.9 2503.91,2070.9 ccw(c2503.91,2053.83) 2491.84,2065.9 ccw(c2494.25,2063.48) 2490.84,2063.48
  pour cut-out: 2459.34,2010.23 ccw(c2466.17,2010.23) 2461.34,2005.4 ccw(c2468.58,2012.64) 2468.58,2002.4 2485.68,2002.4 ccw(c2485.68,2016.06) 2495.34,2006.4 ccw(c2488.1,2013.64) 2498.34,2013.64 2498.34,2027.74 ccw(c2484.68,2027.74) 2494.34,2037.4 ccw(c2489.51,2032.57) 2489.51,2039.4 2472.41,2039.4 ccw(c2472.41,2022.33) 2460.34,2034.4 ccw(c2462.76,2031.99) 2459.34,2031.99
  pour cut-out: 2459.34,2041.72 ccw(c2466.17,2041.72) 2461.34,2036.9 ccw(c2468.58,2044.14) 2468.58,2033.9 2485.68,2033.9 ccw(c2485.68,2047.55) 2495.34,2037.9 ccw(c2488.1,2045.14) 2498.34,2045.14 2498.34,2059.24 ccw(c2484.68,2059.24) 2494.34,2068.9 ccw(c2489.51,2064.07) 2489.51,2070.9 2472.41,2070.9 ccw(c2472.41,2053.83) 2460.34,2065.9 ccw(c2462.76,2063.48) 2459.34,2063.48
  pour cut-out: 2429.11,2011.49 ccw(c2435.93,2011.49) 2431.11,2006.66 ccw(c2438.35,2013.9) 2438.35,2003.66 2455.45,2003.66 ccw(c2455.45,2017.32) 2465.11,2007.66 ccw(c2457.86,2014.9) 2468.11,2014.9 2468.11,2029 ccw(c2454.45,2029) 2464.11,2038.66 ccw(c2459.28,2033.83) 2459.28,2040.66 2442.18,2040.66 ccw(c2442.18,2023.59) 2430.11,2035.66 ccw(c2432.52,2033.25) 2429.11,2033.25
  pour cut-out: 2427.85,2041.72 ccw(c2434.67,2041.72) 2429.85,2036.9 ccw(c2437.09,2044.14) 2437.09,2033.9 2454.19,2033.9 ccw(c2454.19,2047.55) 2463.85,2037.9 ccw(c2456.6,2045.14) 2466.85,2045.14 2466.85,2059.24 ccw(c2453.19,2059.24) 2462.85,2068.9 ccw(c2458.02,2064.07) 2458.02,2070.9 2440.92,2070.9 ccw(c2440.92,2053.83) 2428.85,2065.9 ccw(c2431.26,2063.48) 2427.85,2063.48
  pour cut-out: 2553.83,1789.76 ccw(c2560.66,1789.76) 2555.83,1784.93 ccw(c2563.07,1792.17) 2563.07,1781.93 2580.17,1781.93 ccw(c2580.17,1795.59) 2589.83,1785.93 ccw(c2582.59,1793.17) 2592.83,1793.17 2592.83,1807.27 ccw(c2579.17,1807.27) 2588.83,1816.93 ccw(c2584,1812.1) 2584,1818.93 2566.9,1818.93 ccw(c2566.9,1801.86) 2554.83,1813.93 ccw(c2557.24,1811.51) 2553.83,1811.51
  pour cut-out: 2524.08,1788.01 ccw(c2530.91,1788.01) 2526.08,1783.18 ccw(c2533.33,1790.42) 2533.33,1780.18 2550.43,1780.18 ccw(c2550.43,1793.84) 2560.08,1784.18 ccw(c2552.84,1791.42) 2563.08,1791.42 2563.08,1805.52 ccw(c2549.43,1805.52) 2559.08,1815.18 ccw(c2554.26,1810.35) 2554.26,1817.18 2537.15,1817.18 ccw(c2537.15,1800.11) 2525.08,1812.18 ccw(c2527.5,1809.76) 2524.08,1809.76
  pour cut-out: 2553.83,1821.25 ccw(c2560.66,1821.25) 2555.83,1816.42 ccw(c2563.07,1823.67) 2563.07,1813.42 2580.17,1813.42 ccw(c2580.17,1827.08) 2589.83,1817.42 ccw(c2582.59,1824.67) 2592.83,1824.67 2592.83,1838.77 ccw(c2579.17,1838.77) 2588.83,1848.42 ccw(c2584,1843.6) 2584,1850.42 2566.9,1850.42 ccw(c2566.9,1833.35) 2554.83,1845.42 ccw(c2557.24,1843.01) 2553.83,1843.01
  pour cut-out: 2524.08,1823 ccw(c2530.91,1823) 2526.08,1818.17 ccw(c2533.33,1825.41) 2533.33,1815.17 2550.43,1815.17 ccw(c2550.43,1828.83) 2560.08,1819.17 ccw(c2552.84,1826.41) 2563.08,1826.41 2563.08,1840.51 ccw(c2549.43,1840.51) 2559.08,1850.17 ccw(c2554.26,1845.34) 2554.26,1852.17 2537.15,1852.17 ccw(c2537.15,1835.1) 2525.08,1847.17 ccw(c2527.5,1844.76) 2524.08,1844.76
  pour cut-out: 2555.99,1850.59 ccw(c2562.82,1850.59) 2557.99,1845.76 ccw(c2565.23,1853.01) 2565.23,1842.76 2582.33,1842.76 ccw(c2582.33,1856.42) 2591.99,1846.76 ccw(c2584.74,1854.01) 2594.99,1854.01 2594.99,1868.11 ccw(c2581.33,1868.11) 2590.99,1877.76 ccw(c2586.16,1872.93) 2586.16,1879.76 2569.06,1879.76 ccw(c2569.06,1862.69) 2556.99,1874.76 ccw(c2559.4,1872.35) 2555.99,1872.35
  pour cut-out: 2522.33,1852.75 ccw(c2529.16,1852.75) 2524.33,1847.92 ccw(c2531.58,1855.16) 2531.58,1844.92 2548.68,1844.92 ccw(c2548.68,1858.58) 2558.33,1848.92 ccw(c2551.09,1856.16) 2561.33,1856.16 2561.33,1870.26 ccw(c2547.68,1870.26) 2557.33,1879.92 ccw(c2552.51,1875.09) 2552.51,1881.92 2535.4,1881.92 ccw(c2535.4,1864.85) 2523.33,1876.92 ccw(c2525.75,1874.51) 2522.33,1874.51
  pour cut-out: 2553.83,1884.24 ccw(c2560.66,1884.24) 2555.83,1879.42 ccw(c2563.07,1886.66) 2563.07,1876.42 2580.17,1876.42 ccw(c2580.17,1890.07) 2589.83,1880.42 ccw(c2582.59,1887.66) 2592.83,1887.66 2592.83,1901.76 ccw(c2579.17,1901.76) 2588.83,1911.42 ccw(c2584,1906.59) 2584,1913.42 2566.9,1913.42 ccw(c2566.9,1896.34) 2554.83,1908.42 ccw(c2557.24,1906) 2553.83,1906
  pour cut-out: 2522.33,1884.24 ccw(c2529.16,1884.24) 2524.33,1879.41 ccw(c2531.58,1886.65) 2531.58,1876.41 2548.68,1876.41 ccw(c2548.68,1890.07) 2558.33,1880.41 ccw(c2551.09,1887.65) 2561.33,1887.65 2561.33,1901.76 ccw(c2547.68,1901.76) 2557.33,1911.41 ccw(c2552.51,1906.58) 2552.51,1913.41 2535.4,1913.41 ccw(c2535.4,1896.34) 2523.33,1908.41 ccw(c2525.75,1906) 2522.33,1906
  pour cut-out: 2553.83,1915.74 ccw(c2560.66,1915.74) 2555.83,1910.91 ccw(c2563.07,1918.15) 2563.07,1907.91 2580.17,1907.91 ccw(c2580.17,1921.57) 2589.83,1911.91 ccw(c2582.59,1919.15) 2592.83,1919.15 2592.83,1933.26 ccw(c2579.17,1933.26) 2588.83,1942.91 ccw(c2584,1938.08) 2584,1944.91 2566.9,1944.91 ccw(c2566.9,1927.84) 2554.83,1939.91 ccw(c2557.24,1937.5) 2553.83,1937.5
  pour cut-out: 2522.33,1915.74 ccw(c2529.16,1915.74) 2524.33,1910.91 ccw(c2531.58,1918.15) 2531.58,1907.91 2548.68,1907.91 ccw(c2548.68,1921.57) 2558.33,1911.91 ccw(c2551.09,1919.15) 2561.33,1919.15 2561.33,1933.26 ccw(c2547.68,1933.26) 2557.33,1942.91 ccw(c2552.51,1938.08) 2552.51,1944.91 2535.4,1944.91 ccw(c2535.4,1927.84) 2523.33,1939.91 ccw(c2525.75,1937.5) 2522.33,1937.5
  pour cut-out: 2524.08,1948.98 ccw(c2530.91,1948.98) 2526.08,1944.15 ccw(c2533.33,1951.4) 2533.33,1941.15 2550.43,1941.15 ccw(c2550.43,1954.81) 2560.08,1945.15 ccw(c2552.84,1952.4) 2563.08,1952.4 2563.08,1966.5 ccw(c2549.43,1966.5) 2559.08,1976.15 ccw(c2554.26,1971.33) 2554.26,1978.15 2537.15,1978.15 ccw(c2537.15,1961.08) 2525.08,1973.15 ccw(c2527.5,1970.74) 2524.08,1970.74
  pour cut-out: 2553.83,1947.24 ccw(c2560.66,1947.24) 2555.83,1942.41 ccw(c2563.07,1949.65) 2563.07,1939.41 2580.17,1939.41 ccw(c2580.17,1953.07) 2589.83,1943.41 ccw(c2582.59,1950.65) 2592.83,1950.65 2592.83,1964.75 ccw(c2579.17,1964.75) 2588.83,1974.41 ccw(c2584,1969.58) 2584,1976.41 2566.9,1976.41 ccw(c2566.9,1959.34) 2554.83,1971.41 ccw(c2557.24,1968.99) 2553.83,1968.99
  pour cut-out: 2553.83,1978.73 ccw(c2560.66,1978.73) 2555.83,1973.9 ccw(c2563.07,1981.15) 2563.07,1970.9 2580.17,1970.9 ccw(c2580.17,1984.56) 2589.83,1974.9 ccw(c2582.59,1982.15) 2592.83,1982.15 2592.83,1996.25 ccw(c2579.17,1996.25) 2588.83,2005.9 ccw(c2584,2001.08) 2584,2007.9 2566.9,2007.9 ccw(c2566.9,1990.83) 2554.83,2002.9 ccw(c2557.24,2000.49) 2553.83,2000.49
  pour cut-out: 2522.33,1978.73 ccw(c2529.16,1978.73) 2524.33,1973.9 ccw(c2531.58,1981.15) 2531.58,1970.9 2548.68,1970.9 ccw(c2548.68,1984.56) 2558.33,1974.9 ccw(c2551.09,1982.15) 2561.33,1982.15 2561.33,1996.25 ccw(c2547.68,1996.25) 2557.33,2005.9 ccw(c2552.51,2001.08) 2552.51,2007.9 2535.4,2007.9 ccw(c2535.4,1990.83) 2523.33,2002.9 ccw(c2525.75,2000.49) 2522.33,2000.49
  pour cut-out: 2553.83,1758.26 ccw(c2560.66,1758.26) 2555.83,1753.43 ccw(c2563.07,1760.67) 2563.07,1750.43 2580.17,1750.43 ccw(c2580.17,1764.09) 2589.83,1754.43 ccw(c2582.59,1761.67) 2592.83,1761.67 2592.83,1775.77 ccw(c2579.17,1775.77) 2588.83,1785.43 ccw(c2584,1780.6) 2584,1787.43 2566.9,1787.43 ccw(c2566.9,1770.36) 2554.83,1782.43 ccw(c2557.24,1780.02) 2553.83,1780.02
  pour cut-out: 2522.33,1758.26 ccw(c2529.16,1758.26) 2524.33,1753.43 ccw(c2531.58,1760.67) 2531.58,1750.43 2548.68,1750.43 ccw(c2548.68,1764.09) 2558.33,1754.43 ccw(c2551.09,1761.67) 2561.33,1761.67 2561.33,1775.77 ccw(c2547.68,1775.77) 2557.33,1785.43 ccw(c2552.51,1780.6) 2552.51,1787.43 2535.4,1787.43 ccw(c2535.4,1770.36) 2523.33,1782.43 ccw(c2525.75,1780.02) 2522.33,1780.02
  pour cut-out: 2522.33,1695.27 ccw(c2529.16,1695.27) 2524.33,1690.44 ccw(c2531.58,1697.68) 2531.58,1687.44 2548.68,1687.44 ccw(c2548.68,1701.1) 2558.33,1691.44 ccw(c2551.09,1698.68) 2561.33,1698.68 2561.33,1712.78 ccw(c2547.68,1712.78) 2557.33,1722.44 ccw(c2552.51,1717.61) 2552.51,1724.44 2535.4,1724.44 ccw(c2535.4,1707.37) 2523.33,1719.44 ccw(c2525.75,1717.03) 2522.33,1717.03
  pour cut-out: 2522.33,1726.76 ccw(c2529.16,1726.76) 2524.33,1721.94 ccw(c2531.58,1729.18) 2531.58,1718.94 2548.68,1718.94 ccw(c2548.68,1732.59) 2558.33,1722.94 ccw(c2551.09,1730.18) 2561.33,1730.18 2561.33,1744.28 ccw(c2547.68,1744.28) 2557.33,1753.94 ccw(c2552.51,1749.11) 2552.51,1755.94 2535.4,1755.94 ccw(c2535.4,1738.86) 2523.33,1750.94 ccw(c2525.75,1748.52) 2522.33,1748.52
  pour cut-out: 2490.84,1695.27 ccw(c2497.67,1695.27) 2492.84,1690.44 ccw(c2500.08,1697.68) 2500.08,1687.44 2517.18,1687.44 ccw(c2517.18,1701.1) 2526.84,1691.44 ccw(c2519.6,1698.68) 2529.84,1698.68 2529.84,1712.78 ccw(c2516.18,1712.78) 2525.84,1722.44 ccw(c2521.01,1717.61) 2521.01,1724.44 2503.91,1724.44 ccw(c2503.91,1707.37) 2491.84,1719.44 ccw(c2494.25,1717.03) 2490.84,1717.03
  pour cut-out: 2490.84,1726.76 ccw(c2497.67,1726.76) 2492.84,1721.94 ccw(c2500.08,1729.18) 2500.08,1718.94 2517.18,1718.94 ccw(c2517.18,1732.59) 2526.84,1722.94 ccw(c2519.6,1730.18) 2529.84,1730.18 2529.84,1744.28 ccw(c2516.18,1744.28) 2525.84,1753.94 ccw(c2521.01,1749.11) 2521.01,1755.94 2503.91,1755.94 ccw(c2503.91,1738.86) 2491.84,1750.94 ccw(c2494.25,1748.52) 2490.84,1748.52
  pour cut-out: 2459.34,1695.27 ccw(c2466.17,1695.27) 2461.34,1690.44 ccw(c2468.58,1697.68) 2468.58,1687.44 2485.68,1687.44 ccw(c2485.68,1701.1) 2495.34,1691.44 ccw(c2488.1,1698.68) 2498.34,1698.68 2498.34,1712.78 ccw(c2484.68,1712.78) 2494.34,1722.44 ccw(c2489.51,1717.61) 2489.51,1724.44 2472.41,1724.44 ccw(c2472.41,1707.37) 2460.34,1719.44 ccw(c2462.76,1717.03) 2459.34,1717.03
  pour cut-out: 2459.34,1726.76 ccw(c2466.17,1726.76) 2461.34,1721.94 ccw(c2468.58,1729.18) 2468.58,1718.94 2485.68,1718.94 ccw(c2485.68,1732.59) 2495.34,1722.94 ccw(c2488.1,1730.18) 2498.34,1730.18 2498.34,1744.28 ccw(c2484.68,1744.28) 2494.34,1753.94 ccw(c2489.51,1749.11) 2489.51,1755.94 2472.41,1755.94 ccw(c2472.41,1738.86) 2460.34,1750.94 ccw(c2462.76,1748.52) 2459.34,1748.52
  pour cut-out: 2427.85,1726.76 ccw(c2434.68,1726.76) 2429.85,1721.94 ccw(c2437.09,1729.18) 2437.09,1718.94 2454.19,1718.94 ccw(c2454.19,1732.59) 2463.85,1722.94 ccw(c2456.61,1730.18) 2466.85,1730.18 2466.85,1744.28 ccw(c2453.19,1744.28) 2462.85,1753.94 ccw(c2458.02,1749.11) 2458.02,1755.94 2440.92,1755.94 ccw(c2440.92,1738.86) 2428.85,1750.94 ccw(c2431.27,1748.52) 2427.85,1748.52
  pour cut-out: 2427.85,1695.27 ccw(c2434.67,1695.27) 2429.85,1690.44 ccw(c2437.09,1697.68) 2437.09,1687.44 2454.19,1687.44 ccw(c2454.19,1701.1) 2463.85,1691.44 ccw(c2456.6,1698.68) 2466.85,1698.68 2466.85,1712.78 ccw(c2453.19,1712.78) 2462.85,1722.44 ccw(c2458.02,1717.61) 2458.02,1724.44 2440.92,1724.44 ccw(c2440.92,1707.37) 2428.85,1719.44 ccw(c2431.26,1717.03) 2427.85,1717.03
  pour cut-out: 2333.36,1695.27 ccw(c2340.19,1695.27) 2335.36,1690.44 ccw(c2342.6,1697.68) 2342.6,1687.44 2359.7,1687.44 ccw(c2359.7,1701.1) 2369.36,1691.44 ccw(c2362.11,1698.68) 2372.36,1698.68 2372.36,1712.78 ccw(c2358.7,1712.78) 2368.36,1722.44 ccw(c2363.53,1717.61) 2363.53,1724.44 2346.43,1724.44 ccw(c2346.43,1707.37) 2334.36,1719.44 ccw(c2336.77,1717.03) 2333.36,1717.03
  pour cut-out: 2301.86,1695.27 ccw(c2308.69,1695.27) 2303.86,1690.44 ccw(c2311.1,1697.68) 2311.1,1687.44 2328.2,1687.44 ccw(c2328.2,1701.1) 2337.86,1691.44 ccw(c2330.62,1698.68) 2340.86,1698.68 2340.86,1712.78 ccw(c2327.2,1712.78) 2336.86,1722.44 ccw(c2332.03,1717.61) 2332.03,1724.44 2314.93,1724.44 ccw(c2314.93,1707.37) 2302.86,1719.44 ccw(c2305.28,1717.03) 2301.86,1717.03
  pour cut-out: 2270.37,1758.26 ccw(c2277.19,1758.26) 2272.37,1753.43 ccw(c2279.61,1760.67) 2279.61,1750.43 2296.71,1750.43 ccw(c2296.71,1764.09) 2306.37,1754.43 ccw(c2299.12,1761.67) 2309.37,1761.67 2309.37,1775.77 ccw(c2295.71,1775.77) 2305.37,1785.43 ccw(c2300.54,1780.6) 2300.54,1787.43 2283.44,1787.43 ccw(c2283.44,1770.36) 2271.37,1782.43 ccw(c2273.78,1780.02) 2270.37,1780.02
  pour cut-out: 2238.87,1758.26 ccw(c2245.7,1758.26) 2240.87,1753.43 ccw(c2248.11,1760.67) 2248.11,1750.43 2265.21,1750.43 ccw(c2265.21,1764.09) 2274.87,1754.43 ccw(c2267.63,1761.67) 2277.87,1761.67 2277.87,1775.77 ccw(c2264.21,1775.77) 2273.87,1785.43 ccw(c2269.04,1780.6) 2269.04,1787.43 2251.94,1787.43 ccw(c2251.94,1770.36) 2239.87,1782.43 ccw(c2242.28,1780.02) 2238.87,1780.02
  pour cut-out: 2207.37,1726.76 ccw(c2214.2,1726.76) 2209.37,1721.94 ccw(c2216.62,1729.18) 2216.62,1718.94 2233.72,1718.94 ccw(c2233.72,1732.59) 2243.37,1722.94 ccw(c2236.13,1730.18) 2246.37,1730.18 2246.37,1744.28 ccw(c2232.72,1744.28) 2242.37,1753.94 ccw(c2237.54,1749.11) 2237.54,1755.94 2220.44,1755.94 ccw(c2220.44,1738.86) 2208.37,1750.94 ccw(c2210.79,1748.52) 2207.37,1748.52
  pour cut-out: 2207.37,1758.26 ccw(c2214.2,1758.26) 2209.37,1753.43 ccw(c2216.62,1760.67) 2216.62,1750.43 2233.72,1750.43 ccw(c2233.72,1764.09) 2243.37,1754.43 ccw(c2236.13,1761.67) 2246.37,1761.67 2246.37,1775.77 ccw(c2232.72,1775.77) 2242.37,1785.43 ccw(c2237.54,1780.6) 2237.54,1787.43 2220.44,1787.43 ccw(c2220.44,1770.36) 2208.37,1782.43 ccw(c2210.79,1780.02) 2207.37,1780.02
  pour cut-out: 2207.37,1852.75 ccw(c2214.2,1852.75) 2209.37,1847.92 ccw(c2216.62,1855.16) 2216.62,1844.92 2233.72,1844.92 ccw(c2233.72,1858.58) 2243.37,1848.92 ccw(c2236.13,1856.16) 2246.37,1856.16 2246.37,1870.26 ccw(c2232.72,1870.26) 2242.37,1879.92 ccw(c2237.54,1875.09) 2237.54,1881.92 2220.44,1881.92 ccw(c2220.44,1864.85) 2208.37,1876.92 ccw(c2210.79,1874.51) 2207.37,1874.51
  pour cut-out: 2207.37,1884.24 ccw(c2214.2,1884.24) 2209.37,1879.42 ccw(c2216.62,1886.66) 2216.62,1876.42 2233.72,1876.42 ccw(c2233.72,1890.07) 2243.37,1880.42 ccw(c2236.13,1887.66) 2246.37,1887.66 2246.37,1901.76 ccw(c2232.72,1901.76) 2242.37,1911.42 ccw(c2237.54,1906.59) 2237.54,1913.42 2220.44,1913.42 ccw(c2220.44,1896.35) 2208.37,1908.42 ccw(c2210.79,1906) 2207.37,1906
  pour cut-out: 2207.37,1978.73 ccw(c2214.2,1978.73) 2209.37,1973.9 ccw(c2216.62,1981.15) 2216.62,1970.9 2233.72,1970.9 ccw(c2233.72,1984.56) 2243.37,1974.9 ccw(c2236.13,1982.15) 2246.37,1982.15 2246.37,1996.25 ccw(c2232.72,1996.25) 2242.37,2005.9 ccw(c2237.54,2001.08) 2237.54,2007.9 2220.44,2007.9 ccw(c2220.44,1990.83) 2208.37,2002.9 ccw(c2210.79,2000.49) 2207.37,2000.49
  pour cut-out: 2207.37,2010.23 ccw(c2214.2,2010.23) 2209.37,2005.4 ccw(c2216.62,2012.64) 2216.62,2002.4 2233.72,2002.4 ccw(c2233.72,2016.06) 2243.37,2006.4 ccw(c2236.13,2013.64) 2246.37,2013.64 2246.37,2027.74 ccw(c2232.72,2027.74) 2242.37,2037.4 ccw(c2237.54,2032.57) 2237.54,2039.4 2220.44,2039.4 ccw(c2220.44,2022.33) 2208.37,2034.4 ccw(c2210.79,2031.99) 2207.37,2031.99
  text "'.Layer_Name'" at -2296.32,-2314.1 h60
Multi-Layer:
  drawing of 162 lines, arcs and shapes, not listed

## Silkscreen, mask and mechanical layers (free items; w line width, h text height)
Top Overlay:
  drawing of 497 lines, arcs and shapes, not listed
  text "GND1" at 5431,11373 h25
  text "12VIN" at 3937,11274 h25
  text "12V_DC" at 5397,11255 h25
  text "12V" at 4622,11174 h25
  text "V1P1V_CONV" at 1833,11173 h25
  text "3P3_CONV" at 3538,11171 h25
  text "VA3P75_CONV" at 1078,11169 h25
  text "V1P9V_CONV" at 2697,11166 h25
  text "12V_DCIN" at 6542,11129 h25
  text "ON/OFF" at 5621,11110 h30 r90
  text "EN/UVLO" at 5314,10966 h25
  text "12VIN_LED" at 4792,10948 h30
  text "VA_N1P25_CONV" at 226,10896 h25
  text "ADC_SCS4X" at 5304,10724 h25 r90
  text "ADC_SCS2X" at 5500,10724 h25 r90
  text "LMH_CSX1" at 5194,10722 h25 r90
  text "ADC_SCS3X" at 5391,10722 h25 r90
  text "LMH_CS_1X" at 5091,10721 h25 r90
  text "SMB_CLK" at 6714,10699 h25
  text "SMB_DAT" at 6483,10596 h25
  text "SMB_CLK" at 5046,10554 h25
  text "SMB_DAT" at 5228,10554 h25
  text "EADC_SCK" at 6427,10551 h25
  text "SMB_DAT" at 4830,10471 h25
  text "GND" at 2736,10425 h25
  text "GND" at 3236,10425 h25
  text "GND" at 446,10422 h25
  text "VA_N1P25_IN" at 745,10422 h25
  text "GND" at 1246,10422 h25
  text "VA3P75_IN" at 1575,10422 h25
  text "GND" at 2190,10422 h25
  text "V1P1V_IN" at 2443,10422 h25
  text "V1P9V_IN" at 2944,10422 h25
  text "V3P3_IN" at 3444,10422 h25
  text "BDBUS2" at 4835,10410 h25
  text "DGND" at 6911,10380 h25 r90
  text "EADC_SDI" at 6446,10349 h25
  text "GND" at 4593,10289 h25 r90
  text "V3P3_VDD" at 4684,10243 h25
  text "PWR_SYNC" at 3753,10204 h25
  text "EADC_SCS" at 6445,10180 h25
  text "BDBUS1" at 5280,10179 h25 r90
  text "DGND" at 4593,10177 h25 r90
  text "EADC_SDO" at 6913,10173 h25 r90
  text "BDBUS0" at 5213,10166 h25 r90
  text "V3P3_VDD" at 5888,10116 h25
  text "USB_ACTIVITY" at 4370,10093 h25
  text "3P3USB" at 5594,10078 h25 r90
  text "VREGIN" at 5920,9967 h25 r90
  text "DGND" at 2196,9925 h25
  text "DGND" at 2740,9925 h25
  text "AGND" at 1332,9923 h25
  text "VA_N1P25" at 783,9922 h25
  text "AGND" at 1072,9922 h25
  text "VA3P75" at 1608,9922 h25
  text "V1P1V" at 2492,9922 h25
  text "V1P9V" at 2986,9921 h25
  text "DGND" at 3240,9921 h25
  text "AGND" at 331,9920 h25
  text "AGND" at 574,9918 h25
  text "V3P3" at 3435,9916 h25
  text "DGND" at 5935,9914 h25
  text "BADC1_SCS" at 6542,9838 h25
  text "V_BUS" at 5919,9834 h25 r90
  text "1" at 3608,9693 h25
  text "2" at 3840,9693 h25
  text "EADC_SCS" at 6491,9679 h25 r90
  text "TDIODE1-" at 2431,9657 h25 r90
  text "TDIODE1+" at 2544,9653 h25 r90
  text "BADC2_SCS" at 6389,9650 h25 r90
  text "1P8V_USB" at 4697,9582 h25
  text "VCC_LMH5401" at 209.27,9529.24 h30
  text "1" at 4528,9524 h25
  text "2" at 4273,9513 h25
  text "TMSTP1+" at 1993,9471 h30
  text "TMSTP1-" at 1588,9469 h30
  text "1" at 4271,9358 h25
  text "2" at 4514,9358 h25
  text "VREGIN" at 5590,9308 h25 r90
  text "VCC_LMH6401" at 1062,9232 h30
  text "AGND" at 1499,9155 h25
  text "PD1" at 2923,9055 h25
  text "ANALOG I/P" at 2206.68,9050.9 h30
  text "CALTRG1" at 3288,9026 h25
  text "CH1_AC_COUP" at 2200.68,9005.9 h30
  text "DGND" at 5213,8995 h25
  text "2" at 3599,8957 h25
  text "1" at 3842,8956 h25
  text "ANALOG I/P" at 18.68,8909.9 h30
  text "VDDL19" at 6104,8883 h25
  text "CH1" at 85.68,8869.9 h30
  text "J40 CONNECTOR" at 3377,8563 h25
  text "J39 CONNECTOR" at 4452,8563 h25
  text "J34 CONNECTOR" at 5548,8563 h25
  text "VA1P1_ADC1" at 1964,8561 h25
  text "PIN NO" at 3586,8507 h25
  text "NETNAME" at 3765,8507 h25
  text "PIN NO" at 4661,8507 h25
  text "NETNAME" at 4840,8507 h25
  text "PIN NO" at 5757,8507 h25
  text "NETNAME" at 5936,8507 h25
  text "PIN NO" at 3099,8506 h25
  text "NETNAME" at 3278,8506 h25
  text "PIN NO" at 4174,8506 h25
  text "NETNAME" at 4353,8506 h25
  text "PIN NO" at 5270,8506 h25
  text "NETNAME" at 5449,8506 h25
  text "2" at 3659,8454 h25
  text "2" at 4734,8454 h25
  text "2" at 5830,8454 h25
  text "ELMK_CS" at 3767,8451 h25
  text "ELMK_CS" at 4842,8451 h25
  text "ELMH_CS" at 5938,8451 h25
  text "1" at 3151,8447 h25
  text "BLMK_SCS" at 3276,8447 h25
  text "1" at 4226,8447 h25
  text "LMK_EXT_SYNC" at 4351,8447 h25
  text "1" at 5322,8447 h25
  text "BLMH1_SCS" at 5447,8447 h25
  text "BLMX1_SCS" at 3275,8387 h25
  text "ELMK_SDO" at 4350,8387 h25
  text "BLMH2_SCS" at 5446,8387 h25
  text "4" at 3660,8386 h25
  text "ELMK_CS" at 3768,8386 h25
  text "4" at 4735,8386 h25
  text "ELMK_SDIO" at 4841,8386 h25
  text "4" at 5831,8386 h25
  text "ELMH_CS" at 5939,8386 h25
  text "3" at 3149,8385 h25
  text "3" at 4224,8385 h25
  text "3" at 5320,8385 h25
  text "5" at 3147,8329 h25
  text "5" at 4222,8329 h25
  text "5" at 5318,8329 h25
  text "BLMX2_SCS" at 3274,8326 h25
  text "CLKIN_SEL1" at 4349,8326 h25
  text "BLMH3_SCS" at 5445,8326 h25
  text "ELMK_CS" at 3768,8325 h25
  text "PULL DOWN" at 4843,8325 h25
  text "ELMH_CS" at 5939,8325 h25
  text "6" at 3658,8324 h25
  text "6" at 4733,8324 h25
  text "6" at 5829,8324 h25
  text "T1" at 1750,8323 h25
  text "VEE_LMH5401" at 648,8269 h30 r90
  text "LMX_SDO_MSEL" at 3274,8264 h25
  text "NC" at 4349,8264 h25
  text "BLMH4_SCS" at 5445,8264 h25
  text "7" at 3148,8262 h25
  text "7" at 4223,8262 h25
  text "7" at 5319,8262 h25
  text "VEE_LMH6401" at 989.03,8261.27 h30 r90
  text "DGND" at 3770,8260 h25
  text "ELMK_SCK" at 4845,8260 h25
  text "ELMH_CS" at 5941,8260 h25
  text "8" at 3659,8259 h25
  text "8" at 4734,8259 h25
  text "8" at 5830,8259 h25
  text "CLKIN_SEL0" at 4840,8202 h25
  text "IOVLVL" at 4349,8200 h25
  text "9" at 4222,8199 h25
  text "10" at 4737,8199 h25
  text "VCC_LMH5401" at 224.27,8108.24 h30
  text "DEVCLKIN1" at 1388,8039 h30
  text "J31 CONNECTOR" at 4452,8021 h25
  text "J5 CONNECTOR" at 3377,8020 h25
  text "PIN NO" at 4661,7965 h25
  text "NETNAME" at 4840,7965 h25
  text "PIN NO" at 3486,7964 h25
  text "NETNAME" at 3665,7964 h25
  text "PIN NO" at 4174,7964 h25
  text "NETNAME" at 4353,7964 h25
  text "PIN NO" at 3099,7963 h25
  text "NETNAME" at 3278,7963 h25
  text "2" at 4734,7912 h25
  text "2" at 3559,7911 h25
  text "ELMH_CS" at 4842,7909 h25
  text "AADC1_NCOA0" at 3667,7908 h25
  text "1" at 4226,7905 h25
  text "NC" at 4351,7905 h25
  text "1" at 3151,7904 h25
  text "PULL UP" at 3276,7904 h25
  text "ELMH_SDO" at 4350,7845 h25
  text "PULL UP" at 3275,7844 h25
  text "4" at 4735,7844 h25
  text "ELMH_SDI" at 4841,7844 h25
  text "4" at 3560,7843 h25
  text "AADC1_NCOA1" at 3668,7843 h25
  text "3" at 4224,7843 h25
  text "3" at 3149,7842 h25
  text "VCC_LMH6401" at 1077,7811 h30
  text "5" at 4222,7787 h25
  text "5" at 3147,7786 h25
  text "DGND" at 4349,7784 h25
  text "PULL UP" at 3274,7783 h25
  text "PULL DOWN" at 4843,7783 h25
  text "AADC1_NCOB0" at 3668,7782 h25
  text "6" at 4733,7782 h25
  text "6" at 3558,7781 h25
  text "NC" at 4349,7722 h25
  text "PULL UP" at 3274,7721 h25
  text "7" at 4223,7720 h25
  text "7" at 3148,7719 h25
  text "ELMH_SCK" at 4845,7718 h25
  text "AADC1_NCOB1" at 3670,7717 h25
  text "8" at 4734,7717 h25
  text "8" at 3559,7716 h25
  text "AGND" at 1497,7705 h25
  text "VA1P9_ADC1" at 2264,7693 h25 r90
  text "NC" at 4840,7660 h25
  text "PULL DOWN" at 4349,7658 h25
  text "9" at 4222,7657 h25
  text "10" at 4737,7657 h25
  text "FMC+_1 CONNECTOR" at 6583,7540 h60 r90
  text "ANALOG I/P" at 15.68,7494.9 h30
  text "DGND" at 2666,7476 h25
  text "CH2" at 82.68,7454.9 h30
  text "ANALOG I/P" at 2180.68,7410.9 h30
  text "CH2_AC_COUP" at 2174.68,7365.9 h30
  text "FMC_SDA1" at 5635,7256 h25 r90
  text "FMC_SCL1" at 5736,7255 h25 r90
  text "3P3VAUX1" at 5993,7181 h25
  text "DGND" at 5795,7107 h25
  text "VD1P1_ADC1" at 2592,7091 h25
  text "VEE_LMH5401" at 649.8,6846.87 h30 r90
  text "VEE_LMH6401" at 990.83,6839.14 h30 r90
  text "LMK_OSCIN_P/N" at 5351,6694 h30
  text "V3P3_LMX1RF" at 2968,6407 h30
  text "DGND" at 4975,6185 h25
  text "SDCLKOUT13_P/N" at 3923,5930 h30
  text "EN" at 5835.06,5900.52 h25
  text "DGND" at 1926,5641 h25
  text "TIDA-01022-E2" at 70.68,5620.9 h100
  text "V3P3_LMK61E2" at 5535,5520 h30
  text "DCLKOUT12_P/N" at 3643,5430 h30 r90
  text "V3P3_LMX1" at 1071,5306 h30
  text "GND" at 1469.68,5251.9 h30
  text "DGND" at 5407,4720 h25
  text "CLKIN0_P/N" at 5917,4702 h30 r90
  text "DGND" at 3176,4609 h25 r90
  text "V3P3_LMX2" at 1176,4487 h30
  text "DGND" at 4328,4482 h25
  text "V3P3_LMK00304" at 3088,4333 h30 r90
  text "DGND" at 2612,4084 h25
  text "LMK_CLKIN" at 5685,4020 h25 r45
  text "RESET" at 4930,4006 h25
  text "SYNCSE_EXTIN" at 6258,3885 h25
  text "V3P3_LMX2RF" at 1593,3823 h30 r90
  text "V3P3_LMK48xx" at 4832.23,3793.01 h30
  text "SYNCSE_EXTOUT" at 6258,3413 h25
  text "VCC_LMH5401" at 213,3213 h30
  text "TDIODE2+" at 2619,2968 h25 r90
  text "TDIODE2-" at 2579,2967 h25 r90
  text "VCC_LMH6401" at 1066,2916 h30
  text "AGND" at 1506,2828 h25
  text "ANALOG I/P" at 2213.68,2707.9 h30
  text "PD2" at 2969,2700 h25
  text "CALTRG2" at 3369,2667 h25
  text "CH3_AC_COUP" at 2207.68,2662.9 h30
  text "2" at 3681,2643 h25
  text "1" at 3926,2641 h25
  text "ANALOG I/P" at 22.76,2563.54 h30
  text "CH3" at 89.76,2523.54 h30
  text "VA1P1_ADC2" at 1907,2216 h25
  text "J16 CONNECTOR" at 3777,2180 h25
  text "PIN NO" at 3886,2124 h25
  text "NETNAME" at 4065,2124 h25
  text "PIN NO" at 3499,2123 h25
  text "NETNAME" at 3678,2123 h25
  text "2" at 3959,2071 h25
  text "AADC2_NCOA0" at 4067,2068 h25
  text "1" at 3551,2064 h25
  text "PULL UP" at 3676,2064 h25
  text "PULL UP" at 3675,2004 h25
  text "4" at 3960,2003 h25
  text "AADC2_NCOA1" at 4068,2003 h25
  text "3" at 3549,2002 h25
  text "5" at 3547,1946 h25
  text "PULL UP" at 3674,1943 h25
  text "AADC2_NCOB0" at 4068,1942 h25
  text "6" at 3958,1941 h25
  text "VEE_LMH5401" at 652.08,1900.64 h30 r90
  text "VEE_LMH6401" at 993.11,1892.91 h30 r90
  text "PULL UP" at 3674,1881 h25
  text "7" at 3548,1879 h25
  text "AADC2_NCOB1" at 4070,1877 h25
  text "8" at 3959,1876 h25
  text "VCC_LMH5401" at 212,1790 h30
  text "DEVCLKIN2" at 1400,1695 h30
  text "VCC_LMH6401" at 1064,1493 h30
  text "AGND" at 1501,1386 h25
  text "VA1P9_ADC2" at 2270,1323 h25 r90
  text "ANALOG I/P" at 20.92,1144.21 h30
  text "DGND" at 2661,1138 h25
  text "FMC+_2 CONNECTOR" at 6650,1137 h60 r90
  text "CH4" at 87.92,1104.21 h30
  text "ANALOG I/P" at 2188.68,1040.9 h30
  text "CH4_AC_COUP" at 2182.68,995.9 h30
  text "FMC_SDA2" at 5634.19,902.71 h25 r90
  text "FMC_SCL2" at 5735.19,901.71 h25 r90
  text "3P3VAUX2" at 5992.19,827.71 h25
  text "DGND" at 5794.19,753.71 h25
  text "VD1P1_ADC2" at 2576,747 h25
  text "TMSTP2-" at 1943.68,626.9 h30
  text "TMSTP2+" at 1544.68,623.9 h30
  text "VEE_LMH5401" at 650.24,492.3 h30 r90
  text "VEE_LMH6401" at 991.27,484.57 h30 r90
  text "DGND" at 5870,94 h25
  text "DGND" at 1631,83 h25
  text "TOP OVERLAY" at -2293.76,-2323.68 h50
Bottom Overlay:
  circle w6: c2334.48,9151 r8.31
  circle w6: c2335.24,7299.2 r8.31
  circle w6: c2339.42,953.23 r8.31
  circle w6: c2337.48,2805.38 r8.31
  lines w6: 1371.77,5732.32 1398.77,5732.32 ; 2109,2131 2208,2131 ; 2125.26,1921.8 2135.26,1921.8 ; 2127.08,8314.9 2130.08,8314.9 ; 2132.08,8241.9 2143.08,8252.9 ; 2134,8479 2203,8479 ; 2278.08,8255.9 2278.08,8266.9 2330.08,8266.9 2330.08,8414.9 2343.08,8414.9 ; 2279.08,8189.9 2279.08,8175.9 2300.08,8154.9 2300.08,8064.9 2554.08,8064.9 2554.08,8375.9 2876.08,8375.9 2876.08,7874.9 3255.08,7874.9 3255.08,8553.9 2701.08,8553.9 2562.08,8414.9 2339.08,8414.9 ; 2282.26,1911.8 2282.26,1923.8 2331.26,1923.8 2331.26,2068.8 2373.26,2068.8 2561.26,2068.8 2833.26,2340.8 3391.26,2340.8 3391.26,1646.8 2909.26,1646.8 2909.26,2023.8 2824.26,2023.8 2599.26,2023.8 2554.26,1978.8 2554.26,1721.8 2306.26,1721.8 2306.26,1785.8 2283.26,1808.8 2283.26,1843.8 ; 2518.08,8386.9 2558.08,8386.9 2604.08,8432.9 2908.08,8432.9 2926.08,8432.9 ; 2589.26,2049.8 2624.26,2084.8 2955.26,2084.8 ; 3153.57,4091.16 3177.57,4091.16 ; 4658,5177 4658,5572 4802,5572 4802,5214 ; 4671.58,5020.04 4671.58,4751.42 4798.58,4751.42 4798.58,5115.58 ; 4733,5216 4733,5248 ; 5043,9875 5043.05,9875.05 5056.18,9875.05 ; 1398.77,5732.32 1398.77,5729.32 1391.77,5722.32 1391.77,5739.32 1398.77,5732.32 ; 2926.08,8432.9 2917.08,8441.9 2917.08,8423.9 2926.08,8432.9 ; 2955.26,2084.8 2946.26,2093.8 2946.26,2075.8 2955.26,2084.8 ; 3177.57,4091.16 3170.57,4084.16 3170.57,4098.16 3177.57,4091.16 ; 4733,5248 4733,5247 4725,5239 4742,5239 4733,5248 ; 2138.72,7316.2 2138.72,7704.2 2528.72,7704.2 2528.72,7316.2 2138.72,7316.2 ; 2141,8746 2141,9134 2531,9134 2531,8746 2141,8746 ; 2142.91,970.23 2142.91,1358.23 2532.91,1358.23 2532.91,970.23 2142.91,970.23 ; 2143.99,2400.38 2533.99,2400.38 2533.99,2788.38 2143.99,2788.38 2143.99,2400.38
  text "BOTTOM OVERLAY" at -2179.53,-2337.19 h50
Top Paste:
  text "TOP PASTE" at -2293.76,-2323.68 h60
Bottom Paste:
  text "BOTTOM PASTE" at -2293.76,-2323.68 h60
Top Solder:
  text "TOP SOLDER" at -2293.76,-2323.68 h60
Bottom Solder:
  text "BOTTOM SOLDER" at -2293.76,-2323.68 h60
Drill Guide:
  text ".Layer_Name" at -2293.76,-2323.68 h60
M1 Board Outline:
  the board outline again, w10
M2 Board Dimensions:
  rectangle: -2746.26,-1875.69 -2371.26,-1750.69
  rectangle: -2871.26,-1750.69 -2746.26,-1625.69
  lines w7: -2871.26,-1750.69 -1871.26,-1750.69 ; -2746.26,-1875.69 -2746.26,-1625.69 ; -2621.26,-1875.69 -2621.26,-1625.69 ; -2371.26,-1875.69 -2371.26,-1625.69 ; -2121.26,-1875.69 -2121.26,-1625.69 ; -2871.26,-1875.69 -2871.26,-1625.69 -1871.26,-1625.69 -1871.26,-1875.69 -2871.26,-1875.69
  lines w10: -2871.26,-1940.69 -2871.26,-1920.69 ; -2811.26,-1950.69 -2871.26,-1930.69 ; -2811.26,-1910.69 -2871.26,-1930.69 ; -2647.17,-1930.69 -2871.26,-1930.69 ; -2095.34,-1930.69 -1871.26,-1930.69 ; -1931.26,-1950.69 -1871.26,-1930.69 ; -1931.26,-1910.69 -1871.26,-1930.69 ; -1871.26,-1940.69 -1871.26,-1920.69
  text "1000 (mil)" at -2637.17,-1966.68 h60
M3 3D STEP Top:
  text ".Layer_Name" at -2293.76,-2323.68 h60
M4 3D STEP Bottom:
  text ".Layer_Name" at -2293.76,-2323.68 h60
M5 Assembly Top:
  circle w6: c5956,6011.36 r12.72
  circle w6: c3713,4741 r12.65
  circle w6: c3611,4743 r12.65
  circle w6: c3513,4741 r12.65
  circle w6: c431,10797 r12.65
  circle w6: c1251,10791 r12.65
  circle w6: c1980,10793 r12.65
  circle w6: c2855,10789 r12.65
  circle w6: c3696,10789 r12.65
  circle w6: c5739,10995 r26
  circle w6: c5490,10661 r19.42
  circle w6: c6152,9428 r8
  circle w6: c6811,10213 r19.31
  circle w6: c6113,10107 r7.62
  circle w6: c5825,10146 r15.52
  circle w6: c5258,10379 r17.72
  circle w6: c5155,10210 r6.08
  circle w6: c4453,9540 r16.49
  circle w6: c4355,9375 r24.52
  circle w6: c1471,8650.67 r6.74
  circle w6: c1473,2304.31 r8.31
  circle w6: c1471,7228.54 r6.62
  circle w6: c1470,885 r5.1
  lines w6: 2893,4863 2780,4863 2780,5069 2896,5069 ; 2895,4968 2871,4968 ; 4954,4698 4954,4732 ; 5036,4843 5036,4826.28 5047.75,4814.53 5061,4801.28 5061,4698 5093,4666 5093,4438 4863,4438 4863,4937 5037,4937 5037,4925 ; 5235,4834 5206,4805 ; 2871,4968 2879,4976 2879,4959 2871,4967 2871,4968 ; 4954,4732 4947,4725 4962,4725 4955,4732 4954,4732 ; 5206,4805 5206,4818 5219,4805 5206,4805 ; 5071,4701 5113,4659 5192,4738 5281,4827 5353,4827 5478,4952 5450,4980 5379,5051 5087,4759 5071,4743 5071,4701
  lines w10: -3162.76,-2395.36 3437.24,-2395.36 ; -3162.76,-2192.02 3439.24,-2192.02 ; -3162.76,-1988.69 -3162.76,-2598.69 842.24,-2598.69 3439.24,-2598.69 3439.24,-1988.69 -3162.26,-1988.69 -3162.26,-2598.69 -1586.76,-2598.69 ; -697.76,-2598.69 -697.76,-1988.69 ; 569.24,-2192.02 569.24,-1988.69 ; 1409.24,-2192.02 1409.24,-1988.69 ; 2031.24,-2605.19 2031.24,-2402.36
  text "A" at 4798,10056 h20
  text "K" at 4738,10055 h20
  text "U74" at 5214,4625 h20 r45
  text "COMPONENTS MARKED 'DNP' SHOULD NOT BE POPULATED." at -1717.26,-1783.69 h20
  text "ASSEMBLY VARIANT:" at -1717.76,-1899.19 h20
  text ".VariantName" at -681.76,-1899.19 h20
  text "E2" at 1004.47,-2114.19 h20
  text "PCB VIEWED FROM TOP SIDE" at -3099.26,-2120.86 h20
  text "BOARD #:" at -622.76,-2120.86 h20
  text "TIDA-01022" at -77.26,-2120.86 h20
  text "REV:" at 767.24,-2120.86 h20
  text "SVN REV:" at 1605.24,-2120.86 h20
  text "ASSEMBLY TOP" at -2287.53,-2318.19 h20
  text "TID #:" at -623.76,-2318.86 h20
  text "01022" at -284.32,-2320.1 h20
  text "LAYER NAME =" at -3099.26,-2323.68 h20
  text "PLOT NAME =" at -3099.26,-2529.53 h20
  text ".plot_File_Name" at -2293.76,-2529.53 h20
  text "GENERATED    :" at -620.76,-2529.53 h20
  text "03/05/2017" at 248.74,-2529.53 h20
  text "12:12:36 PM" at 977.74,-2529.53 h20
  text "TEXAS INSTRUMENTS" at 2242.24,-2529.53 h20
M6 Assembly Bottom:
  circle w6: c5942,3745.69 r5.78
  circle w6: c5944,3479.41 r4.52
  circle w6: c4165,5848 r6.71
  lines w6: 2280,8184 2280,8139 2321,8139 ; 2286,8274 2286,8364 2640,8364 2730,8454 3043,8454 3043,8099.87 2646.42,8099.87 ; 2288,1936 2288,2022 2689,2022 2755,2088 3152,2088 3152,1806 3152,1675 2831,1675 2752.13,1753.87 2649.75,1753.87 ; 2290,1831 2290,1793 2325,1793 ; 2386,1775 2398,1763 2448,1763 ; 2393.44,8130.61 2425.72,8098.32 2461.16,8098.32 ; 2524.15,8098.32 2585.82,8098.32 ; 2538,1759 2581,1759 ; 2662,8258 2705,8258 ; 2688,1880 2759,1880 ; 2705,8258 2699,8264 2699,8250 2705,8256 2705,8258 ; 2759,1880 2751,1888 2751,1872 2759,1880 ; 4025,5746 4025,5873 4187,5873 4199,5861 4199,5746 4025,5746
  lines w10: -3163.26,-2192.52 3438.74,-2192.52 ; -3161.26,-2395.86 3438.74,-2395.86 ; -1755.26,-2605.69 -1755.26,-2402.86 ; -1133.26,-2192.52 -1133.26,-1989.19 ; -293.26,-2192.52 -293.26,-1989.19 ; 973.74,-2599.19 973.74,-1989.19 ; 1862.74,-2599.19 3438.24,-2599.19 3438.24,-1989.19 -3163.26,-1989.19 -3163.26,-2599.19 -566.26,-2599.19 3438.74,-2599.19 3438.74,-1989.19
  text "T3" at 5185,4366 h20 r315
  text "COMPONENTS MARKED 'DNP' SHOULD NOT BE POPULATED." at 3231.24,-1783.19 h20
  text ".VariantName" at 2187.24,-1899.19 h20
  text "ASSEMBLY VARIANT:" at 3226.24,-1899.19 h20
  text "SVN REV:" at -1329.26,-2121.36 h20
  text "REV:" at -491.26,-2121.36 h20
  text "TIDA-01022" at 353.24,-2121.36 h20
  text "BOARD #:" at 898.74,-2121.36 h20
  text "PCB VIEWED FROM BOTTOM SIDE" at 3375.24,-2121.36 h20
  text "E2" at -629.53,-2134.19 h20
  text "ASSEMBLY BOTTOM" at 1901.68,-2314.1 h20
  text "LAYER NAME =" at 3193.61,-2316.68 h20
  text "TID #:" at 921.11,-2325.86 h20
  text "01022" at 581.68,-2327.1 h20
  text "TEXAS INSTRUMENTS" at -1966.26,-2530.03 h20
  text "12:12:36 PM" at -701.76,-2530.03 h20
  text "03/05/2017" at 27.24,-2530.03 h20
  text "GENERATED    :" at 896.74,-2530.03 h20
  text ".plot_File_Name" at 2569.74,-2530.03 h20
  text "PLOT NAME =" at 3375.24,-2530.03 h20
M9 Title Sheet:
  drawing of 64 lines, arcs and shapes, not listed
  text "1" at -1987.2,15167.81 h70
  text "2" at 508.46,15167.81 h70
  text "3" at 2997.81,15167.81 h70
  text "4" at 5504.48,15167.81 h70
  text "5" at 8003.46,15167.81 h70
  text "6" at 10508.46,15167.81 h70
  text "A" at 16491.46,5429.81 h70
  text "A" at -3287.26,5428.31 h70
  text "B" at 16491.46,3049.81 h70
  text "B" at -3287.26,3048.31 h70
  text "C" at 16491.46,674.81 h70
  text "C" at -3287.26,673.31 h70
  text ".PRJ_Title" at 13501.46,-1319.52 h70
  text "DESIGNED FOR:" at 13451.46,-1487.19 h45
  text ".PRJ_Customer" at 13501.46,-1627.19 h70
  text "D" at 16491.46,-1695.19 h70
  text "D" at -3287.26,-1696.69 h70
  text "FILE NAME:" at 13451.46,-1787.19 h45
  text ".PCB_File_Name_No_Path" at 13501.46,-1907.19 h70
  text "Texas Instruments (TI) and/or its licensors do not warrant the accuracy or completeness of this specification" at 3503.24,-2070.53 h45
  text "ENGINEER:" at 13451.46,-2077.19 h45
  text "LAYOUT BY:" at 14956.46,-2077.19 h45
  text "or any information contained therein. TI and/or its licensors do not warrant that this design will meet" at 3458.26,-2183.2 h45
  text ".PRJ_Engineer" at 13501.46,-2232.18 h70
  text ".PCB_Layout" at 15006.96,-2232.18 h70
  text "the specifications, will be suitable for your application or fit for any particular purpose, or will operate in" at 3458.26,-2295.86 h45
  text "ALTIUM DESIGNER VERSION:" at 14956.46,-2387.19 h45
  text "an implementation. TI and/or its licensors do not warrant that the design is production worthy. You should" at 3458.26,-2408.53 h45
  text ".print_Scale" at 13501.46,-2520.52 h70
  text ".Application_BuildNumber" at 15006.96,-2520.52 h70
  text "completely validate and test your design implementation to confirm the system functionality for your application." at 3503.24,-2521.19 h45
  text "6" at 15343.46,-2727.19 h70
  text "1" at -2130.92,-2728.69 h70
  text "2" at 364.74,-2728.69 h70
  text "3" at 2854.09,-2728.69 h70
  text "4" at 5360.76,-2728.69 h70
  text "5" at 7859.74,-2728.69 h70
M10 Fab Notes:
  drawing of 244 lines, arcs and shapes, not listed
  text "DESIGN INFORMATION" at 14488.98,5346.31 h60
  text "(REFER ALSO ARRAY/PANEL PROFILING INFORMATION)" at 14127.42,5184.59 h60
  text "BOARD SIZE" at 13441.42,5180.31 h60
  text "296MM" at 14589.18,5056.31 h60
  text "X" at 14409.42,5052.49 h60
  text "176MM" at 13844.18,5046.31 h60
  text "Number of Layers :" at 13844.42,4855.31 h60
  text "12" at 14939.24,4845.31 h60
  text "MIN. TRACK WIDTH:" at 13844.42,4716.31 h60
  text "MIL" at 15095.42,4716.31 h60
  text "3.5" at 14916.72,4715.09 h60
  text "5" at 14875.18,4586.31 h60
  text "MIN. CLEARANCE:" at 13844.42,4584.31 h60
  text "MIL" at 15095.42,4584.31 h60
  text "16" at 14894.68,4459.9 h60
  text "MIN. VIA PAD SIZE:" at 13844.42,4452.31 h60
  text "MIL" at 15095.42,4452.31 h60
  text "4 MIL" at 14539.42,4310.6 h60
  text "MINIMUM ANNULAR RING" at 13515.19,4306.31 h60
  text "EXTERNAL" at 15352.18,4306.31 h60
  text "PER" at 13715.19,4188.31 h60
  text "IPC-D-275 CLASS 2 LEVEL C" at 13935.19,4188.31 h60
  text "+/-" at 15030.96,4075.31 h60
  text "MIL, HOLES" at 15423.42,4076.02 h60
  text "+/-" at 15884.96,4075.31 h60
  text "5" at 15291.17,4070.31 h60
  text "3" at 16124.17,4070.31 h60
  text "REGISTRATION TOLERANCES:" at 13515.19,4070.31 h60
  text "METAL" at 14714.96,4070.31 h60
  text "MIL" at 16240.42,4070.31 h60
  text "MATERIAL:" at 13440.42,3860.85 h60
  text "R-5670K AND R-5775K" at 15679.68,3722.9 h40
  text "FR-4 High Tg" at 14426.87,3720.52 h60
  text "X" at 15151.68,3718.9 h60
  text "FR-408" at 13861.43,3711.95 h60
  text "OTHER" at 15349.42,3711.95 h60
  text "63 MIL (1.6mm) +/-10%" at 14181.53,3549.23 h60
  text "THICKNESS:" at 13515.19,3544.95 h60
  text "X" at 14053.36,3544.95 h60
  text "OTHER" at 15466.42,3544.95 h60
  text "TOLERANCE:" at 13515.19,3386.95 h60
  text "X" at 14354.5,3386.95 h60
  text "ANSI IPC-6012 TYPE 3 CLASS 2" at 14541.44,3386.95 h60
  text "OTHER +/-" at 14541.42,3230.95 h60
  text "BOW & TWIST:" at 13515.19,3073.95 h60
  text "X" at 14354.5,3073.95 h60
  text "ANSI IPC-6012 TYPE 3 CLASS 2" at 14541.44,3073.95 h60
  text "OTHER +/-" at 14541.42,2915.44 h60
  text "COPPER THICKNESS (FINISHED):" at 13440.42,2779.95 h60
  text "1.4MIL (1oz)" at 14320.42,2627.23 h60
  text "2MIL (1.4oz)" at 15087.42,2627.23 h60
  text "2.8MIL (2oz)" at 15814.42,2627.23 h60
  text "OUTER:" at 13797.42,2622.95 h60
  text "X" at 14191.96,2622.31 h60
  text "N/A" at 15813.96,2470.59 h60
  text "0.6MIL (1/2oz)" at 14320.42,2470.23 h60
  text "2.8MIL (2oz)" at 15087.42,2470.23 h60
  text "INNER SIGNAL:" at 13508.34,2465.95 h60
  text "X" at 14191.96,2462.31 h60
  text "DRILLING:" at 13440.42,2326.95 h60
  text "REFERENCE:" at 13515.19,2209.95 h60
  text "X" at 14163.42,2209.95 h60
  text "AS SHOWN" at 14350.42,2209.95 h60
  text "X" at 15064.42,2209.95 h60
  text "NC_DRILL FILES" at 15201.42,2209.95 h60
  text "PTH MIN COPPER THICKNESS:" at 13515.19,2051.95 h60
  text "X" at 14865.42,2051.95 h60
  text "1MIL" at 15002.42,2051.95 h60
  text "OTHER" at 15499.42,2051.95 h60
  text "BOARD FINISH:" at 13440.42,1892.95 h60
  text "SILKSCREEN:" at 13595.65,1774.95 h60
  text "X" at 14544.42,1774.95 h60
  text "TOP" at 14670.42,1774.95 h60
  text "X" at 15054.42,1774.95 h60
  text "BOTTOM" at 15181.42,1774.95 h60
  text "SILKSCREEN COLOR:" at 13595.65,1607.95 h60
  text "X" at 14543.38,1607.95 h60
  text "WHITE" at 14670.42,1607.95 h60
  text "OTHER" at 15181.42,1607.95 h60
  text "SOLDER RESIST COLOR:" at 13595.65,1437.95 h60
  text "X" at 14163.39,1278.75 h60
  text "GREEN" at 14290.42,1278.75 h60
  text "BLUE" at 14881.42,1278.75 h60
  text "OTHER" at 15419.42,1278.75 h60
  text "IMMERSION GOLD (ENIG)" at 14501.42,1090.23 h60
  text "ENEPIG" at 15838.96,1086.95 h60
  text "SURFACE FINISH:" at 13440.42,1085.95 h60
  text "X" at 14314.48,1085.95 h60
  text "IMPEDANCE TABLE:-" at 7683.42,1066.9 h60
  text "IMM. TIN/SILVER OR EQUIV" at 13769.96,928.95 h60
  text "OTHER" at 15201.42,928.95 h60
  text "ARRAY/PANEL:" at 13440.42,749.95 h60
  text "CUT AND TRIM PER MECH LAYER 1" at 14501.42,745.66 h60
  text "N.C. ROUTE" at 14501.42,593.95 h60
  text "X" at 15180.42,593.95 h60
  text "V. SCORE" at 15367.42,593.95 h60
  text "100 OHM DIFF" at 10810.68,588.9 h50
  text "Layer" at 7781.68,587.9 h50
  text "100 OHM DIFF" at 9956.68,583.9 h50
  text "50 OHM SE" at 8380.68,543.9 h50
  text "90 OHM DIFF" at 8972.68,540.9 h50
  text "REFERENCE" at 11595.42,521.9 h50
  text "LOOSELY COUPLED" at 10751.68,512.9 h50
  text "TIGHTLY COUPLED" at 9897.68,507.9 h50
  text "CERTIFICATION:" at 13440.42,456.95 h60
  text "MATERIALS AND WORKMANSHIP FOR ALL PCBS" at 14165.42,456.95 h60
  text "Layer" at 11678.42,414.9 h50
  text "WIDTH/SPACING" at 8978.68,391.9 h50
  text "WIDTH/SPACING" at 10816.68,387.9 h50
  text "TRACE WIDTH" at 8237.68,383.9 h50
  text "WIDTH/SPACING" at 9962.68,382.9 h50
  text "TO MEET OR EXCEED THE REQUIREMENTS OF:" at 14165.42,358.95 h60
  text "(MILS)" at 9112.68,285.9 h50
  text "(MILS)" at 10950.68,281.9 h50
  text "(MILS)" at 8349.68,277.9 h50
  text "(MILS)" at 10096.68,276.9 h50
  text "X" at 13791.93,222.44 h60
  text "ANSI IPC-A-600F CLASS ->" at 13930.93,222.44 h60
  text "X" at 15569.98,222.44 h60
  text "2" at 15688.93,222.44 h60
  text "1" at 15373.93,220.95 h60
  text "3" at 16042.93,220.95 h60
  text "+/-10%" at 9103.68,198.9 h50
  text "+/-10%" at 10941.68,194.9 h50
  text "+/-10%" at 8340.68,190.9 h50
  text "+/-10%" at 10087.68,189.9 h50
  text "L2_GND" at 11675.68,75.9 h50
  text "L1_Top" at 7779.83,74.9 h50
  text "8.2mil trace/" at 9091.42,72.9 h50
  text "6mil trace/" at 9982.42,67.9 h50
  text "X" at 13793.98,62.95 h60
  text "UL 94V-0" at 13930.93,62.95 h60
  text "X" at 14605.98,62.95 h60
  text "RoHS" at 14742.93,62.95 h60
  text "OTHER" at 15387.33,62.95 h60
  text "PER ORDER" at 15784.39,62.95 h60
  text "10mil trace/" at 10904.42,60.9 h50
  text "11mils" at 8336.68,23.9 h50
  text "Layer" at 11679.68,-2.1 h50
  text "6mil space" at 9093.42,-10.1 h50
  text "Layer" at 7788.68,-15.1 h50
  text "5mil space" at 9984.42,-15.1 h50
  text "18mil space" at 10906.42,-22.1 h50
  text "ADDITIONAL REQUIREMENTS:" at 13440.42,-78.05 h60
  text "X" at 15424.26,-78.58 h60
  text "VIA TENTING:" at 14657.96,-78.69 h60
  text "YES" at 15207.63,-87.77 h60
  text "NO" at 15572.44,-93 h60
  text "L4_SIGNAL" at 7763.94,-147.1 h50
  text "4.9mil trace/" at 9973.42,-161.1 h50
  text "L5_GND" at 11670.68,-163.1 h50
  text "MICROSECTION:" at 13515.19,-193.05 h60
  text "YES" at 14420.93,-193.05 h60
  text "X" at 15892.68,-195.1 h60
  text "NIL" at 11039.68,-199.1 h50
  text "NIL" at 9199.68,-202.1 h50
  text "IMPEDANCE CONTROL:" at 14683.96,-202.69 h60
  text "YES" at 15667.96,-203.69 h60
  text "5.5mils" at 8328.68,-208.1 h50
  text "NO" at 16043.44,-221 h60
  text "Layer1" at 7817.68,-231.1 h50
  text "Layer" at 11674.68,-241.1 h50
  text "7.1mil space" at 9975.42,-244.1 h50
  text "REQUIRED" at 15282.42,-349.2 h60
  text "BARE BOARD ELEC. TEST:" at 13515.19,-352.05 h60
  text "NONE" at 14820.93,-352.05 h60
  text "X" at 15155.42,-352.05 h60
  text "PER ORDER" at 15874.42,-352.05 h60
  text "L10_SIGNAL" at 7716.94,-373.1 h50
  text "L11_GND" at 11696.68,-377.1 h50
  text "6.3mil trace/" at 10887.42,-379.1 h50
  text "5.5mil trace/" at 9968.42,-381.1 h50
  text "NIL" at 9197.68,-422.1 h50
  text "6.5mils" at 8321.68,-425.1 h50
  text "Layer" at 11700.68,-455.1 h50
  text "Layer2" at 7817.68,-458.1 h50
  text "20.1mil space" at 10889.42,-462.1 h50
  text "6.5mil space" at 9970.42,-464.1 h50
  text "MANUFACTURER'S UL:" at 13515.19,-509.05 h60
  text "RAIL" at 14680.93,-513.34 h60
  text "METAL" at 15172.74,-513.34 h60
  text "SILK" at 15684.42,-513.34 h60
  text "X" at 15547.96,-513.69 h60
  text "L12_BOTTOM" at 7719.83,-597.1 h50
  text "10mil trace/" at 10887.42,-602.1 h50
  text "L11_GND" at 11693.68,-611.1 h50
  text "6mil trace/" at 9966.42,-613.1 h50
  text "11mils" at 8309.68,-646.1 h50
  text "NIL" at 9201.68,-673.1 h50
  text "Layer" at 7816.68,-684.1 h50
  text "18mil space" at 10889.42,-685.1 h50
  text "Layer" at 11697.68,-689.1 h50
  text "5mil space" at 9968.42,-696.1 h50
M11 Gerber Information:
  lines w10: -3162.76,-2395.36 3437.24,-2395.36 ; -3162.76,-2192.02 3439.24,-2192.02 ; -3162.76,-1988.69 -3162.76,-2598.69 842.24,-2598.69 3439.24,-2598.69 3439.24,-1988.69 -3162.26,-1988.69 -3162.26,-2598.69 -1586.76,-2598.69 ; -697.76,-2598.69 -697.76,-1988.69 ; 569.24,-2192.02 569.24,-1988.69 ; 1409.24,-2192.02 1409.24,-1988.69 ; 2031.24,-2605.19 2031.24,-2402.36
  text "E2" at 1060.47,-2116.19 h40
  text "ALL ARTWORK VIEWED FROM TOP SIDE" at -3099.26,-2120.86 h60
  text "BOARD #:" at -622.76,-2120.86 h60
  text "TIDA-01022" at -77.26,-2120.86 h60
  text "REV:" at 767.24,-2120.86 h60
  text "SVN REV:" at 1605.24,-2120.86 h60
  text "TID #:" at -623.76,-2320.86 h60
  text "01022" at -284.32,-2322.1 h60
  text "LAYER NAME =" at -3097.26,-2323.68 h60
  text "PLOT NAME =" at -3099.26,-2529.53 h60
  text ".plot_File_Name" at -2293.76,-2529.53 h60
  text "GENERATED    :" at -620.76,-2529.53 h60
  text "'.Print_Date'" at 248.74,-2529.53 h60
  text "'.Print_Time'" at 977.74,-2529.53 h60
  text "TEXAS INSTRUMENTS" at 2242.24,-2529.53 h60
